VERSION 5.8 ;
BUSBITCHARS "[]" ;
DIVIDERCHAR "/" ;
UNITS
    DATABASE MICRONS 1000 ;
END UNITS

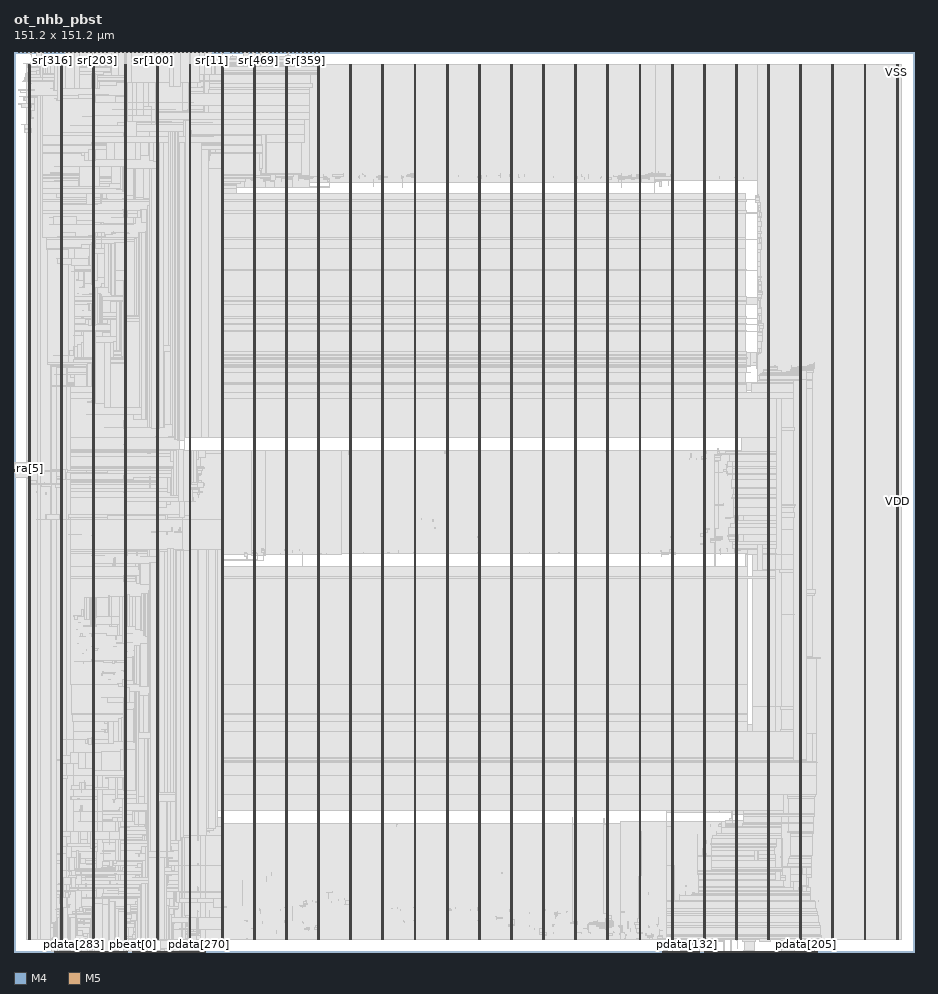
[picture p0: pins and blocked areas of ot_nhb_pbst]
MACRO ot_nhb_pbst
  FOREIGN ot_nhb_pbst 0 0 ;
  CLASS BLOCK ;
  SIZE 151.2 BY 151.2 ;
  PIN clk
    DIRECTION INPUT ;
    USE SIGNAL ;
    PORT
      LAYER M4 ;
        RECT  0 80.592 0.084 80.616 ;
    END
  END clk
  PIN pbeat[0]
    DIRECTION INPUT ;
    USE SIGNAL ;
    PORT
      LAYER M5 ;
        RECT  19.92 0 19.944 0.084 ;
    END
  END pbeat[0]
  PIN pbeat[1]
    DIRECTION INPUT ;
    USE SIGNAL ;
    PORT
      LAYER M5 ;
        RECT  20.016 0 20.04 0.084 ;
    END
  END pbeat[1]
  PIN pbeat[2]
    DIRECTION INPUT ;
    USE SIGNAL ;
    PORT
      LAYER M5 ;
        RECT  20.112 0 20.136 0.084 ;
    END
  END pbeat[2]
  PIN pbeat[3]
    DIRECTION INPUT ;
    USE SIGNAL ;
    PORT
      LAYER M5 ;
        RECT  20.208 0 20.232 0.084 ;
    END
  END pbeat[3]
  PIN pbeat[4]
    DIRECTION INPUT ;
    USE SIGNAL ;
    PORT
      LAYER M5 ;
        RECT  20.304 0 20.328 0.084 ;
    END
  END pbeat[4]
  PIN pbeat[5]
    DIRECTION INPUT ;
    USE SIGNAL ;
    PORT
      LAYER M5 ;
        RECT  20.4 0 20.424 0.084 ;
    END
  END pbeat[5]
  PIN pdata[0]
    DIRECTION INPUT ;
    USE SIGNAL ;
    PORT
      LAYER M5 ;
        RECT  20.496 0 20.52 0.084 ;
    END
  END pdata[0]
  PIN pdata[100]
    DIRECTION INPUT ;
    USE SIGNAL ;
    PORT
      LAYER M5 ;
        RECT  23.952 0 23.976 0.084 ;
    END
  END pdata[100]
  PIN pdata[101]
    DIRECTION INPUT ;
    USE SIGNAL ;
    PORT
      LAYER M5 ;
        RECT  24.048 0 24.072 0.084 ;
    END
  END pdata[101]
  PIN pdata[102]
    DIRECTION INPUT ;
    USE SIGNAL ;
    PORT
      LAYER M5 ;
        RECT  24.144 0 24.168 0.084 ;
    END
  END pdata[102]
  PIN pdata[103]
    DIRECTION INPUT ;
    USE SIGNAL ;
    PORT
      LAYER M5 ;
        RECT  24.24 0 24.264 0.084 ;
    END
  END pdata[103]
  PIN pdata[104]
    DIRECTION INPUT ;
    USE SIGNAL ;
    PORT
      LAYER M5 ;
        RECT  24.336 0 24.36 0.084 ;
    END
  END pdata[104]
  PIN pdata[105]
    DIRECTION INPUT ;
    USE SIGNAL ;
    PORT
      LAYER M5 ;
        RECT  24.432 0 24.456 0.084 ;
    END
  END pdata[105]
  PIN pdata[106]
    DIRECTION INPUT ;
    USE SIGNAL ;
    PORT
      LAYER M5 ;
        RECT  24.528 0 24.552 0.084 ;
    END
  END pdata[106]
  PIN pdata[107]
    DIRECTION INPUT ;
    USE SIGNAL ;
    PORT
      LAYER M5 ;
        RECT  24.624 0 24.648 0.084 ;
    END
  END pdata[107]
  PIN pdata[108]
    DIRECTION INPUT ;
    USE SIGNAL ;
    PORT
      LAYER M5 ;
        RECT  24.72 0 24.744 0.084 ;
    END
  END pdata[108]
  PIN pdata[109]
    DIRECTION INPUT ;
    USE SIGNAL ;
    PORT
      LAYER M5 ;
        RECT  24.816 0 24.84 0.084 ;
    END
  END pdata[109]
  PIN pdata[10]
    DIRECTION INPUT ;
    USE SIGNAL ;
    PORT
      LAYER M5 ;
        RECT  21.456 0 21.48 0.084 ;
    END
  END pdata[10]
  PIN pdata[110]
    DIRECTION INPUT ;
    USE SIGNAL ;
    PORT
      LAYER M5 ;
        RECT  24.912 0 24.936 0.084 ;
    END
  END pdata[110]
  PIN pdata[111]
    DIRECTION INPUT ;
    USE SIGNAL ;
    PORT
      LAYER M5 ;
        RECT  25.008 0 25.032 0.084 ;
    END
  END pdata[111]
  PIN pdata[112]
    DIRECTION INPUT ;
    USE SIGNAL ;
    PORT
      LAYER M5 ;
        RECT  25.104 0 25.128 0.084 ;
    END
  END pdata[112]
  PIN pdata[113]
    DIRECTION INPUT ;
    USE SIGNAL ;
    PORT
      LAYER M5 ;
        RECT  25.2 0 25.224 0.084 ;
    END
  END pdata[113]
  PIN pdata[114]
    DIRECTION INPUT ;
    USE SIGNAL ;
    PORT
      LAYER M5 ;
        RECT  25.296 0 25.32 0.084 ;
    END
  END pdata[114]
  PIN pdata[115]
    DIRECTION INPUT ;
    USE SIGNAL ;
    PORT
      LAYER M5 ;
        RECT  25.392 0 25.416 0.084 ;
    END
  END pdata[115]
  PIN pdata[116]
    DIRECTION INPUT ;
    USE SIGNAL ;
    PORT
      LAYER M5 ;
        RECT  25.488 0 25.512 0.084 ;
    END
  END pdata[116]
  PIN pdata[117]
    DIRECTION INPUT ;
    USE SIGNAL ;
    PORT
      LAYER M5 ;
        RECT  25.584 0 25.608 0.084 ;
    END
  END pdata[117]
  PIN pdata[118]
    DIRECTION INPUT ;
    USE SIGNAL ;
    PORT
      LAYER M5 ;
        RECT  25.68 0 25.704 0.084 ;
    END
  END pdata[118]
  PIN pdata[119]
    DIRECTION INPUT ;
    USE SIGNAL ;
    PORT
      LAYER M5 ;
        RECT  25.776 0 25.8 0.084 ;
    END
  END pdata[119]
  PIN pdata[11]
    DIRECTION INPUT ;
    USE SIGNAL ;
    PORT
      LAYER M5 ;
        RECT  21.552 0 21.576 0.084 ;
    END
  END pdata[11]
  PIN pdata[120]
    DIRECTION INPUT ;
    USE SIGNAL ;
    PORT
      LAYER M5 ;
        RECT  25.872 0 25.896 0.084 ;
    END
  END pdata[120]
  PIN pdata[121]
    DIRECTION INPUT ;
    USE SIGNAL ;
    PORT
      LAYER M5 ;
        RECT  25.968 0 25.992 0.084 ;
    END
  END pdata[121]
  PIN pdata[122]
    DIRECTION INPUT ;
    USE SIGNAL ;
    PORT
      LAYER M5 ;
        RECT  112.08 0 112.104 0.084 ;
    END
  END pdata[122]
  PIN pdata[123]
    DIRECTION INPUT ;
    USE SIGNAL ;
    PORT
      LAYER M5 ;
        RECT  112.176 0 112.2 0.084 ;
    END
  END pdata[123]
  PIN pdata[124]
    DIRECTION INPUT ;
    USE SIGNAL ;
    PORT
      LAYER M5 ;
        RECT  112.272 0 112.296 0.084 ;
    END
  END pdata[124]
  PIN pdata[125]
    DIRECTION INPUT ;
    USE SIGNAL ;
    PORT
      LAYER M5 ;
        RECT  112.368 0 112.392 0.084 ;
    END
  END pdata[125]
  PIN pdata[126]
    DIRECTION INPUT ;
    USE SIGNAL ;
    PORT
      LAYER M5 ;
        RECT  112.464 0 112.488 0.084 ;
    END
  END pdata[126]
  PIN pdata[127]
    DIRECTION INPUT ;
    USE SIGNAL ;
    PORT
      LAYER M5 ;
        RECT  112.56 0 112.584 0.084 ;
    END
  END pdata[127]
  PIN pdata[128]
    DIRECTION INPUT ;
    USE SIGNAL ;
    PORT
      LAYER M5 ;
        RECT  112.656 0 112.68 0.084 ;
    END
  END pdata[128]
  PIN pdata[129]
    DIRECTION INPUT ;
    USE SIGNAL ;
    PORT
      LAYER M5 ;
        RECT  112.752 0 112.776 0.084 ;
    END
  END pdata[129]
  PIN pdata[12]
    DIRECTION INPUT ;
    USE SIGNAL ;
    PORT
      LAYER M5 ;
        RECT  21.648 0 21.672 0.084 ;
    END
  END pdata[12]
  PIN pdata[130]
    DIRECTION INPUT ;
    USE SIGNAL ;
    PORT
      LAYER M5 ;
        RECT  112.848 0 112.872 0.084 ;
    END
  END pdata[130]
  PIN pdata[131]
    DIRECTION INPUT ;
    USE SIGNAL ;
    PORT
      LAYER M5 ;
        RECT  112.944 0 112.968 0.084 ;
    END
  END pdata[131]
  PIN pdata[132]
    DIRECTION INPUT ;
    USE SIGNAL ;
    PORT
      LAYER M5 ;
        RECT  113.04 0 113.064 0.084 ;
    END
  END pdata[132]
  PIN pdata[133]
    DIRECTION INPUT ;
    USE SIGNAL ;
    PORT
      LAYER M5 ;
        RECT  113.136 0 113.16 0.084 ;
    END
  END pdata[133]
  PIN pdata[134]
    DIRECTION INPUT ;
    USE SIGNAL ;
    PORT
      LAYER M5 ;
        RECT  113.232 0 113.256 0.084 ;
    END
  END pdata[134]
  PIN pdata[135]
    DIRECTION INPUT ;
    USE SIGNAL ;
    PORT
      LAYER M5 ;
        RECT  113.328 0 113.352 0.084 ;
    END
  END pdata[135]
  PIN pdata[136]
    DIRECTION INPUT ;
    USE SIGNAL ;
    PORT
      LAYER M5 ;
        RECT  113.424 0 113.448 0.084 ;
    END
  END pdata[136]
  PIN pdata[137]
    DIRECTION INPUT ;
    USE SIGNAL ;
    PORT
      LAYER M5 ;
        RECT  113.52 0 113.544 0.084 ;
    END
  END pdata[137]
  PIN pdata[138]
    DIRECTION INPUT ;
    USE SIGNAL ;
    PORT
      LAYER M5 ;
        RECT  113.616 0 113.64 0.084 ;
    END
  END pdata[138]
  PIN pdata[139]
    DIRECTION INPUT ;
    USE SIGNAL ;
    PORT
      LAYER M5 ;
        RECT  113.712 0 113.736 0.084 ;
    END
  END pdata[139]
  PIN pdata[13]
    DIRECTION INPUT ;
    USE SIGNAL ;
    PORT
      LAYER M5 ;
        RECT  21.744 0 21.768 0.084 ;
    END
  END pdata[13]
  PIN pdata[140]
    DIRECTION INPUT ;
    USE SIGNAL ;
    PORT
      LAYER M5 ;
        RECT  113.808 0 113.832 0.084 ;
    END
  END pdata[140]
  PIN pdata[141]
    DIRECTION INPUT ;
    USE SIGNAL ;
    PORT
      LAYER M5 ;
        RECT  113.904 0 113.928 0.084 ;
    END
  END pdata[141]
  PIN pdata[142]
    DIRECTION INPUT ;
    USE SIGNAL ;
    PORT
      LAYER M5 ;
        RECT  114 0 114.024 0.084 ;
    END
  END pdata[142]
  PIN pdata[143]
    DIRECTION INPUT ;
    USE SIGNAL ;
    PORT
      LAYER M5 ;
        RECT  114.096 0 114.12 0.084 ;
    END
  END pdata[143]
  PIN pdata[144]
    DIRECTION INPUT ;
    USE SIGNAL ;
    PORT
      LAYER M5 ;
        RECT  114.192 0 114.216 0.084 ;
    END
  END pdata[144]
  PIN pdata[145]
    DIRECTION INPUT ;
    USE SIGNAL ;
    PORT
      LAYER M5 ;
        RECT  114.288 0 114.312 0.084 ;
    END
  END pdata[145]
  PIN pdata[146]
    DIRECTION INPUT ;
    USE SIGNAL ;
    PORT
      LAYER M5 ;
        RECT  114.384 0 114.408 0.084 ;
    END
  END pdata[146]
  PIN pdata[147]
    DIRECTION INPUT ;
    USE SIGNAL ;
    PORT
      LAYER M5 ;
        RECT  114.48 0 114.504 0.084 ;
    END
  END pdata[147]
  PIN pdata[148]
    DIRECTION INPUT ;
    USE SIGNAL ;
    PORT
      LAYER M5 ;
        RECT  114.576 0 114.6 0.084 ;
    END
  END pdata[148]
  PIN pdata[149]
    DIRECTION INPUT ;
    USE SIGNAL ;
    PORT
      LAYER M5 ;
        RECT  114.672 0 114.696 0.084 ;
    END
  END pdata[149]
  PIN pdata[14]
    DIRECTION INPUT ;
    USE SIGNAL ;
    PORT
      LAYER M5 ;
        RECT  21.84 0 21.864 0.084 ;
    END
  END pdata[14]
  PIN pdata[150]
    DIRECTION INPUT ;
    USE SIGNAL ;
    PORT
      LAYER M5 ;
        RECT  114.768 0 114.792 0.084 ;
    END
  END pdata[150]
  PIN pdata[151]
    DIRECTION INPUT ;
    USE SIGNAL ;
    PORT
      LAYER M5 ;
        RECT  114.864 0 114.888 0.084 ;
    END
  END pdata[151]
  PIN pdata[152]
    DIRECTION INPUT ;
    USE SIGNAL ;
    PORT
      LAYER M5 ;
        RECT  114.96 0 114.984 0.084 ;
    END
  END pdata[152]
  PIN pdata[153]
    DIRECTION INPUT ;
    USE SIGNAL ;
    PORT
      LAYER M5 ;
        RECT  115.056 0 115.08 0.084 ;
    END
  END pdata[153]
  PIN pdata[154]
    DIRECTION INPUT ;
    USE SIGNAL ;
    PORT
      LAYER M5 ;
        RECT  118.992 0 119.016 0.084 ;
    END
  END pdata[154]
  PIN pdata[155]
    DIRECTION INPUT ;
    USE SIGNAL ;
    PORT
      LAYER M5 ;
        RECT  119.088 0 119.112 0.084 ;
    END
  END pdata[155]
  PIN pdata[156]
    DIRECTION INPUT ;
    USE SIGNAL ;
    PORT
      LAYER M5 ;
        RECT  119.184 0 119.208 0.084 ;
    END
  END pdata[156]
  PIN pdata[157]
    DIRECTION INPUT ;
    USE SIGNAL ;
    PORT
      LAYER M5 ;
        RECT  119.28 0 119.304 0.084 ;
    END
  END pdata[157]
  PIN pdata[158]
    DIRECTION INPUT ;
    USE SIGNAL ;
    PORT
      LAYER M5 ;
        RECT  119.376 0 119.4 0.084 ;
    END
  END pdata[158]
  PIN pdata[159]
    DIRECTION INPUT ;
    USE SIGNAL ;
    PORT
      LAYER M5 ;
        RECT  119.472 0 119.496 0.084 ;
    END
  END pdata[159]
  PIN pdata[15]
    DIRECTION INPUT ;
    USE SIGNAL ;
    PORT
      LAYER M5 ;
        RECT  21.936 0 21.96 0.084 ;
    END
  END pdata[15]
  PIN pdata[160]
    DIRECTION INPUT ;
    USE SIGNAL ;
    PORT
      LAYER M5 ;
        RECT  119.568 0 119.592 0.084 ;
    END
  END pdata[160]
  PIN pdata[161]
    DIRECTION INPUT ;
    USE SIGNAL ;
    PORT
      LAYER M5 ;
        RECT  119.664 0 119.688 0.084 ;
    END
  END pdata[161]
  PIN pdata[162]
    DIRECTION INPUT ;
    USE SIGNAL ;
    PORT
      LAYER M5 ;
        RECT  119.76 0 119.784 0.084 ;
    END
  END pdata[162]
  PIN pdata[163]
    DIRECTION INPUT ;
    USE SIGNAL ;
    PORT
      LAYER M5 ;
        RECT  119.856 0 119.88 0.084 ;
    END
  END pdata[163]
  PIN pdata[164]
    DIRECTION INPUT ;
    USE SIGNAL ;
    PORT
      LAYER M5 ;
        RECT  119.952 0 119.976 0.084 ;
    END
  END pdata[164]
  PIN pdata[165]
    DIRECTION INPUT ;
    USE SIGNAL ;
    PORT
      LAYER M5 ;
        RECT  120.048 0 120.072 0.084 ;
    END
  END pdata[165]
  PIN pdata[166]
    DIRECTION INPUT ;
    USE SIGNAL ;
    PORT
      LAYER M5 ;
        RECT  120.144 0 120.168 0.084 ;
    END
  END pdata[166]
  PIN pdata[167]
    DIRECTION INPUT ;
    USE SIGNAL ;
    PORT
      LAYER M5 ;
        RECT  120.24 0 120.264 0.084 ;
    END
  END pdata[167]
  PIN pdata[168]
    DIRECTION INPUT ;
    USE SIGNAL ;
    PORT
      LAYER M5 ;
        RECT  120.336 0 120.36 0.084 ;
    END
  END pdata[168]
  PIN pdata[169]
    DIRECTION INPUT ;
    USE SIGNAL ;
    PORT
      LAYER M5 ;
        RECT  120.432 0 120.456 0.084 ;
    END
  END pdata[169]
  PIN pdata[16]
    DIRECTION INPUT ;
    USE SIGNAL ;
    PORT
      LAYER M5 ;
        RECT  22.032 0 22.056 0.084 ;
    END
  END pdata[16]
  PIN pdata[170]
    DIRECTION INPUT ;
    USE SIGNAL ;
    PORT
      LAYER M5 ;
        RECT  120.528 0 120.552 0.084 ;
    END
  END pdata[170]
  PIN pdata[171]
    DIRECTION INPUT ;
    USE SIGNAL ;
    PORT
      LAYER M5 ;
        RECT  120.624 0 120.648 0.084 ;
    END
  END pdata[171]
  PIN pdata[172]
    DIRECTION INPUT ;
    USE SIGNAL ;
    PORT
      LAYER M5 ;
        RECT  120.72 0 120.744 0.084 ;
    END
  END pdata[172]
  PIN pdata[173]
    DIRECTION INPUT ;
    USE SIGNAL ;
    PORT
      LAYER M5 ;
        RECT  120.816 0 120.84 0.084 ;
    END
  END pdata[173]
  PIN pdata[174]
    DIRECTION INPUT ;
    USE SIGNAL ;
    PORT
      LAYER M5 ;
        RECT  120.912 0 120.936 0.084 ;
    END
  END pdata[174]
  PIN pdata[175]
    DIRECTION INPUT ;
    USE SIGNAL ;
    PORT
      LAYER M5 ;
        RECT  121.008 0 121.032 0.084 ;
    END
  END pdata[175]
  PIN pdata[176]
    DIRECTION INPUT ;
    USE SIGNAL ;
    PORT
      LAYER M5 ;
        RECT  121.104 0 121.128 0.084 ;
    END
  END pdata[176]
  PIN pdata[177]
    DIRECTION INPUT ;
    USE SIGNAL ;
    PORT
      LAYER M5 ;
        RECT  121.2 0 121.224 0.084 ;
    END
  END pdata[177]
  PIN pdata[178]
    DIRECTION INPUT ;
    USE SIGNAL ;
    PORT
      LAYER M5 ;
        RECT  121.296 0 121.32 0.084 ;
    END
  END pdata[178]
  PIN pdata[179]
    DIRECTION INPUT ;
    USE SIGNAL ;
    PORT
      LAYER M5 ;
        RECT  121.392 0 121.416 0.084 ;
    END
  END pdata[179]
  PIN pdata[17]
    DIRECTION INPUT ;
    USE SIGNAL ;
    PORT
      LAYER M5 ;
        RECT  22.128 0 22.152 0.084 ;
    END
  END pdata[17]
  PIN pdata[180]
    DIRECTION INPUT ;
    USE SIGNAL ;
    PORT
      LAYER M5 ;
        RECT  121.488 0 121.512 0.084 ;
    END
  END pdata[180]
  PIN pdata[181]
    DIRECTION INPUT ;
    USE SIGNAL ;
    PORT
      LAYER M5 ;
        RECT  121.584 0 121.608 0.084 ;
    END
  END pdata[181]
  PIN pdata[182]
    DIRECTION INPUT ;
    USE SIGNAL ;
    PORT
      LAYER M5 ;
        RECT  121.68 0 121.704 0.084 ;
    END
  END pdata[182]
  PIN pdata[183]
    DIRECTION INPUT ;
    USE SIGNAL ;
    PORT
      LAYER M5 ;
        RECT  121.776 0 121.8 0.084 ;
    END
  END pdata[183]
  PIN pdata[184]
    DIRECTION INPUT ;
    USE SIGNAL ;
    PORT
      LAYER M5 ;
        RECT  121.872 0 121.896 0.084 ;
    END
  END pdata[184]
  PIN pdata[185]
    DIRECTION INPUT ;
    USE SIGNAL ;
    PORT
      LAYER M5 ;
        RECT  121.968 0 121.992 0.084 ;
    END
  END pdata[185]
  PIN pdata[186]
    DIRECTION INPUT ;
    USE SIGNAL ;
    PORT
      LAYER M5 ;
        RECT  131.28 0 131.304 0.084 ;
    END
  END pdata[186]
  PIN pdata[187]
    DIRECTION INPUT ;
    USE SIGNAL ;
    PORT
      LAYER M5 ;
        RECT  131.376 0 131.4 0.084 ;
    END
  END pdata[187]
  PIN pdata[188]
    DIRECTION INPUT ;
    USE SIGNAL ;
    PORT
      LAYER M5 ;
        RECT  131.472 0 131.496 0.084 ;
    END
  END pdata[188]
  PIN pdata[189]
    DIRECTION INPUT ;
    USE SIGNAL ;
    PORT
      LAYER M5 ;
        RECT  131.568 0 131.592 0.084 ;
    END
  END pdata[189]
  PIN pdata[18]
    DIRECTION INPUT ;
    USE SIGNAL ;
    PORT
      LAYER M5 ;
        RECT  22.224 0 22.248 0.084 ;
    END
  END pdata[18]
  PIN pdata[190]
    DIRECTION INPUT ;
    USE SIGNAL ;
    PORT
      LAYER M5 ;
        RECT  131.664 0 131.688 0.084 ;
    END
  END pdata[190]
  PIN pdata[191]
    DIRECTION INPUT ;
    USE SIGNAL ;
    PORT
      LAYER M5 ;
        RECT  131.76 0 131.784 0.084 ;
    END
  END pdata[191]
  PIN pdata[192]
    DIRECTION INPUT ;
    USE SIGNAL ;
    PORT
      LAYER M5 ;
        RECT  131.856 0 131.88 0.084 ;
    END
  END pdata[192]
  PIN pdata[193]
    DIRECTION INPUT ;
    USE SIGNAL ;
    PORT
      LAYER M5 ;
        RECT  131.952 0 131.976 0.084 ;
    END
  END pdata[193]
  PIN pdata[194]
    DIRECTION INPUT ;
    USE SIGNAL ;
    PORT
      LAYER M5 ;
        RECT  132.048 0 132.072 0.084 ;
    END
  END pdata[194]
  PIN pdata[195]
    DIRECTION INPUT ;
    USE SIGNAL ;
    PORT
      LAYER M5 ;
        RECT  132.144 0 132.168 0.084 ;
    END
  END pdata[195]
  PIN pdata[196]
    DIRECTION INPUT ;
    USE SIGNAL ;
    PORT
      LAYER M5 ;
        RECT  132.24 0 132.264 0.084 ;
    END
  END pdata[196]
  PIN pdata[197]
    DIRECTION INPUT ;
    USE SIGNAL ;
    PORT
      LAYER M5 ;
        RECT  132.336 0 132.36 0.084 ;
    END
  END pdata[197]
  PIN pdata[198]
    DIRECTION INPUT ;
    USE SIGNAL ;
    PORT
      LAYER M5 ;
        RECT  132.432 0 132.456 0.084 ;
    END
  END pdata[198]
  PIN pdata[199]
    DIRECTION INPUT ;
    USE SIGNAL ;
    PORT
      LAYER M5 ;
        RECT  132.528 0 132.552 0.084 ;
    END
  END pdata[199]
  PIN pdata[19]
    DIRECTION INPUT ;
    USE SIGNAL ;
    PORT
      LAYER M5 ;
        RECT  22.32 0 22.344 0.084 ;
    END
  END pdata[19]
  PIN pdata[1]
    DIRECTION INPUT ;
    USE SIGNAL ;
    PORT
      LAYER M5 ;
        RECT  20.592 0 20.616 0.084 ;
    END
  END pdata[1]
  PIN pdata[200]
    DIRECTION INPUT ;
    USE SIGNAL ;
    PORT
      LAYER M5 ;
        RECT  132.624 0 132.648 0.084 ;
    END
  END pdata[200]
  PIN pdata[201]
    DIRECTION INPUT ;
    USE SIGNAL ;
    PORT
      LAYER M5 ;
        RECT  132.72 0 132.744 0.084 ;
    END
  END pdata[201]
  PIN pdata[202]
    DIRECTION INPUT ;
    USE SIGNAL ;
    PORT
      LAYER M5 ;
        RECT  132.816 0 132.84 0.084 ;
    END
  END pdata[202]
  PIN pdata[203]
    DIRECTION INPUT ;
    USE SIGNAL ;
    PORT
      LAYER M5 ;
        RECT  132.912 0 132.936 0.084 ;
    END
  END pdata[203]
  PIN pdata[204]
    DIRECTION INPUT ;
    USE SIGNAL ;
    PORT
      LAYER M5 ;
        RECT  133.008 0 133.032 0.084 ;
    END
  END pdata[204]
  PIN pdata[205]
    DIRECTION INPUT ;
    USE SIGNAL ;
    PORT
      LAYER M5 ;
        RECT  133.104 0 133.128 0.084 ;
    END
  END pdata[205]
  PIN pdata[206]
    DIRECTION INPUT ;
    USE SIGNAL ;
    PORT
      LAYER M5 ;
        RECT  133.2 0 133.224 0.084 ;
    END
  END pdata[206]
  PIN pdata[207]
    DIRECTION INPUT ;
    USE SIGNAL ;
    PORT
      LAYER M5 ;
        RECT  133.296 0 133.32 0.084 ;
    END
  END pdata[207]
  PIN pdata[208]
    DIRECTION INPUT ;
    USE SIGNAL ;
    PORT
      LAYER M5 ;
        RECT  133.392 0 133.416 0.084 ;
    END
  END pdata[208]
  PIN pdata[209]
    DIRECTION INPUT ;
    USE SIGNAL ;
    PORT
      LAYER M5 ;
        RECT  133.488 0 133.512 0.084 ;
    END
  END pdata[209]
  PIN pdata[20]
    DIRECTION INPUT ;
    USE SIGNAL ;
    PORT
      LAYER M5 ;
        RECT  22.416 0 22.44 0.084 ;
    END
  END pdata[20]
  PIN pdata[210]
    DIRECTION INPUT ;
    USE SIGNAL ;
    PORT
      LAYER M5 ;
        RECT  133.584 0 133.608 0.084 ;
    END
  END pdata[210]
  PIN pdata[211]
    DIRECTION INPUT ;
    USE SIGNAL ;
    PORT
      LAYER M5 ;
        RECT  133.68 0 133.704 0.084 ;
    END
  END pdata[211]
  PIN pdata[212]
    DIRECTION INPUT ;
    USE SIGNAL ;
    PORT
      LAYER M5 ;
        RECT  133.776 0 133.8 0.084 ;
    END
  END pdata[212]
  PIN pdata[213]
    DIRECTION INPUT ;
    USE SIGNAL ;
    PORT
      LAYER M5 ;
        RECT  133.872 0 133.896 0.084 ;
    END
  END pdata[213]
  PIN pdata[214]
    DIRECTION INPUT ;
    USE SIGNAL ;
    PORT
      LAYER M5 ;
        RECT  133.968 0 133.992 0.084 ;
    END
  END pdata[214]
  PIN pdata[215]
    DIRECTION INPUT ;
    USE SIGNAL ;
    PORT
      LAYER M5 ;
        RECT  134.064 0 134.088 0.084 ;
    END
  END pdata[215]
  PIN pdata[216]
    DIRECTION INPUT ;
    USE SIGNAL ;
    PORT
      LAYER M5 ;
        RECT  134.16 0 134.184 0.084 ;
    END
  END pdata[216]
  PIN pdata[217]
    DIRECTION INPUT ;
    USE SIGNAL ;
    PORT
      LAYER M5 ;
        RECT  134.256 0 134.28 0.084 ;
    END
  END pdata[217]
  PIN pdata[218]
    DIRECTION INPUT ;
    USE SIGNAL ;
    PORT
      LAYER M5 ;
        RECT  125.136 0 125.16 0.084 ;
    END
  END pdata[218]
  PIN pdata[219]
    DIRECTION INPUT ;
    USE SIGNAL ;
    PORT
      LAYER M5 ;
        RECT  125.232 0 125.256 0.084 ;
    END
  END pdata[219]
  PIN pdata[21]
    DIRECTION INPUT ;
    USE SIGNAL ;
    PORT
      LAYER M5 ;
        RECT  22.512 0 22.536 0.084 ;
    END
  END pdata[21]
  PIN pdata[220]
    DIRECTION INPUT ;
    USE SIGNAL ;
    PORT
      LAYER M5 ;
        RECT  125.328 0 125.352 0.084 ;
    END
  END pdata[220]
  PIN pdata[221]
    DIRECTION INPUT ;
    USE SIGNAL ;
    PORT
      LAYER M5 ;
        RECT  125.424 0 125.448 0.084 ;
    END
  END pdata[221]
  PIN pdata[222]
    DIRECTION INPUT ;
    USE SIGNAL ;
    PORT
      LAYER M5 ;
        RECT  125.52 0 125.544 0.084 ;
    END
  END pdata[222]
  PIN pdata[223]
    DIRECTION INPUT ;
    USE SIGNAL ;
    PORT
      LAYER M5 ;
        RECT  125.616 0 125.64 0.084 ;
    END
  END pdata[223]
  PIN pdata[224]
    DIRECTION INPUT ;
    USE SIGNAL ;
    PORT
      LAYER M5 ;
        RECT  125.712 0 125.736 0.084 ;
    END
  END pdata[224]
  PIN pdata[225]
    DIRECTION INPUT ;
    USE SIGNAL ;
    PORT
      LAYER M5 ;
        RECT  125.808 0 125.832 0.084 ;
    END
  END pdata[225]
  PIN pdata[226]
    DIRECTION INPUT ;
    USE SIGNAL ;
    PORT
      LAYER M5 ;
        RECT  125.904 0 125.928 0.084 ;
    END
  END pdata[226]
  PIN pdata[227]
    DIRECTION INPUT ;
    USE SIGNAL ;
    PORT
      LAYER M5 ;
        RECT  126 0 126.024 0.084 ;
    END
  END pdata[227]
  PIN pdata[228]
    DIRECTION INPUT ;
    USE SIGNAL ;
    PORT
      LAYER M5 ;
        RECT  126.096 0 126.12 0.084 ;
    END
  END pdata[228]
  PIN pdata[229]
    DIRECTION INPUT ;
    USE SIGNAL ;
    PORT
      LAYER M5 ;
        RECT  126.192 0 126.216 0.084 ;
    END
  END pdata[229]
  PIN pdata[22]
    DIRECTION INPUT ;
    USE SIGNAL ;
    PORT
      LAYER M5 ;
        RECT  22.608 0 22.632 0.084 ;
    END
  END pdata[22]
  PIN pdata[230]
    DIRECTION INPUT ;
    USE SIGNAL ;
    PORT
      LAYER M5 ;
        RECT  126.288 0 126.312 0.084 ;
    END
  END pdata[230]
  PIN pdata[231]
    DIRECTION INPUT ;
    USE SIGNAL ;
    PORT
      LAYER M5 ;
        RECT  126.384 0 126.408 0.084 ;
    END
  END pdata[231]
  PIN pdata[232]
    DIRECTION INPUT ;
    USE SIGNAL ;
    PORT
      LAYER M5 ;
        RECT  126.48 0 126.504 0.084 ;
    END
  END pdata[232]
  PIN pdata[233]
    DIRECTION INPUT ;
    USE SIGNAL ;
    PORT
      LAYER M5 ;
        RECT  126.576 0 126.6 0.084 ;
    END
  END pdata[233]
  PIN pdata[234]
    DIRECTION INPUT ;
    USE SIGNAL ;
    PORT
      LAYER M5 ;
        RECT  126.672 0 126.696 0.084 ;
    END
  END pdata[234]
  PIN pdata[235]
    DIRECTION INPUT ;
    USE SIGNAL ;
    PORT
      LAYER M5 ;
        RECT  126.768 0 126.792 0.084 ;
    END
  END pdata[235]
  PIN pdata[236]
    DIRECTION INPUT ;
    USE SIGNAL ;
    PORT
      LAYER M5 ;
        RECT  126.864 0 126.888 0.084 ;
    END
  END pdata[236]
  PIN pdata[237]
    DIRECTION INPUT ;
    USE SIGNAL ;
    PORT
      LAYER M5 ;
        RECT  126.96 0 126.984 0.084 ;
    END
  END pdata[237]
  PIN pdata[238]
    DIRECTION INPUT ;
    USE SIGNAL ;
    PORT
      LAYER M5 ;
        RECT  127.056 0 127.08 0.084 ;
    END
  END pdata[238]
  PIN pdata[239]
    DIRECTION INPUT ;
    USE SIGNAL ;
    PORT
      LAYER M5 ;
        RECT  127.152 0 127.176 0.084 ;
    END
  END pdata[239]
  PIN pdata[23]
    DIRECTION INPUT ;
    USE SIGNAL ;
    PORT
      LAYER M5 ;
        RECT  22.704 0 22.728 0.084 ;
    END
  END pdata[23]
  PIN pdata[240]
    DIRECTION INPUT ;
    USE SIGNAL ;
    PORT
      LAYER M5 ;
        RECT  127.248 0 127.272 0.084 ;
    END
  END pdata[240]
  PIN pdata[241]
    DIRECTION INPUT ;
    USE SIGNAL ;
    PORT
      LAYER M5 ;
        RECT  127.344 0 127.368 0.084 ;
    END
  END pdata[241]
  PIN pdata[242]
    DIRECTION INPUT ;
    USE SIGNAL ;
    PORT
      LAYER M5 ;
        RECT  127.44 0 127.464 0.084 ;
    END
  END pdata[242]
  PIN pdata[243]
    DIRECTION INPUT ;
    USE SIGNAL ;
    PORT
      LAYER M5 ;
        RECT  127.536 0 127.56 0.084 ;
    END
  END pdata[243]
  PIN pdata[244]
    DIRECTION INPUT ;
    USE SIGNAL ;
    PORT
      LAYER M5 ;
        RECT  127.632 0 127.656 0.084 ;
    END
  END pdata[244]
  PIN pdata[245]
    DIRECTION INPUT ;
    USE SIGNAL ;
    PORT
      LAYER M5 ;
        RECT  127.728 0 127.752 0.084 ;
    END
  END pdata[245]
  PIN pdata[246]
    DIRECTION INPUT ;
    USE SIGNAL ;
    PORT
      LAYER M5 ;
        RECT  127.824 0 127.848 0.084 ;
    END
  END pdata[246]
  PIN pdata[247]
    DIRECTION INPUT ;
    USE SIGNAL ;
    PORT
      LAYER M5 ;
        RECT  127.92 0 127.944 0.084 ;
    END
  END pdata[247]
  PIN pdata[248]
    DIRECTION INPUT ;
    USE SIGNAL ;
    PORT
      LAYER M5 ;
        RECT  128.016 0 128.04 0.084 ;
    END
  END pdata[248]
  PIN pdata[249]
    DIRECTION INPUT ;
    USE SIGNAL ;
    PORT
      LAYER M5 ;
        RECT  128.112 0 128.136 0.084 ;
    END
  END pdata[249]
  PIN pdata[24]
    DIRECTION INPUT ;
    USE SIGNAL ;
    PORT
      LAYER M5 ;
        RECT  22.8 0 22.824 0.084 ;
    END
  END pdata[24]
  PIN pdata[250]
    DIRECTION INPUT ;
    USE SIGNAL ;
    PORT
      LAYER M5 ;
        RECT  29.136 0 29.16 0.084 ;
    END
  END pdata[250]
  PIN pdata[251]
    DIRECTION INPUT ;
    USE SIGNAL ;
    PORT
      LAYER M5 ;
        RECT  29.232 0 29.256 0.084 ;
    END
  END pdata[251]
  PIN pdata[252]
    DIRECTION INPUT ;
    USE SIGNAL ;
    PORT
      LAYER M5 ;
        RECT  29.328 0 29.352 0.084 ;
    END
  END pdata[252]
  PIN pdata[253]
    DIRECTION INPUT ;
    USE SIGNAL ;
    PORT
      LAYER M5 ;
        RECT  29.424 0 29.448 0.084 ;
    END
  END pdata[253]
  PIN pdata[254]
    DIRECTION INPUT ;
    USE SIGNAL ;
    PORT
      LAYER M5 ;
        RECT  29.52 0 29.544 0.084 ;
    END
  END pdata[254]
  PIN pdata[255]
    DIRECTION INPUT ;
    USE SIGNAL ;
    PORT
      LAYER M5 ;
        RECT  29.616 0 29.64 0.084 ;
    END
  END pdata[255]
  PIN pdata[256]
    DIRECTION INPUT ;
    USE SIGNAL ;
    PORT
      LAYER M5 ;
        RECT  29.712 0 29.736 0.084 ;
    END
  END pdata[256]
  PIN pdata[257]
    DIRECTION INPUT ;
    USE SIGNAL ;
    PORT
      LAYER M5 ;
        RECT  29.808 0 29.832 0.084 ;
    END
  END pdata[257]
  PIN pdata[258]
    DIRECTION INPUT ;
    USE SIGNAL ;
    PORT
      LAYER M5 ;
        RECT  29.904 0 29.928 0.084 ;
    END
  END pdata[258]
  PIN pdata[259]
    DIRECTION INPUT ;
    USE SIGNAL ;
    PORT
      LAYER M5 ;
        RECT  30 0 30.024 0.084 ;
    END
  END pdata[259]
  PIN pdata[25]
    DIRECTION INPUT ;
    USE SIGNAL ;
    PORT
      LAYER M5 ;
        RECT  22.896 0 22.92 0.084 ;
    END
  END pdata[25]
  PIN pdata[260]
    DIRECTION INPUT ;
    USE SIGNAL ;
    PORT
      LAYER M5 ;
        RECT  30.096 0 30.12 0.084 ;
    END
  END pdata[260]
  PIN pdata[261]
    DIRECTION INPUT ;
    USE SIGNAL ;
    PORT
      LAYER M5 ;
        RECT  30.192 0 30.216 0.084 ;
    END
  END pdata[261]
  PIN pdata[262]
    DIRECTION INPUT ;
    USE SIGNAL ;
    PORT
      LAYER M5 ;
        RECT  30.288 0 30.312 0.084 ;
    END
  END pdata[262]
  PIN pdata[263]
    DIRECTION INPUT ;
    USE SIGNAL ;
    PORT
      LAYER M5 ;
        RECT  30.384 0 30.408 0.084 ;
    END
  END pdata[263]
  PIN pdata[264]
    DIRECTION INPUT ;
    USE SIGNAL ;
    PORT
      LAYER M5 ;
        RECT  30.48 0 30.504 0.084 ;
    END
  END pdata[264]
  PIN pdata[265]
    DIRECTION INPUT ;
    USE SIGNAL ;
    PORT
      LAYER M5 ;
        RECT  30.576 0 30.6 0.084 ;
    END
  END pdata[265]
  PIN pdata[266]
    DIRECTION INPUT ;
    USE SIGNAL ;
    PORT
      LAYER M5 ;
        RECT  30.672 0 30.696 0.084 ;
    END
  END pdata[266]
  PIN pdata[267]
    DIRECTION INPUT ;
    USE SIGNAL ;
    PORT
      LAYER M5 ;
        RECT  30.768 0 30.792 0.084 ;
    END
  END pdata[267]
  PIN pdata[268]
    DIRECTION INPUT ;
    USE SIGNAL ;
    PORT
      LAYER M5 ;
        RECT  30.864 0 30.888 0.084 ;
    END
  END pdata[268]
  PIN pdata[269]
    DIRECTION INPUT ;
    USE SIGNAL ;
    PORT
      LAYER M5 ;
        RECT  30.96 0 30.984 0.084 ;
    END
  END pdata[269]
  PIN pdata[26]
    DIRECTION INPUT ;
    USE SIGNAL ;
    PORT
      LAYER M5 ;
        RECT  13.008 0 13.032 0.084 ;
    END
  END pdata[26]
  PIN pdata[270]
    DIRECTION INPUT ;
    USE SIGNAL ;
    PORT
      LAYER M5 ;
        RECT  31.056 0 31.08 0.084 ;
    END
  END pdata[270]
  PIN pdata[271]
    DIRECTION INPUT ;
    USE SIGNAL ;
    PORT
      LAYER M5 ;
        RECT  31.152 0 31.176 0.084 ;
    END
  END pdata[271]
  PIN pdata[272]
    DIRECTION INPUT ;
    USE SIGNAL ;
    PORT
      LAYER M5 ;
        RECT  31.248 0 31.272 0.084 ;
    END
  END pdata[272]
  PIN pdata[273]
    DIRECTION INPUT ;
    USE SIGNAL ;
    PORT
      LAYER M5 ;
        RECT  31.344 0 31.368 0.084 ;
    END
  END pdata[273]
  PIN pdata[274]
    DIRECTION INPUT ;
    USE SIGNAL ;
    PORT
      LAYER M5 ;
        RECT  31.44 0 31.464 0.084 ;
    END
  END pdata[274]
  PIN pdata[275]
    DIRECTION INPUT ;
    USE SIGNAL ;
    PORT
      LAYER M5 ;
        RECT  31.536 0 31.56 0.084 ;
    END
  END pdata[275]
  PIN pdata[276]
    DIRECTION INPUT ;
    USE SIGNAL ;
    PORT
      LAYER M5 ;
        RECT  31.632 0 31.656 0.084 ;
    END
  END pdata[276]
  PIN pdata[277]
    DIRECTION INPUT ;
    USE SIGNAL ;
    PORT
      LAYER M5 ;
        RECT  31.728 0 31.752 0.084 ;
    END
  END pdata[277]
  PIN pdata[278]
    DIRECTION INPUT ;
    USE SIGNAL ;
    PORT
      LAYER M5 ;
        RECT  31.824 0 31.848 0.084 ;
    END
  END pdata[278]
  PIN pdata[279]
    DIRECTION INPUT ;
    USE SIGNAL ;
    PORT
      LAYER M5 ;
        RECT  31.92 0 31.944 0.084 ;
    END
  END pdata[279]
  PIN pdata[27]
    DIRECTION INPUT ;
    USE SIGNAL ;
    PORT
      LAYER M5 ;
        RECT  13.104 0 13.128 0.084 ;
    END
  END pdata[27]
  PIN pdata[280]
    DIRECTION INPUT ;
    USE SIGNAL ;
    PORT
      LAYER M5 ;
        RECT  32.016 0 32.04 0.084 ;
    END
  END pdata[280]
  PIN pdata[281]
    DIRECTION INPUT ;
    USE SIGNAL ;
    PORT
      LAYER M5 ;
        RECT  32.112 0 32.136 0.084 ;
    END
  END pdata[281]
  PIN pdata[282]
    DIRECTION INPUT ;
    USE SIGNAL ;
    PORT
      LAYER M5 ;
        RECT  9.936 0 9.96 0.084 ;
    END
  END pdata[282]
  PIN pdata[283]
    DIRECTION INPUT ;
    USE SIGNAL ;
    PORT
      LAYER M5 ;
        RECT  10.032 0 10.056 0.084 ;
    END
  END pdata[283]
  PIN pdata[284]
    DIRECTION INPUT ;
    USE SIGNAL ;
    PORT
      LAYER M5 ;
        RECT  10.128 0 10.152 0.084 ;
    END
  END pdata[284]
  PIN pdata[285]
    DIRECTION INPUT ;
    USE SIGNAL ;
    PORT
      LAYER M5 ;
        RECT  10.224 0 10.248 0.084 ;
    END
  END pdata[285]
  PIN pdata[286]
    DIRECTION INPUT ;
    USE SIGNAL ;
    PORT
      LAYER M5 ;
        RECT  10.32 0 10.344 0.084 ;
    END
  END pdata[286]
  PIN pdata[287]
    DIRECTION INPUT ;
    USE SIGNAL ;
    PORT
      LAYER M5 ;
        RECT  10.416 0 10.44 0.084 ;
    END
  END pdata[287]
  PIN pdata[288]
    DIRECTION INPUT ;
    USE SIGNAL ;
    PORT
      LAYER M5 ;
        RECT  10.512 0 10.536 0.084 ;
    END
  END pdata[288]
  PIN pdata[289]
    DIRECTION INPUT ;
    USE SIGNAL ;
    PORT
      LAYER M5 ;
        RECT  10.608 0 10.632 0.084 ;
    END
  END pdata[289]
  PIN pdata[28]
    DIRECTION INPUT ;
    USE SIGNAL ;
    PORT
      LAYER M5 ;
        RECT  13.2 0 13.224 0.084 ;
    END
  END pdata[28]
  PIN pdata[290]
    DIRECTION INPUT ;
    USE SIGNAL ;
    PORT
      LAYER M5 ;
        RECT  10.704 0 10.728 0.084 ;
    END
  END pdata[290]
  PIN pdata[291]
    DIRECTION INPUT ;
    USE SIGNAL ;
    PORT
      LAYER M5 ;
        RECT  10.8 0 10.824 0.084 ;
    END
  END pdata[291]
  PIN pdata[292]
    DIRECTION INPUT ;
    USE SIGNAL ;
    PORT
      LAYER M5 ;
        RECT  10.896 0 10.92 0.084 ;
    END
  END pdata[292]
  PIN pdata[293]
    DIRECTION INPUT ;
    USE SIGNAL ;
    PORT
      LAYER M5 ;
        RECT  10.992 0 11.016 0.084 ;
    END
  END pdata[293]
  PIN pdata[294]
    DIRECTION INPUT ;
    USE SIGNAL ;
    PORT
      LAYER M5 ;
        RECT  11.088 0 11.112 0.084 ;
    END
  END pdata[294]
  PIN pdata[295]
    DIRECTION INPUT ;
    USE SIGNAL ;
    PORT
      LAYER M5 ;
        RECT  11.184 0 11.208 0.084 ;
    END
  END pdata[295]
  PIN pdata[296]
    DIRECTION INPUT ;
    USE SIGNAL ;
    PORT
      LAYER M5 ;
        RECT  11.28 0 11.304 0.084 ;
    END
  END pdata[296]
  PIN pdata[297]
    DIRECTION INPUT ;
    USE SIGNAL ;
    PORT
      LAYER M5 ;
        RECT  11.376 0 11.4 0.084 ;
    END
  END pdata[297]
  PIN pdata[298]
    DIRECTION INPUT ;
    USE SIGNAL ;
    PORT
      LAYER M5 ;
        RECT  11.472 0 11.496 0.084 ;
    END
  END pdata[298]
  PIN pdata[299]
    DIRECTION INPUT ;
    USE SIGNAL ;
    PORT
      LAYER M5 ;
        RECT  11.568 0 11.592 0.084 ;
    END
  END pdata[299]
  PIN pdata[29]
    DIRECTION INPUT ;
    USE SIGNAL ;
    PORT
      LAYER M5 ;
        RECT  13.296 0 13.32 0.084 ;
    END
  END pdata[29]
  PIN pdata[2]
    DIRECTION INPUT ;
    USE SIGNAL ;
    PORT
      LAYER M5 ;
        RECT  20.688 0 20.712 0.084 ;
    END
  END pdata[2]
  PIN pdata[300]
    DIRECTION INPUT ;
    USE SIGNAL ;
    PORT
      LAYER M5 ;
        RECT  11.664 0 11.688 0.084 ;
    END
  END pdata[300]
  PIN pdata[301]
    DIRECTION INPUT ;
    USE SIGNAL ;
    PORT
      LAYER M5 ;
        RECT  11.76 0 11.784 0.084 ;
    END
  END pdata[301]
  PIN pdata[302]
    DIRECTION INPUT ;
    USE SIGNAL ;
    PORT
      LAYER M5 ;
        RECT  11.856 0 11.88 0.084 ;
    END
  END pdata[302]
  PIN pdata[303]
    DIRECTION INPUT ;
    USE SIGNAL ;
    PORT
      LAYER M5 ;
        RECT  11.952 0 11.976 0.084 ;
    END
  END pdata[303]
  PIN pdata[304]
    DIRECTION INPUT ;
    USE SIGNAL ;
    PORT
      LAYER M5 ;
        RECT  12.048 0 12.072 0.084 ;
    END
  END pdata[304]
  PIN pdata[305]
    DIRECTION INPUT ;
    USE SIGNAL ;
    PORT
      LAYER M5 ;
        RECT  12.144 0 12.168 0.084 ;
    END
  END pdata[305]
  PIN pdata[306]
    DIRECTION INPUT ;
    USE SIGNAL ;
    PORT
      LAYER M5 ;
        RECT  12.24 0 12.264 0.084 ;
    END
  END pdata[306]
  PIN pdata[307]
    DIRECTION INPUT ;
    USE SIGNAL ;
    PORT
      LAYER M5 ;
        RECT  12.336 0 12.36 0.084 ;
    END
  END pdata[307]
  PIN pdata[308]
    DIRECTION INPUT ;
    USE SIGNAL ;
    PORT
      LAYER M5 ;
        RECT  12.432 0 12.456 0.084 ;
    END
  END pdata[308]
  PIN pdata[309]
    DIRECTION INPUT ;
    USE SIGNAL ;
    PORT
      LAYER M5 ;
        RECT  12.528 0 12.552 0.084 ;
    END
  END pdata[309]
  PIN pdata[30]
    DIRECTION INPUT ;
    USE SIGNAL ;
    PORT
      LAYER M5 ;
        RECT  13.392 0 13.416 0.084 ;
    END
  END pdata[30]
  PIN pdata[310]
    DIRECTION INPUT ;
    USE SIGNAL ;
    PORT
      LAYER M5 ;
        RECT  12.624 0 12.648 0.084 ;
    END
  END pdata[310]
  PIN pdata[311]
    DIRECTION INPUT ;
    USE SIGNAL ;
    PORT
      LAYER M5 ;
        RECT  12.72 0 12.744 0.084 ;
    END
  END pdata[311]
  PIN pdata[312]
    DIRECTION INPUT ;
    USE SIGNAL ;
    PORT
      LAYER M5 ;
        RECT  12.816 0 12.84 0.084 ;
    END
  END pdata[312]
  PIN pdata[313]
    DIRECTION INPUT ;
    USE SIGNAL ;
    PORT
      LAYER M5 ;
        RECT  12.912 0 12.936 0.084 ;
    END
  END pdata[313]
  PIN pdata[314]
    DIRECTION INPUT ;
    USE SIGNAL ;
    PORT
      LAYER M5 ;
        RECT  16.08 0 16.104 0.084 ;
    END
  END pdata[314]
  PIN pdata[315]
    DIRECTION INPUT ;
    USE SIGNAL ;
    PORT
      LAYER M5 ;
        RECT  16.176 0 16.2 0.084 ;
    END
  END pdata[315]
  PIN pdata[316]
    DIRECTION INPUT ;
    USE SIGNAL ;
    PORT
      LAYER M5 ;
        RECT  16.272 0 16.296 0.084 ;
    END
  END pdata[316]
  PIN pdata[317]
    DIRECTION INPUT ;
    USE SIGNAL ;
    PORT
      LAYER M5 ;
        RECT  16.368 0 16.392 0.084 ;
    END
  END pdata[317]
  PIN pdata[318]
    DIRECTION INPUT ;
    USE SIGNAL ;
    PORT
      LAYER M5 ;
        RECT  16.464 0 16.488 0.084 ;
    END
  END pdata[318]
  PIN pdata[319]
    DIRECTION INPUT ;
    USE SIGNAL ;
    PORT
      LAYER M5 ;
        RECT  16.56 0 16.584 0.084 ;
    END
  END pdata[319]
  PIN pdata[31]
    DIRECTION INPUT ;
    USE SIGNAL ;
    PORT
      LAYER M5 ;
        RECT  13.488 0 13.512 0.084 ;
    END
  END pdata[31]
  PIN pdata[320]
    DIRECTION INPUT ;
    USE SIGNAL ;
    PORT
      LAYER M5 ;
        RECT  16.656 0 16.68 0.084 ;
    END
  END pdata[320]
  PIN pdata[321]
    DIRECTION INPUT ;
    USE SIGNAL ;
    PORT
      LAYER M5 ;
        RECT  16.752 0 16.776 0.084 ;
    END
  END pdata[321]
  PIN pdata[322]
    DIRECTION INPUT ;
    USE SIGNAL ;
    PORT
      LAYER M5 ;
        RECT  16.848 0 16.872 0.084 ;
    END
  END pdata[322]
  PIN pdata[323]
    DIRECTION INPUT ;
    USE SIGNAL ;
    PORT
      LAYER M5 ;
        RECT  16.944 0 16.968 0.084 ;
    END
  END pdata[323]
  PIN pdata[324]
    DIRECTION INPUT ;
    USE SIGNAL ;
    PORT
      LAYER M5 ;
        RECT  17.04 0 17.064 0.084 ;
    END
  END pdata[324]
  PIN pdata[325]
    DIRECTION INPUT ;
    USE SIGNAL ;
    PORT
      LAYER M5 ;
        RECT  17.136 0 17.16 0.084 ;
    END
  END pdata[325]
  PIN pdata[326]
    DIRECTION INPUT ;
    USE SIGNAL ;
    PORT
      LAYER M5 ;
        RECT  17.232 0 17.256 0.084 ;
    END
  END pdata[326]
  PIN pdata[327]
    DIRECTION INPUT ;
    USE SIGNAL ;
    PORT
      LAYER M5 ;
        RECT  17.328 0 17.352 0.084 ;
    END
  END pdata[327]
  PIN pdata[328]
    DIRECTION INPUT ;
    USE SIGNAL ;
    PORT
      LAYER M5 ;
        RECT  17.424 0 17.448 0.084 ;
    END
  END pdata[328]
  PIN pdata[329]
    DIRECTION INPUT ;
    USE SIGNAL ;
    PORT
      LAYER M5 ;
        RECT  17.52 0 17.544 0.084 ;
    END
  END pdata[329]
  PIN pdata[32]
    DIRECTION INPUT ;
    USE SIGNAL ;
    PORT
      LAYER M5 ;
        RECT  13.584 0 13.608 0.084 ;
    END
  END pdata[32]
  PIN pdata[330]
    DIRECTION INPUT ;
    USE SIGNAL ;
    PORT
      LAYER M5 ;
        RECT  17.616 0 17.64 0.084 ;
    END
  END pdata[330]
  PIN pdata[331]
    DIRECTION INPUT ;
    USE SIGNAL ;
    PORT
      LAYER M5 ;
        RECT  17.712 0 17.736 0.084 ;
    END
  END pdata[331]
  PIN pdata[332]
    DIRECTION INPUT ;
    USE SIGNAL ;
    PORT
      LAYER M5 ;
        RECT  17.808 0 17.832 0.084 ;
    END
  END pdata[332]
  PIN pdata[333]
    DIRECTION INPUT ;
    USE SIGNAL ;
    PORT
      LAYER M5 ;
        RECT  17.904 0 17.928 0.084 ;
    END
  END pdata[333]
  PIN pdata[334]
    DIRECTION INPUT ;
    USE SIGNAL ;
    PORT
      LAYER M5 ;
        RECT  18 0 18.024 0.084 ;
    END
  END pdata[334]
  PIN pdata[335]
    DIRECTION INPUT ;
    USE SIGNAL ;
    PORT
      LAYER M5 ;
        RECT  18.096 0 18.12 0.084 ;
    END
  END pdata[335]
  PIN pdata[336]
    DIRECTION INPUT ;
    USE SIGNAL ;
    PORT
      LAYER M5 ;
        RECT  18.192 0 18.216 0.084 ;
    END
  END pdata[336]
  PIN pdata[337]
    DIRECTION INPUT ;
    USE SIGNAL ;
    PORT
      LAYER M5 ;
        RECT  18.288 0 18.312 0.084 ;
    END
  END pdata[337]
  PIN pdata[338]
    DIRECTION INPUT ;
    USE SIGNAL ;
    PORT
      LAYER M5 ;
        RECT  18.384 0 18.408 0.084 ;
    END
  END pdata[338]
  PIN pdata[339]
    DIRECTION INPUT ;
    USE SIGNAL ;
    PORT
      LAYER M5 ;
        RECT  18.48 0 18.504 0.084 ;
    END
  END pdata[339]
  PIN pdata[33]
    DIRECTION INPUT ;
    USE SIGNAL ;
    PORT
      LAYER M5 ;
        RECT  13.68 0 13.704 0.084 ;
    END
  END pdata[33]
  PIN pdata[340]
    DIRECTION INPUT ;
    USE SIGNAL ;
    PORT
      LAYER M5 ;
        RECT  18.576 0 18.6 0.084 ;
    END
  END pdata[340]
  PIN pdata[341]
    DIRECTION INPUT ;
    USE SIGNAL ;
    PORT
      LAYER M5 ;
        RECT  18.672 0 18.696 0.084 ;
    END
  END pdata[341]
  PIN pdata[342]
    DIRECTION INPUT ;
    USE SIGNAL ;
    PORT
      LAYER M5 ;
        RECT  18.768 0 18.792 0.084 ;
    END
  END pdata[342]
  PIN pdata[343]
    DIRECTION INPUT ;
    USE SIGNAL ;
    PORT
      LAYER M5 ;
        RECT  18.864 0 18.888 0.084 ;
    END
  END pdata[343]
  PIN pdata[344]
    DIRECTION INPUT ;
    USE SIGNAL ;
    PORT
      LAYER M5 ;
        RECT  18.96 0 18.984 0.084 ;
    END
  END pdata[344]
  PIN pdata[345]
    DIRECTION INPUT ;
    USE SIGNAL ;
    PORT
      LAYER M5 ;
        RECT  19.056 0 19.08 0.084 ;
    END
  END pdata[345]
  PIN pdata[346]
    DIRECTION INPUT ;
    USE SIGNAL ;
    PORT
      LAYER M5 ;
        RECT  26.064 0 26.088 0.084 ;
    END
  END pdata[346]
  PIN pdata[347]
    DIRECTION INPUT ;
    USE SIGNAL ;
    PORT
      LAYER M5 ;
        RECT  26.16 0 26.184 0.084 ;
    END
  END pdata[347]
  PIN pdata[348]
    DIRECTION INPUT ;
    USE SIGNAL ;
    PORT
      LAYER M5 ;
        RECT  26.256 0 26.28 0.084 ;
    END
  END pdata[348]
  PIN pdata[349]
    DIRECTION INPUT ;
    USE SIGNAL ;
    PORT
      LAYER M5 ;
        RECT  26.352 0 26.376 0.084 ;
    END
  END pdata[349]
  PIN pdata[34]
    DIRECTION INPUT ;
    USE SIGNAL ;
    PORT
      LAYER M5 ;
        RECT  13.776 0 13.8 0.084 ;
    END
  END pdata[34]
  PIN pdata[350]
    DIRECTION INPUT ;
    USE SIGNAL ;
    PORT
      LAYER M5 ;
        RECT  26.448 0 26.472 0.084 ;
    END
  END pdata[350]
  PIN pdata[351]
    DIRECTION INPUT ;
    USE SIGNAL ;
    PORT
      LAYER M5 ;
        RECT  26.544 0 26.568 0.084 ;
    END
  END pdata[351]
  PIN pdata[352]
    DIRECTION INPUT ;
    USE SIGNAL ;
    PORT
      LAYER M5 ;
        RECT  26.64 0 26.664 0.084 ;
    END
  END pdata[352]
  PIN pdata[353]
    DIRECTION INPUT ;
    USE SIGNAL ;
    PORT
      LAYER M5 ;
        RECT  26.736 0 26.76 0.084 ;
    END
  END pdata[353]
  PIN pdata[354]
    DIRECTION INPUT ;
    USE SIGNAL ;
    PORT
      LAYER M5 ;
        RECT  26.832 0 26.856 0.084 ;
    END
  END pdata[354]
  PIN pdata[355]
    DIRECTION INPUT ;
    USE SIGNAL ;
    PORT
      LAYER M5 ;
        RECT  26.928 0 26.952 0.084 ;
    END
  END pdata[355]
  PIN pdata[356]
    DIRECTION INPUT ;
    USE SIGNAL ;
    PORT
      LAYER M5 ;
        RECT  27.024 0 27.048 0.084 ;
    END
  END pdata[356]
  PIN pdata[357]
    DIRECTION INPUT ;
    USE SIGNAL ;
    PORT
      LAYER M5 ;
        RECT  27.12 0 27.144 0.084 ;
    END
  END pdata[357]
  PIN pdata[358]
    DIRECTION INPUT ;
    USE SIGNAL ;
    PORT
      LAYER M5 ;
        RECT  27.216 0 27.24 0.084 ;
    END
  END pdata[358]
  PIN pdata[359]
    DIRECTION INPUT ;
    USE SIGNAL ;
    PORT
      LAYER M5 ;
        RECT  27.312 0 27.336 0.084 ;
    END
  END pdata[359]
  PIN pdata[35]
    DIRECTION INPUT ;
    USE SIGNAL ;
    PORT
      LAYER M5 ;
        RECT  13.872 0 13.896 0.084 ;
    END
  END pdata[35]
  PIN pdata[360]
    DIRECTION INPUT ;
    USE SIGNAL ;
    PORT
      LAYER M5 ;
        RECT  27.408 0 27.432 0.084 ;
    END
  END pdata[360]
  PIN pdata[361]
    DIRECTION INPUT ;
    USE SIGNAL ;
    PORT
      LAYER M5 ;
        RECT  27.504 0 27.528 0.084 ;
    END
  END pdata[361]
  PIN pdata[362]
    DIRECTION INPUT ;
    USE SIGNAL ;
    PORT
      LAYER M5 ;
        RECT  27.6 0 27.624 0.084 ;
    END
  END pdata[362]
  PIN pdata[363]
    DIRECTION INPUT ;
    USE SIGNAL ;
    PORT
      LAYER M5 ;
        RECT  27.696 0 27.72 0.084 ;
    END
  END pdata[363]
  PIN pdata[364]
    DIRECTION INPUT ;
    USE SIGNAL ;
    PORT
      LAYER M5 ;
        RECT  27.792 0 27.816 0.084 ;
    END
  END pdata[364]
  PIN pdata[365]
    DIRECTION INPUT ;
    USE SIGNAL ;
    PORT
      LAYER M5 ;
        RECT  27.888 0 27.912 0.084 ;
    END
  END pdata[365]
  PIN pdata[366]
    DIRECTION INPUT ;
    USE SIGNAL ;
    PORT
      LAYER M5 ;
        RECT  27.984 0 28.008 0.084 ;
    END
  END pdata[366]
  PIN pdata[367]
    DIRECTION INPUT ;
    USE SIGNAL ;
    PORT
      LAYER M5 ;
        RECT  28.08 0 28.104 0.084 ;
    END
  END pdata[367]
  PIN pdata[368]
    DIRECTION INPUT ;
    USE SIGNAL ;
    PORT
      LAYER M5 ;
        RECT  28.176 0 28.2 0.084 ;
    END
  END pdata[368]
  PIN pdata[369]
    DIRECTION INPUT ;
    USE SIGNAL ;
    PORT
      LAYER M5 ;
        RECT  28.272 0 28.296 0.084 ;
    END
  END pdata[369]
  PIN pdata[36]
    DIRECTION INPUT ;
    USE SIGNAL ;
    PORT
      LAYER M5 ;
        RECT  13.968 0 13.992 0.084 ;
    END
  END pdata[36]
  PIN pdata[370]
    DIRECTION INPUT ;
    USE SIGNAL ;
    PORT
      LAYER M5 ;
        RECT  28.368 0 28.392 0.084 ;
    END
  END pdata[370]
  PIN pdata[371]
    DIRECTION INPUT ;
    USE SIGNAL ;
    PORT
      LAYER M5 ;
        RECT  28.464 0 28.488 0.084 ;
    END
  END pdata[371]
  PIN pdata[372]
    DIRECTION INPUT ;
    USE SIGNAL ;
    PORT
      LAYER M5 ;
        RECT  28.56 0 28.584 0.084 ;
    END
  END pdata[372]
  PIN pdata[373]
    DIRECTION INPUT ;
    USE SIGNAL ;
    PORT
      LAYER M5 ;
        RECT  28.656 0 28.68 0.084 ;
    END
  END pdata[373]
  PIN pdata[374]
    DIRECTION INPUT ;
    USE SIGNAL ;
    PORT
      LAYER M5 ;
        RECT  28.752 0 28.776 0.084 ;
    END
  END pdata[374]
  PIN pdata[375]
    DIRECTION INPUT ;
    USE SIGNAL ;
    PORT
      LAYER M5 ;
        RECT  28.848 0 28.872 0.084 ;
    END
  END pdata[375]
  PIN pdata[376]
    DIRECTION INPUT ;
    USE SIGNAL ;
    PORT
      LAYER M5 ;
        RECT  28.944 0 28.968 0.084 ;
    END
  END pdata[376]
  PIN pdata[377]
    DIRECTION INPUT ;
    USE SIGNAL ;
    PORT
      LAYER M5 ;
        RECT  29.04 0 29.064 0.084 ;
    END
  END pdata[377]
  PIN pdata[378]
    DIRECTION INPUT ;
    USE SIGNAL ;
    PORT
      LAYER M5 ;
        RECT  109.008 0 109.032 0.084 ;
    END
  END pdata[378]
  PIN pdata[379]
    DIRECTION INPUT ;
    USE SIGNAL ;
    PORT
      LAYER M5 ;
        RECT  109.104 0 109.128 0.084 ;
    END
  END pdata[379]
  PIN pdata[37]
    DIRECTION INPUT ;
    USE SIGNAL ;
    PORT
      LAYER M5 ;
        RECT  14.064 0 14.088 0.084 ;
    END
  END pdata[37]
  PIN pdata[380]
    DIRECTION INPUT ;
    USE SIGNAL ;
    PORT
      LAYER M5 ;
        RECT  109.2 0 109.224 0.084 ;
    END
  END pdata[380]
  PIN pdata[381]
    DIRECTION INPUT ;
    USE SIGNAL ;
    PORT
      LAYER M5 ;
        RECT  109.296 0 109.32 0.084 ;
    END
  END pdata[381]
  PIN pdata[382]
    DIRECTION INPUT ;
    USE SIGNAL ;
    PORT
      LAYER M5 ;
        RECT  109.392 0 109.416 0.084 ;
    END
  END pdata[382]
  PIN pdata[383]
    DIRECTION INPUT ;
    USE SIGNAL ;
    PORT
      LAYER M5 ;
        RECT  109.488 0 109.512 0.084 ;
    END
  END pdata[383]
  PIN pdata[384]
    DIRECTION INPUT ;
    USE SIGNAL ;
    PORT
      LAYER M5 ;
        RECT  109.584 0 109.608 0.084 ;
    END
  END pdata[384]
  PIN pdata[385]
    DIRECTION INPUT ;
    USE SIGNAL ;
    PORT
      LAYER M5 ;
        RECT  109.68 0 109.704 0.084 ;
    END
  END pdata[385]
  PIN pdata[386]
    DIRECTION INPUT ;
    USE SIGNAL ;
    PORT
      LAYER M5 ;
        RECT  109.776 0 109.8 0.084 ;
    END
  END pdata[386]
  PIN pdata[387]
    DIRECTION INPUT ;
    USE SIGNAL ;
    PORT
      LAYER M5 ;
        RECT  109.872 0 109.896 0.084 ;
    END
  END pdata[387]
  PIN pdata[388]
    DIRECTION INPUT ;
    USE SIGNAL ;
    PORT
      LAYER M5 ;
        RECT  109.968 0 109.992 0.084 ;
    END
  END pdata[388]
  PIN pdata[389]
    DIRECTION INPUT ;
    USE SIGNAL ;
    PORT
      LAYER M5 ;
        RECT  110.064 0 110.088 0.084 ;
    END
  END pdata[389]
  PIN pdata[38]
    DIRECTION INPUT ;
    USE SIGNAL ;
    PORT
      LAYER M5 ;
        RECT  14.16 0 14.184 0.084 ;
    END
  END pdata[38]
  PIN pdata[390]
    DIRECTION INPUT ;
    USE SIGNAL ;
    PORT
      LAYER M5 ;
        RECT  110.16 0 110.184 0.084 ;
    END
  END pdata[390]
  PIN pdata[391]
    DIRECTION INPUT ;
    USE SIGNAL ;
    PORT
      LAYER M5 ;
        RECT  110.256 0 110.28 0.084 ;
    END
  END pdata[391]
  PIN pdata[392]
    DIRECTION INPUT ;
    USE SIGNAL ;
    PORT
      LAYER M5 ;
        RECT  110.352 0 110.376 0.084 ;
    END
  END pdata[392]
  PIN pdata[393]
    DIRECTION INPUT ;
    USE SIGNAL ;
    PORT
      LAYER M5 ;
        RECT  110.448 0 110.472 0.084 ;
    END
  END pdata[393]
  PIN pdata[394]
    DIRECTION INPUT ;
    USE SIGNAL ;
    PORT
      LAYER M5 ;
        RECT  110.544 0 110.568 0.084 ;
    END
  END pdata[394]
  PIN pdata[395]
    DIRECTION INPUT ;
    USE SIGNAL ;
    PORT
      LAYER M5 ;
        RECT  110.64 0 110.664 0.084 ;
    END
  END pdata[395]
  PIN pdata[396]
    DIRECTION INPUT ;
    USE SIGNAL ;
    PORT
      LAYER M5 ;
        RECT  110.736 0 110.76 0.084 ;
    END
  END pdata[396]
  PIN pdata[397]
    DIRECTION INPUT ;
    USE SIGNAL ;
    PORT
      LAYER M5 ;
        RECT  110.832 0 110.856 0.084 ;
    END
  END pdata[397]
  PIN pdata[398]
    DIRECTION INPUT ;
    USE SIGNAL ;
    PORT
      LAYER M5 ;
        RECT  110.928 0 110.952 0.084 ;
    END
  END pdata[398]
  PIN pdata[399]
    DIRECTION INPUT ;
    USE SIGNAL ;
    PORT
      LAYER M5 ;
        RECT  111.024 0 111.048 0.084 ;
    END
  END pdata[399]
  PIN pdata[39]
    DIRECTION INPUT ;
    USE SIGNAL ;
    PORT
      LAYER M5 ;
        RECT  14.256 0 14.28 0.084 ;
    END
  END pdata[39]
  PIN pdata[3]
    DIRECTION INPUT ;
    USE SIGNAL ;
    PORT
      LAYER M5 ;
        RECT  20.784 0 20.808 0.084 ;
    END
  END pdata[3]
  PIN pdata[400]
    DIRECTION INPUT ;
    USE SIGNAL ;
    PORT
      LAYER M5 ;
        RECT  111.12 0 111.144 0.084 ;
    END
  END pdata[400]
  PIN pdata[401]
    DIRECTION INPUT ;
    USE SIGNAL ;
    PORT
      LAYER M5 ;
        RECT  111.216 0 111.24 0.084 ;
    END
  END pdata[401]
  PIN pdata[402]
    DIRECTION INPUT ;
    USE SIGNAL ;
    PORT
      LAYER M5 ;
        RECT  111.312 0 111.336 0.084 ;
    END
  END pdata[402]
  PIN pdata[403]
    DIRECTION INPUT ;
    USE SIGNAL ;
    PORT
      LAYER M5 ;
        RECT  111.408 0 111.432 0.084 ;
    END
  END pdata[403]
  PIN pdata[404]
    DIRECTION INPUT ;
    USE SIGNAL ;
    PORT
      LAYER M5 ;
        RECT  111.504 0 111.528 0.084 ;
    END
  END pdata[404]
  PIN pdata[405]
    DIRECTION INPUT ;
    USE SIGNAL ;
    PORT
      LAYER M5 ;
        RECT  111.6 0 111.624 0.084 ;
    END
  END pdata[405]
  PIN pdata[406]
    DIRECTION INPUT ;
    USE SIGNAL ;
    PORT
      LAYER M5 ;
        RECT  111.696 0 111.72 0.084 ;
    END
  END pdata[406]
  PIN pdata[407]
    DIRECTION INPUT ;
    USE SIGNAL ;
    PORT
      LAYER M5 ;
        RECT  111.792 0 111.816 0.084 ;
    END
  END pdata[407]
  PIN pdata[408]
    DIRECTION INPUT ;
    USE SIGNAL ;
    PORT
      LAYER M5 ;
        RECT  111.888 0 111.912 0.084 ;
    END
  END pdata[408]
  PIN pdata[409]
    DIRECTION INPUT ;
    USE SIGNAL ;
    PORT
      LAYER M5 ;
        RECT  111.984 0 112.008 0.084 ;
    END
  END pdata[409]
  PIN pdata[40]
    DIRECTION INPUT ;
    USE SIGNAL ;
    PORT
      LAYER M5 ;
        RECT  14.352 0 14.376 0.084 ;
    END
  END pdata[40]
  PIN pdata[410]
    DIRECTION INPUT ;
    USE SIGNAL ;
    PORT
      LAYER M5 ;
        RECT  115.92 0 115.944 0.084 ;
    END
  END pdata[410]
  PIN pdata[411]
    DIRECTION INPUT ;
    USE SIGNAL ;
    PORT
      LAYER M5 ;
        RECT  116.016 0 116.04 0.084 ;
    END
  END pdata[411]
  PIN pdata[412]
    DIRECTION INPUT ;
    USE SIGNAL ;
    PORT
      LAYER M5 ;
        RECT  116.112 0 116.136 0.084 ;
    END
  END pdata[412]
  PIN pdata[413]
    DIRECTION INPUT ;
    USE SIGNAL ;
    PORT
      LAYER M5 ;
        RECT  116.208 0 116.232 0.084 ;
    END
  END pdata[413]
  PIN pdata[414]
    DIRECTION INPUT ;
    USE SIGNAL ;
    PORT
      LAYER M5 ;
        RECT  116.304 0 116.328 0.084 ;
    END
  END pdata[414]
  PIN pdata[415]
    DIRECTION INPUT ;
    USE SIGNAL ;
    PORT
      LAYER M5 ;
        RECT  116.4 0 116.424 0.084 ;
    END
  END pdata[415]
  PIN pdata[416]
    DIRECTION INPUT ;
    USE SIGNAL ;
    PORT
      LAYER M5 ;
        RECT  116.496 0 116.52 0.084 ;
    END
  END pdata[416]
  PIN pdata[417]
    DIRECTION INPUT ;
    USE SIGNAL ;
    PORT
      LAYER M5 ;
        RECT  116.592 0 116.616 0.084 ;
    END
  END pdata[417]
  PIN pdata[418]
    DIRECTION INPUT ;
    USE SIGNAL ;
    PORT
      LAYER M5 ;
        RECT  116.688 0 116.712 0.084 ;
    END
  END pdata[418]
  PIN pdata[419]
    DIRECTION INPUT ;
    USE SIGNAL ;
    PORT
      LAYER M5 ;
        RECT  116.784 0 116.808 0.084 ;
    END
  END pdata[419]
  PIN pdata[41]
    DIRECTION INPUT ;
    USE SIGNAL ;
    PORT
      LAYER M5 ;
        RECT  14.448 0 14.472 0.084 ;
    END
  END pdata[41]
  PIN pdata[420]
    DIRECTION INPUT ;
    USE SIGNAL ;
    PORT
      LAYER M5 ;
        RECT  116.88 0 116.904 0.084 ;
    END
  END pdata[420]
  PIN pdata[421]
    DIRECTION INPUT ;
    USE SIGNAL ;
    PORT
      LAYER M5 ;
        RECT  116.976 0 117 0.084 ;
    END
  END pdata[421]
  PIN pdata[422]
    DIRECTION INPUT ;
    USE SIGNAL ;
    PORT
      LAYER M5 ;
        RECT  117.072 0 117.096 0.084 ;
    END
  END pdata[422]
  PIN pdata[423]
    DIRECTION INPUT ;
    USE SIGNAL ;
    PORT
      LAYER M5 ;
        RECT  117.168 0 117.192 0.084 ;
    END
  END pdata[423]
  PIN pdata[424]
    DIRECTION INPUT ;
    USE SIGNAL ;
    PORT
      LAYER M5 ;
        RECT  117.264 0 117.288 0.084 ;
    END
  END pdata[424]
  PIN pdata[425]
    DIRECTION INPUT ;
    USE SIGNAL ;
    PORT
      LAYER M5 ;
        RECT  117.36 0 117.384 0.084 ;
    END
  END pdata[425]
  PIN pdata[426]
    DIRECTION INPUT ;
    USE SIGNAL ;
    PORT
      LAYER M5 ;
        RECT  117.456 0 117.48 0.084 ;
    END
  END pdata[426]
  PIN pdata[427]
    DIRECTION INPUT ;
    USE SIGNAL ;
    PORT
      LAYER M5 ;
        RECT  117.552 0 117.576 0.084 ;
    END
  END pdata[427]
  PIN pdata[428]
    DIRECTION INPUT ;
    USE SIGNAL ;
    PORT
      LAYER M5 ;
        RECT  117.648 0 117.672 0.084 ;
    END
  END pdata[428]
  PIN pdata[429]
    DIRECTION INPUT ;
    USE SIGNAL ;
    PORT
      LAYER M5 ;
        RECT  117.744 0 117.768 0.084 ;
    END
  END pdata[429]
  PIN pdata[42]
    DIRECTION INPUT ;
    USE SIGNAL ;
    PORT
      LAYER M5 ;
        RECT  14.544 0 14.568 0.084 ;
    END
  END pdata[42]
  PIN pdata[430]
    DIRECTION INPUT ;
    USE SIGNAL ;
    PORT
      LAYER M5 ;
        RECT  117.84 0 117.864 0.084 ;
    END
  END pdata[430]
  PIN pdata[431]
    DIRECTION INPUT ;
    USE SIGNAL ;
    PORT
      LAYER M5 ;
        RECT  117.936 0 117.96 0.084 ;
    END
  END pdata[431]
  PIN pdata[432]
    DIRECTION INPUT ;
    USE SIGNAL ;
    PORT
      LAYER M5 ;
        RECT  118.032 0 118.056 0.084 ;
    END
  END pdata[432]
  PIN pdata[433]
    DIRECTION INPUT ;
    USE SIGNAL ;
    PORT
      LAYER M5 ;
        RECT  118.128 0 118.152 0.084 ;
    END
  END pdata[433]
  PIN pdata[434]
    DIRECTION INPUT ;
    USE SIGNAL ;
    PORT
      LAYER M5 ;
        RECT  118.224 0 118.248 0.084 ;
    END
  END pdata[434]
  PIN pdata[435]
    DIRECTION INPUT ;
    USE SIGNAL ;
    PORT
      LAYER M5 ;
        RECT  118.32 0 118.344 0.084 ;
    END
  END pdata[435]
  PIN pdata[436]
    DIRECTION INPUT ;
    USE SIGNAL ;
    PORT
      LAYER M5 ;
        RECT  118.416 0 118.44 0.084 ;
    END
  END pdata[436]
  PIN pdata[437]
    DIRECTION INPUT ;
    USE SIGNAL ;
    PORT
      LAYER M5 ;
        RECT  118.512 0 118.536 0.084 ;
    END
  END pdata[437]
  PIN pdata[438]
    DIRECTION INPUT ;
    USE SIGNAL ;
    PORT
      LAYER M5 ;
        RECT  118.608 0 118.632 0.084 ;
    END
  END pdata[438]
  PIN pdata[439]
    DIRECTION INPUT ;
    USE SIGNAL ;
    PORT
      LAYER M5 ;
        RECT  118.704 0 118.728 0.084 ;
    END
  END pdata[439]
  PIN pdata[43]
    DIRECTION INPUT ;
    USE SIGNAL ;
    PORT
      LAYER M5 ;
        RECT  14.64 0 14.664 0.084 ;
    END
  END pdata[43]
  PIN pdata[440]
    DIRECTION INPUT ;
    USE SIGNAL ;
    PORT
      LAYER M5 ;
        RECT  118.8 0 118.824 0.084 ;
    END
  END pdata[440]
  PIN pdata[441]
    DIRECTION INPUT ;
    USE SIGNAL ;
    PORT
      LAYER M5 ;
        RECT  118.896 0 118.92 0.084 ;
    END
  END pdata[441]
  PIN pdata[442]
    DIRECTION INPUT ;
    USE SIGNAL ;
    PORT
      LAYER M5 ;
        RECT  122.064 0 122.088 0.084 ;
    END
  END pdata[442]
  PIN pdata[443]
    DIRECTION INPUT ;
    USE SIGNAL ;
    PORT
      LAYER M5 ;
        RECT  122.16 0 122.184 0.084 ;
    END
  END pdata[443]
  PIN pdata[444]
    DIRECTION INPUT ;
    USE SIGNAL ;
    PORT
      LAYER M5 ;
        RECT  122.256 0 122.28 0.084 ;
    END
  END pdata[444]
  PIN pdata[445]
    DIRECTION INPUT ;
    USE SIGNAL ;
    PORT
      LAYER M5 ;
        RECT  122.352 0 122.376 0.084 ;
    END
  END pdata[445]
  PIN pdata[446]
    DIRECTION INPUT ;
    USE SIGNAL ;
    PORT
      LAYER M5 ;
        RECT  122.448 0 122.472 0.084 ;
    END
  END pdata[446]
  PIN pdata[447]
    DIRECTION INPUT ;
    USE SIGNAL ;
    PORT
      LAYER M5 ;
        RECT  122.544 0 122.568 0.084 ;
    END
  END pdata[447]
  PIN pdata[448]
    DIRECTION INPUT ;
    USE SIGNAL ;
    PORT
      LAYER M5 ;
        RECT  122.64 0 122.664 0.084 ;
    END
  END pdata[448]
  PIN pdata[449]
    DIRECTION INPUT ;
    USE SIGNAL ;
    PORT
      LAYER M5 ;
        RECT  122.736 0 122.76 0.084 ;
    END
  END pdata[449]
  PIN pdata[44]
    DIRECTION INPUT ;
    USE SIGNAL ;
    PORT
      LAYER M5 ;
        RECT  14.736 0 14.76 0.084 ;
    END
  END pdata[44]
  PIN pdata[450]
    DIRECTION INPUT ;
    USE SIGNAL ;
    PORT
      LAYER M5 ;
        RECT  122.832 0 122.856 0.084 ;
    END
  END pdata[450]
  PIN pdata[451]
    DIRECTION INPUT ;
    USE SIGNAL ;
    PORT
      LAYER M5 ;
        RECT  122.928 0 122.952 0.084 ;
    END
  END pdata[451]
  PIN pdata[452]
    DIRECTION INPUT ;
    USE SIGNAL ;
    PORT
      LAYER M5 ;
        RECT  123.024 0 123.048 0.084 ;
    END
  END pdata[452]
  PIN pdata[453]
    DIRECTION INPUT ;
    USE SIGNAL ;
    PORT
      LAYER M5 ;
        RECT  123.12 0 123.144 0.084 ;
    END
  END pdata[453]
  PIN pdata[454]
    DIRECTION INPUT ;
    USE SIGNAL ;
    PORT
      LAYER M5 ;
        RECT  123.216 0 123.24 0.084 ;
    END
  END pdata[454]
  PIN pdata[455]
    DIRECTION INPUT ;
    USE SIGNAL ;
    PORT
      LAYER M5 ;
        RECT  123.312 0 123.336 0.084 ;
    END
  END pdata[455]
  PIN pdata[456]
    DIRECTION INPUT ;
    USE SIGNAL ;
    PORT
      LAYER M5 ;
        RECT  123.408 0 123.432 0.084 ;
    END
  END pdata[456]
  PIN pdata[457]
    DIRECTION INPUT ;
    USE SIGNAL ;
    PORT
      LAYER M5 ;
        RECT  123.504 0 123.528 0.084 ;
    END
  END pdata[457]
  PIN pdata[458]
    DIRECTION INPUT ;
    USE SIGNAL ;
    PORT
      LAYER M5 ;
        RECT  123.6 0 123.624 0.084 ;
    END
  END pdata[458]
  PIN pdata[459]
    DIRECTION INPUT ;
    USE SIGNAL ;
    PORT
      LAYER M5 ;
        RECT  123.696 0 123.72 0.084 ;
    END
  END pdata[459]
  PIN pdata[45]
    DIRECTION INPUT ;
    USE SIGNAL ;
    PORT
      LAYER M5 ;
        RECT  14.832 0 14.856 0.084 ;
    END
  END pdata[45]
  PIN pdata[460]
    DIRECTION INPUT ;
    USE SIGNAL ;
    PORT
      LAYER M5 ;
        RECT  123.792 0 123.816 0.084 ;
    END
  END pdata[460]
  PIN pdata[461]
    DIRECTION INPUT ;
    USE SIGNAL ;
    PORT
      LAYER M5 ;
        RECT  123.888 0 123.912 0.084 ;
    END
  END pdata[461]
  PIN pdata[462]
    DIRECTION INPUT ;
    USE SIGNAL ;
    PORT
      LAYER M5 ;
        RECT  123.984 0 124.008 0.084 ;
    END
  END pdata[462]
  PIN pdata[463]
    DIRECTION INPUT ;
    USE SIGNAL ;
    PORT
      LAYER M5 ;
        RECT  124.08 0 124.104 0.084 ;
    END
  END pdata[463]
  PIN pdata[464]
    DIRECTION INPUT ;
    USE SIGNAL ;
    PORT
      LAYER M5 ;
        RECT  124.176 0 124.2 0.084 ;
    END
  END pdata[464]
  PIN pdata[465]
    DIRECTION INPUT ;
    USE SIGNAL ;
    PORT
      LAYER M5 ;
        RECT  124.272 0 124.296 0.084 ;
    END
  END pdata[465]
  PIN pdata[466]
    DIRECTION INPUT ;
    USE SIGNAL ;
    PORT
      LAYER M5 ;
        RECT  124.368 0 124.392 0.084 ;
    END
  END pdata[466]
  PIN pdata[467]
    DIRECTION INPUT ;
    USE SIGNAL ;
    PORT
      LAYER M5 ;
        RECT  124.464 0 124.488 0.084 ;
    END
  END pdata[467]
  PIN pdata[468]
    DIRECTION INPUT ;
    USE SIGNAL ;
    PORT
      LAYER M5 ;
        RECT  124.56 0 124.584 0.084 ;
    END
  END pdata[468]
  PIN pdata[469]
    DIRECTION INPUT ;
    USE SIGNAL ;
    PORT
      LAYER M5 ;
        RECT  124.656 0 124.68 0.084 ;
    END
  END pdata[469]
  PIN pdata[46]
    DIRECTION INPUT ;
    USE SIGNAL ;
    PORT
      LAYER M5 ;
        RECT  14.928 0 14.952 0.084 ;
    END
  END pdata[46]
  PIN pdata[470]
    DIRECTION INPUT ;
    USE SIGNAL ;
    PORT
      LAYER M5 ;
        RECT  124.752 0 124.776 0.084 ;
    END
  END pdata[470]
  PIN pdata[471]
    DIRECTION INPUT ;
    USE SIGNAL ;
    PORT
      LAYER M5 ;
        RECT  124.848 0 124.872 0.084 ;
    END
  END pdata[471]
  PIN pdata[472]
    DIRECTION INPUT ;
    USE SIGNAL ;
    PORT
      LAYER M5 ;
        RECT  124.944 0 124.968 0.084 ;
    END
  END pdata[472]
  PIN pdata[473]
    DIRECTION INPUT ;
    USE SIGNAL ;
    PORT
      LAYER M5 ;
        RECT  125.04 0 125.064 0.084 ;
    END
  END pdata[473]
  PIN pdata[474]
    DIRECTION INPUT ;
    USE SIGNAL ;
    PORT
      LAYER M5 ;
        RECT  128.208 0 128.232 0.084 ;
    END
  END pdata[474]
  PIN pdata[475]
    DIRECTION INPUT ;
    USE SIGNAL ;
    PORT
      LAYER M5 ;
        RECT  128.304 0 128.328 0.084 ;
    END
  END pdata[475]
  PIN pdata[476]
    DIRECTION INPUT ;
    USE SIGNAL ;
    PORT
      LAYER M5 ;
        RECT  128.4 0 128.424 0.084 ;
    END
  END pdata[476]
  PIN pdata[477]
    DIRECTION INPUT ;
    USE SIGNAL ;
    PORT
      LAYER M5 ;
        RECT  128.496 0 128.52 0.084 ;
    END
  END pdata[477]
  PIN pdata[478]
    DIRECTION INPUT ;
    USE SIGNAL ;
    PORT
      LAYER M5 ;
        RECT  128.592 0 128.616 0.084 ;
    END
  END pdata[478]
  PIN pdata[479]
    DIRECTION INPUT ;
    USE SIGNAL ;
    PORT
      LAYER M5 ;
        RECT  128.688 0 128.712 0.084 ;
    END
  END pdata[479]
  PIN pdata[47]
    DIRECTION INPUT ;
    USE SIGNAL ;
    PORT
      LAYER M5 ;
        RECT  15.024 0 15.048 0.084 ;
    END
  END pdata[47]
  PIN pdata[480]
    DIRECTION INPUT ;
    USE SIGNAL ;
    PORT
      LAYER M5 ;
        RECT  128.784 0 128.808 0.084 ;
    END
  END pdata[480]
  PIN pdata[481]
    DIRECTION INPUT ;
    USE SIGNAL ;
    PORT
      LAYER M5 ;
        RECT  128.88 0 128.904 0.084 ;
    END
  END pdata[481]
  PIN pdata[482]
    DIRECTION INPUT ;
    USE SIGNAL ;
    PORT
      LAYER M5 ;
        RECT  128.976 0 129 0.084 ;
    END
  END pdata[482]
  PIN pdata[483]
    DIRECTION INPUT ;
    USE SIGNAL ;
    PORT
      LAYER M5 ;
        RECT  129.072 0 129.096 0.084 ;
    END
  END pdata[483]
  PIN pdata[484]
    DIRECTION INPUT ;
    USE SIGNAL ;
    PORT
      LAYER M5 ;
        RECT  129.168 0 129.192 0.084 ;
    END
  END pdata[484]
  PIN pdata[485]
    DIRECTION INPUT ;
    USE SIGNAL ;
    PORT
      LAYER M5 ;
        RECT  129.264 0 129.288 0.084 ;
    END
  END pdata[485]
  PIN pdata[486]
    DIRECTION INPUT ;
    USE SIGNAL ;
    PORT
      LAYER M5 ;
        RECT  129.36 0 129.384 0.084 ;
    END
  END pdata[486]
  PIN pdata[487]
    DIRECTION INPUT ;
    USE SIGNAL ;
    PORT
      LAYER M5 ;
        RECT  129.456 0 129.48 0.084 ;
    END
  END pdata[487]
  PIN pdata[488]
    DIRECTION INPUT ;
    USE SIGNAL ;
    PORT
      LAYER M5 ;
        RECT  129.552 0 129.576 0.084 ;
    END
  END pdata[488]
  PIN pdata[489]
    DIRECTION INPUT ;
    USE SIGNAL ;
    PORT
      LAYER M5 ;
        RECT  129.648 0 129.672 0.084 ;
    END
  END pdata[489]
  PIN pdata[48]
    DIRECTION INPUT ;
    USE SIGNAL ;
    PORT
      LAYER M5 ;
        RECT  15.12 0 15.144 0.084 ;
    END
  END pdata[48]
  PIN pdata[490]
    DIRECTION INPUT ;
    USE SIGNAL ;
    PORT
      LAYER M5 ;
        RECT  129.744 0 129.768 0.084 ;
    END
  END pdata[490]
  PIN pdata[491]
    DIRECTION INPUT ;
    USE SIGNAL ;
    PORT
      LAYER M5 ;
        RECT  129.84 0 129.864 0.084 ;
    END
  END pdata[491]
  PIN pdata[492]
    DIRECTION INPUT ;
    USE SIGNAL ;
    PORT
      LAYER M5 ;
        RECT  129.936 0 129.96 0.084 ;
    END
  END pdata[492]
  PIN pdata[493]
    DIRECTION INPUT ;
    USE SIGNAL ;
    PORT
      LAYER M5 ;
        RECT  130.032 0 130.056 0.084 ;
    END
  END pdata[493]
  PIN pdata[494]
    DIRECTION INPUT ;
    USE SIGNAL ;
    PORT
      LAYER M5 ;
        RECT  130.128 0 130.152 0.084 ;
    END
  END pdata[494]
  PIN pdata[495]
    DIRECTION INPUT ;
    USE SIGNAL ;
    PORT
      LAYER M5 ;
        RECT  130.224 0 130.248 0.084 ;
    END
  END pdata[495]
  PIN pdata[496]
    DIRECTION INPUT ;
    USE SIGNAL ;
    PORT
      LAYER M5 ;
        RECT  130.32 0 130.344 0.084 ;
    END
  END pdata[496]
  PIN pdata[497]
    DIRECTION INPUT ;
    USE SIGNAL ;
    PORT
      LAYER M5 ;
        RECT  130.416 0 130.44 0.084 ;
    END
  END pdata[497]
  PIN pdata[498]
    DIRECTION INPUT ;
    USE SIGNAL ;
    PORT
      LAYER M5 ;
        RECT  130.512 0 130.536 0.084 ;
    END
  END pdata[498]
  PIN pdata[499]
    DIRECTION INPUT ;
    USE SIGNAL ;
    PORT
      LAYER M5 ;
        RECT  130.608 0 130.632 0.084 ;
    END
  END pdata[499]
  PIN pdata[49]
    DIRECTION INPUT ;
    USE SIGNAL ;
    PORT
      LAYER M5 ;
        RECT  15.216 0 15.24 0.084 ;
    END
  END pdata[49]
  PIN pdata[4]
    DIRECTION INPUT ;
    USE SIGNAL ;
    PORT
      LAYER M5 ;
        RECT  20.88 0 20.904 0.084 ;
    END
  END pdata[4]
  PIN pdata[500]
    DIRECTION INPUT ;
    USE SIGNAL ;
    PORT
      LAYER M5 ;
        RECT  130.704 0 130.728 0.084 ;
    END
  END pdata[500]
  PIN pdata[501]
    DIRECTION INPUT ;
    USE SIGNAL ;
    PORT
      LAYER M5 ;
        RECT  130.8 0 130.824 0.084 ;
    END
  END pdata[501]
  PIN pdata[502]
    DIRECTION INPUT ;
    USE SIGNAL ;
    PORT
      LAYER M5 ;
        RECT  130.896 0 130.92 0.084 ;
    END
  END pdata[502]
  PIN pdata[503]
    DIRECTION INPUT ;
    USE SIGNAL ;
    PORT
      LAYER M5 ;
        RECT  130.992 0 131.016 0.084 ;
    END
  END pdata[503]
  PIN pdata[504]
    DIRECTION INPUT ;
    USE SIGNAL ;
    PORT
      LAYER M5 ;
        RECT  131.088 0 131.112 0.084 ;
    END
  END pdata[504]
  PIN pdata[505]
    DIRECTION INPUT ;
    USE SIGNAL ;
    PORT
      LAYER M5 ;
        RECT  131.184 0 131.208 0.084 ;
    END
  END pdata[505]
  PIN pdata[506]
    DIRECTION INPUT ;
    USE SIGNAL ;
    PORT
      LAYER M5 ;
        RECT  134.352 0 134.376 0.084 ;
    END
  END pdata[506]
  PIN pdata[507]
    DIRECTION INPUT ;
    USE SIGNAL ;
    PORT
      LAYER M5 ;
        RECT  134.448 0 134.472 0.084 ;
    END
  END pdata[507]
  PIN pdata[508]
    DIRECTION INPUT ;
    USE SIGNAL ;
    PORT
      LAYER M5 ;
        RECT  134.544 0 134.568 0.084 ;
    END
  END pdata[508]
  PIN pdata[509]
    DIRECTION INPUT ;
    USE SIGNAL ;
    PORT
      LAYER M5 ;
        RECT  134.64 0 134.664 0.084 ;
    END
  END pdata[509]
  PIN pdata[50]
    DIRECTION INPUT ;
    USE SIGNAL ;
    PORT
      LAYER M5 ;
        RECT  15.312 0 15.336 0.084 ;
    END
  END pdata[50]
  PIN pdata[510]
    DIRECTION INPUT ;
    USE SIGNAL ;
    PORT
      LAYER M5 ;
        RECT  134.736 0 134.76 0.084 ;
    END
  END pdata[510]
  PIN pdata[511]
    DIRECTION INPUT ;
    USE SIGNAL ;
    PORT
      LAYER M5 ;
        RECT  134.832 0 134.856 0.084 ;
    END
  END pdata[511]
  PIN pdata[51]
    DIRECTION INPUT ;
    USE SIGNAL ;
    PORT
      LAYER M5 ;
        RECT  15.408 0 15.432 0.084 ;
    END
  END pdata[51]
  PIN pdata[52]
    DIRECTION INPUT ;
    USE SIGNAL ;
    PORT
      LAYER M5 ;
        RECT  15.504 0 15.528 0.084 ;
    END
  END pdata[52]
  PIN pdata[53]
    DIRECTION INPUT ;
    USE SIGNAL ;
    PORT
      LAYER M5 ;
        RECT  15.6 0 15.624 0.084 ;
    END
  END pdata[53]
  PIN pdata[54]
    DIRECTION INPUT ;
    USE SIGNAL ;
    PORT
      LAYER M5 ;
        RECT  15.696 0 15.72 0.084 ;
    END
  END pdata[54]
  PIN pdata[55]
    DIRECTION INPUT ;
    USE SIGNAL ;
    PORT
      LAYER M5 ;
        RECT  15.792 0 15.816 0.084 ;
    END
  END pdata[55]
  PIN pdata[56]
    DIRECTION INPUT ;
    USE SIGNAL ;
    PORT
      LAYER M5 ;
        RECT  15.888 0 15.912 0.084 ;
    END
  END pdata[56]
  PIN pdata[57]
    DIRECTION INPUT ;
    USE SIGNAL ;
    PORT
      LAYER M5 ;
        RECT  15.984 0 16.008 0.084 ;
    END
  END pdata[57]
  PIN pdata[58]
    DIRECTION INPUT ;
    USE SIGNAL ;
    PORT
      LAYER M5 ;
        RECT  6.864 0 6.888 0.084 ;
    END
  END pdata[58]
  PIN pdata[59]
    DIRECTION INPUT ;
    USE SIGNAL ;
    PORT
      LAYER M5 ;
        RECT  6.96 0 6.984 0.084 ;
    END
  END pdata[59]
  PIN pdata[5]
    DIRECTION INPUT ;
    USE SIGNAL ;
    PORT
      LAYER M5 ;
        RECT  20.976 0 21 0.084 ;
    END
  END pdata[5]
  PIN pdata[60]
    DIRECTION INPUT ;
    USE SIGNAL ;
    PORT
      LAYER M5 ;
        RECT  7.056 0 7.08 0.084 ;
    END
  END pdata[60]
  PIN pdata[61]
    DIRECTION INPUT ;
    USE SIGNAL ;
    PORT
      LAYER M5 ;
        RECT  7.152 0 7.176 0.084 ;
    END
  END pdata[61]
  PIN pdata[62]
    DIRECTION INPUT ;
    USE SIGNAL ;
    PORT
      LAYER M5 ;
        RECT  7.248 0 7.272 0.084 ;
    END
  END pdata[62]
  PIN pdata[63]
    DIRECTION INPUT ;
    USE SIGNAL ;
    PORT
      LAYER M5 ;
        RECT  7.344 0 7.368 0.084 ;
    END
  END pdata[63]
  PIN pdata[64]
    DIRECTION INPUT ;
    USE SIGNAL ;
    PORT
      LAYER M5 ;
        RECT  7.44 0 7.464 0.084 ;
    END
  END pdata[64]
  PIN pdata[65]
    DIRECTION INPUT ;
    USE SIGNAL ;
    PORT
      LAYER M5 ;
        RECT  7.536 0 7.56 0.084 ;
    END
  END pdata[65]
  PIN pdata[66]
    DIRECTION INPUT ;
    USE SIGNAL ;
    PORT
      LAYER M5 ;
        RECT  7.632 0 7.656 0.084 ;
    END
  END pdata[66]
  PIN pdata[67]
    DIRECTION INPUT ;
    USE SIGNAL ;
    PORT
      LAYER M5 ;
        RECT  7.728 0 7.752 0.084 ;
    END
  END pdata[67]
  PIN pdata[68]
    DIRECTION INPUT ;
    USE SIGNAL ;
    PORT
      LAYER M5 ;
        RECT  7.824 0 7.848 0.084 ;
    END
  END pdata[68]
  PIN pdata[69]
    DIRECTION INPUT ;
    USE SIGNAL ;
    PORT
      LAYER M5 ;
        RECT  7.92 0 7.944 0.084 ;
    END
  END pdata[69]
  PIN pdata[6]
    DIRECTION INPUT ;
    USE SIGNAL ;
    PORT
      LAYER M5 ;
        RECT  21.072 0 21.096 0.084 ;
    END
  END pdata[6]
  PIN pdata[70]
    DIRECTION INPUT ;
    USE SIGNAL ;
    PORT
      LAYER M5 ;
        RECT  8.016 0 8.04 0.084 ;
    END
  END pdata[70]
  PIN pdata[71]
    DIRECTION INPUT ;
    USE SIGNAL ;
    PORT
      LAYER M5 ;
        RECT  8.112 0 8.136 0.084 ;
    END
  END pdata[71]
  PIN pdata[72]
    DIRECTION INPUT ;
    USE SIGNAL ;
    PORT
      LAYER M5 ;
        RECT  8.208 0 8.232 0.084 ;
    END
  END pdata[72]
  PIN pdata[73]
    DIRECTION INPUT ;
    USE SIGNAL ;
    PORT
      LAYER M5 ;
        RECT  8.304 0 8.328 0.084 ;
    END
  END pdata[73]
  PIN pdata[74]
    DIRECTION INPUT ;
    USE SIGNAL ;
    PORT
      LAYER M5 ;
        RECT  8.4 0 8.424 0.084 ;
    END
  END pdata[74]
  PIN pdata[75]
    DIRECTION INPUT ;
    USE SIGNAL ;
    PORT
      LAYER M5 ;
        RECT  8.496 0 8.52 0.084 ;
    END
  END pdata[75]
  PIN pdata[76]
    DIRECTION INPUT ;
    USE SIGNAL ;
    PORT
      LAYER M5 ;
        RECT  8.592 0 8.616 0.084 ;
    END
  END pdata[76]
  PIN pdata[77]
    DIRECTION INPUT ;
    USE SIGNAL ;
    PORT
      LAYER M5 ;
        RECT  8.688 0 8.712 0.084 ;
    END
  END pdata[77]
  PIN pdata[78]
    DIRECTION INPUT ;
    USE SIGNAL ;
    PORT
      LAYER M5 ;
        RECT  8.784 0 8.808 0.084 ;
    END
  END pdata[78]
  PIN pdata[79]
    DIRECTION INPUT ;
    USE SIGNAL ;
    PORT
      LAYER M5 ;
        RECT  8.88 0 8.904 0.084 ;
    END
  END pdata[79]
  PIN pdata[7]
    DIRECTION INPUT ;
    USE SIGNAL ;
    PORT
      LAYER M5 ;
        RECT  21.168 0 21.192 0.084 ;
    END
  END pdata[7]
  PIN pdata[80]
    DIRECTION INPUT ;
    USE SIGNAL ;
    PORT
      LAYER M5 ;
        RECT  8.976 0 9 0.084 ;
    END
  END pdata[80]
  PIN pdata[81]
    DIRECTION INPUT ;
    USE SIGNAL ;
    PORT
      LAYER M5 ;
        RECT  9.072 0 9.096 0.084 ;
    END
  END pdata[81]
  PIN pdata[82]
    DIRECTION INPUT ;
    USE SIGNAL ;
    PORT
      LAYER M5 ;
        RECT  9.168 0 9.192 0.084 ;
    END
  END pdata[82]
  PIN pdata[83]
    DIRECTION INPUT ;
    USE SIGNAL ;
    PORT
      LAYER M5 ;
        RECT  9.264 0 9.288 0.084 ;
    END
  END pdata[83]
  PIN pdata[84]
    DIRECTION INPUT ;
    USE SIGNAL ;
    PORT
      LAYER M5 ;
        RECT  9.36 0 9.384 0.084 ;
    END
  END pdata[84]
  PIN pdata[85]
    DIRECTION INPUT ;
    USE SIGNAL ;
    PORT
      LAYER M5 ;
        RECT  9.456 0 9.48 0.084 ;
    END
  END pdata[85]
  PIN pdata[86]
    DIRECTION INPUT ;
    USE SIGNAL ;
    PORT
      LAYER M5 ;
        RECT  9.552 0 9.576 0.084 ;
    END
  END pdata[86]
  PIN pdata[87]
    DIRECTION INPUT ;
    USE SIGNAL ;
    PORT
      LAYER M5 ;
        RECT  9.648 0 9.672 0.084 ;
    END
  END pdata[87]
  PIN pdata[88]
    DIRECTION INPUT ;
    USE SIGNAL ;
    PORT
      LAYER M5 ;
        RECT  9.744 0 9.768 0.084 ;
    END
  END pdata[88]
  PIN pdata[89]
    DIRECTION INPUT ;
    USE SIGNAL ;
    PORT
      LAYER M5 ;
        RECT  9.84 0 9.864 0.084 ;
    END
  END pdata[89]
  PIN pdata[8]
    DIRECTION INPUT ;
    USE SIGNAL ;
    PORT
      LAYER M5 ;
        RECT  21.264 0 21.288 0.084 ;
    END
  END pdata[8]
  PIN pdata[90]
    DIRECTION INPUT ;
    USE SIGNAL ;
    PORT
      LAYER M5 ;
        RECT  22.992 0 23.016 0.084 ;
    END
  END pdata[90]
  PIN pdata[91]
    DIRECTION INPUT ;
    USE SIGNAL ;
    PORT
      LAYER M5 ;
        RECT  23.088 0 23.112 0.084 ;
    END
  END pdata[91]
  PIN pdata[92]
    DIRECTION INPUT ;
    USE SIGNAL ;
    PORT
      LAYER M5 ;
        RECT  23.184 0 23.208 0.084 ;
    END
  END pdata[92]
  PIN pdata[93]
    DIRECTION INPUT ;
    USE SIGNAL ;
    PORT
      LAYER M5 ;
        RECT  23.28 0 23.304 0.084 ;
    END
  END pdata[93]
  PIN pdata[94]
    DIRECTION INPUT ;
    USE SIGNAL ;
    PORT
      LAYER M5 ;
        RECT  23.376 0 23.4 0.084 ;
    END
  END pdata[94]
  PIN pdata[95]
    DIRECTION INPUT ;
    USE SIGNAL ;
    PORT
      LAYER M5 ;
        RECT  23.472 0 23.496 0.084 ;
    END
  END pdata[95]
  PIN pdata[96]
    DIRECTION INPUT ;
    USE SIGNAL ;
    PORT
      LAYER M5 ;
        RECT  23.568 0 23.592 0.084 ;
    END
  END pdata[96]
  PIN pdata[97]
    DIRECTION INPUT ;
    USE SIGNAL ;
    PORT
      LAYER M5 ;
        RECT  23.664 0 23.688 0.084 ;
    END
  END pdata[97]
  PIN pdata[98]
    DIRECTION INPUT ;
    USE SIGNAL ;
    PORT
      LAYER M5 ;
        RECT  23.76 0 23.784 0.084 ;
    END
  END pdata[98]
  PIN pdata[99]
    DIRECTION INPUT ;
    USE SIGNAL ;
    PORT
      LAYER M5 ;
        RECT  23.856 0 23.88 0.084 ;
    END
  END pdata[99]
  PIN pdata[9]
    DIRECTION INPUT ;
    USE SIGNAL ;
    PORT
      LAYER M5 ;
        RECT  21.36 0 21.384 0.084 ;
    END
  END pdata[9]
  PIN pgi
    DIRECTION INPUT ;
    USE SIGNAL ;
    PORT
      LAYER M5 ;
        RECT  134.928 0 134.952 0.084 ;
    END
  END pgi
  PIN pv
    DIRECTION INPUT ;
    USE SIGNAL ;
    PORT
      LAYER M5 ;
        RECT  135.024 0 135.048 0.084 ;
    END
  END pv
  PIN ra[0]
    DIRECTION INPUT ;
    USE SIGNAL ;
    PORT
      LAYER M4 ;
        RECT  0 80.688 0.084 80.712 ;
    END
  END ra[0]
  PIN ra[1]
    DIRECTION INPUT ;
    USE SIGNAL ;
    PORT
      LAYER M4 ;
        RECT  0 80.784 0.084 80.808 ;
    END
  END ra[1]
  PIN ra[2]
    DIRECTION INPUT ;
    USE SIGNAL ;
    PORT
      LAYER M4 ;
        RECT  0 80.88 0.084 80.904 ;
    END
  END ra[2]
  PIN ra[3]
    DIRECTION INPUT ;
    USE SIGNAL ;
    PORT
      LAYER M4 ;
        RECT  0 80.976 0.084 81 ;
    END
  END ra[3]
  PIN ra[4]
    DIRECTION INPUT ;
    USE SIGNAL ;
    PORT
      LAYER M4 ;
        RECT  0 81.072 0.084 81.096 ;
    END
  END ra[4]
  PIN ra[5]
    DIRECTION INPUT ;
    USE SIGNAL ;
    PORT
      LAYER M4 ;
        RECT  0 81.168 0.084 81.192 ;
    END
  END ra[5]
  PIN rst_n
    DIRECTION INPUT ;
    USE SIGNAL ;
    PORT
      LAYER M4 ;
        RECT  0 81.264 0.084 81.288 ;
    END
  END rst_n
  PIN sr[0]
    DIRECTION OUTPUT ;
    USE SIGNAL ;
    PORT
      LAYER M5 ;
        RECT  32.208 151.116 32.232 151.2 ;
    END
  END sr[0]
  PIN sr[100]
    DIRECTION OUTPUT ;
    USE SIGNAL ;
    PORT
      LAYER M5 ;
        RECT  23.376 151.116 23.4 151.2 ;
    END
  END sr[100]
  PIN sr[101]
    DIRECTION OUTPUT ;
    USE SIGNAL ;
    PORT
      LAYER M5 ;
        RECT  23.472 151.116 23.496 151.2 ;
    END
  END sr[101]
  PIN sr[102]
    DIRECTION OUTPUT ;
    USE SIGNAL ;
    PORT
      LAYER M5 ;
        RECT  23.568 151.116 23.592 151.2 ;
    END
  END sr[102]
  PIN sr[103]
    DIRECTION OUTPUT ;
    USE SIGNAL ;
    PORT
      LAYER M5 ;
        RECT  23.664 151.116 23.688 151.2 ;
    END
  END sr[103]
  PIN sr[104]
    DIRECTION OUTPUT ;
    USE SIGNAL ;
    PORT
      LAYER M5 ;
        RECT  23.76 151.116 23.784 151.2 ;
    END
  END sr[104]
  PIN sr[105]
    DIRECTION OUTPUT ;
    USE SIGNAL ;
    PORT
      LAYER M5 ;
        RECT  23.856 151.116 23.88 151.2 ;
    END
  END sr[105]
  PIN sr[106]
    DIRECTION OUTPUT ;
    USE SIGNAL ;
    PORT
      LAYER M5 ;
        RECT  23.952 151.116 23.976 151.2 ;
    END
  END sr[106]
  PIN sr[107]
    DIRECTION OUTPUT ;
    USE SIGNAL ;
    PORT
      LAYER M5 ;
        RECT  24.048 151.116 24.072 151.2 ;
    END
  END sr[107]
  PIN sr[108]
    DIRECTION OUTPUT ;
    USE SIGNAL ;
    PORT
      LAYER M5 ;
        RECT  24.144 151.116 24.168 151.2 ;
    END
  END sr[108]
  PIN sr[109]
    DIRECTION OUTPUT ;
    USE SIGNAL ;
    PORT
      LAYER M5 ;
        RECT  24.24 151.116 24.264 151.2 ;
    END
  END sr[109]
  PIN sr[10]
    DIRECTION OUTPUT ;
    USE SIGNAL ;
    PORT
      LAYER M5 ;
        RECT  33.168 151.116 33.192 151.2 ;
    END
  END sr[10]
  PIN sr[110]
    DIRECTION OUTPUT ;
    USE SIGNAL ;
    PORT
      LAYER M5 ;
        RECT  24.336 151.116 24.36 151.2 ;
    END
  END sr[110]
  PIN sr[111]
    DIRECTION OUTPUT ;
    USE SIGNAL ;
    PORT
      LAYER M5 ;
        RECT  24.432 151.116 24.456 151.2 ;
    END
  END sr[111]
  PIN sr[112]
    DIRECTION OUTPUT ;
    USE SIGNAL ;
    PORT
      LAYER M5 ;
        RECT  24.528 151.116 24.552 151.2 ;
    END
  END sr[112]
  PIN sr[113]
    DIRECTION OUTPUT ;
    USE SIGNAL ;
    PORT
      LAYER M5 ;
        RECT  24.624 151.116 24.648 151.2 ;
    END
  END sr[113]
  PIN sr[114]
    DIRECTION OUTPUT ;
    USE SIGNAL ;
    PORT
      LAYER M5 ;
        RECT  24.72 151.116 24.744 151.2 ;
    END
  END sr[114]
  PIN sr[115]
    DIRECTION OUTPUT ;
    USE SIGNAL ;
    PORT
      LAYER M5 ;
        RECT  24.816 151.116 24.84 151.2 ;
    END
  END sr[115]
  PIN sr[116]
    DIRECTION OUTPUT ;
    USE SIGNAL ;
    PORT
      LAYER M5 ;
        RECT  24.912 151.116 24.936 151.2 ;
    END
  END sr[116]
  PIN sr[117]
    DIRECTION OUTPUT ;
    USE SIGNAL ;
    PORT
      LAYER M5 ;
        RECT  25.008 151.116 25.032 151.2 ;
    END
  END sr[117]
  PIN sr[118]
    DIRECTION OUTPUT ;
    USE SIGNAL ;
    PORT
      LAYER M5 ;
        RECT  25.104 151.116 25.128 151.2 ;
    END
  END sr[118]
  PIN sr[119]
    DIRECTION OUTPUT ;
    USE SIGNAL ;
    PORT
      LAYER M5 ;
        RECT  25.2 151.116 25.224 151.2 ;
    END
  END sr[119]
  PIN sr[11]
    DIRECTION OUTPUT ;
    USE SIGNAL ;
    PORT
      LAYER M5 ;
        RECT  33.264 151.116 33.288 151.2 ;
    END
  END sr[11]
  PIN sr[120]
    DIRECTION OUTPUT ;
    USE SIGNAL ;
    PORT
      LAYER M5 ;
        RECT  25.296 151.116 25.32 151.2 ;
    END
  END sr[120]
  PIN sr[121]
    DIRECTION OUTPUT ;
    USE SIGNAL ;
    PORT
      LAYER M5 ;
        RECT  25.392 151.116 25.416 151.2 ;
    END
  END sr[121]
  PIN sr[122]
    DIRECTION OUTPUT ;
    USE SIGNAL ;
    PORT
      LAYER M5 ;
        RECT  25.488 151.116 25.512 151.2 ;
    END
  END sr[122]
  PIN sr[123]
    DIRECTION OUTPUT ;
    USE SIGNAL ;
    PORT
      LAYER M5 ;
        RECT  25.584 151.116 25.608 151.2 ;
    END
  END sr[123]
  PIN sr[124]
    DIRECTION OUTPUT ;
    USE SIGNAL ;
    PORT
      LAYER M5 ;
        RECT  25.68 151.116 25.704 151.2 ;
    END
  END sr[124]
  PIN sr[125]
    DIRECTION OUTPUT ;
    USE SIGNAL ;
    PORT
      LAYER M5 ;
        RECT  25.776 151.116 25.8 151.2 ;
    END
  END sr[125]
  PIN sr[126]
    DIRECTION OUTPUT ;
    USE SIGNAL ;
    PORT
      LAYER M5 ;
        RECT  25.872 151.116 25.896 151.2 ;
    END
  END sr[126]
  PIN sr[127]
    DIRECTION OUTPUT ;
    USE SIGNAL ;
    PORT
      LAYER M5 ;
        RECT  25.968 151.116 25.992 151.2 ;
    END
  END sr[127]
  PIN sr[128]
    DIRECTION OUTPUT ;
    USE SIGNAL ;
    PORT
      LAYER M5 ;
        RECT  16.848 151.116 16.872 151.2 ;
    END
  END sr[128]
  PIN sr[129]
    DIRECTION OUTPUT ;
    USE SIGNAL ;
    PORT
      LAYER M5 ;
        RECT  16.944 151.116 16.968 151.2 ;
    END
  END sr[129]
  PIN sr[12]
    DIRECTION OUTPUT ;
    USE SIGNAL ;
    PORT
      LAYER M5 ;
        RECT  33.36 151.116 33.384 151.2 ;
    END
  END sr[12]
  PIN sr[130]
    DIRECTION OUTPUT ;
    USE SIGNAL ;
    PORT
      LAYER M5 ;
        RECT  17.04 151.116 17.064 151.2 ;
    END
  END sr[130]
  PIN sr[131]
    DIRECTION OUTPUT ;
    USE SIGNAL ;
    PORT
      LAYER M5 ;
        RECT  17.136 151.116 17.16 151.2 ;
    END
  END sr[131]
  PIN sr[132]
    DIRECTION OUTPUT ;
    USE SIGNAL ;
    PORT
      LAYER M5 ;
        RECT  17.232 151.116 17.256 151.2 ;
    END
  END sr[132]
  PIN sr[133]
    DIRECTION OUTPUT ;
    USE SIGNAL ;
    PORT
      LAYER M5 ;
        RECT  17.328 151.116 17.352 151.2 ;
    END
  END sr[133]
  PIN sr[134]
    DIRECTION OUTPUT ;
    USE SIGNAL ;
    PORT
      LAYER M5 ;
        RECT  17.424 151.116 17.448 151.2 ;
    END
  END sr[134]
  PIN sr[135]
    DIRECTION OUTPUT ;
    USE SIGNAL ;
    PORT
      LAYER M5 ;
        RECT  17.52 151.116 17.544 151.2 ;
    END
  END sr[135]
  PIN sr[136]
    DIRECTION OUTPUT ;
    USE SIGNAL ;
    PORT
      LAYER M5 ;
        RECT  17.616 151.116 17.64 151.2 ;
    END
  END sr[136]
  PIN sr[137]
    DIRECTION OUTPUT ;
    USE SIGNAL ;
    PORT
      LAYER M5 ;
        RECT  17.712 151.116 17.736 151.2 ;
    END
  END sr[137]
  PIN sr[138]
    DIRECTION OUTPUT ;
    USE SIGNAL ;
    PORT
      LAYER M5 ;
        RECT  17.808 151.116 17.832 151.2 ;
    END
  END sr[138]
  PIN sr[139]
    DIRECTION OUTPUT ;
    USE SIGNAL ;
    PORT
      LAYER M5 ;
        RECT  17.904 151.116 17.928 151.2 ;
    END
  END sr[139]
  PIN sr[13]
    DIRECTION OUTPUT ;
    USE SIGNAL ;
    PORT
      LAYER M5 ;
        RECT  33.456 151.116 33.48 151.2 ;
    END
  END sr[13]
  PIN sr[140]
    DIRECTION OUTPUT ;
    USE SIGNAL ;
    PORT
      LAYER M5 ;
        RECT  18 151.116 18.024 151.2 ;
    END
  END sr[140]
  PIN sr[141]
    DIRECTION OUTPUT ;
    USE SIGNAL ;
    PORT
      LAYER M5 ;
        RECT  18.096 151.116 18.12 151.2 ;
    END
  END sr[141]
  PIN sr[142]
    DIRECTION OUTPUT ;
    USE SIGNAL ;
    PORT
      LAYER M5 ;
        RECT  18.192 151.116 18.216 151.2 ;
    END
  END sr[142]
  PIN sr[143]
    DIRECTION OUTPUT ;
    USE SIGNAL ;
    PORT
      LAYER M5 ;
        RECT  18.288 151.116 18.312 151.2 ;
    END
  END sr[143]
  PIN sr[144]
    DIRECTION OUTPUT ;
    USE SIGNAL ;
    PORT
      LAYER M5 ;
        RECT  18.384 151.116 18.408 151.2 ;
    END
  END sr[144]
  PIN sr[145]
    DIRECTION OUTPUT ;
    USE SIGNAL ;
    PORT
      LAYER M5 ;
        RECT  18.48 151.116 18.504 151.2 ;
    END
  END sr[145]
  PIN sr[146]
    DIRECTION OUTPUT ;
    USE SIGNAL ;
    PORT
      LAYER M5 ;
        RECT  18.576 151.116 18.6 151.2 ;
    END
  END sr[146]
  PIN sr[147]
    DIRECTION OUTPUT ;
    USE SIGNAL ;
    PORT
      LAYER M5 ;
        RECT  18.672 151.116 18.696 151.2 ;
    END
  END sr[147]
  PIN sr[148]
    DIRECTION OUTPUT ;
    USE SIGNAL ;
    PORT
      LAYER M5 ;
        RECT  18.768 151.116 18.792 151.2 ;
    END
  END sr[148]
  PIN sr[149]
    DIRECTION OUTPUT ;
    USE SIGNAL ;
    PORT
      LAYER M5 ;
        RECT  18.864 151.116 18.888 151.2 ;
    END
  END sr[149]
  PIN sr[14]
    DIRECTION OUTPUT ;
    USE SIGNAL ;
    PORT
      LAYER M5 ;
        RECT  33.552 151.116 33.576 151.2 ;
    END
  END sr[14]
  PIN sr[150]
    DIRECTION OUTPUT ;
    USE SIGNAL ;
    PORT
      LAYER M5 ;
        RECT  18.96 151.116 18.984 151.2 ;
    END
  END sr[150]
  PIN sr[151]
    DIRECTION OUTPUT ;
    USE SIGNAL ;
    PORT
      LAYER M5 ;
        RECT  19.056 151.116 19.08 151.2 ;
    END
  END sr[151]
  PIN sr[152]
    DIRECTION OUTPUT ;
    USE SIGNAL ;
    PORT
      LAYER M5 ;
        RECT  19.152 151.116 19.176 151.2 ;
    END
  END sr[152]
  PIN sr[153]
    DIRECTION OUTPUT ;
    USE SIGNAL ;
    PORT
      LAYER M5 ;
        RECT  19.248 151.116 19.272 151.2 ;
    END
  END sr[153]
  PIN sr[154]
    DIRECTION OUTPUT ;
    USE SIGNAL ;
    PORT
      LAYER M5 ;
        RECT  19.344 151.116 19.368 151.2 ;
    END
  END sr[154]
  PIN sr[155]
    DIRECTION OUTPUT ;
    USE SIGNAL ;
    PORT
      LAYER M5 ;
        RECT  19.44 151.116 19.464 151.2 ;
    END
  END sr[155]
  PIN sr[156]
    DIRECTION OUTPUT ;
    USE SIGNAL ;
    PORT
      LAYER M5 ;
        RECT  19.536 151.116 19.56 151.2 ;
    END
  END sr[156]
  PIN sr[157]
    DIRECTION OUTPUT ;
    USE SIGNAL ;
    PORT
      LAYER M5 ;
        RECT  19.632 151.116 19.656 151.2 ;
    END
  END sr[157]
  PIN sr[158]
    DIRECTION OUTPUT ;
    USE SIGNAL ;
    PORT
      LAYER M5 ;
        RECT  19.728 151.116 19.752 151.2 ;
    END
  END sr[158]
  PIN sr[159]
    DIRECTION OUTPUT ;
    USE SIGNAL ;
    PORT
      LAYER M5 ;
        RECT  19.824 151.116 19.848 151.2 ;
    END
  END sr[159]
  PIN sr[15]
    DIRECTION OUTPUT ;
    USE SIGNAL ;
    PORT
      LAYER M5 ;
        RECT  33.648 151.116 33.672 151.2 ;
    END
  END sr[15]
  PIN sr[160]
    DIRECTION OUTPUT ;
    USE SIGNAL ;
    PORT
      LAYER M5 ;
        RECT  26.064 151.116 26.088 151.2 ;
    END
  END sr[160]
  PIN sr[161]
    DIRECTION OUTPUT ;
    USE SIGNAL ;
    PORT
      LAYER M5 ;
        RECT  26.16 151.116 26.184 151.2 ;
    END
  END sr[161]
  PIN sr[162]
    DIRECTION OUTPUT ;
    USE SIGNAL ;
    PORT
      LAYER M5 ;
        RECT  26.256 151.116 26.28 151.2 ;
    END
  END sr[162]
  PIN sr[163]
    DIRECTION OUTPUT ;
    USE SIGNAL ;
    PORT
      LAYER M5 ;
        RECT  26.352 151.116 26.376 151.2 ;
    END
  END sr[163]
  PIN sr[164]
    DIRECTION OUTPUT ;
    USE SIGNAL ;
    PORT
      LAYER M5 ;
        RECT  26.448 151.116 26.472 151.2 ;
    END
  END sr[164]
  PIN sr[165]
    DIRECTION OUTPUT ;
    USE SIGNAL ;
    PORT
      LAYER M5 ;
        RECT  26.544 151.116 26.568 151.2 ;
    END
  END sr[165]
  PIN sr[166]
    DIRECTION OUTPUT ;
    USE SIGNAL ;
    PORT
      LAYER M5 ;
        RECT  26.64 151.116 26.664 151.2 ;
    END
  END sr[166]
  PIN sr[167]
    DIRECTION OUTPUT ;
    USE SIGNAL ;
    PORT
      LAYER M5 ;
        RECT  26.736 151.116 26.76 151.2 ;
    END
  END sr[167]
  PIN sr[168]
    DIRECTION OUTPUT ;
    USE SIGNAL ;
    PORT
      LAYER M5 ;
        RECT  26.832 151.116 26.856 151.2 ;
    END
  END sr[168]
  PIN sr[169]
    DIRECTION OUTPUT ;
    USE SIGNAL ;
    PORT
      LAYER M5 ;
        RECT  26.928 151.116 26.952 151.2 ;
    END
  END sr[169]
  PIN sr[16]
    DIRECTION OUTPUT ;
    USE SIGNAL ;
    PORT
      LAYER M5 ;
        RECT  33.744 151.116 33.768 151.2 ;
    END
  END sr[16]
  PIN sr[170]
    DIRECTION OUTPUT ;
    USE SIGNAL ;
    PORT
      LAYER M5 ;
        RECT  27.024 151.116 27.048 151.2 ;
    END
  END sr[170]
  PIN sr[171]
    DIRECTION OUTPUT ;
    USE SIGNAL ;
    PORT
      LAYER M5 ;
        RECT  27.12 151.116 27.144 151.2 ;
    END
  END sr[171]
  PIN sr[172]
    DIRECTION OUTPUT ;
    USE SIGNAL ;
    PORT
      LAYER M5 ;
        RECT  27.216 151.116 27.24 151.2 ;
    END
  END sr[172]
  PIN sr[173]
    DIRECTION OUTPUT ;
    USE SIGNAL ;
    PORT
      LAYER M5 ;
        RECT  27.312 151.116 27.336 151.2 ;
    END
  END sr[173]
  PIN sr[174]
    DIRECTION OUTPUT ;
    USE SIGNAL ;
    PORT
      LAYER M5 ;
        RECT  27.408 151.116 27.432 151.2 ;
    END
  END sr[174]
  PIN sr[175]
    DIRECTION OUTPUT ;
    USE SIGNAL ;
    PORT
      LAYER M5 ;
        RECT  27.504 151.116 27.528 151.2 ;
    END
  END sr[175]
  PIN sr[176]
    DIRECTION OUTPUT ;
    USE SIGNAL ;
    PORT
      LAYER M5 ;
        RECT  27.6 151.116 27.624 151.2 ;
    END
  END sr[176]
  PIN sr[177]
    DIRECTION OUTPUT ;
    USE SIGNAL ;
    PORT
      LAYER M5 ;
        RECT  27.696 151.116 27.72 151.2 ;
    END
  END sr[177]
  PIN sr[178]
    DIRECTION OUTPUT ;
    USE SIGNAL ;
    PORT
      LAYER M5 ;
        RECT  27.792 151.116 27.816 151.2 ;
    END
  END sr[178]
  PIN sr[179]
    DIRECTION OUTPUT ;
    USE SIGNAL ;
    PORT
      LAYER M5 ;
        RECT  27.888 151.116 27.912 151.2 ;
    END
  END sr[179]
  PIN sr[17]
    DIRECTION OUTPUT ;
    USE SIGNAL ;
    PORT
      LAYER M5 ;
        RECT  33.84 151.116 33.864 151.2 ;
    END
  END sr[17]
  PIN sr[180]
    DIRECTION OUTPUT ;
    USE SIGNAL ;
    PORT
      LAYER M5 ;
        RECT  27.984 151.116 28.008 151.2 ;
    END
  END sr[180]
  PIN sr[181]
    DIRECTION OUTPUT ;
    USE SIGNAL ;
    PORT
      LAYER M5 ;
        RECT  28.08 151.116 28.104 151.2 ;
    END
  END sr[181]
  PIN sr[182]
    DIRECTION OUTPUT ;
    USE SIGNAL ;
    PORT
      LAYER M5 ;
        RECT  28.176 151.116 28.2 151.2 ;
    END
  END sr[182]
  PIN sr[183]
    DIRECTION OUTPUT ;
    USE SIGNAL ;
    PORT
      LAYER M5 ;
        RECT  28.272 151.116 28.296 151.2 ;
    END
  END sr[183]
  PIN sr[184]
    DIRECTION OUTPUT ;
    USE SIGNAL ;
    PORT
      LAYER M5 ;
        RECT  28.368 151.116 28.392 151.2 ;
    END
  END sr[184]
  PIN sr[185]
    DIRECTION OUTPUT ;
    USE SIGNAL ;
    PORT
      LAYER M5 ;
        RECT  28.464 151.116 28.488 151.2 ;
    END
  END sr[185]
  PIN sr[186]
    DIRECTION OUTPUT ;
    USE SIGNAL ;
    PORT
      LAYER M5 ;
        RECT  28.56 151.116 28.584 151.2 ;
    END
  END sr[186]
  PIN sr[187]
    DIRECTION OUTPUT ;
    USE SIGNAL ;
    PORT
      LAYER M5 ;
        RECT  28.656 151.116 28.68 151.2 ;
    END
  END sr[187]
  PIN sr[188]
    DIRECTION OUTPUT ;
    USE SIGNAL ;
    PORT
      LAYER M5 ;
        RECT  28.752 151.116 28.776 151.2 ;
    END
  END sr[188]
  PIN sr[189]
    DIRECTION OUTPUT ;
    USE SIGNAL ;
    PORT
      LAYER M5 ;
        RECT  28.848 151.116 28.872 151.2 ;
    END
  END sr[189]
  PIN sr[18]
    DIRECTION OUTPUT ;
    USE SIGNAL ;
    PORT
      LAYER M5 ;
        RECT  33.936 151.116 33.96 151.2 ;
    END
  END sr[18]
  PIN sr[190]
    DIRECTION OUTPUT ;
    USE SIGNAL ;
    PORT
      LAYER M5 ;
        RECT  28.944 151.116 28.968 151.2 ;
    END
  END sr[190]
  PIN sr[191]
    DIRECTION OUTPUT ;
    USE SIGNAL ;
    PORT
      LAYER M5 ;
        RECT  29.04 151.116 29.064 151.2 ;
    END
  END sr[191]
  PIN sr[192]
    DIRECTION OUTPUT ;
    USE SIGNAL ;
    PORT
      LAYER M5 ;
        RECT  13.008 151.116 13.032 151.2 ;
    END
  END sr[192]
  PIN sr[193]
    DIRECTION OUTPUT ;
    USE SIGNAL ;
    PORT
      LAYER M5 ;
        RECT  13.104 151.116 13.128 151.2 ;
    END
  END sr[193]
  PIN sr[194]
    DIRECTION OUTPUT ;
    USE SIGNAL ;
    PORT
      LAYER M5 ;
        RECT  13.2 151.116 13.224 151.2 ;
    END
  END sr[194]
  PIN sr[195]
    DIRECTION OUTPUT ;
    USE SIGNAL ;
    PORT
      LAYER M5 ;
        RECT  13.296 151.116 13.32 151.2 ;
    END
  END sr[195]
  PIN sr[196]
    DIRECTION OUTPUT ;
    USE SIGNAL ;
    PORT
      LAYER M5 ;
        RECT  13.392 151.116 13.416 151.2 ;
    END
  END sr[196]
  PIN sr[197]
    DIRECTION OUTPUT ;
    USE SIGNAL ;
    PORT
      LAYER M5 ;
        RECT  13.488 151.116 13.512 151.2 ;
    END
  END sr[197]
  PIN sr[198]
    DIRECTION OUTPUT ;
    USE SIGNAL ;
    PORT
      LAYER M5 ;
        RECT  13.584 151.116 13.608 151.2 ;
    END
  END sr[198]
  PIN sr[199]
    DIRECTION OUTPUT ;
    USE SIGNAL ;
    PORT
      LAYER M5 ;
        RECT  13.68 151.116 13.704 151.2 ;
    END
  END sr[199]
  PIN sr[19]
    DIRECTION OUTPUT ;
    USE SIGNAL ;
    PORT
      LAYER M5 ;
        RECT  34.032 151.116 34.056 151.2 ;
    END
  END sr[19]
  PIN sr[1]
    DIRECTION OUTPUT ;
    USE SIGNAL ;
    PORT
      LAYER M5 ;
        RECT  32.304 151.116 32.328 151.2 ;
    END
  END sr[1]
  PIN sr[200]
    DIRECTION OUTPUT ;
    USE SIGNAL ;
    PORT
      LAYER M5 ;
        RECT  13.776 151.116 13.8 151.2 ;
    END
  END sr[200]
  PIN sr[201]
    DIRECTION OUTPUT ;
    USE SIGNAL ;
    PORT
      LAYER M5 ;
        RECT  13.872 151.116 13.896 151.2 ;
    END
  END sr[201]
  PIN sr[202]
    DIRECTION OUTPUT ;
    USE SIGNAL ;
    PORT
      LAYER M5 ;
        RECT  13.968 151.116 13.992 151.2 ;
    END
  END sr[202]
  PIN sr[203]
    DIRECTION OUTPUT ;
    USE SIGNAL ;
    PORT
      LAYER M5 ;
        RECT  14.064 151.116 14.088 151.2 ;
    END
  END sr[203]
  PIN sr[204]
    DIRECTION OUTPUT ;
    USE SIGNAL ;
    PORT
      LAYER M5 ;
        RECT  14.16 151.116 14.184 151.2 ;
    END
  END sr[204]
  PIN sr[205]
    DIRECTION OUTPUT ;
    USE SIGNAL ;
    PORT
      LAYER M5 ;
        RECT  14.256 151.116 14.28 151.2 ;
    END
  END sr[205]
  PIN sr[206]
    DIRECTION OUTPUT ;
    USE SIGNAL ;
    PORT
      LAYER M5 ;
        RECT  14.352 151.116 14.376 151.2 ;
    END
  END sr[206]
  PIN sr[207]
    DIRECTION OUTPUT ;
    USE SIGNAL ;
    PORT
      LAYER M5 ;
        RECT  14.448 151.116 14.472 151.2 ;
    END
  END sr[207]
  PIN sr[208]
    DIRECTION OUTPUT ;
    USE SIGNAL ;
    PORT
      LAYER M5 ;
        RECT  14.544 151.116 14.568 151.2 ;
    END
  END sr[208]
  PIN sr[209]
    DIRECTION OUTPUT ;
    USE SIGNAL ;
    PORT
      LAYER M5 ;
        RECT  14.64 151.116 14.664 151.2 ;
    END
  END sr[209]
  PIN sr[20]
    DIRECTION OUTPUT ;
    USE SIGNAL ;
    PORT
      LAYER M5 ;
        RECT  34.128 151.116 34.152 151.2 ;
    END
  END sr[20]
  PIN sr[210]
    DIRECTION OUTPUT ;
    USE SIGNAL ;
    PORT
      LAYER M5 ;
        RECT  14.736 151.116 14.76 151.2 ;
    END
  END sr[210]
  PIN sr[211]
    DIRECTION OUTPUT ;
    USE SIGNAL ;
    PORT
      LAYER M5 ;
        RECT  14.832 151.116 14.856 151.2 ;
    END
  END sr[211]
  PIN sr[212]
    DIRECTION OUTPUT ;
    USE SIGNAL ;
    PORT
      LAYER M5 ;
        RECT  14.928 151.116 14.952 151.2 ;
    END
  END sr[212]
  PIN sr[213]
    DIRECTION OUTPUT ;
    USE SIGNAL ;
    PORT
      LAYER M5 ;
        RECT  15.024 151.116 15.048 151.2 ;
    END
  END sr[213]
  PIN sr[214]
    DIRECTION OUTPUT ;
    USE SIGNAL ;
    PORT
      LAYER M5 ;
        RECT  15.12 151.116 15.144 151.2 ;
    END
  END sr[214]
  PIN sr[215]
    DIRECTION OUTPUT ;
    USE SIGNAL ;
    PORT
      LAYER M5 ;
        RECT  15.216 151.116 15.24 151.2 ;
    END
  END sr[215]
  PIN sr[216]
    DIRECTION OUTPUT ;
    USE SIGNAL ;
    PORT
      LAYER M5 ;
        RECT  15.312 151.116 15.336 151.2 ;
    END
  END sr[216]
  PIN sr[217]
    DIRECTION OUTPUT ;
    USE SIGNAL ;
    PORT
      LAYER M5 ;
        RECT  15.408 151.116 15.432 151.2 ;
    END
  END sr[217]
  PIN sr[218]
    DIRECTION OUTPUT ;
    USE SIGNAL ;
    PORT
      LAYER M5 ;
        RECT  15.504 151.116 15.528 151.2 ;
    END
  END sr[218]
  PIN sr[219]
    DIRECTION OUTPUT ;
    USE SIGNAL ;
    PORT
      LAYER M5 ;
        RECT  15.6 151.116 15.624 151.2 ;
    END
  END sr[219]
  PIN sr[21]
    DIRECTION OUTPUT ;
    USE SIGNAL ;
    PORT
      LAYER M5 ;
        RECT  34.224 151.116 34.248 151.2 ;
    END
  END sr[21]
  PIN sr[220]
    DIRECTION OUTPUT ;
    USE SIGNAL ;
    PORT
      LAYER M5 ;
        RECT  15.696 151.116 15.72 151.2 ;
    END
  END sr[220]
  PIN sr[221]
    DIRECTION OUTPUT ;
    USE SIGNAL ;
    PORT
      LAYER M5 ;
        RECT  15.792 151.116 15.816 151.2 ;
    END
  END sr[221]
  PIN sr[222]
    DIRECTION OUTPUT ;
    USE SIGNAL ;
    PORT
      LAYER M5 ;
        RECT  15.888 151.116 15.912 151.2 ;
    END
  END sr[222]
  PIN sr[223]
    DIRECTION OUTPUT ;
    USE SIGNAL ;
    PORT
      LAYER M5 ;
        RECT  15.984 151.116 16.008 151.2 ;
    END
  END sr[223]
  PIN sr[224]
    DIRECTION OUTPUT ;
    USE SIGNAL ;
    PORT
      LAYER M5 ;
        RECT  9.936 151.116 9.96 151.2 ;
    END
  END sr[224]
  PIN sr[225]
    DIRECTION OUTPUT ;
    USE SIGNAL ;
    PORT
      LAYER M5 ;
        RECT  10.032 151.116 10.056 151.2 ;
    END
  END sr[225]
  PIN sr[226]
    DIRECTION OUTPUT ;
    USE SIGNAL ;
    PORT
      LAYER M5 ;
        RECT  10.128 151.116 10.152 151.2 ;
    END
  END sr[226]
  PIN sr[227]
    DIRECTION OUTPUT ;
    USE SIGNAL ;
    PORT
      LAYER M5 ;
        RECT  10.224 151.116 10.248 151.2 ;
    END
  END sr[227]
  PIN sr[228]
    DIRECTION OUTPUT ;
    USE SIGNAL ;
    PORT
      LAYER M5 ;
        RECT  10.32 151.116 10.344 151.2 ;
    END
  END sr[228]
  PIN sr[229]
    DIRECTION OUTPUT ;
    USE SIGNAL ;
    PORT
      LAYER M5 ;
        RECT  10.416 151.116 10.44 151.2 ;
    END
  END sr[229]
  PIN sr[22]
    DIRECTION OUTPUT ;
    USE SIGNAL ;
    PORT
      LAYER M5 ;
        RECT  34.32 151.116 34.344 151.2 ;
    END
  END sr[22]
  PIN sr[230]
    DIRECTION OUTPUT ;
    USE SIGNAL ;
    PORT
      LAYER M5 ;
        RECT  10.512 151.116 10.536 151.2 ;
    END
  END sr[230]
  PIN sr[231]
    DIRECTION OUTPUT ;
    USE SIGNAL ;
    PORT
      LAYER M5 ;
        RECT  10.608 151.116 10.632 151.2 ;
    END
  END sr[231]
  PIN sr[232]
    DIRECTION OUTPUT ;
    USE SIGNAL ;
    PORT
      LAYER M5 ;
        RECT  10.704 151.116 10.728 151.2 ;
    END
  END sr[232]
  PIN sr[233]
    DIRECTION OUTPUT ;
    USE SIGNAL ;
    PORT
      LAYER M5 ;
        RECT  10.8 151.116 10.824 151.2 ;
    END
  END sr[233]
  PIN sr[234]
    DIRECTION OUTPUT ;
    USE SIGNAL ;
    PORT
      LAYER M5 ;
        RECT  10.896 151.116 10.92 151.2 ;
    END
  END sr[234]
  PIN sr[235]
    DIRECTION OUTPUT ;
    USE SIGNAL ;
    PORT
      LAYER M5 ;
        RECT  10.992 151.116 11.016 151.2 ;
    END
  END sr[235]
  PIN sr[236]
    DIRECTION OUTPUT ;
    USE SIGNAL ;
    PORT
      LAYER M5 ;
        RECT  11.088 151.116 11.112 151.2 ;
    END
  END sr[236]
  PIN sr[237]
    DIRECTION OUTPUT ;
    USE SIGNAL ;
    PORT
      LAYER M5 ;
        RECT  11.184 151.116 11.208 151.2 ;
    END
  END sr[237]
  PIN sr[238]
    DIRECTION OUTPUT ;
    USE SIGNAL ;
    PORT
      LAYER M5 ;
        RECT  11.28 151.116 11.304 151.2 ;
    END
  END sr[238]
  PIN sr[239]
    DIRECTION OUTPUT ;
    USE SIGNAL ;
    PORT
      LAYER M5 ;
        RECT  11.376 151.116 11.4 151.2 ;
    END
  END sr[239]
  PIN sr[23]
    DIRECTION OUTPUT ;
    USE SIGNAL ;
    PORT
      LAYER M5 ;
        RECT  34.416 151.116 34.44 151.2 ;
    END
  END sr[23]
  PIN sr[240]
    DIRECTION OUTPUT ;
    USE SIGNAL ;
    PORT
      LAYER M5 ;
        RECT  11.472 151.116 11.496 151.2 ;
    END
  END sr[240]
  PIN sr[241]
    DIRECTION OUTPUT ;
    USE SIGNAL ;
    PORT
      LAYER M5 ;
        RECT  11.568 151.116 11.592 151.2 ;
    END
  END sr[241]
  PIN sr[242]
    DIRECTION OUTPUT ;
    USE SIGNAL ;
    PORT
      LAYER M5 ;
        RECT  11.664 151.116 11.688 151.2 ;
    END
  END sr[242]
  PIN sr[243]
    DIRECTION OUTPUT ;
    USE SIGNAL ;
    PORT
      LAYER M5 ;
        RECT  11.76 151.116 11.784 151.2 ;
    END
  END sr[243]
  PIN sr[244]
    DIRECTION OUTPUT ;
    USE SIGNAL ;
    PORT
      LAYER M5 ;
        RECT  11.856 151.116 11.88 151.2 ;
    END
  END sr[244]
  PIN sr[245]
    DIRECTION OUTPUT ;
    USE SIGNAL ;
    PORT
      LAYER M5 ;
        RECT  11.952 151.116 11.976 151.2 ;
    END
  END sr[245]
  PIN sr[246]
    DIRECTION OUTPUT ;
    USE SIGNAL ;
    PORT
      LAYER M5 ;
        RECT  12.048 151.116 12.072 151.2 ;
    END
  END sr[246]
  PIN sr[247]
    DIRECTION OUTPUT ;
    USE SIGNAL ;
    PORT
      LAYER M5 ;
        RECT  12.144 151.116 12.168 151.2 ;
    END
  END sr[247]
  PIN sr[248]
    DIRECTION OUTPUT ;
    USE SIGNAL ;
    PORT
      LAYER M5 ;
        RECT  12.24 151.116 12.264 151.2 ;
    END
  END sr[248]
  PIN sr[249]
    DIRECTION OUTPUT ;
    USE SIGNAL ;
    PORT
      LAYER M5 ;
        RECT  12.336 151.116 12.36 151.2 ;
    END
  END sr[249]
  PIN sr[24]
    DIRECTION OUTPUT ;
    USE SIGNAL ;
    PORT
      LAYER M5 ;
        RECT  34.512 151.116 34.536 151.2 ;
    END
  END sr[24]
  PIN sr[250]
    DIRECTION OUTPUT ;
    USE SIGNAL ;
    PORT
      LAYER M5 ;
        RECT  12.432 151.116 12.456 151.2 ;
    END
  END sr[250]
  PIN sr[251]
    DIRECTION OUTPUT ;
    USE SIGNAL ;
    PORT
      LAYER M5 ;
        RECT  12.528 151.116 12.552 151.2 ;
    END
  END sr[251]
  PIN sr[252]
    DIRECTION OUTPUT ;
    USE SIGNAL ;
    PORT
      LAYER M5 ;
        RECT  12.624 151.116 12.648 151.2 ;
    END
  END sr[252]
  PIN sr[253]
    DIRECTION OUTPUT ;
    USE SIGNAL ;
    PORT
      LAYER M5 ;
        RECT  12.72 151.116 12.744 151.2 ;
    END
  END sr[253]
  PIN sr[254]
    DIRECTION OUTPUT ;
    USE SIGNAL ;
    PORT
      LAYER M5 ;
        RECT  12.816 151.116 12.84 151.2 ;
    END
  END sr[254]
  PIN sr[255]
    DIRECTION OUTPUT ;
    USE SIGNAL ;
    PORT
      LAYER M5 ;
        RECT  12.912 151.116 12.936 151.2 ;
    END
  END sr[255]
  PIN sr[256]
    DIRECTION OUTPUT ;
    USE SIGNAL ;
    PORT
      LAYER M5 ;
        RECT  6.864 151.116 6.888 151.2 ;
    END
  END sr[256]
  PIN sr[257]
    DIRECTION OUTPUT ;
    USE SIGNAL ;
    PORT
      LAYER M5 ;
        RECT  6.96 151.116 6.984 151.2 ;
    END
  END sr[257]
  PIN sr[258]
    DIRECTION OUTPUT ;
    USE SIGNAL ;
    PORT
      LAYER M5 ;
        RECT  7.056 151.116 7.08 151.2 ;
    END
  END sr[258]
  PIN sr[259]
    DIRECTION OUTPUT ;
    USE SIGNAL ;
    PORT
      LAYER M5 ;
        RECT  7.152 151.116 7.176 151.2 ;
    END
  END sr[259]
  PIN sr[25]
    DIRECTION OUTPUT ;
    USE SIGNAL ;
    PORT
      LAYER M5 ;
        RECT  34.608 151.116 34.632 151.2 ;
    END
  END sr[25]
  PIN sr[260]
    DIRECTION OUTPUT ;
    USE SIGNAL ;
    PORT
      LAYER M5 ;
        RECT  7.248 151.116 7.272 151.2 ;
    END
  END sr[260]
  PIN sr[261]
    DIRECTION OUTPUT ;
    USE SIGNAL ;
    PORT
      LAYER M5 ;
        RECT  7.344 151.116 7.368 151.2 ;
    END
  END sr[261]
  PIN sr[262]
    DIRECTION OUTPUT ;
    USE SIGNAL ;
    PORT
      LAYER M5 ;
        RECT  7.44 151.116 7.464 151.2 ;
    END
  END sr[262]
  PIN sr[263]
    DIRECTION OUTPUT ;
    USE SIGNAL ;
    PORT
      LAYER M5 ;
        RECT  7.536 151.116 7.56 151.2 ;
    END
  END sr[263]
  PIN sr[264]
    DIRECTION OUTPUT ;
    USE SIGNAL ;
    PORT
      LAYER M5 ;
        RECT  7.632 151.116 7.656 151.2 ;
    END
  END sr[264]
  PIN sr[265]
    DIRECTION OUTPUT ;
    USE SIGNAL ;
    PORT
      LAYER M5 ;
        RECT  7.728 151.116 7.752 151.2 ;
    END
  END sr[265]
  PIN sr[266]
    DIRECTION OUTPUT ;
    USE SIGNAL ;
    PORT
      LAYER M5 ;
        RECT  7.824 151.116 7.848 151.2 ;
    END
  END sr[266]
  PIN sr[267]
    DIRECTION OUTPUT ;
    USE SIGNAL ;
    PORT
      LAYER M5 ;
        RECT  7.92 151.116 7.944 151.2 ;
    END
  END sr[267]
  PIN sr[268]
    DIRECTION OUTPUT ;
    USE SIGNAL ;
    PORT
      LAYER M5 ;
        RECT  8.016 151.116 8.04 151.2 ;
    END
  END sr[268]
  PIN sr[269]
    DIRECTION OUTPUT ;
    USE SIGNAL ;
    PORT
      LAYER M5 ;
        RECT  8.112 151.116 8.136 151.2 ;
    END
  END sr[269]
  PIN sr[26]
    DIRECTION OUTPUT ;
    USE SIGNAL ;
    PORT
      LAYER M5 ;
        RECT  34.704 151.116 34.728 151.2 ;
    END
  END sr[26]
  PIN sr[270]
    DIRECTION OUTPUT ;
    USE SIGNAL ;
    PORT
      LAYER M5 ;
        RECT  8.208 151.116 8.232 151.2 ;
    END
  END sr[270]
  PIN sr[271]
    DIRECTION OUTPUT ;
    USE SIGNAL ;
    PORT
      LAYER M5 ;
        RECT  8.304 151.116 8.328 151.2 ;
    END
  END sr[271]
  PIN sr[272]
    DIRECTION OUTPUT ;
    USE SIGNAL ;
    PORT
      LAYER M5 ;
        RECT  8.4 151.116 8.424 151.2 ;
    END
  END sr[272]
  PIN sr[273]
    DIRECTION OUTPUT ;
    USE SIGNAL ;
    PORT
      LAYER M5 ;
        RECT  8.496 151.116 8.52 151.2 ;
    END
  END sr[273]
  PIN sr[274]
    DIRECTION OUTPUT ;
    USE SIGNAL ;
    PORT
      LAYER M5 ;
        RECT  8.592 151.116 8.616 151.2 ;
    END
  END sr[274]
  PIN sr[275]
    DIRECTION OUTPUT ;
    USE SIGNAL ;
    PORT
      LAYER M5 ;
        RECT  8.688 151.116 8.712 151.2 ;
    END
  END sr[275]
  PIN sr[276]
    DIRECTION OUTPUT ;
    USE SIGNAL ;
    PORT
      LAYER M5 ;
        RECT  8.784 151.116 8.808 151.2 ;
    END
  END sr[276]
  PIN sr[277]
    DIRECTION OUTPUT ;
    USE SIGNAL ;
    PORT
      LAYER M5 ;
        RECT  8.88 151.116 8.904 151.2 ;
    END
  END sr[277]
  PIN sr[278]
    DIRECTION OUTPUT ;
    USE SIGNAL ;
    PORT
      LAYER M5 ;
        RECT  8.976 151.116 9 151.2 ;
    END
  END sr[278]
  PIN sr[279]
    DIRECTION OUTPUT ;
    USE SIGNAL ;
    PORT
      LAYER M5 ;
        RECT  9.072 151.116 9.096 151.2 ;
    END
  END sr[279]
  PIN sr[27]
    DIRECTION OUTPUT ;
    USE SIGNAL ;
    PORT
      LAYER M5 ;
        RECT  34.8 151.116 34.824 151.2 ;
    END
  END sr[27]
  PIN sr[280]
    DIRECTION OUTPUT ;
    USE SIGNAL ;
    PORT
      LAYER M5 ;
        RECT  9.168 151.116 9.192 151.2 ;
    END
  END sr[280]
  PIN sr[281]
    DIRECTION OUTPUT ;
    USE SIGNAL ;
    PORT
      LAYER M5 ;
        RECT  9.264 151.116 9.288 151.2 ;
    END
  END sr[281]
  PIN sr[282]
    DIRECTION OUTPUT ;
    USE SIGNAL ;
    PORT
      LAYER M5 ;
        RECT  9.36 151.116 9.384 151.2 ;
    END
  END sr[282]
  PIN sr[283]
    DIRECTION OUTPUT ;
    USE SIGNAL ;
    PORT
      LAYER M5 ;
        RECT  9.456 151.116 9.48 151.2 ;
    END
  END sr[283]
  PIN sr[284]
    DIRECTION OUTPUT ;
    USE SIGNAL ;
    PORT
      LAYER M5 ;
        RECT  9.552 151.116 9.576 151.2 ;
    END
  END sr[284]
  PIN sr[285]
    DIRECTION OUTPUT ;
    USE SIGNAL ;
    PORT
      LAYER M5 ;
        RECT  9.648 151.116 9.672 151.2 ;
    END
  END sr[285]
  PIN sr[286]
    DIRECTION OUTPUT ;
    USE SIGNAL ;
    PORT
      LAYER M5 ;
        RECT  9.744 151.116 9.768 151.2 ;
    END
  END sr[286]
  PIN sr[287]
    DIRECTION OUTPUT ;
    USE SIGNAL ;
    PORT
      LAYER M5 ;
        RECT  9.84 151.116 9.864 151.2 ;
    END
  END sr[287]
  PIN sr[288]
    DIRECTION OUTPUT ;
    USE SIGNAL ;
    PORT
      LAYER M5 ;
        RECT  3.792 151.116 3.816 151.2 ;
    END
  END sr[288]
  PIN sr[289]
    DIRECTION OUTPUT ;
    USE SIGNAL ;
    PORT
      LAYER M5 ;
        RECT  3.888 151.116 3.912 151.2 ;
    END
  END sr[289]
  PIN sr[28]
    DIRECTION OUTPUT ;
    USE SIGNAL ;
    PORT
      LAYER M5 ;
        RECT  34.896 151.116 34.92 151.2 ;
    END
  END sr[28]
  PIN sr[290]
    DIRECTION OUTPUT ;
    USE SIGNAL ;
    PORT
      LAYER M5 ;
        RECT  3.984 151.116 4.008 151.2 ;
    END
  END sr[290]
  PIN sr[291]
    DIRECTION OUTPUT ;
    USE SIGNAL ;
    PORT
      LAYER M5 ;
        RECT  4.08 151.116 4.104 151.2 ;
    END
  END sr[291]
  PIN sr[292]
    DIRECTION OUTPUT ;
    USE SIGNAL ;
    PORT
      LAYER M5 ;
        RECT  4.176 151.116 4.2 151.2 ;
    END
  END sr[292]
  PIN sr[293]
    DIRECTION OUTPUT ;
    USE SIGNAL ;
    PORT
      LAYER M5 ;
        RECT  4.272 151.116 4.296 151.2 ;
    END
  END sr[293]
  PIN sr[294]
    DIRECTION OUTPUT ;
    USE SIGNAL ;
    PORT
      LAYER M5 ;
        RECT  4.368 151.116 4.392 151.2 ;
    END
  END sr[294]
  PIN sr[295]
    DIRECTION OUTPUT ;
    USE SIGNAL ;
    PORT
      LAYER M5 ;
        RECT  4.464 151.116 4.488 151.2 ;
    END
  END sr[295]
  PIN sr[296]
    DIRECTION OUTPUT ;
    USE SIGNAL ;
    PORT
      LAYER M5 ;
        RECT  4.56 151.116 4.584 151.2 ;
    END
  END sr[296]
  PIN sr[297]
    DIRECTION OUTPUT ;
    USE SIGNAL ;
    PORT
      LAYER M5 ;
        RECT  4.656 151.116 4.68 151.2 ;
    END
  END sr[297]
  PIN sr[298]
    DIRECTION OUTPUT ;
    USE SIGNAL ;
    PORT
      LAYER M5 ;
        RECT  4.752 151.116 4.776 151.2 ;
    END
  END sr[298]
  PIN sr[299]
    DIRECTION OUTPUT ;
    USE SIGNAL ;
    PORT
      LAYER M5 ;
        RECT  4.848 151.116 4.872 151.2 ;
    END
  END sr[299]
  PIN sr[29]
    DIRECTION OUTPUT ;
    USE SIGNAL ;
    PORT
      LAYER M5 ;
        RECT  34.992 151.116 35.016 151.2 ;
    END
  END sr[29]
  PIN sr[2]
    DIRECTION OUTPUT ;
    USE SIGNAL ;
    PORT
      LAYER M5 ;
        RECT  32.4 151.116 32.424 151.2 ;
    END
  END sr[2]
  PIN sr[300]
    DIRECTION OUTPUT ;
    USE SIGNAL ;
    PORT
      LAYER M5 ;
        RECT  4.944 151.116 4.968 151.2 ;
    END
  END sr[300]
  PIN sr[301]
    DIRECTION OUTPUT ;
    USE SIGNAL ;
    PORT
      LAYER M5 ;
        RECT  5.04 151.116 5.064 151.2 ;
    END
  END sr[301]
  PIN sr[302]
    DIRECTION OUTPUT ;
    USE SIGNAL ;
    PORT
      LAYER M5 ;
        RECT  5.136 151.116 5.16 151.2 ;
    END
  END sr[302]
  PIN sr[303]
    DIRECTION OUTPUT ;
    USE SIGNAL ;
    PORT
      LAYER M5 ;
        RECT  5.232 151.116 5.256 151.2 ;
    END
  END sr[303]
  PIN sr[304]
    DIRECTION OUTPUT ;
    USE SIGNAL ;
    PORT
      LAYER M5 ;
        RECT  5.328 151.116 5.352 151.2 ;
    END
  END sr[304]
  PIN sr[305]
    DIRECTION OUTPUT ;
    USE SIGNAL ;
    PORT
      LAYER M5 ;
        RECT  5.424 151.116 5.448 151.2 ;
    END
  END sr[305]
  PIN sr[306]
    DIRECTION OUTPUT ;
    USE SIGNAL ;
    PORT
      LAYER M5 ;
        RECT  5.52 151.116 5.544 151.2 ;
    END
  END sr[306]
  PIN sr[307]
    DIRECTION OUTPUT ;
    USE SIGNAL ;
    PORT
      LAYER M5 ;
        RECT  5.616 151.116 5.64 151.2 ;
    END
  END sr[307]
  PIN sr[308]
    DIRECTION OUTPUT ;
    USE SIGNAL ;
    PORT
      LAYER M5 ;
        RECT  5.712 151.116 5.736 151.2 ;
    END
  END sr[308]
  PIN sr[309]
    DIRECTION OUTPUT ;
    USE SIGNAL ;
    PORT
      LAYER M5 ;
        RECT  5.808 151.116 5.832 151.2 ;
    END
  END sr[309]
  PIN sr[30]
    DIRECTION OUTPUT ;
    USE SIGNAL ;
    PORT
      LAYER M5 ;
        RECT  35.088 151.116 35.112 151.2 ;
    END
  END sr[30]
  PIN sr[310]
    DIRECTION OUTPUT ;
    USE SIGNAL ;
    PORT
      LAYER M5 ;
        RECT  5.904 151.116 5.928 151.2 ;
    END
  END sr[310]
  PIN sr[311]
    DIRECTION OUTPUT ;
    USE SIGNAL ;
    PORT
      LAYER M5 ;
        RECT  6 151.116 6.024 151.2 ;
    END
  END sr[311]
  PIN sr[312]
    DIRECTION OUTPUT ;
    USE SIGNAL ;
    PORT
      LAYER M5 ;
        RECT  6.096 151.116 6.12 151.2 ;
    END
  END sr[312]
  PIN sr[313]
    DIRECTION OUTPUT ;
    USE SIGNAL ;
    PORT
      LAYER M5 ;
        RECT  6.192 151.116 6.216 151.2 ;
    END
  END sr[313]
  PIN sr[314]
    DIRECTION OUTPUT ;
    USE SIGNAL ;
    PORT
      LAYER M5 ;
        RECT  6.288 151.116 6.312 151.2 ;
    END
  END sr[314]
  PIN sr[315]
    DIRECTION OUTPUT ;
    USE SIGNAL ;
    PORT
      LAYER M5 ;
        RECT  6.384 151.116 6.408 151.2 ;
    END
  END sr[315]
  PIN sr[316]
    DIRECTION OUTPUT ;
    USE SIGNAL ;
    PORT
      LAYER M5 ;
        RECT  6.48 151.116 6.504 151.2 ;
    END
  END sr[316]
  PIN sr[317]
    DIRECTION OUTPUT ;
    USE SIGNAL ;
    PORT
      LAYER M5 ;
        RECT  6.576 151.116 6.6 151.2 ;
    END
  END sr[317]
  PIN sr[318]
    DIRECTION OUTPUT ;
    USE SIGNAL ;
    PORT
      LAYER M5 ;
        RECT  6.672 151.116 6.696 151.2 ;
    END
  END sr[318]
  PIN sr[319]
    DIRECTION OUTPUT ;
    USE SIGNAL ;
    PORT
      LAYER M5 ;
        RECT  6.768 151.116 6.792 151.2 ;
    END
  END sr[319]
  PIN sr[31]
    DIRECTION OUTPUT ;
    USE SIGNAL ;
    PORT
      LAYER M5 ;
        RECT  35.184 151.116 35.208 151.2 ;
    END
  END sr[31]
  PIN sr[320]
    DIRECTION OUTPUT ;
    USE SIGNAL ;
    PORT
      LAYER M5 ;
        RECT  0.72 151.116 0.744 151.2 ;
    END
  END sr[320]
  PIN sr[321]
    DIRECTION OUTPUT ;
    USE SIGNAL ;
    PORT
      LAYER M5 ;
        RECT  0.816 151.116 0.84 151.2 ;
    END
  END sr[321]
  PIN sr[322]
    DIRECTION OUTPUT ;
    USE SIGNAL ;
    PORT
      LAYER M5 ;
        RECT  0.912 151.116 0.936 151.2 ;
    END
  END sr[322]
  PIN sr[323]
    DIRECTION OUTPUT ;
    USE SIGNAL ;
    PORT
      LAYER M5 ;
        RECT  1.008 151.116 1.032 151.2 ;
    END
  END sr[323]
  PIN sr[324]
    DIRECTION OUTPUT ;
    USE SIGNAL ;
    PORT
      LAYER M5 ;
        RECT  1.104 151.116 1.128 151.2 ;
    END
  END sr[324]
  PIN sr[325]
    DIRECTION OUTPUT ;
    USE SIGNAL ;
    PORT
      LAYER M5 ;
        RECT  1.2 151.116 1.224 151.2 ;
    END
  END sr[325]
  PIN sr[326]
    DIRECTION OUTPUT ;
    USE SIGNAL ;
    PORT
      LAYER M5 ;
        RECT  1.296 151.116 1.32 151.2 ;
    END
  END sr[326]
  PIN sr[327]
    DIRECTION OUTPUT ;
    USE SIGNAL ;
    PORT
      LAYER M5 ;
        RECT  1.392 151.116 1.416 151.2 ;
    END
  END sr[327]
  PIN sr[328]
    DIRECTION OUTPUT ;
    USE SIGNAL ;
    PORT
      LAYER M5 ;
        RECT  1.488 151.116 1.512 151.2 ;
    END
  END sr[328]
  PIN sr[329]
    DIRECTION OUTPUT ;
    USE SIGNAL ;
    PORT
      LAYER M5 ;
        RECT  1.584 151.116 1.608 151.2 ;
    END
  END sr[329]
  PIN sr[32]
    DIRECTION OUTPUT ;
    USE SIGNAL ;
    PORT
      LAYER M5 ;
        RECT  29.136 151.116 29.16 151.2 ;
    END
  END sr[32]
  PIN sr[330]
    DIRECTION OUTPUT ;
    USE SIGNAL ;
    PORT
      LAYER M5 ;
        RECT  1.68 151.116 1.704 151.2 ;
    END
  END sr[330]
  PIN sr[331]
    DIRECTION OUTPUT ;
    USE SIGNAL ;
    PORT
      LAYER M5 ;
        RECT  1.776 151.116 1.8 151.2 ;
    END
  END sr[331]
  PIN sr[332]
    DIRECTION OUTPUT ;
    USE SIGNAL ;
    PORT
      LAYER M5 ;
        RECT  1.872 151.116 1.896 151.2 ;
    END
  END sr[332]
  PIN sr[333]
    DIRECTION OUTPUT ;
    USE SIGNAL ;
    PORT
      LAYER M5 ;
        RECT  1.968 151.116 1.992 151.2 ;
    END
  END sr[333]
  PIN sr[334]
    DIRECTION OUTPUT ;
    USE SIGNAL ;
    PORT
      LAYER M5 ;
        RECT  2.064 151.116 2.088 151.2 ;
    END
  END sr[334]
  PIN sr[335]
    DIRECTION OUTPUT ;
    USE SIGNAL ;
    PORT
      LAYER M5 ;
        RECT  2.16 151.116 2.184 151.2 ;
    END
  END sr[335]
  PIN sr[336]
    DIRECTION OUTPUT ;
    USE SIGNAL ;
    PORT
      LAYER M5 ;
        RECT  2.256 151.116 2.28 151.2 ;
    END
  END sr[336]
  PIN sr[337]
    DIRECTION OUTPUT ;
    USE SIGNAL ;
    PORT
      LAYER M5 ;
        RECT  2.352 151.116 2.376 151.2 ;
    END
  END sr[337]
  PIN sr[338]
    DIRECTION OUTPUT ;
    USE SIGNAL ;
    PORT
      LAYER M5 ;
        RECT  2.448 151.116 2.472 151.2 ;
    END
  END sr[338]
  PIN sr[339]
    DIRECTION OUTPUT ;
    USE SIGNAL ;
    PORT
      LAYER M5 ;
        RECT  2.544 151.116 2.568 151.2 ;
    END
  END sr[339]
  PIN sr[33]
    DIRECTION OUTPUT ;
    USE SIGNAL ;
    PORT
      LAYER M5 ;
        RECT  29.232 151.116 29.256 151.2 ;
    END
  END sr[33]
  PIN sr[340]
    DIRECTION OUTPUT ;
    USE SIGNAL ;
    PORT
      LAYER M5 ;
        RECT  2.64 151.116 2.664 151.2 ;
    END
  END sr[340]
  PIN sr[341]
    DIRECTION OUTPUT ;
    USE SIGNAL ;
    PORT
      LAYER M5 ;
        RECT  2.736 151.116 2.76 151.2 ;
    END
  END sr[341]
  PIN sr[342]
    DIRECTION OUTPUT ;
    USE SIGNAL ;
    PORT
      LAYER M5 ;
        RECT  2.832 151.116 2.856 151.2 ;
    END
  END sr[342]
  PIN sr[343]
    DIRECTION OUTPUT ;
    USE SIGNAL ;
    PORT
      LAYER M5 ;
        RECT  2.928 151.116 2.952 151.2 ;
    END
  END sr[343]
  PIN sr[344]
    DIRECTION OUTPUT ;
    USE SIGNAL ;
    PORT
      LAYER M5 ;
        RECT  3.024 151.116 3.048 151.2 ;
    END
  END sr[344]
  PIN sr[345]
    DIRECTION OUTPUT ;
    USE SIGNAL ;
    PORT
      LAYER M5 ;
        RECT  3.12 151.116 3.144 151.2 ;
    END
  END sr[345]
  PIN sr[346]
    DIRECTION OUTPUT ;
    USE SIGNAL ;
    PORT
      LAYER M5 ;
        RECT  3.216 151.116 3.24 151.2 ;
    END
  END sr[346]
  PIN sr[347]
    DIRECTION OUTPUT ;
    USE SIGNAL ;
    PORT
      LAYER M5 ;
        RECT  3.312 151.116 3.336 151.2 ;
    END
  END sr[347]
  PIN sr[348]
    DIRECTION OUTPUT ;
    USE SIGNAL ;
    PORT
      LAYER M5 ;
        RECT  3.408 151.116 3.432 151.2 ;
    END
  END sr[348]
  PIN sr[349]
    DIRECTION OUTPUT ;
    USE SIGNAL ;
    PORT
      LAYER M5 ;
        RECT  3.504 151.116 3.528 151.2 ;
    END
  END sr[349]
  PIN sr[34]
    DIRECTION OUTPUT ;
    USE SIGNAL ;
    PORT
      LAYER M5 ;
        RECT  29.328 151.116 29.352 151.2 ;
    END
  END sr[34]
  PIN sr[350]
    DIRECTION OUTPUT ;
    USE SIGNAL ;
    PORT
      LAYER M5 ;
        RECT  3.6 151.116 3.624 151.2 ;
    END
  END sr[350]
  PIN sr[351]
    DIRECTION OUTPUT ;
    USE SIGNAL ;
    PORT
      LAYER M5 ;
        RECT  3.696 151.116 3.72 151.2 ;
    END
  END sr[351]
  PIN sr[352]
    DIRECTION OUTPUT ;
    USE SIGNAL ;
    PORT
      LAYER M5 ;
        RECT  48.336 151.116 48.36 151.2 ;
    END
  END sr[352]
  PIN sr[353]
    DIRECTION OUTPUT ;
    USE SIGNAL ;
    PORT
      LAYER M5 ;
        RECT  48.432 151.116 48.456 151.2 ;
    END
  END sr[353]
  PIN sr[354]
    DIRECTION OUTPUT ;
    USE SIGNAL ;
    PORT
      LAYER M5 ;
        RECT  48.528 151.116 48.552 151.2 ;
    END
  END sr[354]
  PIN sr[355]
    DIRECTION OUTPUT ;
    USE SIGNAL ;
    PORT
      LAYER M5 ;
        RECT  48.624 151.116 48.648 151.2 ;
    END
  END sr[355]
  PIN sr[356]
    DIRECTION OUTPUT ;
    USE SIGNAL ;
    PORT
      LAYER M5 ;
        RECT  48.72 151.116 48.744 151.2 ;
    END
  END sr[356]
  PIN sr[357]
    DIRECTION OUTPUT ;
    USE SIGNAL ;
    PORT
      LAYER M5 ;
        RECT  48.816 151.116 48.84 151.2 ;
    END
  END sr[357]
  PIN sr[358]
    DIRECTION OUTPUT ;
    USE SIGNAL ;
    PORT
      LAYER M5 ;
        RECT  48.912 151.116 48.936 151.2 ;
    END
  END sr[358]
  PIN sr[359]
    DIRECTION OUTPUT ;
    USE SIGNAL ;
    PORT
      LAYER M5 ;
        RECT  49.008 151.116 49.032 151.2 ;
    END
  END sr[359]
  PIN sr[35]
    DIRECTION OUTPUT ;
    USE SIGNAL ;
    PORT
      LAYER M5 ;
        RECT  29.424 151.116 29.448 151.2 ;
    END
  END sr[35]
  PIN sr[360]
    DIRECTION OUTPUT ;
    USE SIGNAL ;
    PORT
      LAYER M5 ;
        RECT  49.104 151.116 49.128 151.2 ;
    END
  END sr[360]
  PIN sr[361]
    DIRECTION OUTPUT ;
    USE SIGNAL ;
    PORT
      LAYER M5 ;
        RECT  49.2 151.116 49.224 151.2 ;
    END
  END sr[361]
  PIN sr[362]
    DIRECTION OUTPUT ;
    USE SIGNAL ;
    PORT
      LAYER M5 ;
        RECT  49.296 151.116 49.32 151.2 ;
    END
  END sr[362]
  PIN sr[363]
    DIRECTION OUTPUT ;
    USE SIGNAL ;
    PORT
      LAYER M5 ;
        RECT  49.392 151.116 49.416 151.2 ;
    END
  END sr[363]
  PIN sr[364]
    DIRECTION OUTPUT ;
    USE SIGNAL ;
    PORT
      LAYER M5 ;
        RECT  49.488 151.116 49.512 151.2 ;
    END
  END sr[364]
  PIN sr[365]
    DIRECTION OUTPUT ;
    USE SIGNAL ;
    PORT
      LAYER M5 ;
        RECT  49.584 151.116 49.608 151.2 ;
    END
  END sr[365]
  PIN sr[366]
    DIRECTION OUTPUT ;
    USE SIGNAL ;
    PORT
      LAYER M5 ;
        RECT  49.68 151.116 49.704 151.2 ;
    END
  END sr[366]
  PIN sr[367]
    DIRECTION OUTPUT ;
    USE SIGNAL ;
    PORT
      LAYER M5 ;
        RECT  49.776 151.116 49.8 151.2 ;
    END
  END sr[367]
  PIN sr[368]
    DIRECTION OUTPUT ;
    USE SIGNAL ;
    PORT
      LAYER M5 ;
        RECT  49.872 151.116 49.896 151.2 ;
    END
  END sr[368]
  PIN sr[369]
    DIRECTION OUTPUT ;
    USE SIGNAL ;
    PORT
      LAYER M5 ;
        RECT  49.968 151.116 49.992 151.2 ;
    END
  END sr[369]
  PIN sr[36]
    DIRECTION OUTPUT ;
    USE SIGNAL ;
    PORT
      LAYER M5 ;
        RECT  29.52 151.116 29.544 151.2 ;
    END
  END sr[36]
  PIN sr[370]
    DIRECTION OUTPUT ;
    USE SIGNAL ;
    PORT
      LAYER M5 ;
        RECT  50.064 151.116 50.088 151.2 ;
    END
  END sr[370]
  PIN sr[371]
    DIRECTION OUTPUT ;
    USE SIGNAL ;
    PORT
      LAYER M5 ;
        RECT  50.16 151.116 50.184 151.2 ;
    END
  END sr[371]
  PIN sr[372]
    DIRECTION OUTPUT ;
    USE SIGNAL ;
    PORT
      LAYER M5 ;
        RECT  50.256 151.116 50.28 151.2 ;
    END
  END sr[372]
  PIN sr[373]
    DIRECTION OUTPUT ;
    USE SIGNAL ;
    PORT
      LAYER M5 ;
        RECT  50.352 151.116 50.376 151.2 ;
    END
  END sr[373]
  PIN sr[374]
    DIRECTION OUTPUT ;
    USE SIGNAL ;
    PORT
      LAYER M5 ;
        RECT  50.448 151.116 50.472 151.2 ;
    END
  END sr[374]
  PIN sr[375]
    DIRECTION OUTPUT ;
    USE SIGNAL ;
    PORT
      LAYER M5 ;
        RECT  50.544 151.116 50.568 151.2 ;
    END
  END sr[375]
  PIN sr[376]
    DIRECTION OUTPUT ;
    USE SIGNAL ;
    PORT
      LAYER M5 ;
        RECT  50.64 151.116 50.664 151.2 ;
    END
  END sr[376]
  PIN sr[377]
    DIRECTION OUTPUT ;
    USE SIGNAL ;
    PORT
      LAYER M5 ;
        RECT  50.736 151.116 50.76 151.2 ;
    END
  END sr[377]
  PIN sr[378]
    DIRECTION OUTPUT ;
    USE SIGNAL ;
    PORT
      LAYER M5 ;
        RECT  50.832 151.116 50.856 151.2 ;
    END
  END sr[378]
  PIN sr[379]
    DIRECTION OUTPUT ;
    USE SIGNAL ;
    PORT
      LAYER M5 ;
        RECT  50.928 151.116 50.952 151.2 ;
    END
  END sr[379]
  PIN sr[37]
    DIRECTION OUTPUT ;
    USE SIGNAL ;
    PORT
      LAYER M5 ;
        RECT  29.616 151.116 29.64 151.2 ;
    END
  END sr[37]
  PIN sr[380]
    DIRECTION OUTPUT ;
    USE SIGNAL ;
    PORT
      LAYER M5 ;
        RECT  51.024 151.116 51.048 151.2 ;
    END
  END sr[380]
  PIN sr[381]
    DIRECTION OUTPUT ;
    USE SIGNAL ;
    PORT
      LAYER M5 ;
        RECT  51.12 151.116 51.144 151.2 ;
    END
  END sr[381]
  PIN sr[382]
    DIRECTION OUTPUT ;
    USE SIGNAL ;
    PORT
      LAYER M5 ;
        RECT  51.216 151.116 51.24 151.2 ;
    END
  END sr[382]
  PIN sr[383]
    DIRECTION OUTPUT ;
    USE SIGNAL ;
    PORT
      LAYER M5 ;
        RECT  51.312 151.116 51.336 151.2 ;
    END
  END sr[383]
  PIN sr[384]
    DIRECTION OUTPUT ;
    USE SIGNAL ;
    PORT
      LAYER M5 ;
        RECT  45.264 151.116 45.288 151.2 ;
    END
  END sr[384]
  PIN sr[385]
    DIRECTION OUTPUT ;
    USE SIGNAL ;
    PORT
      LAYER M5 ;
        RECT  45.36 151.116 45.384 151.2 ;
    END
  END sr[385]
  PIN sr[386]
    DIRECTION OUTPUT ;
    USE SIGNAL ;
    PORT
      LAYER M5 ;
        RECT  45.456 151.116 45.48 151.2 ;
    END
  END sr[386]
  PIN sr[387]
    DIRECTION OUTPUT ;
    USE SIGNAL ;
    PORT
      LAYER M5 ;
        RECT  45.552 151.116 45.576 151.2 ;
    END
  END sr[387]
  PIN sr[388]
    DIRECTION OUTPUT ;
    USE SIGNAL ;
    PORT
      LAYER M5 ;
        RECT  45.648 151.116 45.672 151.2 ;
    END
  END sr[388]
  PIN sr[389]
    DIRECTION OUTPUT ;
    USE SIGNAL ;
    PORT
      LAYER M5 ;
        RECT  45.744 151.116 45.768 151.2 ;
    END
  END sr[389]
  PIN sr[38]
    DIRECTION OUTPUT ;
    USE SIGNAL ;
    PORT
      LAYER M5 ;
        RECT  29.712 151.116 29.736 151.2 ;
    END
  END sr[38]
  PIN sr[390]
    DIRECTION OUTPUT ;
    USE SIGNAL ;
    PORT
      LAYER M5 ;
        RECT  45.84 151.116 45.864 151.2 ;
    END
  END sr[390]
  PIN sr[391]
    DIRECTION OUTPUT ;
    USE SIGNAL ;
    PORT
      LAYER M5 ;
        RECT  45.936 151.116 45.96 151.2 ;
    END
  END sr[391]
  PIN sr[392]
    DIRECTION OUTPUT ;
    USE SIGNAL ;
    PORT
      LAYER M5 ;
        RECT  46.032 151.116 46.056 151.2 ;
    END
  END sr[392]
  PIN sr[393]
    DIRECTION OUTPUT ;
    USE SIGNAL ;
    PORT
      LAYER M5 ;
        RECT  46.128 151.116 46.152 151.2 ;
    END
  END sr[393]
  PIN sr[394]
    DIRECTION OUTPUT ;
    USE SIGNAL ;
    PORT
      LAYER M5 ;
        RECT  46.224 151.116 46.248 151.2 ;
    END
  END sr[394]
  PIN sr[395]
    DIRECTION OUTPUT ;
    USE SIGNAL ;
    PORT
      LAYER M5 ;
        RECT  46.32 151.116 46.344 151.2 ;
    END
  END sr[395]
  PIN sr[396]
    DIRECTION OUTPUT ;
    USE SIGNAL ;
    PORT
      LAYER M5 ;
        RECT  46.416 151.116 46.44 151.2 ;
    END
  END sr[396]
  PIN sr[397]
    DIRECTION OUTPUT ;
    USE SIGNAL ;
    PORT
      LAYER M5 ;
        RECT  46.512 151.116 46.536 151.2 ;
    END
  END sr[397]
  PIN sr[398]
    DIRECTION OUTPUT ;
    USE SIGNAL ;
    PORT
      LAYER M5 ;
        RECT  46.608 151.116 46.632 151.2 ;
    END
  END sr[398]
  PIN sr[399]
    DIRECTION OUTPUT ;
    USE SIGNAL ;
    PORT
      LAYER M5 ;
        RECT  46.704 151.116 46.728 151.2 ;
    END
  END sr[399]
  PIN sr[39]
    DIRECTION OUTPUT ;
    USE SIGNAL ;
    PORT
      LAYER M5 ;
        RECT  29.808 151.116 29.832 151.2 ;
    END
  END sr[39]
  PIN sr[3]
    DIRECTION OUTPUT ;
    USE SIGNAL ;
    PORT
      LAYER M5 ;
        RECT  32.496 151.116 32.52 151.2 ;
    END
  END sr[3]
  PIN sr[400]
    DIRECTION OUTPUT ;
    USE SIGNAL ;
    PORT
      LAYER M5 ;
        RECT  46.8 151.116 46.824 151.2 ;
    END
  END sr[400]
  PIN sr[401]
    DIRECTION OUTPUT ;
    USE SIGNAL ;
    PORT
      LAYER M5 ;
        RECT  46.896 151.116 46.92 151.2 ;
    END
  END sr[401]
  PIN sr[402]
    DIRECTION OUTPUT ;
    USE SIGNAL ;
    PORT
      LAYER M5 ;
        RECT  46.992 151.116 47.016 151.2 ;
    END
  END sr[402]
  PIN sr[403]
    DIRECTION OUTPUT ;
    USE SIGNAL ;
    PORT
      LAYER M5 ;
        RECT  47.088 151.116 47.112 151.2 ;
    END
  END sr[403]
  PIN sr[404]
    DIRECTION OUTPUT ;
    USE SIGNAL ;
    PORT
      LAYER M5 ;
        RECT  47.184 151.116 47.208 151.2 ;
    END
  END sr[404]
  PIN sr[405]
    DIRECTION OUTPUT ;
    USE SIGNAL ;
    PORT
      LAYER M5 ;
        RECT  47.28 151.116 47.304 151.2 ;
    END
  END sr[405]
  PIN sr[406]
    DIRECTION OUTPUT ;
    USE SIGNAL ;
    PORT
      LAYER M5 ;
        RECT  47.376 151.116 47.4 151.2 ;
    END
  END sr[406]
  PIN sr[407]
    DIRECTION OUTPUT ;
    USE SIGNAL ;
    PORT
      LAYER M5 ;
        RECT  47.472 151.116 47.496 151.2 ;
    END
  END sr[407]
  PIN sr[408]
    DIRECTION OUTPUT ;
    USE SIGNAL ;
    PORT
      LAYER M5 ;
        RECT  47.568 151.116 47.592 151.2 ;
    END
  END sr[408]
  PIN sr[409]
    DIRECTION OUTPUT ;
    USE SIGNAL ;
    PORT
      LAYER M5 ;
        RECT  47.664 151.116 47.688 151.2 ;
    END
  END sr[409]
  PIN sr[40]
    DIRECTION OUTPUT ;
    USE SIGNAL ;
    PORT
      LAYER M5 ;
        RECT  29.904 151.116 29.928 151.2 ;
    END
  END sr[40]
  PIN sr[410]
    DIRECTION OUTPUT ;
    USE SIGNAL ;
    PORT
      LAYER M5 ;
        RECT  47.76 151.116 47.784 151.2 ;
    END
  END sr[410]
  PIN sr[411]
    DIRECTION OUTPUT ;
    USE SIGNAL ;
    PORT
      LAYER M5 ;
        RECT  47.856 151.116 47.88 151.2 ;
    END
  END sr[411]
  PIN sr[412]
    DIRECTION OUTPUT ;
    USE SIGNAL ;
    PORT
      LAYER M5 ;
        RECT  47.952 151.116 47.976 151.2 ;
    END
  END sr[412]
  PIN sr[413]
    DIRECTION OUTPUT ;
    USE SIGNAL ;
    PORT
      LAYER M5 ;
        RECT  48.048 151.116 48.072 151.2 ;
    END
  END sr[413]
  PIN sr[414]
    DIRECTION OUTPUT ;
    USE SIGNAL ;
    PORT
      LAYER M5 ;
        RECT  48.144 151.116 48.168 151.2 ;
    END
  END sr[414]
  PIN sr[415]
    DIRECTION OUTPUT ;
    USE SIGNAL ;
    PORT
      LAYER M5 ;
        RECT  48.24 151.116 48.264 151.2 ;
    END
  END sr[415]
  PIN sr[416]
    DIRECTION OUTPUT ;
    USE SIGNAL ;
    PORT
      LAYER M5 ;
        RECT  42.192 151.116 42.216 151.2 ;
    END
  END sr[416]
  PIN sr[417]
    DIRECTION OUTPUT ;
    USE SIGNAL ;
    PORT
      LAYER M5 ;
        RECT  42.288 151.116 42.312 151.2 ;
    END
  END sr[417]
  PIN sr[418]
    DIRECTION OUTPUT ;
    USE SIGNAL ;
    PORT
      LAYER M5 ;
        RECT  42.384 151.116 42.408 151.2 ;
    END
  END sr[418]
  PIN sr[419]
    DIRECTION OUTPUT ;
    USE SIGNAL ;
    PORT
      LAYER M5 ;
        RECT  42.48 151.116 42.504 151.2 ;
    END
  END sr[419]
  PIN sr[41]
    DIRECTION OUTPUT ;
    USE SIGNAL ;
    PORT
      LAYER M5 ;
        RECT  30 151.116 30.024 151.2 ;
    END
  END sr[41]
  PIN sr[420]
    DIRECTION OUTPUT ;
    USE SIGNAL ;
    PORT
      LAYER M5 ;
        RECT  42.576 151.116 42.6 151.2 ;
    END
  END sr[420]
  PIN sr[421]
    DIRECTION OUTPUT ;
    USE SIGNAL ;
    PORT
      LAYER M5 ;
        RECT  42.672 151.116 42.696 151.2 ;
    END
  END sr[421]
  PIN sr[422]
    DIRECTION OUTPUT ;
    USE SIGNAL ;
    PORT
      LAYER M5 ;
        RECT  42.768 151.116 42.792 151.2 ;
    END
  END sr[422]
  PIN sr[423]
    DIRECTION OUTPUT ;
    USE SIGNAL ;
    PORT
      LAYER M5 ;
        RECT  42.864 151.116 42.888 151.2 ;
    END
  END sr[423]
  PIN sr[424]
    DIRECTION OUTPUT ;
    USE SIGNAL ;
    PORT
      LAYER M5 ;
        RECT  42.96 151.116 42.984 151.2 ;
    END
  END sr[424]
  PIN sr[425]
    DIRECTION OUTPUT ;
    USE SIGNAL ;
    PORT
      LAYER M5 ;
        RECT  43.056 151.116 43.08 151.2 ;
    END
  END sr[425]
  PIN sr[426]
    DIRECTION OUTPUT ;
    USE SIGNAL ;
    PORT
      LAYER M5 ;
        RECT  43.152 151.116 43.176 151.2 ;
    END
  END sr[426]
  PIN sr[427]
    DIRECTION OUTPUT ;
    USE SIGNAL ;
    PORT
      LAYER M5 ;
        RECT  43.248 151.116 43.272 151.2 ;
    END
  END sr[427]
  PIN sr[428]
    DIRECTION OUTPUT ;
    USE SIGNAL ;
    PORT
      LAYER M5 ;
        RECT  43.344 151.116 43.368 151.2 ;
    END
  END sr[428]
  PIN sr[429]
    DIRECTION OUTPUT ;
    USE SIGNAL ;
    PORT
      LAYER M5 ;
        RECT  43.44 151.116 43.464 151.2 ;
    END
  END sr[429]
  PIN sr[42]
    DIRECTION OUTPUT ;
    USE SIGNAL ;
    PORT
      LAYER M5 ;
        RECT  30.096 151.116 30.12 151.2 ;
    END
  END sr[42]
  PIN sr[430]
    DIRECTION OUTPUT ;
    USE SIGNAL ;
    PORT
      LAYER M5 ;
        RECT  43.536 151.116 43.56 151.2 ;
    END
  END sr[430]
  PIN sr[431]
    DIRECTION OUTPUT ;
    USE SIGNAL ;
    PORT
      LAYER M5 ;
        RECT  43.632 151.116 43.656 151.2 ;
    END
  END sr[431]
  PIN sr[432]
    DIRECTION OUTPUT ;
    USE SIGNAL ;
    PORT
      LAYER M5 ;
        RECT  43.728 151.116 43.752 151.2 ;
    END
  END sr[432]
  PIN sr[433]
    DIRECTION OUTPUT ;
    USE SIGNAL ;
    PORT
      LAYER M5 ;
        RECT  43.824 151.116 43.848 151.2 ;
    END
  END sr[433]
  PIN sr[434]
    DIRECTION OUTPUT ;
    USE SIGNAL ;
    PORT
      LAYER M5 ;
        RECT  43.92 151.116 43.944 151.2 ;
    END
  END sr[434]
  PIN sr[435]
    DIRECTION OUTPUT ;
    USE SIGNAL ;
    PORT
      LAYER M5 ;
        RECT  44.016 151.116 44.04 151.2 ;
    END
  END sr[435]
  PIN sr[436]
    DIRECTION OUTPUT ;
    USE SIGNAL ;
    PORT
      LAYER M5 ;
        RECT  44.112 151.116 44.136 151.2 ;
    END
  END sr[436]
  PIN sr[437]
    DIRECTION OUTPUT ;
    USE SIGNAL ;
    PORT
      LAYER M5 ;
        RECT  44.208 151.116 44.232 151.2 ;
    END
  END sr[437]
  PIN sr[438]
    DIRECTION OUTPUT ;
    USE SIGNAL ;
    PORT
      LAYER M5 ;
        RECT  44.304 151.116 44.328 151.2 ;
    END
  END sr[438]
  PIN sr[439]
    DIRECTION OUTPUT ;
    USE SIGNAL ;
    PORT
      LAYER M5 ;
        RECT  44.4 151.116 44.424 151.2 ;
    END
  END sr[439]
  PIN sr[43]
    DIRECTION OUTPUT ;
    USE SIGNAL ;
    PORT
      LAYER M5 ;
        RECT  30.192 151.116 30.216 151.2 ;
    END
  END sr[43]
  PIN sr[440]
    DIRECTION OUTPUT ;
    USE SIGNAL ;
    PORT
      LAYER M5 ;
        RECT  44.496 151.116 44.52 151.2 ;
    END
  END sr[440]
  PIN sr[441]
    DIRECTION OUTPUT ;
    USE SIGNAL ;
    PORT
      LAYER M5 ;
        RECT  44.592 151.116 44.616 151.2 ;
    END
  END sr[441]
  PIN sr[442]
    DIRECTION OUTPUT ;
    USE SIGNAL ;
    PORT
      LAYER M5 ;
        RECT  44.688 151.116 44.712 151.2 ;
    END
  END sr[442]
  PIN sr[443]
    DIRECTION OUTPUT ;
    USE SIGNAL ;
    PORT
      LAYER M5 ;
        RECT  44.784 151.116 44.808 151.2 ;
    END
  END sr[443]
  PIN sr[444]
    DIRECTION OUTPUT ;
    USE SIGNAL ;
    PORT
      LAYER M5 ;
        RECT  44.88 151.116 44.904 151.2 ;
    END
  END sr[444]
  PIN sr[445]
    DIRECTION OUTPUT ;
    USE SIGNAL ;
    PORT
      LAYER M5 ;
        RECT  44.976 151.116 45 151.2 ;
    END
  END sr[445]
  PIN sr[446]
    DIRECTION OUTPUT ;
    USE SIGNAL ;
    PORT
      LAYER M5 ;
        RECT  45.072 151.116 45.096 151.2 ;
    END
  END sr[446]
  PIN sr[447]
    DIRECTION OUTPUT ;
    USE SIGNAL ;
    PORT
      LAYER M5 ;
        RECT  45.168 151.116 45.192 151.2 ;
    END
  END sr[447]
  PIN sr[448]
    DIRECTION OUTPUT ;
    USE SIGNAL ;
    PORT
      LAYER M5 ;
        RECT  39.12 151.116 39.144 151.2 ;
    END
  END sr[448]
  PIN sr[449]
    DIRECTION OUTPUT ;
    USE SIGNAL ;
    PORT
      LAYER M5 ;
        RECT  39.216 151.116 39.24 151.2 ;
    END
  END sr[449]
  PIN sr[44]
    DIRECTION OUTPUT ;
    USE SIGNAL ;
    PORT
      LAYER M5 ;
        RECT  30.288 151.116 30.312 151.2 ;
    END
  END sr[44]
  PIN sr[450]
    DIRECTION OUTPUT ;
    USE SIGNAL ;
    PORT
      LAYER M5 ;
        RECT  39.312 151.116 39.336 151.2 ;
    END
  END sr[450]
  PIN sr[451]
    DIRECTION OUTPUT ;
    USE SIGNAL ;
    PORT
      LAYER M5 ;
        RECT  39.408 151.116 39.432 151.2 ;
    END
  END sr[451]
  PIN sr[452]
    DIRECTION OUTPUT ;
    USE SIGNAL ;
    PORT
      LAYER M5 ;
        RECT  39.504 151.116 39.528 151.2 ;
    END
  END sr[452]
  PIN sr[453]
    DIRECTION OUTPUT ;
    USE SIGNAL ;
    PORT
      LAYER M5 ;
        RECT  39.6 151.116 39.624 151.2 ;
    END
  END sr[453]
  PIN sr[454]
    DIRECTION OUTPUT ;
    USE SIGNAL ;
    PORT
      LAYER M5 ;
        RECT  39.696 151.116 39.72 151.2 ;
    END
  END sr[454]
  PIN sr[455]
    DIRECTION OUTPUT ;
    USE SIGNAL ;
    PORT
      LAYER M5 ;
        RECT  39.792 151.116 39.816 151.2 ;
    END
  END sr[455]
  PIN sr[456]
    DIRECTION OUTPUT ;
    USE SIGNAL ;
    PORT
      LAYER M5 ;
        RECT  39.888 151.116 39.912 151.2 ;
    END
  END sr[456]
  PIN sr[457]
    DIRECTION OUTPUT ;
    USE SIGNAL ;
    PORT
      LAYER M5 ;
        RECT  39.984 151.116 40.008 151.2 ;
    END
  END sr[457]
  PIN sr[458]
    DIRECTION OUTPUT ;
    USE SIGNAL ;
    PORT
      LAYER M5 ;
        RECT  40.08 151.116 40.104 151.2 ;
    END
  END sr[458]
  PIN sr[459]
    DIRECTION OUTPUT ;
    USE SIGNAL ;
    PORT
      LAYER M5 ;
        RECT  40.176 151.116 40.2 151.2 ;
    END
  END sr[459]
  PIN sr[45]
    DIRECTION OUTPUT ;
    USE SIGNAL ;
    PORT
      LAYER M5 ;
        RECT  30.384 151.116 30.408 151.2 ;
    END
  END sr[45]
  PIN sr[460]
    DIRECTION OUTPUT ;
    USE SIGNAL ;
    PORT
      LAYER M5 ;
        RECT  40.272 151.116 40.296 151.2 ;
    END
  END sr[460]
  PIN sr[461]
    DIRECTION OUTPUT ;
    USE SIGNAL ;
    PORT
      LAYER M5 ;
        RECT  40.368 151.116 40.392 151.2 ;
    END
  END sr[461]
  PIN sr[462]
    DIRECTION OUTPUT ;
    USE SIGNAL ;
    PORT
      LAYER M5 ;
        RECT  40.464 151.116 40.488 151.2 ;
    END
  END sr[462]
  PIN sr[463]
    DIRECTION OUTPUT ;
    USE SIGNAL ;
    PORT
      LAYER M5 ;
        RECT  40.56 151.116 40.584 151.2 ;
    END
  END sr[463]
  PIN sr[464]
    DIRECTION OUTPUT ;
    USE SIGNAL ;
    PORT
      LAYER M5 ;
        RECT  40.656 151.116 40.68 151.2 ;
    END
  END sr[464]
  PIN sr[465]
    DIRECTION OUTPUT ;
    USE SIGNAL ;
    PORT
      LAYER M5 ;
        RECT  40.752 151.116 40.776 151.2 ;
    END
  END sr[465]
  PIN sr[466]
    DIRECTION OUTPUT ;
    USE SIGNAL ;
    PORT
      LAYER M5 ;
        RECT  40.848 151.116 40.872 151.2 ;
    END
  END sr[466]
  PIN sr[467]
    DIRECTION OUTPUT ;
    USE SIGNAL ;
    PORT
      LAYER M5 ;
        RECT  40.944 151.116 40.968 151.2 ;
    END
  END sr[467]
  PIN sr[468]
    DIRECTION OUTPUT ;
    USE SIGNAL ;
    PORT
      LAYER M5 ;
        RECT  41.04 151.116 41.064 151.2 ;
    END
  END sr[468]
  PIN sr[469]
    DIRECTION OUTPUT ;
    USE SIGNAL ;
    PORT
      LAYER M5 ;
        RECT  41.136 151.116 41.16 151.2 ;
    END
  END sr[469]
  PIN sr[46]
    DIRECTION OUTPUT ;
    USE SIGNAL ;
    PORT
      LAYER M5 ;
        RECT  30.48 151.116 30.504 151.2 ;
    END
  END sr[46]
  PIN sr[470]
    DIRECTION OUTPUT ;
    USE SIGNAL ;
    PORT
      LAYER M5 ;
        RECT  41.232 151.116 41.256 151.2 ;
    END
  END sr[470]
  PIN sr[471]
    DIRECTION OUTPUT ;
    USE SIGNAL ;
    PORT
      LAYER M5 ;
        RECT  41.328 151.116 41.352 151.2 ;
    END
  END sr[471]
  PIN sr[472]
    DIRECTION OUTPUT ;
    USE SIGNAL ;
    PORT
      LAYER M5 ;
        RECT  41.424 151.116 41.448 151.2 ;
    END
  END sr[472]
  PIN sr[473]
    DIRECTION OUTPUT ;
    USE SIGNAL ;
    PORT
      LAYER M5 ;
        RECT  41.52 151.116 41.544 151.2 ;
    END
  END sr[473]
  PIN sr[474]
    DIRECTION OUTPUT ;
    USE SIGNAL ;
    PORT
      LAYER M5 ;
        RECT  41.616 151.116 41.64 151.2 ;
    END
  END sr[474]
  PIN sr[475]
    DIRECTION OUTPUT ;
    USE SIGNAL ;
    PORT
      LAYER M5 ;
        RECT  41.712 151.116 41.736 151.2 ;
    END
  END sr[475]
  PIN sr[476]
    DIRECTION OUTPUT ;
    USE SIGNAL ;
    PORT
      LAYER M5 ;
        RECT  41.808 151.116 41.832 151.2 ;
    END
  END sr[476]
  PIN sr[477]
    DIRECTION OUTPUT ;
    USE SIGNAL ;
    PORT
      LAYER M5 ;
        RECT  41.904 151.116 41.928 151.2 ;
    END
  END sr[477]
  PIN sr[478]
    DIRECTION OUTPUT ;
    USE SIGNAL ;
    PORT
      LAYER M5 ;
        RECT  42 151.116 42.024 151.2 ;
    END
  END sr[478]
  PIN sr[479]
    DIRECTION OUTPUT ;
    USE SIGNAL ;
    PORT
      LAYER M5 ;
        RECT  42.096 151.116 42.12 151.2 ;
    END
  END sr[479]
  PIN sr[47]
    DIRECTION OUTPUT ;
    USE SIGNAL ;
    PORT
      LAYER M5 ;
        RECT  30.576 151.116 30.6 151.2 ;
    END
  END sr[47]
  PIN sr[480]
    DIRECTION OUTPUT ;
    USE SIGNAL ;
    PORT
      LAYER M5 ;
        RECT  36.048 151.116 36.072 151.2 ;
    END
  END sr[480]
  PIN sr[481]
    DIRECTION OUTPUT ;
    USE SIGNAL ;
    PORT
      LAYER M5 ;
        RECT  36.144 151.116 36.168 151.2 ;
    END
  END sr[481]
  PIN sr[482]
    DIRECTION OUTPUT ;
    USE SIGNAL ;
    PORT
      LAYER M5 ;
        RECT  36.24 151.116 36.264 151.2 ;
    END
  END sr[482]
  PIN sr[483]
    DIRECTION OUTPUT ;
    USE SIGNAL ;
    PORT
      LAYER M5 ;
        RECT  36.336 151.116 36.36 151.2 ;
    END
  END sr[483]
  PIN sr[484]
    DIRECTION OUTPUT ;
    USE SIGNAL ;
    PORT
      LAYER M5 ;
        RECT  36.432 151.116 36.456 151.2 ;
    END
  END sr[484]
  PIN sr[485]
    DIRECTION OUTPUT ;
    USE SIGNAL ;
    PORT
      LAYER M5 ;
        RECT  36.528 151.116 36.552 151.2 ;
    END
  END sr[485]
  PIN sr[486]
    DIRECTION OUTPUT ;
    USE SIGNAL ;
    PORT
      LAYER M5 ;
        RECT  36.624 151.116 36.648 151.2 ;
    END
  END sr[486]
  PIN sr[487]
    DIRECTION OUTPUT ;
    USE SIGNAL ;
    PORT
      LAYER M5 ;
        RECT  36.72 151.116 36.744 151.2 ;
    END
  END sr[487]
  PIN sr[488]
    DIRECTION OUTPUT ;
    USE SIGNAL ;
    PORT
      LAYER M5 ;
        RECT  36.816 151.116 36.84 151.2 ;
    END
  END sr[488]
  PIN sr[489]
    DIRECTION OUTPUT ;
    USE SIGNAL ;
    PORT
      LAYER M5 ;
        RECT  36.912 151.116 36.936 151.2 ;
    END
  END sr[489]
  PIN sr[48]
    DIRECTION OUTPUT ;
    USE SIGNAL ;
    PORT
      LAYER M5 ;
        RECT  30.672 151.116 30.696 151.2 ;
    END
  END sr[48]
  PIN sr[490]
    DIRECTION OUTPUT ;
    USE SIGNAL ;
    PORT
      LAYER M5 ;
        RECT  37.008 151.116 37.032 151.2 ;
    END
  END sr[490]
  PIN sr[491]
    DIRECTION OUTPUT ;
    USE SIGNAL ;
    PORT
      LAYER M5 ;
        RECT  37.104 151.116 37.128 151.2 ;
    END
  END sr[491]
  PIN sr[492]
    DIRECTION OUTPUT ;
    USE SIGNAL ;
    PORT
      LAYER M5 ;
        RECT  37.2 151.116 37.224 151.2 ;
    END
  END sr[492]
  PIN sr[493]
    DIRECTION OUTPUT ;
    USE SIGNAL ;
    PORT
      LAYER M5 ;
        RECT  37.296 151.116 37.32 151.2 ;
    END
  END sr[493]
  PIN sr[494]
    DIRECTION OUTPUT ;
    USE SIGNAL ;
    PORT
      LAYER M5 ;
        RECT  37.392 151.116 37.416 151.2 ;
    END
  END sr[494]
  PIN sr[495]
    DIRECTION OUTPUT ;
    USE SIGNAL ;
    PORT
      LAYER M5 ;
        RECT  37.488 151.116 37.512 151.2 ;
    END
  END sr[495]
  PIN sr[496]
    DIRECTION OUTPUT ;
    USE SIGNAL ;
    PORT
      LAYER M5 ;
        RECT  37.584 151.116 37.608 151.2 ;
    END
  END sr[496]
  PIN sr[497]
    DIRECTION OUTPUT ;
    USE SIGNAL ;
    PORT
      LAYER M5 ;
        RECT  37.68 151.116 37.704 151.2 ;
    END
  END sr[497]
  PIN sr[498]
    DIRECTION OUTPUT ;
    USE SIGNAL ;
    PORT
      LAYER M5 ;
        RECT  37.776 151.116 37.8 151.2 ;
    END
  END sr[498]
  PIN sr[499]
    DIRECTION OUTPUT ;
    USE SIGNAL ;
    PORT
      LAYER M5 ;
        RECT  37.872 151.116 37.896 151.2 ;
    END
  END sr[499]
  PIN sr[49]
    DIRECTION OUTPUT ;
    USE SIGNAL ;
    PORT
      LAYER M5 ;
        RECT  30.768 151.116 30.792 151.2 ;
    END
  END sr[49]
  PIN sr[4]
    DIRECTION OUTPUT ;
    USE SIGNAL ;
    PORT
      LAYER M5 ;
        RECT  32.592 151.116 32.616 151.2 ;
    END
  END sr[4]
  PIN sr[500]
    DIRECTION OUTPUT ;
    USE SIGNAL ;
    PORT
      LAYER M5 ;
        RECT  37.968 151.116 37.992 151.2 ;
    END
  END sr[500]
  PIN sr[501]
    DIRECTION OUTPUT ;
    USE SIGNAL ;
    PORT
      LAYER M5 ;
        RECT  38.064 151.116 38.088 151.2 ;
    END
  END sr[501]
  PIN sr[502]
    DIRECTION OUTPUT ;
    USE SIGNAL ;
    PORT
      LAYER M5 ;
        RECT  38.16 151.116 38.184 151.2 ;
    END
  END sr[502]
  PIN sr[503]
    DIRECTION OUTPUT ;
    USE SIGNAL ;
    PORT
      LAYER M5 ;
        RECT  38.256 151.116 38.28 151.2 ;
    END
  END sr[503]
  PIN sr[504]
    DIRECTION OUTPUT ;
    USE SIGNAL ;
    PORT
      LAYER M5 ;
        RECT  38.352 151.116 38.376 151.2 ;
    END
  END sr[504]
  PIN sr[505]
    DIRECTION OUTPUT ;
    USE SIGNAL ;
    PORT
      LAYER M5 ;
        RECT  38.448 151.116 38.472 151.2 ;
    END
  END sr[505]
  PIN sr[506]
    DIRECTION OUTPUT ;
    USE SIGNAL ;
    PORT
      LAYER M5 ;
        RECT  38.544 151.116 38.568 151.2 ;
    END
  END sr[506]
  PIN sr[507]
    DIRECTION OUTPUT ;
    USE SIGNAL ;
    PORT
      LAYER M5 ;
        RECT  38.64 151.116 38.664 151.2 ;
    END
  END sr[507]
  PIN sr[508]
    DIRECTION OUTPUT ;
    USE SIGNAL ;
    PORT
      LAYER M5 ;
        RECT  38.736 151.116 38.76 151.2 ;
    END
  END sr[508]
  PIN sr[509]
    DIRECTION OUTPUT ;
    USE SIGNAL ;
    PORT
      LAYER M5 ;
        RECT  38.832 151.116 38.856 151.2 ;
    END
  END sr[509]
  PIN sr[50]
    DIRECTION OUTPUT ;
    USE SIGNAL ;
    PORT
      LAYER M5 ;
        RECT  30.864 151.116 30.888 151.2 ;
    END
  END sr[50]
  PIN sr[510]
    DIRECTION OUTPUT ;
    USE SIGNAL ;
    PORT
      LAYER M5 ;
        RECT  38.928 151.116 38.952 151.2 ;
    END
  END sr[510]
  PIN sr[511]
    DIRECTION OUTPUT ;
    USE SIGNAL ;
    PORT
      LAYER M5 ;
        RECT  39.024 151.116 39.048 151.2 ;
    END
  END sr[511]
  PIN sr[51]
    DIRECTION OUTPUT ;
    USE SIGNAL ;
    PORT
      LAYER M5 ;
        RECT  30.96 151.116 30.984 151.2 ;
    END
  END sr[51]
  PIN sr[52]
    DIRECTION OUTPUT ;
    USE SIGNAL ;
    PORT
      LAYER M5 ;
        RECT  31.056 151.116 31.08 151.2 ;
    END
  END sr[52]
  PIN sr[53]
    DIRECTION OUTPUT ;
    USE SIGNAL ;
    PORT
      LAYER M5 ;
        RECT  31.152 151.116 31.176 151.2 ;
    END
  END sr[53]
  PIN sr[54]
    DIRECTION OUTPUT ;
    USE SIGNAL ;
    PORT
      LAYER M5 ;
        RECT  31.248 151.116 31.272 151.2 ;
    END
  END sr[54]
  PIN sr[55]
    DIRECTION OUTPUT ;
    USE SIGNAL ;
    PORT
      LAYER M5 ;
        RECT  31.344 151.116 31.368 151.2 ;
    END
  END sr[55]
  PIN sr[56]
    DIRECTION OUTPUT ;
    USE SIGNAL ;
    PORT
      LAYER M5 ;
        RECT  31.44 151.116 31.464 151.2 ;
    END
  END sr[56]
  PIN sr[57]
    DIRECTION OUTPUT ;
    USE SIGNAL ;
    PORT
      LAYER M5 ;
        RECT  31.536 151.116 31.56 151.2 ;
    END
  END sr[57]
  PIN sr[58]
    DIRECTION OUTPUT ;
    USE SIGNAL ;
    PORT
      LAYER M5 ;
        RECT  31.632 151.116 31.656 151.2 ;
    END
  END sr[58]
  PIN sr[59]
    DIRECTION OUTPUT ;
    USE SIGNAL ;
    PORT
      LAYER M5 ;
        RECT  31.728 151.116 31.752 151.2 ;
    END
  END sr[59]
  PIN sr[5]
    DIRECTION OUTPUT ;
    USE SIGNAL ;
    PORT
      LAYER M5 ;
        RECT  32.688 151.116 32.712 151.2 ;
    END
  END sr[5]
  PIN sr[60]
    DIRECTION OUTPUT ;
    USE SIGNAL ;
    PORT
      LAYER M5 ;
        RECT  31.824 151.116 31.848 151.2 ;
    END
  END sr[60]
  PIN sr[61]
    DIRECTION OUTPUT ;
    USE SIGNAL ;
    PORT
      LAYER M5 ;
        RECT  31.92 151.116 31.944 151.2 ;
    END
  END sr[61]
  PIN sr[62]
    DIRECTION OUTPUT ;
    USE SIGNAL ;
    PORT
      LAYER M5 ;
        RECT  32.016 151.116 32.04 151.2 ;
    END
  END sr[62]
  PIN sr[63]
    DIRECTION OUTPUT ;
    USE SIGNAL ;
    PORT
      LAYER M5 ;
        RECT  32.112 151.116 32.136 151.2 ;
    END
  END sr[63]
  PIN sr[64]
    DIRECTION OUTPUT ;
    USE SIGNAL ;
    PORT
      LAYER M5 ;
        RECT  19.92 151.116 19.944 151.2 ;
    END
  END sr[64]
  PIN sr[65]
    DIRECTION OUTPUT ;
    USE SIGNAL ;
    PORT
      LAYER M5 ;
        RECT  20.016 151.116 20.04 151.2 ;
    END
  END sr[65]
  PIN sr[66]
    DIRECTION OUTPUT ;
    USE SIGNAL ;
    PORT
      LAYER M5 ;
        RECT  20.112 151.116 20.136 151.2 ;
    END
  END sr[66]
  PIN sr[67]
    DIRECTION OUTPUT ;
    USE SIGNAL ;
    PORT
      LAYER M5 ;
        RECT  20.208 151.116 20.232 151.2 ;
    END
  END sr[67]
  PIN sr[68]
    DIRECTION OUTPUT ;
    USE SIGNAL ;
    PORT
      LAYER M5 ;
        RECT  20.304 151.116 20.328 151.2 ;
    END
  END sr[68]
  PIN sr[69]
    DIRECTION OUTPUT ;
    USE SIGNAL ;
    PORT
      LAYER M5 ;
        RECT  20.4 151.116 20.424 151.2 ;
    END
  END sr[69]
  PIN sr[6]
    DIRECTION OUTPUT ;
    USE SIGNAL ;
    PORT
      LAYER M5 ;
        RECT  32.784 151.116 32.808 151.2 ;
    END
  END sr[6]
  PIN sr[70]
    DIRECTION OUTPUT ;
    USE SIGNAL ;
    PORT
      LAYER M5 ;
        RECT  20.496 151.116 20.52 151.2 ;
    END
  END sr[70]
  PIN sr[71]
    DIRECTION OUTPUT ;
    USE SIGNAL ;
    PORT
      LAYER M5 ;
        RECT  20.592 151.116 20.616 151.2 ;
    END
  END sr[71]
  PIN sr[72]
    DIRECTION OUTPUT ;
    USE SIGNAL ;
    PORT
      LAYER M5 ;
        RECT  20.688 151.116 20.712 151.2 ;
    END
  END sr[72]
  PIN sr[73]
    DIRECTION OUTPUT ;
    USE SIGNAL ;
    PORT
      LAYER M5 ;
        RECT  20.784 151.116 20.808 151.2 ;
    END
  END sr[73]
  PIN sr[74]
    DIRECTION OUTPUT ;
    USE SIGNAL ;
    PORT
      LAYER M5 ;
        RECT  20.88 151.116 20.904 151.2 ;
    END
  END sr[74]
  PIN sr[75]
    DIRECTION OUTPUT ;
    USE SIGNAL ;
    PORT
      LAYER M5 ;
        RECT  20.976 151.116 21 151.2 ;
    END
  END sr[75]
  PIN sr[76]
    DIRECTION OUTPUT ;
    USE SIGNAL ;
    PORT
      LAYER M5 ;
        RECT  21.072 151.116 21.096 151.2 ;
    END
  END sr[76]
  PIN sr[77]
    DIRECTION OUTPUT ;
    USE SIGNAL ;
    PORT
      LAYER M5 ;
        RECT  21.168 151.116 21.192 151.2 ;
    END
  END sr[77]
  PIN sr[78]
    DIRECTION OUTPUT ;
    USE SIGNAL ;
    PORT
      LAYER M5 ;
        RECT  21.264 151.116 21.288 151.2 ;
    END
  END sr[78]
  PIN sr[79]
    DIRECTION OUTPUT ;
    USE SIGNAL ;
    PORT
      LAYER M5 ;
        RECT  21.36 151.116 21.384 151.2 ;
    END
  END sr[79]
  PIN sr[7]
    DIRECTION OUTPUT ;
    USE SIGNAL ;
    PORT
      LAYER M5 ;
        RECT  32.88 151.116 32.904 151.2 ;
    END
  END sr[7]
  PIN sr[80]
    DIRECTION OUTPUT ;
    USE SIGNAL ;
    PORT
      LAYER M5 ;
        RECT  21.456 151.116 21.48 151.2 ;
    END
  END sr[80]
  PIN sr[81]
    DIRECTION OUTPUT ;
    USE SIGNAL ;
    PORT
      LAYER M5 ;
        RECT  21.552 151.116 21.576 151.2 ;
    END
  END sr[81]
  PIN sr[82]
    DIRECTION OUTPUT ;
    USE SIGNAL ;
    PORT
      LAYER M5 ;
        RECT  21.648 151.116 21.672 151.2 ;
    END
  END sr[82]
  PIN sr[83]
    DIRECTION OUTPUT ;
    USE SIGNAL ;
    PORT
      LAYER M5 ;
        RECT  21.744 151.116 21.768 151.2 ;
    END
  END sr[83]
  PIN sr[84]
    DIRECTION OUTPUT ;
    USE SIGNAL ;
    PORT
      LAYER M5 ;
        RECT  21.84 151.116 21.864 151.2 ;
    END
  END sr[84]
  PIN sr[85]
    DIRECTION OUTPUT ;
    USE SIGNAL ;
    PORT
      LAYER M5 ;
        RECT  21.936 151.116 21.96 151.2 ;
    END
  END sr[85]
  PIN sr[86]
    DIRECTION OUTPUT ;
    USE SIGNAL ;
    PORT
      LAYER M5 ;
        RECT  22.032 151.116 22.056 151.2 ;
    END
  END sr[86]
  PIN sr[87]
    DIRECTION OUTPUT ;
    USE SIGNAL ;
    PORT
      LAYER M5 ;
        RECT  22.128 151.116 22.152 151.2 ;
    END
  END sr[87]
  PIN sr[88]
    DIRECTION OUTPUT ;
    USE SIGNAL ;
    PORT
      LAYER M5 ;
        RECT  22.224 151.116 22.248 151.2 ;
    END
  END sr[88]
  PIN sr[89]
    DIRECTION OUTPUT ;
    USE SIGNAL ;
    PORT
      LAYER M5 ;
        RECT  22.32 151.116 22.344 151.2 ;
    END
  END sr[89]
  PIN sr[8]
    DIRECTION OUTPUT ;
    USE SIGNAL ;
    PORT
      LAYER M5 ;
        RECT  32.976 151.116 33 151.2 ;
    END
  END sr[8]
  PIN sr[90]
    DIRECTION OUTPUT ;
    USE SIGNAL ;
    PORT
      LAYER M5 ;
        RECT  22.416 151.116 22.44 151.2 ;
    END
  END sr[90]
  PIN sr[91]
    DIRECTION OUTPUT ;
    USE SIGNAL ;
    PORT
      LAYER M5 ;
        RECT  22.512 151.116 22.536 151.2 ;
    END
  END sr[91]
  PIN sr[92]
    DIRECTION OUTPUT ;
    USE SIGNAL ;
    PORT
      LAYER M5 ;
        RECT  22.608 151.116 22.632 151.2 ;
    END
  END sr[92]
  PIN sr[93]
    DIRECTION OUTPUT ;
    USE SIGNAL ;
    PORT
      LAYER M5 ;
        RECT  22.704 151.116 22.728 151.2 ;
    END
  END sr[93]
  PIN sr[94]
    DIRECTION OUTPUT ;
    USE SIGNAL ;
    PORT
      LAYER M5 ;
        RECT  22.8 151.116 22.824 151.2 ;
    END
  END sr[94]
  PIN sr[95]
    DIRECTION OUTPUT ;
    USE SIGNAL ;
    PORT
      LAYER M5 ;
        RECT  22.896 151.116 22.92 151.2 ;
    END
  END sr[95]
  PIN sr[96]
    DIRECTION OUTPUT ;
    USE SIGNAL ;
    PORT
      LAYER M5 ;
        RECT  22.992 151.116 23.016 151.2 ;
    END
  END sr[96]
  PIN sr[97]
    DIRECTION OUTPUT ;
    USE SIGNAL ;
    PORT
      LAYER M5 ;
        RECT  23.088 151.116 23.112 151.2 ;
    END
  END sr[97]
  PIN sr[98]
    DIRECTION OUTPUT ;
    USE SIGNAL ;
    PORT
      LAYER M5 ;
        RECT  23.184 151.116 23.208 151.2 ;
    END
  END sr[98]
  PIN sr[99]
    DIRECTION OUTPUT ;
    USE SIGNAL ;
    PORT
      LAYER M5 ;
        RECT  23.28 151.116 23.304 151.2 ;
    END
  END sr[99]
  PIN sr[9]
    DIRECTION OUTPUT ;
    USE SIGNAL ;
    PORT
      LAYER M5 ;
        RECT  33.072 151.116 33.096 151.2 ;
    END
  END sr[9]
  PIN VDD
    DIRECTION INOUT ;
    USE POWER ;
    PORT
      LAYER M5 ;
        RECT  148.392 2.151 148.512 149.049 ;
        RECT  142.992 2.151 143.112 149.049 ;
        RECT  137.592 2.151 137.712 149.049 ;
        RECT  132.192 2.151 132.312 149.049 ;
        RECT  126.792 2.151 126.912 149.049 ;
        RECT  121.392 2.151 121.512 149.049 ;
        RECT  115.992 2.151 116.112 149.049 ;
        RECT  110.592 2.151 110.712 149.049 ;
        RECT  105.192 2.151 105.312 149.049 ;
        RECT  99.792 2.151 99.912 149.049 ;
        RECT  94.392 2.151 94.512 149.049 ;
        RECT  88.992 2.151 89.112 149.049 ;
        RECT  83.592 2.151 83.712 149.049 ;
        RECT  78.192 2.151 78.312 149.049 ;
        RECT  72.792 2.151 72.912 149.049 ;
        RECT  67.392 2.151 67.512 149.049 ;
        RECT  61.992 2.151 62.112 149.049 ;
        RECT  56.592 2.151 56.712 149.049 ;
        RECT  51.192 2.151 51.312 149.049 ;
        RECT  45.792 2.151 45.912 149.049 ;
        RECT  40.392 2.151 40.512 149.049 ;
        RECT  34.992 2.151 35.112 149.049 ;
        RECT  29.592 2.151 29.712 149.049 ;
        RECT  24.192 2.151 24.312 149.049 ;
        RECT  18.792 2.151 18.912 149.049 ;
        RECT  13.392 2.151 13.512 149.049 ;
        RECT  7.992 2.151 8.112 149.049 ;
        RECT  2.592 2.151 2.712 149.049 ;
    END
  END VDD
  PIN VSS
    DIRECTION INOUT ;
    USE GROUND ;
    PORT
      LAYER M5 ;
        RECT  148.2 2.137 148.32 149.063 ;
        RECT  142.8 2.137 142.92 149.063 ;
        RECT  137.4 2.137 137.52 149.063 ;
        RECT  132 2.137 132.12 149.063 ;
        RECT  126.6 2.137 126.72 149.063 ;
        RECT  121.2 2.137 121.32 149.063 ;
        RECT  115.8 2.137 115.92 149.063 ;
        RECT  110.4 2.137 110.52 149.063 ;
        RECT  105 2.137 105.12 149.063 ;
        RECT  99.6 2.137 99.72 149.063 ;
        RECT  94.2 2.137 94.32 149.063 ;
        RECT  88.8 2.137 88.92 149.063 ;
        RECT  83.4 2.137 83.52 149.063 ;
        RECT  78 2.137 78.12 149.063 ;
        RECT  72.6 2.137 72.72 149.063 ;
        RECT  67.2 2.137 67.32 149.063 ;
        RECT  61.8 2.137 61.92 149.063 ;
        RECT  56.4 2.137 56.52 149.063 ;
        RECT  51 2.137 51.12 149.063 ;
        RECT  45.6 2.137 45.72 149.063 ;
        RECT  40.2 2.137 40.32 149.063 ;
        RECT  34.8 2.137 34.92 149.063 ;
        RECT  29.4 2.137 29.52 149.063 ;
        RECT  24 2.137 24.12 149.063 ;
        RECT  18.6 2.137 18.72 149.063 ;
        RECT  13.2 2.137 13.32 149.063 ;
        RECT  7.8 2.137 7.92 149.063 ;
        RECT  2.4 2.137 2.52 149.063 ;
    END
  END VSS
  OBS
    LAYER RVTN ;
     RECT  2.16 2.16 149.04 2.295 ;
     RECT  2.16 2.565 149.04 2.835 ;
     RECT  2.16 3.105 149.04 3.375 ;
     RECT  2.16 3.645 149.04 3.915 ;
     RECT  2.16 4.185 149.04 4.455 ;
     RECT  2.16 4.725 149.04 4.995 ;
     RECT  2.16 5.265 149.04 5.535 ;
     RECT  2.16 5.805 149.04 6.075 ;
     RECT  2.16 6.345 149.04 6.615 ;
     RECT  2.16 6.885 149.04 7.155 ;
     RECT  2.16 7.425 149.04 7.695 ;
     RECT  2.16 7.965 149.04 8.235 ;
     RECT  2.16 8.505 149.04 8.775 ;
     RECT  2.16 9.045 149.04 9.315 ;
     RECT  2.16 9.585 149.04 9.855 ;
     RECT  2.16 10.125 149.04 10.395 ;
     RECT  2.16 10.665 149.04 10.935 ;
     RECT  2.16 11.205 149.04 11.475 ;
     RECT  2.16 11.745 149.04 12.015 ;
     RECT  2.16 12.285 149.04 12.555 ;
     RECT  2.16 12.825 149.04 13.095 ;
     RECT  2.16 13.365 149.04 13.635 ;
     RECT  2.16 13.905 149.04 14.175 ;
     RECT  2.16 14.445 149.04 14.715 ;
     RECT  2.16 14.985 149.04 15.255 ;
     RECT  2.16 15.525 149.04 15.795 ;
     RECT  2.16 16.065 149.04 16.335 ;
     RECT  2.16 16.605 149.04 16.875 ;
     RECT  2.16 17.145 149.04 17.415 ;
     RECT  2.16 17.685 149.04 17.955 ;
     RECT  2.16 18.225 149.04 18.495 ;
     RECT  2.16 18.765 149.04 19.035 ;
     RECT  2.16 19.305 149.04 19.575 ;
     RECT  2.16 19.845 149.04 20.115 ;
     RECT  2.16 20.385 149.04 20.655 ;
     RECT  2.16 20.925 149.04 21.195 ;
     RECT  2.16 21.465 149.04 21.6 ;
     RECT  2.16 21.6 26.028 21.735 ;
     RECT  124.956 21.6 149.04 21.735 ;
     RECT  2.16 22.005 26.028 22.275 ;
     RECT  124.956 22.005 149.04 22.275 ;
     RECT  2.16 22.545 26.028 22.815 ;
     RECT  124.956 22.545 149.04 22.815 ;
     RECT  2.16 23.085 26.028 23.355 ;
     RECT  124.956 23.085 149.04 23.355 ;
     RECT  2.16 23.625 26.028 23.895 ;
     RECT  124.956 23.625 149.04 23.895 ;
     RECT  2.16 24.165 26.028 24.435 ;
     RECT  124.956 24.165 149.04 24.435 ;
     RECT  2.16 24.705 26.028 24.975 ;
     RECT  124.956 24.705 149.04 24.975 ;
     RECT  2.16 25.245 26.028 25.515 ;
     RECT  124.956 25.245 149.04 25.515 ;
     RECT  2.16 25.785 26.028 26.055 ;
     RECT  124.956 25.785 149.04 26.055 ;
     RECT  2.16 26.325 26.028 26.595 ;
     RECT  124.956 26.325 149.04 26.595 ;
     RECT  2.16 26.865 26.028 27.135 ;
     RECT  124.956 26.865 149.04 27.135 ;
     RECT  2.16 27.405 26.028 27.675 ;
     RECT  124.956 27.405 149.04 27.675 ;
     RECT  2.16 27.945 26.028 28.215 ;
     RECT  124.956 27.945 149.04 28.215 ;
     RECT  2.16 28.485 26.028 28.755 ;
     RECT  124.956 28.485 149.04 28.755 ;
     RECT  2.16 29.025 26.028 29.295 ;
     RECT  124.956 29.025 149.04 29.295 ;
     RECT  2.16 29.565 26.028 29.835 ;
     RECT  124.956 29.565 149.04 29.835 ;
     RECT  2.16 30.105 26.028 30.375 ;
     RECT  124.956 30.105 149.04 30.375 ;
     RECT  2.16 30.645 26.028 30.915 ;
     RECT  124.956 30.645 149.04 30.915 ;
     RECT  2.16 31.185 26.028 31.455 ;
     RECT  124.956 31.185 149.04 31.455 ;
     RECT  2.16 31.725 26.028 31.995 ;
     RECT  124.956 31.725 149.04 31.995 ;
     RECT  2.16 32.265 26.028 32.535 ;
     RECT  124.956 32.265 149.04 32.535 ;
     RECT  2.16 32.805 26.028 33.075 ;
     RECT  124.956 32.805 149.04 33.075 ;
     RECT  2.16 33.345 26.028 33.615 ;
     RECT  124.956 33.345 149.04 33.615 ;
     RECT  2.16 33.885 26.028 34.155 ;
     RECT  124.956 33.885 149.04 34.155 ;
     RECT  2.16 34.425 26.028 34.695 ;
     RECT  124.956 34.425 149.04 34.695 ;
     RECT  2.16 34.965 26.028 35.235 ;
     RECT  124.956 34.965 149.04 35.235 ;
     RECT  2.16 35.505 26.028 35.775 ;
     RECT  124.956 35.505 149.04 35.775 ;
     RECT  2.16 36.045 26.028 36.315 ;
     RECT  124.956 36.045 149.04 36.315 ;
     RECT  2.16 36.585 26.028 36.855 ;
     RECT  124.956 36.585 149.04 36.855 ;
     RECT  2.16 37.125 26.028 37.395 ;
     RECT  124.956 37.125 149.04 37.395 ;
     RECT  2.16 37.665 26.028 37.935 ;
     RECT  124.956 37.665 149.04 37.935 ;
     RECT  2.16 38.205 26.028 38.475 ;
     RECT  124.956 38.205 149.04 38.475 ;
     RECT  2.16 38.745 26.028 39.015 ;
     RECT  124.956 38.745 149.04 39.015 ;
     RECT  2.16 39.285 26.028 39.555 ;
     RECT  124.956 39.285 149.04 39.555 ;
     RECT  2.16 39.825 26.028 40.095 ;
     RECT  124.956 39.825 149.04 40.095 ;
     RECT  2.16 40.365 26.028 40.635 ;
     RECT  124.956 40.365 149.04 40.635 ;
     RECT  2.16 40.905 26.028 41.175 ;
     RECT  124.956 40.905 149.04 41.175 ;
     RECT  2.16 41.445 26.028 41.715 ;
     RECT  124.956 41.445 149.04 41.715 ;
     RECT  2.16 41.985 26.028 42.255 ;
     RECT  124.956 41.985 149.04 42.255 ;
     RECT  2.16 42.525 26.028 42.795 ;
     RECT  124.956 42.525 149.04 42.795 ;
     RECT  2.16 43.065 26.028 43.335 ;
     RECT  124.956 43.065 149.04 43.335 ;
     RECT  2.16 43.605 26.028 43.875 ;
     RECT  124.956 43.605 149.04 43.875 ;
     RECT  2.16 44.145 26.028 44.415 ;
     RECT  124.956 44.145 149.04 44.415 ;
     RECT  2.16 44.685 26.028 44.955 ;
     RECT  124.956 44.685 149.04 44.955 ;
     RECT  2.16 45.225 26.028 45.495 ;
     RECT  124.956 45.225 149.04 45.495 ;
     RECT  2.16 45.765 26.028 46.035 ;
     RECT  124.956 45.765 149.04 46.035 ;
     RECT  2.16 46.305 26.028 46.575 ;
     RECT  124.956 46.305 149.04 46.575 ;
     RECT  2.16 46.845 26.028 47.115 ;
     RECT  124.956 46.845 149.04 47.115 ;
     RECT  2.16 47.385 26.028 47.655 ;
     RECT  124.956 47.385 149.04 47.655 ;
     RECT  2.16 47.925 26.028 48.195 ;
     RECT  124.956 47.925 149.04 48.195 ;
     RECT  2.16 48.465 26.028 48.735 ;
     RECT  124.956 48.465 149.04 48.735 ;
     RECT  2.16 49.005 26.028 49.275 ;
     RECT  124.956 49.005 149.04 49.275 ;
     RECT  2.16 49.545 26.028 49.815 ;
     RECT  124.956 49.545 149.04 49.815 ;
     RECT  2.16 50.085 26.028 50.355 ;
     RECT  124.956 50.085 149.04 50.355 ;
     RECT  2.16 50.625 26.028 50.895 ;
     RECT  124.956 50.625 149.04 50.895 ;
     RECT  2.16 51.165 26.028 51.435 ;
     RECT  124.956 51.165 149.04 51.435 ;
     RECT  2.16 51.705 26.028 51.975 ;
     RECT  124.956 51.705 149.04 51.975 ;
     RECT  2.16 52.245 26.028 52.515 ;
     RECT  124.956 52.245 149.04 52.515 ;
     RECT  2.16 52.785 26.028 53.055 ;
     RECT  124.956 52.785 149.04 53.055 ;
     RECT  2.16 53.325 26.028 53.595 ;
     RECT  124.956 53.325 149.04 53.595 ;
     RECT  2.16 53.865 26.028 54.135 ;
     RECT  124.956 53.865 149.04 54.135 ;
     RECT  2.16 54.405 26.028 54.675 ;
     RECT  124.956 54.405 149.04 54.675 ;
     RECT  2.16 54.945 26.028 55.215 ;
     RECT  124.956 54.945 149.04 55.215 ;
     RECT  2.16 55.485 26.028 55.755 ;
     RECT  124.956 55.485 149.04 55.755 ;
     RECT  2.16 56.025 26.028 56.295 ;
     RECT  124.956 56.025 149.04 56.295 ;
     RECT  2.16 56.565 26.028 56.835 ;
     RECT  124.956 56.565 149.04 56.835 ;
     RECT  2.16 57.105 26.028 57.375 ;
     RECT  124.956 57.105 149.04 57.375 ;
     RECT  2.16 57.645 26.028 57.915 ;
     RECT  124.956 57.645 149.04 57.915 ;
     RECT  2.16 58.185 26.028 58.455 ;
     RECT  124.956 58.185 149.04 58.455 ;
     RECT  2.16 58.725 26.028 58.995 ;
     RECT  124.956 58.725 149.04 58.995 ;
     RECT  2.16 59.265 26.028 59.535 ;
     RECT  124.956 59.265 149.04 59.535 ;
     RECT  2.16 59.805 26.028 60.075 ;
     RECT  124.956 59.805 149.04 60.075 ;
     RECT  2.16 60.345 26.028 60.615 ;
     RECT  124.956 60.345 149.04 60.615 ;
     RECT  2.16 60.885 26.028 61.155 ;
     RECT  124.956 60.885 149.04 61.155 ;
     RECT  2.16 61.425 26.028 61.695 ;
     RECT  124.956 61.425 149.04 61.695 ;
     RECT  2.16 61.965 26.028 62.235 ;
     RECT  124.956 61.965 149.04 62.235 ;
     RECT  2.16 62.505 26.028 62.775 ;
     RECT  124.956 62.505 149.04 62.775 ;
     RECT  2.16 63.045 26.028 63.315 ;
     RECT  124.956 63.045 149.04 63.315 ;
     RECT  2.16 63.585 26.028 63.855 ;
     RECT  124.956 63.585 149.04 63.855 ;
     RECT  2.16 64.125 26.028 64.395 ;
     RECT  124.956 64.125 149.04 64.395 ;
     RECT  2.16 64.665 26.028 64.935 ;
     RECT  124.956 64.665 149.04 64.935 ;
     RECT  2.16 65.205 26.028 65.475 ;
     RECT  124.956 65.205 149.04 65.475 ;
     RECT  2.16 65.745 26.028 66.015 ;
     RECT  124.956 65.745 149.04 66.015 ;
     RECT  2.16 66.285 26.028 66.555 ;
     RECT  124.956 66.285 149.04 66.555 ;
     RECT  2.16 66.825 26.028 66.96 ;
     RECT  124.956 66.825 149.04 66.96 ;
     RECT  2.16 66.96 149.04 67.095 ;
     RECT  2.16 67.365 149.04 67.635 ;
     RECT  2.16 67.905 149.04 68.175 ;
     RECT  2.16 68.445 149.04 68.715 ;
     RECT  2.16 68.985 149.04 69.255 ;
     RECT  2.16 69.525 149.04 69.795 ;
     RECT  2.16 70.065 149.04 70.335 ;
     RECT  2.16 70.605 149.04 70.875 ;
     RECT  2.16 71.145 149.04 71.415 ;
     RECT  2.16 71.685 149.04 71.955 ;
     RECT  2.16 72.225 149.04 72.495 ;
     RECT  2.16 72.765 149.04 73.035 ;
     RECT  2.16 73.305 149.04 73.575 ;
     RECT  2.16 73.845 149.04 74.115 ;
     RECT  2.16 74.385 149.04 74.655 ;
     RECT  2.16 74.925 149.04 75.195 ;
     RECT  2.16 75.465 149.04 75.735 ;
     RECT  2.16 76.005 149.04 76.275 ;
     RECT  2.16 76.545 149.04 76.815 ;
     RECT  2.16 77.085 149.04 77.355 ;
     RECT  2.16 77.625 149.04 77.895 ;
     RECT  2.16 78.165 149.04 78.435 ;
     RECT  2.16 78.705 149.04 78.975 ;
     RECT  2.16 79.245 149.04 79.515 ;
     RECT  2.16 79.785 149.04 80.055 ;
     RECT  2.16 80.325 149.04 80.595 ;
     RECT  2.16 80.865 149.04 81.135 ;
     RECT  2.16 81.405 149.04 81.675 ;
     RECT  2.16 81.945 149.04 82.215 ;
     RECT  2.16 82.485 149.04 82.755 ;
     RECT  2.16 83.025 149.04 83.295 ;
     RECT  2.16 83.565 149.04 83.835 ;
     RECT  2.16 84.105 149.04 84.24 ;
     RECT  2.16 84.24 26.028 84.375 ;
     RECT  124.956 84.24 149.04 84.375 ;
     RECT  2.16 84.645 26.028 84.915 ;
     RECT  124.956 84.645 149.04 84.915 ;
     RECT  2.16 85.185 26.028 85.455 ;
     RECT  124.956 85.185 149.04 85.455 ;
     RECT  2.16 85.725 26.028 85.995 ;
     RECT  124.956 85.725 149.04 85.995 ;
     RECT  2.16 86.265 26.028 86.535 ;
     RECT  124.956 86.265 149.04 86.535 ;
     RECT  2.16 86.805 26.028 87.075 ;
     RECT  124.956 86.805 149.04 87.075 ;
     RECT  2.16 87.345 26.028 87.615 ;
     RECT  124.956 87.345 149.04 87.615 ;
     RECT  2.16 87.885 26.028 88.155 ;
     RECT  124.956 87.885 149.04 88.155 ;
     RECT  2.16 88.425 26.028 88.695 ;
     RECT  124.956 88.425 149.04 88.695 ;
     RECT  2.16 88.965 26.028 89.235 ;
     RECT  124.956 88.965 149.04 89.235 ;
     RECT  2.16 89.505 26.028 89.775 ;
     RECT  124.956 89.505 149.04 89.775 ;
     RECT  2.16 90.045 26.028 90.315 ;
     RECT  124.956 90.045 149.04 90.315 ;
     RECT  2.16 90.585 26.028 90.855 ;
     RECT  124.956 90.585 149.04 90.855 ;
     RECT  2.16 91.125 26.028 91.395 ;
     RECT  124.956 91.125 149.04 91.395 ;
     RECT  2.16 91.665 26.028 91.935 ;
     RECT  124.956 91.665 149.04 91.935 ;
     RECT  2.16 92.205 26.028 92.475 ;
     RECT  124.956 92.205 149.04 92.475 ;
     RECT  2.16 92.745 26.028 93.015 ;
     RECT  124.956 92.745 149.04 93.015 ;
     RECT  2.16 93.285 26.028 93.555 ;
     RECT  124.956 93.285 149.04 93.555 ;
     RECT  2.16 93.825 26.028 94.095 ;
     RECT  124.956 93.825 149.04 94.095 ;
     RECT  2.16 94.365 26.028 94.635 ;
     RECT  124.956 94.365 149.04 94.635 ;
     RECT  2.16 94.905 26.028 95.175 ;
     RECT  124.956 94.905 149.04 95.175 ;
     RECT  2.16 95.445 26.028 95.715 ;
     RECT  124.956 95.445 149.04 95.715 ;
     RECT  2.16 95.985 26.028 96.255 ;
     RECT  124.956 95.985 149.04 96.255 ;
     RECT  2.16 96.525 26.028 96.795 ;
     RECT  124.956 96.525 149.04 96.795 ;
     RECT  2.16 97.065 26.028 97.335 ;
     RECT  124.956 97.065 149.04 97.335 ;
     RECT  2.16 97.605 26.028 97.875 ;
     RECT  124.956 97.605 149.04 97.875 ;
     RECT  2.16 98.145 26.028 98.415 ;
     RECT  124.956 98.145 149.04 98.415 ;
     RECT  2.16 98.685 26.028 98.955 ;
     RECT  124.956 98.685 149.04 98.955 ;
     RECT  2.16 99.225 26.028 99.495 ;
     RECT  124.956 99.225 149.04 99.495 ;
     RECT  2.16 99.765 26.028 100.035 ;
     RECT  124.956 99.765 149.04 100.035 ;
     RECT  2.16 100.305 26.028 100.575 ;
     RECT  124.956 100.305 149.04 100.575 ;
     RECT  2.16 100.845 26.028 101.115 ;
     RECT  124.956 100.845 149.04 101.115 ;
     RECT  2.16 101.385 26.028 101.655 ;
     RECT  124.956 101.385 149.04 101.655 ;
     RECT  2.16 101.925 26.028 102.195 ;
     RECT  124.956 101.925 149.04 102.195 ;
     RECT  2.16 102.465 26.028 102.735 ;
     RECT  124.956 102.465 149.04 102.735 ;
     RECT  2.16 103.005 26.028 103.275 ;
     RECT  124.956 103.005 149.04 103.275 ;
     RECT  2.16 103.545 26.028 103.815 ;
     RECT  124.956 103.545 149.04 103.815 ;
     RECT  2.16 104.085 26.028 104.355 ;
     RECT  124.956 104.085 149.04 104.355 ;
     RECT  2.16 104.625 26.028 104.895 ;
     RECT  124.956 104.625 149.04 104.895 ;
     RECT  2.16 105.165 26.028 105.435 ;
     RECT  124.956 105.165 149.04 105.435 ;
     RECT  2.16 105.705 26.028 105.975 ;
     RECT  124.956 105.705 149.04 105.975 ;
     RECT  2.16 106.245 26.028 106.515 ;
     RECT  124.956 106.245 149.04 106.515 ;
     RECT  2.16 106.785 26.028 107.055 ;
     RECT  124.956 106.785 149.04 107.055 ;
     RECT  2.16 107.325 26.028 107.595 ;
     RECT  124.956 107.325 149.04 107.595 ;
     RECT  2.16 107.865 26.028 108.135 ;
     RECT  124.956 107.865 149.04 108.135 ;
     RECT  2.16 108.405 26.028 108.675 ;
     RECT  124.956 108.405 149.04 108.675 ;
     RECT  2.16 108.945 26.028 109.215 ;
     RECT  124.956 108.945 149.04 109.215 ;
     RECT  2.16 109.485 26.028 109.755 ;
     RECT  124.956 109.485 149.04 109.755 ;
     RECT  2.16 110.025 26.028 110.295 ;
     RECT  124.956 110.025 149.04 110.295 ;
     RECT  2.16 110.565 26.028 110.835 ;
     RECT  124.956 110.565 149.04 110.835 ;
     RECT  2.16 111.105 26.028 111.375 ;
     RECT  124.956 111.105 149.04 111.375 ;
     RECT  2.16 111.645 26.028 111.915 ;
     RECT  124.956 111.645 149.04 111.915 ;
     RECT  2.16 112.185 26.028 112.455 ;
     RECT  124.956 112.185 149.04 112.455 ;
     RECT  2.16 112.725 26.028 112.995 ;
     RECT  124.956 112.725 149.04 112.995 ;
     RECT  2.16 113.265 26.028 113.535 ;
     RECT  124.956 113.265 149.04 113.535 ;
     RECT  2.16 113.805 26.028 114.075 ;
     RECT  124.956 113.805 149.04 114.075 ;
     RECT  2.16 114.345 26.028 114.615 ;
     RECT  124.956 114.345 149.04 114.615 ;
     RECT  2.16 114.885 26.028 115.155 ;
     RECT  124.956 114.885 149.04 115.155 ;
     RECT  2.16 115.425 26.028 115.695 ;
     RECT  124.956 115.425 149.04 115.695 ;
     RECT  2.16 115.965 26.028 116.235 ;
     RECT  124.956 115.965 149.04 116.235 ;
     RECT  2.16 116.505 26.028 116.775 ;
     RECT  124.956 116.505 149.04 116.775 ;
     RECT  2.16 117.045 26.028 117.315 ;
     RECT  124.956 117.045 149.04 117.315 ;
     RECT  2.16 117.585 26.028 117.855 ;
     RECT  124.956 117.585 149.04 117.855 ;
     RECT  2.16 118.125 26.028 118.395 ;
     RECT  124.956 118.125 149.04 118.395 ;
     RECT  2.16 118.665 26.028 118.935 ;
     RECT  124.956 118.665 149.04 118.935 ;
     RECT  2.16 119.205 26.028 119.475 ;
     RECT  124.956 119.205 149.04 119.475 ;
     RECT  2.16 119.745 26.028 120.015 ;
     RECT  124.956 119.745 149.04 120.015 ;
     RECT  2.16 120.285 26.028 120.555 ;
     RECT  124.956 120.285 149.04 120.555 ;
     RECT  2.16 120.825 26.028 121.095 ;
     RECT  124.956 120.825 149.04 121.095 ;
     RECT  2.16 121.365 26.028 121.635 ;
     RECT  124.956 121.365 149.04 121.635 ;
     RECT  2.16 121.905 26.028 122.175 ;
     RECT  124.956 121.905 149.04 122.175 ;
     RECT  2.16 122.445 26.028 122.715 ;
     RECT  124.956 122.445 149.04 122.715 ;
     RECT  2.16 122.985 26.028 123.255 ;
     RECT  124.956 122.985 149.04 123.255 ;
     RECT  2.16 123.525 26.028 123.795 ;
     RECT  124.956 123.525 149.04 123.795 ;
     RECT  2.16 124.065 26.028 124.335 ;
     RECT  124.956 124.065 149.04 124.335 ;
     RECT  2.16 124.605 26.028 124.875 ;
     RECT  124.956 124.605 149.04 124.875 ;
     RECT  2.16 125.145 26.028 125.415 ;
     RECT  124.956 125.145 149.04 125.415 ;
     RECT  2.16 125.685 26.028 125.955 ;
     RECT  124.956 125.685 149.04 125.955 ;
     RECT  2.16 126.225 26.028 126.495 ;
     RECT  124.956 126.225 149.04 126.495 ;
     RECT  2.16 126.765 26.028 127.035 ;
     RECT  124.956 126.765 149.04 127.035 ;
     RECT  2.16 127.305 26.028 127.575 ;
     RECT  124.956 127.305 149.04 127.575 ;
     RECT  2.16 127.845 26.028 128.115 ;
     RECT  124.956 127.845 149.04 128.115 ;
     RECT  2.16 128.385 26.028 128.655 ;
     RECT  124.956 128.385 149.04 128.655 ;
     RECT  2.16 128.925 26.028 129.195 ;
     RECT  124.956 128.925 149.04 129.195 ;
     RECT  2.16 129.465 26.028 129.6 ;
     RECT  124.956 129.465 149.04 129.6 ;
     RECT  2.16 129.6 149.04 129.735 ;
     RECT  2.16 130.005 149.04 130.275 ;
     RECT  2.16 130.545 149.04 130.815 ;
     RECT  2.16 131.085 149.04 131.355 ;
     RECT  2.16 131.625 149.04 131.895 ;
     RECT  2.16 132.165 149.04 132.435 ;
     RECT  2.16 132.705 149.04 132.975 ;
     RECT  2.16 133.245 149.04 133.515 ;
     RECT  2.16 133.785 149.04 134.055 ;
     RECT  2.16 134.325 149.04 134.595 ;
     RECT  2.16 134.865 149.04 135.135 ;
     RECT  2.16 135.405 149.04 135.675 ;
     RECT  2.16 135.945 149.04 136.215 ;
     RECT  2.16 136.485 149.04 136.755 ;
     RECT  2.16 137.025 149.04 137.295 ;
     RECT  2.16 137.565 149.04 137.835 ;
     RECT  2.16 138.105 149.04 138.375 ;
     RECT  2.16 138.645 149.04 138.915 ;
     RECT  2.16 139.185 149.04 139.455 ;
     RECT  2.16 139.725 149.04 139.995 ;
     RECT  2.16 140.265 149.04 140.535 ;
     RECT  2.16 140.805 149.04 141.075 ;
     RECT  2.16 141.345 149.04 141.615 ;
     RECT  2.16 141.885 149.04 142.155 ;
     RECT  2.16 142.425 149.04 142.695 ;
     RECT  2.16 142.965 149.04 143.235 ;
     RECT  2.16 143.505 149.04 143.775 ;
     RECT  2.16 144.045 149.04 144.315 ;
     RECT  2.16 144.585 149.04 144.855 ;
     RECT  2.16 145.125 149.04 145.395 ;
     RECT  2.16 145.665 149.04 145.935 ;
     RECT  2.16 146.205 149.04 146.475 ;
     RECT  2.16 146.745 149.04 147.015 ;
     RECT  2.16 147.285 149.04 147.555 ;
     RECT  2.16 147.825 149.04 148.095 ;
     RECT  2.16 148.365 149.04 148.635 ;
     RECT  2.16 148.905 149.04 149.04 ;
    LAYER RVTP ;
     RECT  2.16 2.295 149.04 2.565 ;
     RECT  2.16 2.835 149.04 3.105 ;
     RECT  2.16 3.375 149.04 3.645 ;
     RECT  2.16 3.915 149.04 4.185 ;
     RECT  2.16 4.455 149.04 4.725 ;
     RECT  2.16 4.995 149.04 5.265 ;
     RECT  2.16 5.535 149.04 5.805 ;
     RECT  2.16 6.075 149.04 6.345 ;
     RECT  2.16 6.615 149.04 6.885 ;
     RECT  2.16 7.155 149.04 7.425 ;
     RECT  2.16 7.695 149.04 7.965 ;
     RECT  2.16 8.235 149.04 8.505 ;
     RECT  2.16 8.775 149.04 9.045 ;
     RECT  2.16 9.315 149.04 9.585 ;
     RECT  2.16 9.855 149.04 10.125 ;
     RECT  2.16 10.395 149.04 10.665 ;
     RECT  2.16 10.935 149.04 11.205 ;
     RECT  2.16 11.475 149.04 11.745 ;
     RECT  2.16 12.015 149.04 12.285 ;
     RECT  2.16 12.555 149.04 12.825 ;
     RECT  2.16 13.095 149.04 13.365 ;
     RECT  2.16 13.635 149.04 13.905 ;
     RECT  2.16 14.175 149.04 14.445 ;
     RECT  2.16 14.715 149.04 14.985 ;
     RECT  2.16 15.255 149.04 15.525 ;
     RECT  2.16 15.795 149.04 16.065 ;
     RECT  2.16 16.335 149.04 16.605 ;
     RECT  2.16 16.875 149.04 17.145 ;
     RECT  2.16 17.415 149.04 17.685 ;
     RECT  2.16 17.955 149.04 18.225 ;
     RECT  2.16 18.495 149.04 18.765 ;
     RECT  2.16 19.035 149.04 19.305 ;
     RECT  2.16 19.575 149.04 19.845 ;
     RECT  2.16 20.115 149.04 20.385 ;
     RECT  2.16 20.655 149.04 20.925 ;
     RECT  2.16 21.195 149.04 21.465 ;
     RECT  2.16 21.735 26.028 22.005 ;
     RECT  124.956 21.735 149.04 22.005 ;
     RECT  2.16 22.275 26.028 22.545 ;
     RECT  124.956 22.275 149.04 22.545 ;
     RECT  2.16 22.815 26.028 23.085 ;
     RECT  124.956 22.815 149.04 23.085 ;
     RECT  2.16 23.355 26.028 23.625 ;
     RECT  124.956 23.355 149.04 23.625 ;
     RECT  2.16 23.895 26.028 24.165 ;
     RECT  124.956 23.895 149.04 24.165 ;
     RECT  2.16 24.435 26.028 24.705 ;
     RECT  124.956 24.435 149.04 24.705 ;
     RECT  2.16 24.975 26.028 25.245 ;
     RECT  124.956 24.975 149.04 25.245 ;
     RECT  2.16 25.515 26.028 25.785 ;
     RECT  124.956 25.515 149.04 25.785 ;
     RECT  2.16 26.055 26.028 26.325 ;
     RECT  124.956 26.055 149.04 26.325 ;
     RECT  2.16 26.595 26.028 26.865 ;
     RECT  124.956 26.595 149.04 26.865 ;
     RECT  2.16 27.135 26.028 27.405 ;
     RECT  124.956 27.135 149.04 27.405 ;
     RECT  2.16 27.675 26.028 27.945 ;
     RECT  124.956 27.675 149.04 27.945 ;
     RECT  2.16 28.215 26.028 28.485 ;
     RECT  124.956 28.215 149.04 28.485 ;
     RECT  2.16 28.755 26.028 29.025 ;
     RECT  124.956 28.755 149.04 29.025 ;
     RECT  2.16 29.295 26.028 29.565 ;
     RECT  124.956 29.295 149.04 29.565 ;
     RECT  2.16 29.835 26.028 30.105 ;
     RECT  124.956 29.835 149.04 30.105 ;
     RECT  2.16 30.375 26.028 30.645 ;
     RECT  124.956 30.375 149.04 30.645 ;
     RECT  2.16 30.915 26.028 31.185 ;
     RECT  124.956 30.915 149.04 31.185 ;
     RECT  2.16 31.455 26.028 31.725 ;
     RECT  124.956 31.455 149.04 31.725 ;
     RECT  2.16 31.995 26.028 32.265 ;
     RECT  124.956 31.995 149.04 32.265 ;
     RECT  2.16 32.535 26.028 32.805 ;
     RECT  124.956 32.535 149.04 32.805 ;
     RECT  2.16 33.075 26.028 33.345 ;
     RECT  124.956 33.075 149.04 33.345 ;
     RECT  2.16 33.615 26.028 33.885 ;
     RECT  124.956 33.615 149.04 33.885 ;
     RECT  2.16 34.155 26.028 34.425 ;
     RECT  124.956 34.155 149.04 34.425 ;
     RECT  2.16 34.695 26.028 34.965 ;
     RECT  124.956 34.695 149.04 34.965 ;
     RECT  2.16 35.235 26.028 35.505 ;
     RECT  124.956 35.235 149.04 35.505 ;
     RECT  2.16 35.775 26.028 36.045 ;
     RECT  124.956 35.775 149.04 36.045 ;
     RECT  2.16 36.315 26.028 36.585 ;
     RECT  124.956 36.315 149.04 36.585 ;
     RECT  2.16 36.855 26.028 37.125 ;
     RECT  124.956 36.855 149.04 37.125 ;
     RECT  2.16 37.395 26.028 37.665 ;
     RECT  124.956 37.395 149.04 37.665 ;
     RECT  2.16 37.935 26.028 38.205 ;
     RECT  124.956 37.935 149.04 38.205 ;
     RECT  2.16 38.475 26.028 38.745 ;
     RECT  124.956 38.475 149.04 38.745 ;
     RECT  2.16 39.015 26.028 39.285 ;
     RECT  124.956 39.015 149.04 39.285 ;
     RECT  2.16 39.555 26.028 39.825 ;
     RECT  124.956 39.555 149.04 39.825 ;
     RECT  2.16 40.095 26.028 40.365 ;
     RECT  124.956 40.095 149.04 40.365 ;
     RECT  2.16 40.635 26.028 40.905 ;
     RECT  124.956 40.635 149.04 40.905 ;
     RECT  2.16 41.175 26.028 41.445 ;
     RECT  124.956 41.175 149.04 41.445 ;
     RECT  2.16 41.715 26.028 41.985 ;
     RECT  124.956 41.715 149.04 41.985 ;
     RECT  2.16 42.255 26.028 42.525 ;
     RECT  124.956 42.255 149.04 42.525 ;
     RECT  2.16 42.795 26.028 43.065 ;
     RECT  124.956 42.795 149.04 43.065 ;
     RECT  2.16 43.335 26.028 43.605 ;
     RECT  124.956 43.335 149.04 43.605 ;
     RECT  2.16 43.875 26.028 44.145 ;
     RECT  124.956 43.875 149.04 44.145 ;
     RECT  2.16 44.415 26.028 44.685 ;
     RECT  124.956 44.415 149.04 44.685 ;
     RECT  2.16 44.955 26.028 45.225 ;
     RECT  124.956 44.955 149.04 45.225 ;
     RECT  2.16 45.495 26.028 45.765 ;
     RECT  124.956 45.495 149.04 45.765 ;
     RECT  2.16 46.035 26.028 46.305 ;
     RECT  124.956 46.035 149.04 46.305 ;
     RECT  2.16 46.575 26.028 46.845 ;
     RECT  124.956 46.575 149.04 46.845 ;
     RECT  2.16 47.115 26.028 47.385 ;
     RECT  124.956 47.115 149.04 47.385 ;
     RECT  2.16 47.655 26.028 47.925 ;
     RECT  124.956 47.655 149.04 47.925 ;
     RECT  2.16 48.195 26.028 48.465 ;
     RECT  124.956 48.195 149.04 48.465 ;
     RECT  2.16 48.735 26.028 49.005 ;
     RECT  124.956 48.735 149.04 49.005 ;
     RECT  2.16 49.275 26.028 49.545 ;
     RECT  124.956 49.275 149.04 49.545 ;
     RECT  2.16 49.815 26.028 50.085 ;
     RECT  124.956 49.815 149.04 50.085 ;
     RECT  2.16 50.355 26.028 50.625 ;
     RECT  124.956 50.355 149.04 50.625 ;
     RECT  2.16 50.895 26.028 51.165 ;
     RECT  124.956 50.895 149.04 51.165 ;
     RECT  2.16 51.435 26.028 51.705 ;
     RECT  124.956 51.435 149.04 51.705 ;
     RECT  2.16 51.975 26.028 52.245 ;
     RECT  124.956 51.975 149.04 52.245 ;
     RECT  2.16 52.515 26.028 52.785 ;
     RECT  124.956 52.515 149.04 52.785 ;
     RECT  2.16 53.055 26.028 53.325 ;
     RECT  124.956 53.055 149.04 53.325 ;
     RECT  2.16 53.595 26.028 53.865 ;
     RECT  124.956 53.595 149.04 53.865 ;
     RECT  2.16 54.135 26.028 54.405 ;
     RECT  124.956 54.135 149.04 54.405 ;
     RECT  2.16 54.675 26.028 54.945 ;
     RECT  124.956 54.675 149.04 54.945 ;
     RECT  2.16 55.215 26.028 55.485 ;
     RECT  124.956 55.215 149.04 55.485 ;
     RECT  2.16 55.755 26.028 56.025 ;
     RECT  124.956 55.755 149.04 56.025 ;
     RECT  2.16 56.295 26.028 56.565 ;
     RECT  124.956 56.295 149.04 56.565 ;
     RECT  2.16 56.835 26.028 57.105 ;
     RECT  124.956 56.835 149.04 57.105 ;
     RECT  2.16 57.375 26.028 57.645 ;
     RECT  124.956 57.375 149.04 57.645 ;
     RECT  2.16 57.915 26.028 58.185 ;
     RECT  124.956 57.915 149.04 58.185 ;
     RECT  2.16 58.455 26.028 58.725 ;
     RECT  124.956 58.455 149.04 58.725 ;
     RECT  2.16 58.995 26.028 59.265 ;
     RECT  124.956 58.995 149.04 59.265 ;
     RECT  2.16 59.535 26.028 59.805 ;
     RECT  124.956 59.535 149.04 59.805 ;
     RECT  2.16 60.075 26.028 60.345 ;
     RECT  124.956 60.075 149.04 60.345 ;
     RECT  2.16 60.615 26.028 60.885 ;
     RECT  124.956 60.615 149.04 60.885 ;
     RECT  2.16 61.155 26.028 61.425 ;
     RECT  124.956 61.155 149.04 61.425 ;
     RECT  2.16 61.695 26.028 61.965 ;
     RECT  124.956 61.695 149.04 61.965 ;
     RECT  2.16 62.235 26.028 62.505 ;
     RECT  124.956 62.235 149.04 62.505 ;
     RECT  2.16 62.775 26.028 63.045 ;
     RECT  124.956 62.775 149.04 63.045 ;
     RECT  2.16 63.315 26.028 63.585 ;
     RECT  124.956 63.315 149.04 63.585 ;
     RECT  2.16 63.855 26.028 64.125 ;
     RECT  124.956 63.855 149.04 64.125 ;
     RECT  2.16 64.395 26.028 64.665 ;
     RECT  124.956 64.395 149.04 64.665 ;
     RECT  2.16 64.935 26.028 65.205 ;
     RECT  124.956 64.935 149.04 65.205 ;
     RECT  2.16 65.475 26.028 65.745 ;
     RECT  124.956 65.475 149.04 65.745 ;
     RECT  2.16 66.015 26.028 66.285 ;
     RECT  124.956 66.015 149.04 66.285 ;
     RECT  2.16 66.555 26.028 66.825 ;
     RECT  124.956 66.555 149.04 66.825 ;
     RECT  2.16 67.095 149.04 67.365 ;
     RECT  2.16 67.635 149.04 67.905 ;
     RECT  2.16 68.175 149.04 68.445 ;
     RECT  2.16 68.715 149.04 68.985 ;
     RECT  2.16 69.255 149.04 69.525 ;
     RECT  2.16 69.795 149.04 70.065 ;
     RECT  2.16 70.335 149.04 70.605 ;
     RECT  2.16 70.875 149.04 71.145 ;
     RECT  2.16 71.415 149.04 71.685 ;
     RECT  2.16 71.955 149.04 72.225 ;
     RECT  2.16 72.495 149.04 72.765 ;
     RECT  2.16 73.035 149.04 73.305 ;
     RECT  2.16 73.575 149.04 73.845 ;
     RECT  2.16 74.115 149.04 74.385 ;
     RECT  2.16 74.655 149.04 74.925 ;
     RECT  2.16 75.195 149.04 75.465 ;
     RECT  2.16 75.735 149.04 76.005 ;
     RECT  2.16 76.275 149.04 76.545 ;
     RECT  2.16 76.815 149.04 77.085 ;
     RECT  2.16 77.355 149.04 77.625 ;
     RECT  2.16 77.895 149.04 78.165 ;
     RECT  2.16 78.435 149.04 78.705 ;
     RECT  2.16 78.975 149.04 79.245 ;
     RECT  2.16 79.515 149.04 79.785 ;
     RECT  2.16 80.055 149.04 80.325 ;
     RECT  2.16 80.595 149.04 80.865 ;
     RECT  2.16 81.135 149.04 81.405 ;
     RECT  2.16 81.675 149.04 81.945 ;
     RECT  2.16 82.215 149.04 82.485 ;
     RECT  2.16 82.755 149.04 83.025 ;
     RECT  2.16 83.295 149.04 83.565 ;
     RECT  2.16 83.835 149.04 84.105 ;
     RECT  2.16 84.375 26.028 84.645 ;
     RECT  124.956 84.375 149.04 84.645 ;
     RECT  2.16 84.915 26.028 85.185 ;
     RECT  124.956 84.915 149.04 85.185 ;
     RECT  2.16 85.455 26.028 85.725 ;
     RECT  124.956 85.455 149.04 85.725 ;
     RECT  2.16 85.995 26.028 86.265 ;
     RECT  124.956 85.995 149.04 86.265 ;
     RECT  2.16 86.535 26.028 86.805 ;
     RECT  124.956 86.535 149.04 86.805 ;
     RECT  2.16 87.075 26.028 87.345 ;
     RECT  124.956 87.075 149.04 87.345 ;
     RECT  2.16 87.615 26.028 87.885 ;
     RECT  124.956 87.615 149.04 87.885 ;
     RECT  2.16 88.155 26.028 88.425 ;
     RECT  124.956 88.155 149.04 88.425 ;
     RECT  2.16 88.695 26.028 88.965 ;
     RECT  124.956 88.695 149.04 88.965 ;
     RECT  2.16 89.235 26.028 89.505 ;
     RECT  124.956 89.235 149.04 89.505 ;
     RECT  2.16 89.775 26.028 90.045 ;
     RECT  124.956 89.775 149.04 90.045 ;
     RECT  2.16 90.315 26.028 90.585 ;
     RECT  124.956 90.315 149.04 90.585 ;
     RECT  2.16 90.855 26.028 91.125 ;
     RECT  124.956 90.855 149.04 91.125 ;
     RECT  2.16 91.395 26.028 91.665 ;
     RECT  124.956 91.395 149.04 91.665 ;
     RECT  2.16 91.935 26.028 92.205 ;
     RECT  124.956 91.935 149.04 92.205 ;
     RECT  2.16 92.475 26.028 92.745 ;
     RECT  124.956 92.475 149.04 92.745 ;
     RECT  2.16 93.015 26.028 93.285 ;
     RECT  124.956 93.015 149.04 93.285 ;
     RECT  2.16 93.555 26.028 93.825 ;
     RECT  124.956 93.555 149.04 93.825 ;
     RECT  2.16 94.095 26.028 94.365 ;
     RECT  124.956 94.095 149.04 94.365 ;
     RECT  2.16 94.635 26.028 94.905 ;
     RECT  124.956 94.635 149.04 94.905 ;
     RECT  2.16 95.175 26.028 95.445 ;
     RECT  124.956 95.175 149.04 95.445 ;
     RECT  2.16 95.715 26.028 95.985 ;
     RECT  124.956 95.715 149.04 95.985 ;
     RECT  2.16 96.255 26.028 96.525 ;
     RECT  124.956 96.255 149.04 96.525 ;
     RECT  2.16 96.795 26.028 97.065 ;
     RECT  124.956 96.795 149.04 97.065 ;
     RECT  2.16 97.335 26.028 97.605 ;
     RECT  124.956 97.335 149.04 97.605 ;
     RECT  2.16 97.875 26.028 98.145 ;
     RECT  124.956 97.875 149.04 98.145 ;
     RECT  2.16 98.415 26.028 98.685 ;
     RECT  124.956 98.415 149.04 98.685 ;
     RECT  2.16 98.955 26.028 99.225 ;
     RECT  124.956 98.955 149.04 99.225 ;
     RECT  2.16 99.495 26.028 99.765 ;
     RECT  124.956 99.495 149.04 99.765 ;
     RECT  2.16 100.035 26.028 100.305 ;
     RECT  124.956 100.035 149.04 100.305 ;
     RECT  2.16 100.575 26.028 100.845 ;
     RECT  124.956 100.575 149.04 100.845 ;
     RECT  2.16 101.115 26.028 101.385 ;
     RECT  124.956 101.115 149.04 101.385 ;
     RECT  2.16 101.655 26.028 101.925 ;
     RECT  124.956 101.655 149.04 101.925 ;
     RECT  2.16 102.195 26.028 102.465 ;
     RECT  124.956 102.195 149.04 102.465 ;
     RECT  2.16 102.735 26.028 103.005 ;
     RECT  124.956 102.735 149.04 103.005 ;
     RECT  2.16 103.275 26.028 103.545 ;
     RECT  124.956 103.275 149.04 103.545 ;
     RECT  2.16 103.815 26.028 104.085 ;
     RECT  124.956 103.815 149.04 104.085 ;
     RECT  2.16 104.355 26.028 104.625 ;
     RECT  124.956 104.355 149.04 104.625 ;
     RECT  2.16 104.895 26.028 105.165 ;
     RECT  124.956 104.895 149.04 105.165 ;
     RECT  2.16 105.435 26.028 105.705 ;
     RECT  124.956 105.435 149.04 105.705 ;
     RECT  2.16 105.975 26.028 106.245 ;
     RECT  124.956 105.975 149.04 106.245 ;
     RECT  2.16 106.515 26.028 106.785 ;
     RECT  124.956 106.515 149.04 106.785 ;
     RECT  2.16 107.055 26.028 107.325 ;
     RECT  124.956 107.055 149.04 107.325 ;
     RECT  2.16 107.595 26.028 107.865 ;
     RECT  124.956 107.595 149.04 107.865 ;
     RECT  2.16 108.135 26.028 108.405 ;
     RECT  124.956 108.135 149.04 108.405 ;
     RECT  2.16 108.675 26.028 108.945 ;
     RECT  124.956 108.675 149.04 108.945 ;
     RECT  2.16 109.215 26.028 109.485 ;
     RECT  124.956 109.215 149.04 109.485 ;
     RECT  2.16 109.755 26.028 110.025 ;
     RECT  124.956 109.755 149.04 110.025 ;
     RECT  2.16 110.295 26.028 110.565 ;
     RECT  124.956 110.295 149.04 110.565 ;
     RECT  2.16 110.835 26.028 111.105 ;
     RECT  124.956 110.835 149.04 111.105 ;
     RECT  2.16 111.375 26.028 111.645 ;
     RECT  124.956 111.375 149.04 111.645 ;
     RECT  2.16 111.915 26.028 112.185 ;
     RECT  124.956 111.915 149.04 112.185 ;
     RECT  2.16 112.455 26.028 112.725 ;
     RECT  124.956 112.455 149.04 112.725 ;
     RECT  2.16 112.995 26.028 113.265 ;
     RECT  124.956 112.995 149.04 113.265 ;
     RECT  2.16 113.535 26.028 113.805 ;
     RECT  124.956 113.535 149.04 113.805 ;
     RECT  2.16 114.075 26.028 114.345 ;
     RECT  124.956 114.075 149.04 114.345 ;
     RECT  2.16 114.615 26.028 114.885 ;
     RECT  124.956 114.615 149.04 114.885 ;
     RECT  2.16 115.155 26.028 115.425 ;
     RECT  124.956 115.155 149.04 115.425 ;
     RECT  2.16 115.695 26.028 115.965 ;
     RECT  124.956 115.695 149.04 115.965 ;
     RECT  2.16 116.235 26.028 116.505 ;
     RECT  124.956 116.235 149.04 116.505 ;
     RECT  2.16 116.775 26.028 117.045 ;
     RECT  124.956 116.775 149.04 117.045 ;
     RECT  2.16 117.315 26.028 117.585 ;
     RECT  124.956 117.315 149.04 117.585 ;
     RECT  2.16 117.855 26.028 118.125 ;
     RECT  124.956 117.855 149.04 118.125 ;
     RECT  2.16 118.395 26.028 118.665 ;
     RECT  124.956 118.395 149.04 118.665 ;
     RECT  2.16 118.935 26.028 119.205 ;
     RECT  124.956 118.935 149.04 119.205 ;
     RECT  2.16 119.475 26.028 119.745 ;
     RECT  124.956 119.475 149.04 119.745 ;
     RECT  2.16 120.015 26.028 120.285 ;
     RECT  124.956 120.015 149.04 120.285 ;
     RECT  2.16 120.555 26.028 120.825 ;
     RECT  124.956 120.555 149.04 120.825 ;
     RECT  2.16 121.095 26.028 121.365 ;
     RECT  124.956 121.095 149.04 121.365 ;
     RECT  2.16 121.635 26.028 121.905 ;
     RECT  124.956 121.635 149.04 121.905 ;
     RECT  2.16 122.175 26.028 122.445 ;
     RECT  124.956 122.175 149.04 122.445 ;
     RECT  2.16 122.715 26.028 122.985 ;
     RECT  124.956 122.715 149.04 122.985 ;
     RECT  2.16 123.255 26.028 123.525 ;
     RECT  124.956 123.255 149.04 123.525 ;
     RECT  2.16 123.795 26.028 124.065 ;
     RECT  124.956 123.795 149.04 124.065 ;
     RECT  2.16 124.335 26.028 124.605 ;
     RECT  124.956 124.335 149.04 124.605 ;
     RECT  2.16 124.875 26.028 125.145 ;
     RECT  124.956 124.875 149.04 125.145 ;
     RECT  2.16 125.415 26.028 125.685 ;
     RECT  124.956 125.415 149.04 125.685 ;
     RECT  2.16 125.955 26.028 126.225 ;
     RECT  124.956 125.955 149.04 126.225 ;
     RECT  2.16 126.495 26.028 126.765 ;
     RECT  124.956 126.495 149.04 126.765 ;
     RECT  2.16 127.035 26.028 127.305 ;
     RECT  124.956 127.035 149.04 127.305 ;
     RECT  2.16 127.575 26.028 127.845 ;
     RECT  124.956 127.575 149.04 127.845 ;
     RECT  2.16 128.115 26.028 128.385 ;
     RECT  124.956 128.115 149.04 128.385 ;
     RECT  2.16 128.655 26.028 128.925 ;
     RECT  124.956 128.655 149.04 128.925 ;
     RECT  2.16 129.195 26.028 129.465 ;
     RECT  124.956 129.195 149.04 129.465 ;
     RECT  2.16 129.735 149.04 130.005 ;
     RECT  2.16 130.275 149.04 130.545 ;
     RECT  2.16 130.815 149.04 131.085 ;
     RECT  2.16 131.355 149.04 131.625 ;
     RECT  2.16 131.895 149.04 132.165 ;
     RECT  2.16 132.435 149.04 132.705 ;
     RECT  2.16 132.975 149.04 133.245 ;
     RECT  2.16 133.515 149.04 133.785 ;
     RECT  2.16 134.055 149.04 134.325 ;
     RECT  2.16 134.595 149.04 134.865 ;
     RECT  2.16 135.135 149.04 135.405 ;
     RECT  2.16 135.675 149.04 135.945 ;
     RECT  2.16 136.215 149.04 136.485 ;
     RECT  2.16 136.755 149.04 137.025 ;
     RECT  2.16 137.295 149.04 137.565 ;
     RECT  2.16 137.835 149.04 138.105 ;
     RECT  2.16 138.375 149.04 138.645 ;
     RECT  2.16 138.915 149.04 139.185 ;
     RECT  2.16 139.455 149.04 139.725 ;
     RECT  2.16 139.995 149.04 140.265 ;
     RECT  2.16 140.535 149.04 140.805 ;
     RECT  2.16 141.075 149.04 141.345 ;
     RECT  2.16 141.615 149.04 141.885 ;
     RECT  2.16 142.155 149.04 142.425 ;
     RECT  2.16 142.695 149.04 142.965 ;
     RECT  2.16 143.235 149.04 143.505 ;
     RECT  2.16 143.775 149.04 144.045 ;
     RECT  2.16 144.315 149.04 144.585 ;
     RECT  2.16 144.855 149.04 145.125 ;
     RECT  2.16 145.395 149.04 145.665 ;
     RECT  2.16 145.935 149.04 146.205 ;
     RECT  2.16 146.475 149.04 146.745 ;
     RECT  2.16 147.015 149.04 147.285 ;
     RECT  2.16 147.555 149.04 147.825 ;
     RECT  2.16 148.095 149.04 148.365 ;
     RECT  2.16 148.635 149.04 148.905 ;
    LAYER M1 ;
     RECT  2.16 2.151 149.04 21.609 ;
     RECT  28.08 23.76 122.904 64.824 ;
     RECT  2.16 21.609 26.028 66.951 ;
     RECT  124.956 21.609 149.04 66.951 ;
     RECT  2.16 66.951 149.04 84.249 ;
     RECT  28.08 86.4 122.904 127.464 ;
     RECT  2.16 84.249 26.028 129.591 ;
     RECT  124.956 84.249 149.04 129.591 ;
     RECT  2.16 129.591 149.04 149.049 ;
    LAYER M2 ;
     RECT  1.651 143.136 1.687 143.154 ;
     RECT  1.723 137.736 2.16 137.754 ;
     RECT  1.687 143.136 2.16 143.496 ;
     RECT  1.111 144.396 2.16 144.414 ;
     RECT  1.687 146.286 2.16 146.394 ;
     RECT  2.16 2.151 2.695 149.049 ;
     RECT  2.695 2.151 3.911 149.166 ;
     RECT  3.911 2.151 4.487 149.094 ;
     RECT  4.487 2.151 7.087 149.049 ;
     RECT  7.087 2.151 8.815 149.094 ;
     RECT  16.555 1.152 16.727 1.17 ;
     RECT  14.719 151.11 17.347 151.128 ;
     RECT  17.347 151.038 17.447 151.128 ;
     RECT  8.815 2.151 17.491 149.634 ;
     RECT  17.491 2.151 18.175 149.67 ;
     RECT  17.447 151.11 20.479 151.128 ;
     RECT  20.479 151.11 21.695 151.164 ;
     RECT  21.695 151.146 24.943 151.164 ;
     RECT  24.907 0.108 25.231 0.126 ;
     RECT  25.231 0.108 25.951 0.549 ;
     RECT  18.175 2.151 26.028 149.778 ;
     RECT  26.028 66.798 26.051 84.249 ;
     RECT  26.028 24.876 26.087 64.152 ;
     RECT  26.028 110.538 26.231 122.274 ;
     RECT  25.951 0.036 26.267 0.549 ;
     RECT  26.028 123.228 26.267 149.778 ;
     RECT  26.028 65.988 26.411 66.006 ;
     RECT  26.028 86.661 26.555 109.674 ;
     RECT  26.087 24.876 26.627 62.46 ;
     RECT  26.267 127.116 26.671 149.778 ;
     RECT  24.943 151.11 26.671 151.164 ;
     RECT  26.627 60.894 26.699 60.984 ;
     RECT  26.699 60.894 26.735 60.912 ;
     RECT  26.231 110.538 26.771 122.202 ;
     RECT  26.671 150.768 26.771 151.164 ;
     RECT  26.627 24.876 26.807 60.138 ;
     RECT  26.555 86.661 26.807 97.83 ;
     RECT  26.028 2.151 26.815 21.654 ;
     RECT  26.028 22.518 26.815 23.724 ;
     RECT  26.627 62.244 26.815 62.46 ;
     RECT  26.815 62.244 26.851 62.649 ;
     RECT  26.771 111.816 26.879 122.202 ;
     RECT  26.879 111.816 26.915 118.764 ;
     RECT  26.771 110.538 26.951 111.024 ;
     RECT  26.555 98.622 26.987 109.674 ;
     RECT  26.879 119.646 26.987 122.202 ;
     RECT  26.987 119.826 27.023 122.202 ;
     RECT  26.987 99.126 27.059 109.674 ;
     RECT  26.807 86.661 27.095 86.832 ;
     RECT  26.915 111.816 27.095 118.458 ;
     RECT  26.807 24.876 27.131 55.98 ;
     RECT  27.095 86.814 27.131 86.832 ;
     RECT  26.851 62.244 27.167 62.802 ;
     RECT  26.267 123.228 27.175 126.144 ;
     RECT  26.807 60.12 27.203 60.138 ;
     RECT  26.951 110.538 27.203 110.754 ;
     RECT  26.051 66.951 27.211 84.249 ;
     RECT  27.059 99.126 27.275 107.244 ;
     RECT  27.131 26.37 27.311 55.98 ;
     RECT  26.807 56.88 27.311 59.256 ;
     RECT  26.807 88.011 27.311 97.83 ;
     RECT  27.131 24.876 27.347 25.434 ;
     RECT  27.311 26.37 27.347 46.062 ;
     RECT  27.311 46.926 27.347 55.98 ;
     RECT  27.175 123.228 27.347 126.216 ;
     RECT  26.923 65.871 27.463 65.889 ;
     RECT  27.211 66.906 27.535 84.249 ;
     RECT  27.023 119.826 27.751 120.78 ;
     RECT  27.023 121.608 27.751 122.202 ;
     RECT  27.311 58.896 27.787 59.256 ;
     RECT  27.535 66.87 27.787 84.249 ;
     RECT  26.267 0.036 27.815 0.504 ;
     RECT  27.787 66.834 27.823 84.249 ;
     RECT  27.275 99.126 27.823 106.704 ;
     RECT  27.823 66.798 27.859 84.249 ;
     RECT  26.815 2.151 28.08 23.724 ;
     RECT  27.347 25.146 28.08 25.434 ;
     RECT  27.347 26.37 28.08 29.088 ;
     RECT  27.347 30.006 28.08 33.642 ;
     RECT  27.347 34.47 28.08 45.954 ;
     RECT  27.347 46.926 28.08 50.112 ;
     RECT  27.347 50.868 28.08 53.856 ;
     RECT  27.347 54.684 28.08 55.98 ;
     RECT  27.311 56.88 28.08 57.978 ;
     RECT  27.787 58.896 28.08 59.679 ;
     RECT  27.167 62.244 28.08 62.73 ;
     RECT  26.087 63.594 28.08 64.152 ;
     RECT  26.028 64.908 28.08 64.926 ;
     RECT  27.311 88.011 28.08 94.014 ;
     RECT  27.311 94.986 28.08 97.83 ;
     RECT  27.823 98.694 28.08 106.704 ;
     RECT  27.059 108.036 28.08 109.674 ;
     RECT  27.203 110.538 28.08 110.592 ;
     RECT  27.095 111.816 28.08 118.224 ;
     RECT  27.751 119.826 28.08 122.202 ;
     RECT  27.347 123.228 28.08 125.91 ;
     RECT  26.671 127.116 28.08 149.904 ;
     RECT  28.08 2.151 28.247 64.926 ;
     RECT  27.815 0.036 28.391 0.054 ;
     RECT  28.247 2.151 31.379 64.824 ;
     RECT  31.379 22.86 31.595 64.824 ;
     RECT  28.08 86.4 31.991 149.904 ;
     RECT  31.379 2.151 32.243 21.96 ;
     RECT  26.771 151.074 32.639 151.164 ;
     RECT  32.639 151.146 33.107 151.164 ;
     RECT  31.595 23.058 33.647 64.824 ;
     RECT  31.991 86.4 33.935 149.859 ;
     RECT  33.935 86.4 34.951 149.319 ;
     RECT  34.951 86.4 35.303 149.364 ;
     RECT  35.303 86.4 36.239 149.319 ;
     RECT  36.239 128.511 38.795 149.319 ;
     RECT  38.983 150.381 39.055 150.399 ;
     RECT  39.055 150.381 39.119 150.48 ;
     RECT  39.119 150.462 39.263 150.48 ;
     RECT  27.859 66.726 39.955 84.249 ;
     RECT  38.795 128.511 40.171 149.166 ;
     RECT  40.171 128.511 40.379 149.436 ;
     RECT  40.603 150.381 40.819 150.399 ;
     RECT  27.463 65.826 40.883 65.889 ;
     RECT  40.819 150.381 40.919 150.48 ;
     RECT  40.883 65.826 41.999 65.844 ;
     RECT  39.955 66.636 42.179 84.249 ;
     RECT  42.043 150.462 42.179 150.48 ;
     RECT  40.379 128.511 42.287 149.166 ;
     RECT  46.291 149.994 46.391 150.012 ;
     RECT  42.287 128.511 49.631 149.049 ;
     RECT  49.631 128.511 53.051 128.529 ;
     RECT  42.179 66.726 55.103 84.249 ;
     RECT  32.243 2.151 101.911 21.609 ;
     RECT  49.631 129.276 107.735 149.049 ;
     RECT  107.735 129.51 107.807 149.049 ;
     RECT  109.039 0.036 109.111 0.054 ;
     RECT  33.647 23.76 109.615 64.824 ;
     RECT  109.111 0.036 109.687 0.126 ;
     RECT  112.279 1.152 112.379 1.17 ;
     RECT  109.615 23.364 118.607 64.824 ;
     RECT  101.911 2.151 118.795 21.96 ;
     RECT  118.795 2.151 120.091 21.996 ;
     RECT  118.607 23.481 120.739 64.824 ;
     RECT  120.739 23.058 122.904 64.824 ;
     RECT  36.239 86.4 122.904 127.464 ;
     RECT  122.904 23.058 123.007 23.724 ;
     RECT  122.904 27.756 123.035 28.008 ;
     RECT  122.904 94.176 123.035 95.742 ;
     RECT  123.007 22.986 123.143 23.724 ;
     RECT  122.904 62.631 123.143 62.73 ;
     RECT  122.904 35.856 123.179 38.736 ;
     RECT  123.143 22.986 123.187 23.652 ;
     RECT  55.103 66.951 123.187 84.249 ;
     RECT  123.187 22.941 123.223 23.652 ;
     RECT  123.187 66.726 123.287 84.249 ;
     RECT  122.904 26.451 123.323 26.469 ;
     RECT  122.904 86.544 123.323 86.634 ;
     RECT  109.687 0.036 123.467 0.162 ;
     RECT  123.323 86.616 123.539 86.634 ;
     RECT  123.223 22.824 123.683 23.652 ;
     RECT  122.904 29.034 123.683 29.628 ;
     RECT  122.904 30.501 123.683 31.104 ;
     RECT  122.904 97.416 123.683 97.434 ;
     RECT  122.904 98.316 123.683 100.764 ;
     RECT  123.035 27.756 123.727 27.936 ;
     RECT  123.467 0.036 123.755 0.09 ;
     RECT  123.683 22.896 123.791 23.652 ;
     RECT  123.727 27.036 123.827 27.936 ;
     RECT  123.791 22.896 123.863 23.382 ;
     RECT  122.904 88.866 123.979 88.884 ;
     RECT  122.904 89.856 123.979 89.874 ;
     RECT  123.863 23.022 124.007 23.382 ;
     RECT  123.035 94.374 124.231 95.742 ;
     RECT  122.904 33.354 124.267 34.074 ;
     RECT  123.179 35.856 124.267 38.196 ;
     RECT  123.287 66.951 124.267 84.249 ;
     RECT  124.267 50.364 124.303 50.382 ;
     RECT  124.267 54.846 124.303 54.864 ;
     RECT  124.267 64.602 124.303 64.62 ;
     RECT  124.303 50.364 124.339 50.454 ;
     RECT  124.267 56.61 124.339 56.628 ;
     RECT  124.339 49.401 124.375 49.419 ;
     RECT  123.979 88.866 124.519 89.874 ;
     RECT  122.904 126.396 124.519 126.414 ;
     RECT  123.683 98.496 124.663 100.764 ;
     RECT  124.663 98.19 124.699 100.764 ;
     RECT  123.683 30.726 124.807 30.744 ;
     RECT  124.771 31.806 124.807 31.824 ;
     RECT  123.827 27.756 124.843 27.936 ;
     RECT  124.267 33.354 124.843 34.794 ;
     RECT  124.267 35.856 124.843 38.772 ;
     RECT  124.267 41.724 124.843 41.814 ;
     RECT  124.267 46.746 124.843 46.764 ;
     RECT  124.375 49.014 124.843 49.419 ;
     RECT  124.339 50.364 124.843 50.922 ;
     RECT  124.267 52.83 124.843 52.848 ;
     RECT  124.303 54.306 124.843 55.548 ;
     RECT  124.339 56.61 124.843 56.979 ;
     RECT  124.267 57.924 124.843 57.942 ;
     RECT  124.267 66.636 124.843 84.249 ;
     RECT  124.231 93.798 124.843 95.742 ;
     RECT  122.904 104.166 124.843 104.184 ;
     RECT  122.904 105.372 124.843 105.39 ;
     RECT  122.904 106.452 124.843 106.47 ;
     RECT  122.904 108.846 124.843 109.944 ;
     RECT  122.904 114.552 124.843 114.57 ;
     RECT  122.904 119.646 124.843 119.664 ;
     RECT  122.904 124.146 124.843 124.164 ;
     RECT  124.843 27.756 124.879 28.746 ;
     RECT  124.807 30.726 124.879 31.824 ;
     RECT  124.843 33.084 124.879 34.794 ;
     RECT  124.843 40.338 124.879 44.136 ;
     RECT  124.843 44.964 124.879 46.908 ;
     RECT  124.843 52.83 124.879 59.022 ;
     RECT  124.843 59.778 124.879 59.796 ;
     RECT  124.843 60.696 124.879 62.694 ;
     RECT  123.943 87.426 124.879 87.444 ;
     RECT  124.519 88.326 124.879 89.874 ;
     RECT  124.843 93.798 124.879 96.084 ;
     RECT  124.843 110.772 124.879 110.79 ;
     RECT  124.843 113.166 124.879 113.796 ;
     RECT  124.843 114.552 124.879 116.802 ;
     RECT  124.843 118.026 124.879 118.044 ;
     RECT  124.843 118.872 124.879 120.816 ;
     RECT  124.879 110.772 124.915 111.096 ;
     RECT  124.879 27.756 124.951 28.854 ;
     RECT  124.519 29.61 124.951 29.628 ;
     RECT  124.159 85.662 124.951 85.68 ;
     RECT  120.091 2.151 124.956 22.032 ;
     RECT  124.007 23.022 124.956 23.076 ;
     RECT  124.843 24.336 124.956 24.426 ;
     RECT  124.951 25.416 124.956 25.434 ;
     RECT  124.843 26.838 124.956 26.856 ;
     RECT  124.951 27.756 124.956 29.628 ;
     RECT  124.879 30.726 124.956 34.794 ;
     RECT  124.843 35.856 124.956 39.276 ;
     RECT  124.879 40.338 124.956 46.908 ;
     RECT  124.843 47.736 124.956 49.419 ;
     RECT  124.843 50.364 124.956 50.994 ;
     RECT  124.843 51.912 124.956 51.93 ;
     RECT  124.879 52.83 124.956 62.694 ;
     RECT  124.267 63.522 124.956 63.54 ;
     RECT  124.303 64.296 124.956 64.62 ;
     RECT  124.843 66.636 124.956 84.6 ;
     RECT  124.951 85.536 124.956 85.68 ;
     RECT  124.879 87.426 124.956 89.874 ;
     RECT  124.843 90.936 124.956 90.954 ;
     RECT  124.879 93.096 124.956 96.084 ;
     RECT  124.843 96.876 124.956 96.894 ;
     RECT  124.699 97.956 124.956 100.764 ;
     RECT  124.843 101.898 124.956 104.184 ;
     RECT  124.843 105.372 124.956 106.47 ;
     RECT  124.843 107.604 124.956 110.016 ;
     RECT  124.915 110.772 124.956 111.132 ;
     RECT  124.843 111.996 124.956 112.014 ;
     RECT  124.879 113.166 124.956 120.816 ;
     RECT  124.843 121.95 124.956 124.632 ;
     RECT  124.843 125.388 124.956 125.406 ;
     RECT  124.519 126.396 124.956 127.098 ;
     RECT  107.807 129.591 124.956 149.049 ;
     RECT  123.755 0.036 128.975 0.054 ;
     RECT  124.956 2.151 149.04 149.049 ;
    LAYER M3 ;
     RECT  28.368 0.031 28.386 0.043 ;
     RECT  25.956 0.031 25.974 0.091 ;
     RECT  27.864 0.043 28.386 0.091 ;
     RECT  109.044 0.031 109.062 0.091 ;
     RECT  109.8 0.067 109.818 0.091 ;
     RECT  123.732 0.067 123.75 0.091 ;
     RECT  128.952 0.031 128.97 0.091 ;
     RECT  122.544 0.091 122.562 0.103 ;
     RECT  27.792 0.091 28.386 0.125 ;
     RECT  109.044 0.091 109.818 0.125 ;
     RECT  14.832 0.091 15.534 0.139 ;
     RECT  16.56 0.091 16.578 0.139 ;
     RECT  19.044 0.091 19.062 0.139 ;
     RECT  25.848 0.091 25.974 0.139 ;
     RECT  26.784 0.103 26.802 0.139 ;
     RECT  120.348 0.091 120.474 0.139 ;
     RECT  122.544 0.103 122.814 0.139 ;
     RECT  123.732 0.091 124.362 0.139 ;
     RECT  27.792 0.125 27.882 0.173 ;
     RECT  109.116 0.125 109.71 0.173 ;
     RECT  11.376 0.091 11.394 0.187 ;
     RECT  12.204 0.139 12.222 0.187 ;
     RECT  14.832 0.139 16.578 0.187 ;
     RECT  17.604 0.091 17.622 0.187 ;
     RECT  18.972 0.139 19.062 0.187 ;
     RECT  25.848 0.139 26.802 0.187 ;
     RECT  27.792 0.173 27.81 0.187 ;
     RECT  112.032 0.091 112.41 0.187 ;
     RECT  24.912 0.091 25.11 0.211 ;
     RECT  25.848 0.187 27.81 0.211 ;
     RECT  122.544 0.139 124.362 0.221 ;
     RECT  18.972 0.187 19.17 0.235 ;
     RECT  24.912 0.211 27.81 0.239 ;
     RECT  6.228 0.091 6.858 0.269 ;
     RECT  20.592 0.139 20.61 0.269 ;
     RECT  23.832 0.139 23.85 0.269 ;
     RECT  24.912 0.239 26.802 0.269 ;
     RECT  110.592 0.091 110.61 0.269 ;
     RECT  9.684 0.091 9.702 0.283 ;
     RECT  9.684 0.283 9.738 0.331 ;
     RECT  10.764 0.187 12.654 0.331 ;
     RECT  18.972 0.235 19.242 0.331 ;
     RECT  22.32 0.091 22.446 0.365 ;
     RECT  112.032 0.187 112.986 0.413 ;
     RECT  24.912 0.269 26.478 0.427 ;
     RECT  24.768 0.427 26.478 0.475 ;
     RECT  24.66 0.475 26.478 0.509 ;
     RECT  27.792 0.239 27.81 0.509 ;
     RECT  30.96 0.379 30.978 0.509 ;
     RECT  24.66 0.509 26.262 0.554 ;
     RECT  6.228 0.269 6.246 0.811 ;
     RECT  118.008 0.091 118.026 1.099 ;
     RECT  29.772 0.139 29.79 1.387 ;
     RECT  7.236 1.675 7.254 1.723 ;
     RECT  8.136 0.523 8.154 1.723 ;
     RECT  13.608 0.091 13.626 1.723 ;
     RECT  22.32 0.365 22.338 1.723 ;
     RECT  112.032 0.413 112.554 1.723 ;
     RECT  114.012 0.091 114.03 1.723 ;
     RECT  115.2 0.091 115.218 1.723 ;
     RECT  117.324 1.099 118.026 1.723 ;
     RECT  119.268 0.091 119.286 1.723 ;
     RECT  121.536 0.523 121.554 1.723 ;
     RECT  122.796 0.221 124.362 1.723 ;
     RECT  128.952 0.091 131.202 1.723 ;
     RECT  132.84 0.091 132.858 1.723 ;
     RECT  134.424 0.091 134.442 1.723 ;
     RECT  13.608 1.723 13.77 1.771 ;
     RECT  13.608 1.771 13.842 1.867 ;
     RECT  24.66 0.554 26.19 1.867 ;
     RECT  13.608 1.867 13.878 1.915 ;
     RECT  13.572 1.915 13.878 1.963 ;
     RECT  24.372 1.867 26.19 1.963 ;
     RECT  128.7 1.723 131.31 1.963 ;
     RECT  132.156 1.723 132.858 1.963 ;
     RECT  9.684 0.331 12.654 2.011 ;
     RECT  13.392 1.963 13.878 2.011 ;
     RECT  24.336 1.963 26.19 2.011 ;
     RECT  109.62 0.173 109.638 2.011 ;
     RECT  111.204 0.379 111.222 2.011 ;
     RECT  112.032 1.723 115.218 2.011 ;
     RECT  116.568 1.723 119.286 2.011 ;
     RECT  121.536 1.723 121.626 2.011 ;
     RECT  20.736 1.723 22.338 2.059 ;
     RECT  24.156 2.011 26.19 2.059 ;
     RECT  112.032 2.011 119.286 2.107 ;
     RECT  120.348 0.139 120.618 2.107 ;
     RECT  121.428 2.011 121.626 2.107 ;
     RECT  122.364 1.723 124.578 2.107 ;
     RECT  24.156 2.059 26.514 2.143 ;
     RECT  112.032 2.107 120.618 2.143 ;
     RECT  121.428 2.107 124.578 2.143 ;
     RECT  107.244 2.059 107.262 2.155 ;
     RECT  9.684 2.011 13.878 2.191 ;
     RECT  24.015 2.143 26.514 2.191 ;
     RECT  34.815 2.143 34.905 2.191 ;
     RECT  105.015 2.143 105.105 2.191 ;
     RECT  14.832 0.187 17.622 2.203 ;
     RECT  18.432 0.331 19.242 2.203 ;
     RECT  39.204 2.191 39.222 2.203 ;
     RECT  108.792 2.155 108.81 2.203 ;
     RECT  128.7 1.963 132.858 2.203 ;
     RECT  133.632 1.723 134.442 2.203 ;
     RECT  23.94 2.191 26.514 2.227 ;
     RECT  29.052 1.387 29.79 2.227 ;
     RECT  104.688 2.191 105.105 2.227 ;
     RECT  112.032 2.143 124.578 2.227 ;
     RECT  125.316 1.723 127.062 2.227 ;
     RECT  128.7 2.203 134.442 2.227 ;
     RECT  39.024 2.203 39.222 2.237 ;
     RECT  102.6 2.059 102.618 2.237 ;
     RECT  6.192 0.811 6.246 2.251 ;
     RECT  7.236 1.723 8.694 2.251 ;
     RECT  23.832 2.227 26.514 2.251 ;
     RECT  29.052 2.227 30.222 2.251 ;
     RECT  109.62 2.011 111.222 2.251 ;
     RECT  112.032 2.227 127.062 2.251 ;
     RECT  135.324 2.227 135.342 2.251 ;
     RECT  39.024 2.237 39.042 2.255 ;
     RECT  28.764 2.251 30.222 2.263 ;
     RECT  109.62 2.251 127.062 2.263 ;
     RECT  6.192 2.251 8.694 2.299 ;
     RECT  9.684 2.191 14.058 2.299 ;
     RECT  14.832 2.203 19.242 2.299 ;
     RECT  20.736 2.059 22.842 2.299 ;
     RECT  23.58 2.251 26.514 2.299 ;
     RECT  108.144 2.203 108.81 2.299 ;
     RECT  109.584 2.263 127.062 2.299 ;
     RECT  128.052 2.227 134.442 2.299 ;
     RECT  135.324 2.251 135.63 2.299 ;
     RECT  31.824 0.091 31.842 2.327 ;
     RECT  33.048 2.227 33.066 2.327 ;
     RECT  6.192 2.299 26.658 2.333 ;
     RECT  104.58 2.227 105.105 2.333 ;
     RECT  108.144 2.299 135.63 2.333 ;
     RECT  106.74 2.155 107.262 2.371 ;
     RECT  2.415 2.143 2.505 2.413 ;
     RECT  34.815 2.191 35.01 2.413 ;
     RECT  40.215 2.143 40.305 2.413 ;
     RECT  45.615 2.143 45.705 2.413 ;
     RECT  51.015 2.143 51.105 2.413 ;
     RECT  56.415 2.143 56.505 2.413 ;
     RECT  61.815 2.143 61.905 2.413 ;
     RECT  67.215 2.143 67.305 2.413 ;
     RECT  72.615 2.143 72.705 2.413 ;
     RECT  78.015 2.143 78.105 2.413 ;
     RECT  83.415 2.143 83.505 2.413 ;
     RECT  88.815 2.143 88.905 2.413 ;
     RECT  94.215 2.143 94.305 2.413 ;
     RECT  99.615 2.143 99.705 2.413 ;
     RECT  105.015 2.333 105.105 2.413 ;
     RECT  137.415 2.143 137.505 2.413 ;
     RECT  142.815 2.143 142.905 2.413 ;
     RECT  148.215 2.143 148.305 2.413 ;
     RECT  108.144 2.333 108.882 2.525 ;
     RECT  20.016 2.333 26.658 2.569 ;
     RECT  106.452 2.371 107.262 2.605 ;
     RECT  20.016 2.569 26.73 2.641 ;
     RECT  106.452 2.605 107.298 2.641 ;
     RECT  109.62 2.333 135.63 2.641 ;
     RECT  109.62 2.641 135.702 2.717 ;
     RECT  88.815 2.413 89.097 2.731 ;
     RECT  102.672 2.251 102.69 2.731 ;
     RECT  108.288 2.525 108.882 2.759 ;
     RECT  109.62 2.717 135.63 2.759 ;
     RECT  108.288 2.759 108.738 2.795 ;
     RECT  106.452 2.641 107.406 2.813 ;
     RECT  99.615 2.413 99.897 2.827 ;
     RECT  108.288 2.795 108.486 2.831 ;
     RECT  102.672 2.731 102.834 2.861 ;
     RECT  107.136 2.813 107.406 2.861 ;
     RECT  28.764 2.263 30.546 2.911 ;
     RECT  109.62 2.759 135.522 2.939 ;
     RECT  88.815 2.731 89.478 3.001 ;
     RECT  101.7 2.875 101.718 3.001 ;
     RECT  99.615 2.827 100.602 3.065 ;
     RECT  101.7 3.001 101.862 3.065 ;
     RECT  107.136 2.861 107.154 3.065 ;
     RECT  43.92 3.067 43.938 3.101 ;
     RECT  105.015 2.413 105.297 3.109 ;
     RECT  106.092 2.827 106.218 3.137 ;
     RECT  28.764 2.911 30.582 3.181 ;
     RECT  104.688 3.109 105.297 3.181 ;
     RECT  90.648 3.067 90.666 3.197 ;
     RECT  88.308 3.001 89.478 3.209 ;
     RECT  20.016 2.641 26.766 3.271 ;
     RECT  96.912 3.181 96.93 3.271 ;
     RECT  102.6 3.181 102.618 3.271 ;
     RECT  102.06 3.271 102.618 3.299 ;
     RECT  94.215 2.413 94.497 3.307 ;
     RECT  95.256 3.067 95.274 3.307 ;
     RECT  96.48 3.271 96.93 3.335 ;
     RECT  104.688 3.181 105.606 3.335 ;
     RECT  108.36 2.831 108.486 3.335 ;
     RECT  94.215 3.307 95.274 3.341 ;
     RECT  100.692 3.271 100.818 3.341 ;
     RECT  104.688 3.335 105.297 3.343 ;
     RECT  20.016 3.271 26.802 3.437 ;
     RECT  28.764 3.181 31.086 3.437 ;
     RECT  100.692 3.341 100.71 3.437 ;
     RECT  108.468 3.335 108.486 3.547 ;
     RECT  31.068 3.437 31.086 3.605 ;
     RECT  44.136 3.181 44.154 3.629 ;
     RECT  48.636 3.577 48.654 3.629 ;
     RECT  108.468 3.547 108.882 3.677 ;
     RECT  31.284 3.685 31.374 3.721 ;
     RECT  49.428 3.685 49.446 3.721 ;
     RECT  51.015 2.413 51.297 3.721 ;
     RECT  99.615 3.065 99.897 3.721 ;
     RECT  108.468 3.677 108.486 3.749 ;
     RECT  31.284 3.721 31.59 3.839 ;
     RECT  96.48 3.335 96.57 3.847 ;
     RECT  87.48 3.811 87.498 3.869 ;
     RECT  48.816 3.721 49.626 3.875 ;
     RECT  103.5 3.403 103.518 3.875 ;
     RECT  40.215 2.413 40.497 3.883 ;
     RECT  99.324 3.721 99.897 3.883 ;
     RECT  88.308 3.209 89.097 3.911 ;
     RECT  39.924 3.883 40.497 3.919 ;
     RECT  96.264 3.847 96.57 3.931 ;
     RECT  98.604 3.883 99.897 3.931 ;
     RECT  104.616 3.343 105.297 3.931 ;
     RECT  39.816 3.919 40.497 3.965 ;
     RECT  95.616 3.931 96.57 3.983 ;
     RECT  34.815 2.413 35.097 4.075 ;
     RECT  6.192 2.333 19.278 4.081 ;
     RECT  20.016 3.437 26.694 4.081 ;
     RECT  98.316 3.931 99.897 4.081 ;
     RECT  49.212 3.875 49.626 4.109 ;
     RECT  96.264 3.983 96.57 4.109 ;
     RECT  49.212 4.109 49.23 4.145 ;
     RECT  50.508 3.721 51.297 4.145 ;
     RECT  106.812 4.081 106.83 4.157 ;
     RECT  102.06 3.299 102.15 4.189 ;
     RECT  109.62 2.939 135.45 4.189 ;
     RECT  98.316 4.081 100.35 4.225 ;
     RECT  101.7 4.189 102.15 4.225 ;
     RECT  28.764 3.437 30.186 4.261 ;
     RECT  32.58 3.721 32.598 4.261 ;
     RECT  106.596 4.189 106.686 4.301 ;
     RECT  83.415 2.413 83.697 4.351 ;
     RECT  98.316 4.225 100.71 4.351 ;
     RECT  101.628 4.225 102.15 4.379 ;
     RECT  106.596 4.301 106.614 4.379 ;
     RECT  109.62 4.189 135.486 4.379 ;
     RECT  34.524 4.075 35.097 4.415 ;
     RECT  50.58 4.145 51.297 4.415 ;
     RECT  109.62 4.379 135.378 4.415 ;
     RECT  50.832 4.415 51.297 4.451 ;
     RECT  101.7 4.379 102.15 4.451 ;
     RECT  86.652 4.363 86.67 4.493 ;
     RECT  97.884 4.351 100.71 4.495 ;
     RECT  28.764 4.261 30.366 4.507 ;
     RECT  31.284 3.839 31.374 4.507 ;
     RECT  101.7 4.451 101.718 4.523 ;
     RECT  32.292 4.261 32.814 4.531 ;
     RECT  83.052 4.351 83.697 4.531 ;
     RECT  28.764 4.507 31.374 4.541 ;
     RECT  83.052 4.531 84.006 4.541 ;
     RECT  97.776 4.495 100.71 4.541 ;
     RECT  90.54 4.363 90.558 4.621 ;
     RECT  94.215 3.341 94.497 4.621 ;
     RECT  96.408 4.109 96.57 4.621 ;
     RECT  97.776 4.541 100.638 4.621 ;
     RECT  104.4 3.931 105.297 4.651 ;
     RECT  108.144 4.351 108.162 4.651 ;
     RECT  32.292 4.531 32.922 4.685 ;
     RECT  83.196 4.541 84.006 4.685 ;
     RECT  90.54 4.621 90.738 4.685 ;
     RECT  96.408 4.621 100.638 4.685 ;
     RECT  107.964 4.651 108.306 4.685 ;
     RECT  6.192 4.081 26.694 4.765 ;
     RECT  94.215 4.621 94.662 4.765 ;
     RECT  6.192 4.765 26.946 4.793 ;
     RECT  28.764 4.541 31.086 4.793 ;
     RECT  93.564 4.765 94.662 4.801 ;
     RECT  96.552 4.685 100.638 4.829 ;
     RECT  45.615 2.413 45.897 4.891 ;
     RECT  20.484 4.793 26.946 4.919 ;
     RECT  30.744 4.793 31.086 4.919 ;
     RECT  48.564 4.801 48.582 4.919 ;
     RECT  109.62 4.415 135.27 4.919 ;
     RECT  34.704 4.415 35.097 4.925 ;
     RECT  49.356 4.891 49.374 4.925 ;
     RECT  6.192 4.793 19.566 4.955 ;
     RECT  93.564 4.801 94.698 4.955 ;
     RECT  96.66 4.829 100.638 4.955 ;
     RECT  104.256 4.651 105.297 4.955 ;
     RECT  109.62 4.919 135.162 4.955 ;
     RECT  30.744 4.919 30.942 4.973 ;
     RECT  96.66 4.955 98.082 4.991 ;
     RECT  30.744 4.973 30.762 5.021 ;
     RECT  103.14 3.991 103.158 5.063 ;
     RECT  48.42 5.035 48.438 5.069 ;
     RECT  27.684 4.987 27.702 5.071 ;
     RECT  27.684 5.071 27.954 5.099 ;
     RECT  93.816 4.955 94.698 5.099 ;
     RECT  97.38 4.991 98.082 5.099 ;
     RECT  7.02 4.955 19.566 5.117 ;
     RECT  27.936 5.099 27.954 5.117 ;
     RECT  41.724 4.801 41.742 5.117 ;
     RECT  65.628 4.963 65.646 5.161 ;
     RECT  31.86 5.071 31.878 5.189 ;
     RECT  65.412 5.161 65.646 5.189 ;
     RECT  99.432 4.955 100.638 5.189 ;
     RECT  39.132 5.161 39.222 5.197 ;
     RECT  99.432 5.189 100.494 5.225 ;
     RECT  65.412 5.189 65.43 5.261 ;
     RECT  39.024 5.197 39.222 5.269 ;
     RECT  98.064 5.099 98.082 5.297 ;
     RECT  56.415 2.413 56.697 5.323 ;
     RECT  67.215 2.413 67.497 5.323 ;
     RECT  78.015 2.413 78.297 5.323 ;
     RECT  88.815 3.911 89.097 5.323 ;
     RECT  38.772 5.269 39.222 5.333 ;
     RECT  34.776 4.925 35.097 5.369 ;
     RECT  38.772 5.333 38.79 5.369 ;
     RECT  45.504 4.891 45.897 5.369 ;
     RECT  56.304 5.323 56.697 5.369 ;
     RECT  67.104 5.323 67.497 5.369 ;
     RECT  77.904 5.323 78.297 5.369 ;
     RECT  88.704 5.323 89.097 5.369 ;
     RECT  32.904 4.685 32.922 5.467 ;
     RECT  83.415 4.685 84.006 5.531 ;
     RECT  7.056 5.117 19.566 5.575 ;
     RECT  99.432 5.225 100.422 5.597 ;
     RECT  7.056 5.575 19.602 5.611 ;
     RECT  32.904 5.467 33.246 5.611 ;
     RECT  32.904 5.611 33.462 5.693 ;
     RECT  104.796 4.955 105.297 5.693 ;
     RECT  81.072 5.431 81.09 5.701 ;
     RECT  82.116 5.611 82.134 5.701 ;
     RECT  108.288 4.685 108.306 5.729 ;
     RECT  81.072 5.701 82.134 5.789 ;
     RECT  82.116 5.789 82.134 5.873 ;
     RECT  90.9 5.707 90.918 5.881 ;
     RECT  81.072 5.789 81.09 5.971 ;
     RECT  80.82 5.971 81.09 5.999 ;
     RECT  80.82 5.999 80.838 6.029 ;
     RECT  90.9 5.881 91.098 6.115 ;
     RECT  28.764 4.793 29.697 6.151 ;
     RECT  90.9 6.115 91.17 6.151 ;
     RECT  109.62 4.955 135.126 6.173 ;
     RECT  99.576 5.597 100.422 6.179 ;
     RECT  7.056 5.611 19.746 6.241 ;
     RECT  7.056 6.241 19.818 6.269 ;
     RECT  90.9 6.151 91.242 6.283 ;
     RECT  20.556 4.919 26.946 6.377 ;
     RECT  90.792 6.283 91.242 6.421 ;
     RECT  99.576 6.179 99.897 6.421 ;
     RECT  90.792 6.421 91.782 6.539 ;
     RECT  109.62 6.173 134.946 6.539 ;
     RECT  9.756 6.269 19.818 6.547 ;
     RECT  20.556 6.377 26.154 6.547 ;
     RECT  90.792 6.539 91.314 6.575 ;
     RECT  45.615 5.369 45.897 6.619 ;
     RECT  86.652 6.547 86.67 6.647 ;
     RECT  101.916 5.341 101.934 6.667 ;
     RECT  92.736 6.667 92.754 6.781 ;
     RECT  91.224 6.575 91.314 6.809 ;
     RECT  101.916 6.667 102.618 6.809 ;
     RECT  109.62 6.539 134.91 6.809 ;
     RECT  83.415 5.531 83.697 6.811 ;
     RECT  9.756 6.547 26.154 6.845 ;
     RECT  91.224 6.809 91.242 6.845 ;
     RECT  92.736 6.781 92.934 6.845 ;
     RECT  101.916 6.809 102.474 6.845 ;
     RECT  109.62 6.809 134.838 6.845 ;
     RECT  7.056 6.269 8.91 6.953 ;
     RECT  32.904 5.693 32.922 6.953 ;
     RECT  88.815 5.369 89.097 6.961 ;
     RECT  41.4 6.547 41.418 7.051 ;
     RECT  46.764 5.233 46.782 7.051 ;
     RECT  72.615 2.413 72.897 7.051 ;
     RECT  78.015 5.369 78.297 7.051 ;
     RECT  64.944 6.961 64.962 7.079 ;
     RECT  88.815 6.961 89.298 7.079 ;
     RECT  10.332 6.845 26.154 7.085 ;
     RECT  72.615 7.051 73.422 7.085 ;
     RECT  76.716 6.925 76.734 7.115 ;
     RECT  83.196 6.811 83.697 7.115 ;
     RECT  26.928 6.377 26.946 7.123 ;
     RECT  41.22 7.051 41.49 7.151 ;
     RECT  44.784 7.051 44.802 7.181 ;
     RECT  46.728 7.051 46.782 7.181 ;
     RECT  41.22 7.151 41.238 7.229 ;
     RECT  11.34 7.085 26.154 7.231 ;
     RECT  26.928 7.123 27.486 7.231 ;
     RECT  63.54 7.231 63.558 7.321 ;
     RECT  63.396 7.321 63.558 7.349 ;
     RECT  7.056 6.953 8.154 7.373 ;
     RECT  63.396 7.349 63.414 7.373 ;
     RECT  72.615 7.085 73.278 7.373 ;
     RECT  109.62 6.845 134.802 7.373 ;
     RECT  64.368 7.357 64.386 7.421 ;
     RECT  74.196 7.231 74.214 7.421 ;
     RECT  34.815 5.369 35.097 7.435 ;
     RECT  45.576 6.619 45.897 7.483 ;
     RECT  56.415 5.369 56.697 7.483 ;
     RECT  67.215 5.369 67.497 7.483 ;
     RECT  88.815 7.079 89.097 7.483 ;
     RECT  45.504 7.483 45.897 7.529 ;
     RECT  67.104 7.483 67.497 7.529 ;
     RECT  77.904 7.051 78.297 7.529 ;
     RECT  88.704 7.483 89.097 7.529 ;
     RECT  48.42 7.435 48.438 7.591 ;
     RECT  34.815 7.435 35.73 7.655 ;
     RECT  48.42 7.591 48.906 7.699 ;
     RECT  11.34 7.231 27.558 7.727 ;
     RECT  46.764 7.181 46.782 7.727 ;
     RECT  48.096 7.699 48.906 7.771 ;
     RECT  47.952 7.771 48.906 7.889 ;
     RECT  48.564 7.889 48.906 7.897 ;
     RECT  8.928 7.435 9.27 7.925 ;
     RECT  9 7.925 9.27 7.933 ;
     RECT  48.564 7.897 49.122 7.933 ;
     RECT  56.304 7.483 56.697 7.933 ;
     RECT  9 7.933 9.486 7.997 ;
     RECT  55.584 7.933 56.697 7.997 ;
     RECT  48.564 7.933 49.338 8.159 ;
     RECT  51.015 4.451 51.297 8.299 ;
     RECT  53.28 8.311 53.298 8.429 ;
     RECT  109.62 7.373 134.658 8.429 ;
     RECT  30.672 8.299 30.69 8.477 ;
     RECT  48.564 8.159 49.122 8.477 ;
     RECT  50.724 8.299 51.297 8.477 ;
     RECT  54.072 8.401 54.09 8.477 ;
     RECT  48.888 8.477 49.122 8.525 ;
     RECT  53.1 8.491 53.118 8.537 ;
     RECT  109.62 8.429 134.442 8.573 ;
     RECT  50.112 8.491 50.13 8.609 ;
     RECT  49.032 8.525 49.122 8.699 ;
     RECT  55.692 7.997 56.697 8.699 ;
     RECT  111.78 8.573 134.442 8.699 ;
     RECT  135.216 8.539 135.234 8.699 ;
     RECT  49.032 8.699 49.05 8.735 ;
     RECT  111.78 8.699 134.298 8.735 ;
     RECT  54.504 8.731 54.522 8.771 ;
     RECT  11.34 7.727 26.082 8.941 ;
     RECT  26.928 7.727 27.558 8.941 ;
     RECT  55.476 8.851 55.566 9.041 ;
     RECT  55.476 9.041 55.494 9.053 ;
     RECT  11.34 8.941 27.558 9.113 ;
     RECT  7.056 7.373 8.097 9.115 ;
     RECT  9 7.997 9.018 9.115 ;
     RECT  14.76 9.113 27.558 9.275 ;
     RECT  111.78 8.735 133.758 9.509 ;
     RECT  111.78 9.509 111.798 9.653 ;
     RECT  113.868 9.509 133.758 9.653 ;
     RECT  7.056 9.115 9.342 9.661 ;
     RECT  114.012 9.653 133.758 9.779 ;
     RECT  14.832 9.275 27.558 9.815 ;
     RECT  114.012 9.779 114.318 9.917 ;
     RECT  114.3 9.917 114.318 9.923 ;
     RECT  52.812 8.941 52.83 9.979 ;
     RECT  52.488 9.979 52.83 10.021 ;
     RECT  52.488 10.021 53.442 10.049 ;
     RECT  106.596 9.661 106.614 10.061 ;
     RECT  53.424 10.049 53.442 10.109 ;
     RECT  112.86 9.509 112.878 10.157 ;
     RECT  7.056 9.661 9.522 10.201 ;
     RECT  10.332 7.085 10.35 10.201 ;
     RECT  115.056 9.779 133.758 10.229 ;
     RECT  7.056 10.201 10.35 10.253 ;
     RECT  9.144 10.253 10.35 10.267 ;
     RECT  11.34 9.113 13.914 10.267 ;
     RECT  115.056 10.229 132.39 10.319 ;
     RECT  9.144 10.267 13.914 10.355 ;
     RECT  9.36 10.355 13.914 10.741 ;
     RECT  15.012 9.815 27.558 10.741 ;
     RECT  133.128 10.229 133.758 10.769 ;
     RECT  131.796 10.319 132.39 10.829 ;
     RECT  115.056 10.319 131.022 10.877 ;
     RECT  9.36 10.741 27.558 10.895 ;
     RECT  115.056 10.877 129.474 10.973 ;
     RECT  112.932 10.939 112.95 10.987 ;
     RECT  131.904 10.829 132.39 11.011 ;
     RECT  133.128 10.769 133.47 11.011 ;
     RECT  112.86 10.987 112.95 11.165 ;
     RECT  131.904 11.011 133.47 11.165 ;
     RECT  112.932 11.165 112.95 11.213 ;
     RECT  7.056 10.253 8.097 11.281 ;
     RECT  7.056 11.281 8.226 11.357 ;
     RECT  10.332 10.895 27.558 11.405 ;
     RECT  40.215 3.965 40.497 11.419 ;
     RECT  130.392 10.877 131.022 11.821 ;
     RECT  131.904 11.165 132.297 11.821 ;
     RECT  38.448 7.771 38.466 11.939 ;
     RECT  115.056 10.973 129.294 11.939 ;
     RECT  128.736 11.939 129.294 11.947 ;
     RECT  11.34 11.405 27.558 11.975 ;
     RECT  40.215 11.419 40.554 11.975 ;
     RECT  9.36 10.895 9.594 11.995 ;
     RECT  115.056 11.939 127.962 12.209 ;
     RECT  10.332 11.405 10.35 12.361 ;
     RECT  9.216 11.995 9.594 12.451 ;
     RECT  10.332 12.361 10.53 12.451 ;
     RECT  11.34 11.975 16.974 12.487 ;
     RECT  9.216 12.451 10.53 12.523 ;
     RECT  133.128 11.165 133.47 12.523 ;
     RECT  128.736 11.947 129.582 12.557 ;
     RECT  42.372 11.911 42.39 12.623 ;
     RECT  42.552 12.631 42.57 12.749 ;
     RECT  104.976 5.693 105.297 12.749 ;
     RECT  9.108 12.523 10.53 12.785 ;
     RECT  10.332 12.785 10.53 12.901 ;
     RECT  11.304 12.487 16.974 12.901 ;
     RECT  105.015 12.749 105.297 12.901 ;
     RECT  128.844 12.557 129.582 12.929 ;
     RECT  133.128 12.523 133.902 12.991 ;
     RECT  130.392 11.821 132.297 13.051 ;
     RECT  133.128 12.991 134.046 13.051 ;
     RECT  115.056 12.209 127.926 13.063 ;
     RECT  130.392 13.051 134.046 13.091 ;
     RECT  10.332 12.901 16.974 13.099 ;
     RECT  17.856 11.975 27.558 13.099 ;
     RECT  114.876 13.063 127.926 13.243 ;
     RECT  81.972 13.171 81.99 13.289 ;
     RECT  43.272 12.901 43.29 13.325 ;
     RECT  114.876 13.243 127.998 13.441 ;
     RECT  128.844 12.929 129.078 13.441 ;
     RECT  9.36 12.785 9.594 13.531 ;
     RECT  10.332 13.099 27.558 13.595 ;
     RECT  9.216 13.531 9.594 13.675 ;
     RECT  10.332 13.595 16.974 13.675 ;
     RECT  114.876 13.441 129.078 13.739 ;
     RECT  8.892 13.675 16.974 13.865 ;
     RECT  117.108 13.739 129.078 13.865 ;
     RECT  9 13.865 16.974 14.045 ;
     RECT  14.724 14.045 16.974 14.135 ;
     RECT  117.216 13.865 129.078 14.171 ;
     RECT  130.392 13.091 132.39 14.215 ;
     RECT  133.128 13.091 134.046 14.215 ;
     RECT  128.88 14.171 129.078 14.251 ;
     RECT  130.392 14.215 134.046 14.251 ;
     RECT  128.88 14.251 134.046 14.405 ;
     RECT  14.904 14.135 16.974 14.521 ;
     RECT  17.856 13.595 27.558 14.521 ;
     RECT  109.62 8.573 111.042 14.525 ;
     RECT  7.056 11.357 8.097 14.791 ;
     RECT  129.888 14.405 134.046 14.813 ;
     RECT  7.056 14.791 8.226 14.827 ;
     RECT  9 14.045 13.914 14.827 ;
     RECT  14.904 14.521 27.558 15.215 ;
     RECT  15.012 15.215 27.558 15.389 ;
     RECT  117.216 14.171 127.998 15.389 ;
     RECT  7.056 14.827 13.914 15.449 ;
     RECT  9.648 15.449 13.914 15.755 ;
     RECT  125.1 15.389 127.998 15.755 ;
     RECT  130.104 14.813 134.046 15.755 ;
     RECT  128.88 14.405 129.078 15.871 ;
     RECT  130.32 15.755 134.046 15.965 ;
     RECT  114.876 13.739 116.19 15.979 ;
     RECT  117.216 15.389 124.362 15.979 ;
     RECT  128.808 15.871 129.078 16.061 ;
     RECT  114.876 15.979 124.362 16.133 ;
     RECT  130.392 15.965 134.046 16.141 ;
     RECT  115.704 16.133 124.362 16.259 ;
     RECT  125.1 15.755 127.926 16.367 ;
     RECT  7.056 15.449 8.694 16.411 ;
     RECT  115.704 16.259 116.37 16.493 ;
     RECT  7.056 16.411 8.802 16.541 ;
     RECT  9.72 15.755 13.914 16.843 ;
     RECT  15.012 15.389 16.974 16.843 ;
     RECT  14.832 16.843 16.974 16.979 ;
     RECT  17.856 15.389 27.558 17.077 ;
     RECT  117.216 16.259 124.362 17.077 ;
     RECT  125.1 16.367 127.71 17.077 ;
     RECT  17.856 17.077 27.63 17.117 ;
     RECT  115.704 16.493 116.154 17.375 ;
     RECT  117.216 17.077 127.71 17.611 ;
     RECT  9.72 16.843 14.058 17.659 ;
     RECT  117.216 17.611 127.926 17.659 ;
     RECT  115.815 17.375 116.154 17.689 ;
     RECT  117.216 17.659 128.034 17.995 ;
     RECT  117.18 17.995 128.034 18.031 ;
     RECT  17.856 17.117 27.558 18.157 ;
     RECT  8.928 17.659 14.058 18.185 ;
     RECT  116.964 18.031 128.034 18.185 ;
     RECT  9.36 18.185 14.058 18.221 ;
     RECT  115.815 17.689 116.226 18.301 ;
     RECT  117.252 18.185 128.034 18.301 ;
     RECT  15.012 16.979 16.974 18.463 ;
     RECT  17.856 18.157 27.63 18.661 ;
     RECT  115.815 18.301 116.37 18.689 ;
     RECT  115.815 18.689 116.298 18.725 ;
     RECT  115.815 18.725 116.154 18.797 ;
     RECT  117.252 18.301 128.142 18.995 ;
     RECT  128.88 16.061 129.078 18.995 ;
     RECT  117.324 18.995 128.142 19.111 ;
     RECT  128.88 18.995 128.97 19.111 ;
     RECT  17.856 18.661 27.954 19.237 ;
     RECT  28.692 6.151 29.697 19.237 ;
     RECT  9.432 18.221 14.058 19.387 ;
     RECT  130.392 16.141 134.082 19.387 ;
     RECT  117.324 19.111 128.97 19.499 ;
     RECT  9.036 19.387 14.058 19.517 ;
     RECT  9.036 19.517 9.054 19.535 ;
     RECT  114.876 16.133 114.894 19.661 ;
     RECT  17.856 19.237 29.697 19.741 ;
     RECT  31.068 19.651 31.086 19.771 ;
     RECT  30.924 19.771 31.086 19.805 ;
     RECT  117.936 19.499 128.97 19.877 ;
     RECT  130.392 19.387 134.118 19.921 ;
     RECT  117.936 19.877 117.99 20.075 ;
     RECT  130.392 19.921 134.334 20.155 ;
     RECT  105.015 12.901 105.39 20.219 ;
     RECT  117.936 20.075 117.954 20.219 ;
     RECT  31.14 19.921 31.914 20.281 ;
     RECT  32.868 20.047 32.886 20.281 ;
     RECT  114.588 20.191 114.606 20.309 ;
     RECT  129.96 20.155 134.334 20.309 ;
     RECT  17.856 19.741 29.97 20.425 ;
     RECT  31.14 20.281 32.886 20.461 ;
     RECT  31.14 20.461 33.462 20.731 ;
     RECT  31.14 20.731 33.534 20.821 ;
     RECT  118.8 19.877 128.97 20.885 ;
     RECT  17.856 20.425 30.186 21.053 ;
     RECT  34.815 7.655 35.097 21.115 ;
     RECT  118.8 20.885 118.818 21.115 ;
     RECT  109.62 14.525 110.697 21.119 ;
     RECT  22.68 21.053 30.186 21.127 ;
     RECT  31.14 20.821 33.822 21.127 ;
     RECT  119.592 20.885 128.97 21.155 ;
     RECT  119.592 21.155 121.59 21.227 ;
     RECT  22.68 21.127 33.822 21.271 ;
     RECT  34.668 21.115 35.097 21.271 ;
     RECT  22.68 21.271 35.097 21.341 ;
     RECT  33.516 21.341 35.097 21.347 ;
     RECT  40.215 11.975 40.497 21.347 ;
     RECT  45.615 7.529 45.897 21.347 ;
     RECT  51.015 8.477 51.297 21.347 ;
     RECT  56.415 8.699 56.697 21.347 ;
     RECT  61.815 2.413 62.097 21.347 ;
     RECT  67.215 7.529 67.497 21.347 ;
     RECT  72.615 7.373 72.897 21.347 ;
     RECT  78.015 7.529 78.297 21.347 ;
     RECT  83.415 7.115 83.697 21.347 ;
     RECT  88.815 7.529 89.097 21.347 ;
     RECT  93.816 5.099 94.497 21.347 ;
     RECT  99.108 6.421 99.897 21.347 ;
     RECT  105.015 20.219 105.297 21.347 ;
     RECT  110.415 21.119 110.697 21.347 ;
     RECT  115.815 18.797 116.097 21.347 ;
     RECT  119.592 21.227 121.497 21.347 ;
     RECT  64.188 21.115 64.206 21.389 ;
     RECT  117.036 21.163 117.054 21.389 ;
     RECT  118.296 21.115 118.818 21.389 ;
     RECT  119.592 21.347 121.374 21.389 ;
     RECT  122.328 21.155 128.97 21.437 ;
     RECT  22.68 21.341 32.526 21.461 ;
     RECT  122.4 21.437 128.97 21.461 ;
     RECT  117.144 21.451 117.162 21.497 ;
     RECT  122.436 21.461 128.97 21.533 ;
     RECT  64.404 21.451 64.422 21.569 ;
     RECT  33.516 21.347 34.905 21.617 ;
     RECT  40.215 21.347 40.305 21.617 ;
     RECT  45.615 21.347 45.705 21.617 ;
     RECT  51.015 21.347 51.105 21.617 ;
     RECT  56.415 21.347 56.505 21.617 ;
     RECT  61.815 21.347 61.905 21.617 ;
     RECT  67.215 21.347 67.305 21.617 ;
     RECT  72.615 21.347 72.705 21.617 ;
     RECT  78.015 21.347 78.105 21.617 ;
     RECT  83.415 21.347 83.505 21.617 ;
     RECT  88.815 21.347 88.905 21.617 ;
     RECT  93.816 21.347 94.305 21.617 ;
     RECT  99.108 21.347 99.705 21.617 ;
     RECT  105.015 21.347 105.105 21.617 ;
     RECT  110.415 21.347 110.505 21.617 ;
     RECT  115.815 21.347 115.905 21.617 ;
     RECT  119.592 21.389 121.305 21.617 ;
     RECT  122.472 21.533 128.97 21.631 ;
     RECT  122.472 21.631 129.006 21.643 ;
     RECT  130.104 20.309 134.334 21.643 ;
     RECT  118.584 21.389 118.818 21.659 ;
     RECT  22.68 21.461 30.618 21.695 ;
     RECT  122.472 21.643 134.334 21.695 ;
     RECT  101.916 6.845 101.934 21.965 ;
     RECT  14.868 18.463 16.974 21.979 ;
     RECT  17.856 21.053 21.906 21.979 ;
     RECT  118.8 21.659 118.818 22.001 ;
     RECT  14.868 21.979 21.906 22.081 ;
     RECT  22.68 21.695 28.962 22.081 ;
     RECT  119.592 21.617 120.762 22.109 ;
     RECT  14.868 22.081 28.962 22.205 ;
     RECT  29.952 21.695 30.618 22.205 ;
     RECT  30.492 22.205 30.618 22.411 ;
     RECT  31.356 21.461 32.526 22.411 ;
     RECT  120.276 22.109 120.762 22.445 ;
     RECT  99.108 21.617 99.126 22.493 ;
     RECT  30.492 22.411 32.526 22.541 ;
     RECT  93.816 21.617 93.834 22.541 ;
     RECT  122.472 21.695 129.006 22.795 ;
     RECT  130.104 21.695 134.334 22.795 ;
     RECT  22.68 22.205 28.962 22.829 ;
     RECT  31.572 22.541 32.526 22.883 ;
     RECT  30.492 22.541 30.762 22.964 ;
     RECT  122.472 22.795 134.55 23.045 ;
     RECT  14.868 22.205 21.906 23.125 ;
     RECT  22.68 22.829 27.846 23.125 ;
     RECT  30.492 22.964 30.51 23.179 ;
     RECT  122.472 23.045 134.442 23.315 ;
     RECT  14.868 23.125 27.846 23.76 ;
     RECT  28.656 22.829 28.962 23.76 ;
     RECT  30.384 23.179 30.51 23.76 ;
     RECT  31.752 22.883 32.526 23.76 ;
     RECT  33.516 21.617 34.254 23.76 ;
     RECT  109.62 21.119 109.638 23.76 ;
     RECT  118.584 23.359 118.602 23.76 ;
     RECT  120.456 22.445 120.762 23.76 ;
     RECT  122.472 23.315 129.222 23.76 ;
     RECT  9.936 19.517 14.058 25.675 ;
     RECT  130.104 23.315 134.442 25.723 ;
     RECT  9.648 25.675 14.058 26.131 ;
     RECT  9.504 26.131 14.058 26.189 ;
     RECT  129.96 25.723 134.442 26.203 ;
     RECT  14.868 23.76 129.222 26.401 ;
     RECT  129.96 26.203 134.73 26.401 ;
     RECT  9.036 29.083 9.054 29.489 ;
     RECT  9.936 26.189 14.058 29.605 ;
     RECT  14.868 26.401 134.838 29.605 ;
     RECT  8.892 29.605 8.91 29.645 ;
     RECT  9.936 29.605 134.838 31.801 ;
     RECT  9.936 31.801 134.91 31.853 ;
     RECT  9.936 31.853 134.838 31.997 ;
     RECT  9.936 31.997 133.146 32.189 ;
     RECT  132.015 32.189 133.146 32.381 ;
     RECT  9.936 32.189 131.022 32.491 ;
     RECT  9.216 32.491 131.022 32.729 ;
     RECT  9.072 32.881 9.09 32.957 ;
     RECT  133.128 32.381 133.146 36.751 ;
     RECT  134.1 31.997 134.838 36.751 ;
     RECT  9.936 32.729 131.022 37.037 ;
     RECT  123.984 37.037 131.022 37.049 ;
     RECT  128.808 37.049 131.022 37.391 ;
     RECT  9.936 37.037 123.21 38.641 ;
     RECT  9.9 38.641 123.21 39.829 ;
     RECT  9.648 39.829 123.21 40.135 ;
     RECT  128.88 37.391 131.022 40.711 ;
     RECT  128.844 40.711 131.022 40.801 ;
     RECT  123.984 37.049 127.926 41.251 ;
     RECT  128.808 40.801 131.022 41.251 ;
     RECT  123.984 41.251 131.022 41.309 ;
     RECT  9.612 40.135 123.21 44.959 ;
     RECT  133.128 36.751 134.838 49.351 ;
     RECT  133.128 49.351 135.414 49.469 ;
     RECT  133.128 49.469 134.442 49.517 ;
     RECT  133.128 49.517 134.118 49.711 ;
     RECT  128.88 41.309 131.022 56.641 ;
     RECT  128.88 56.641 131.058 56.765 ;
     RECT  133.092 49.711 134.118 59.851 ;
     RECT  133.092 59.851 134.406 60.151 ;
     RECT  133.092 60.151 134.73 60.881 ;
     RECT  9.468 44.959 123.21 62.683 ;
     RECT  123.984 41.309 127.926 62.683 ;
     RECT  9.468 62.683 127.926 63.005 ;
     RECT  128.88 56.765 131.022 63.835 ;
     RECT  123.984 63.005 127.926 64.085 ;
     RECT  125.748 64.085 127.926 64.267 ;
     RECT  128.664 63.835 131.022 64.267 ;
     RECT  125.748 64.267 131.022 64.319 ;
     RECT  9.468 63.005 123.21 64.824 ;
     RECT  39.132 65.803 39.15 66.379 ;
     RECT  41.976 65.821 41.994 66.631 ;
     RECT  125.748 64.319 127.926 66.715 ;
     RECT  128.88 64.319 131.022 66.715 ;
     RECT  122.94 64.824 123.21 66.721 ;
     RECT  123.984 64.085 124.866 66.721 ;
     RECT  125.748 66.715 131.022 66.749 ;
     RECT  122.94 66.721 124.866 66.797 ;
     RECT  55.08 66.721 55.098 66.811 ;
     RECT  109.548 66.763 109.566 66.811 ;
     RECT  111.132 66.715 111.15 66.811 ;
     RECT  123.12 66.797 124.866 66.845 ;
     RECT  41.976 66.631 42.174 66.857 ;
     RECT  108.792 66.379 108.81 66.859 ;
     RECT  109.548 66.811 109.89 66.859 ;
     RECT  110.952 66.811 111.15 66.859 ;
     RECT  44.82 66.829 44.838 66.865 ;
     RECT  125.748 66.749 128.142 66.893 ;
     RECT  52.416 66.763 52.434 66.901 ;
     RECT  35.1 66.829 35.118 66.943 ;
     RECT  39.96 66.631 39.978 66.943 ;
     RECT  40.86 65.866 40.878 66.943 ;
     RECT  51.588 66.859 51.606 66.943 ;
     RECT  108.792 66.859 109.89 66.943 ;
     RECT  110.7 66.859 111.15 66.943 ;
     RECT  121.215 66.943 121.305 66.955 ;
     RECT  56.415 66.943 56.505 66.991 ;
     RECT  67.215 66.943 67.305 66.991 ;
     RECT  78.015 66.943 78.105 66.991 ;
     RECT  99.615 66.943 99.705 66.991 ;
     RECT  63 66.991 63.018 67.003 ;
     RECT  94.215 66.943 94.305 67.003 ;
     RECT  34.815 66.943 35.118 67.019 ;
     RECT  38.772 66.379 39.15 67.019 ;
     RECT  39.96 66.943 40.878 67.019 ;
     RECT  41.976 66.857 42.102 67.019 ;
     RECT  44.748 66.865 44.838 67.019 ;
     RECT  51.015 66.943 51.606 67.019 ;
     RECT  52.416 66.901 52.506 67.019 ;
     RECT  55.008 66.811 55.098 67.019 ;
     RECT  9.468 64.824 28.242 67.027 ;
     RECT  38.772 67.019 39.006 67.027 ;
     RECT  56.304 66.991 56.61 67.037 ;
     RECT  62.712 67.003 63.018 67.037 ;
     RECT  67.104 66.991 67.41 67.037 ;
     RECT  77.904 66.991 78.21 67.037 ;
     RECT  99.504 66.991 99.81 67.037 ;
     RECT  108.792 66.943 111.15 67.055 ;
     RECT  109.728 67.055 111.15 67.085 ;
     RECT  48.42 64.824 48.438 67.091 ;
     RECT  38.736 67.027 39.006 67.127 ;
     RECT  30.78 67.003 30.798 67.133 ;
     RECT  48.348 67.099 48.366 67.133 ;
     RECT  58.716 67.003 58.734 67.133 ;
     RECT  62.712 67.037 62.73 67.133 ;
     RECT  86.652 67.003 86.67 67.133 ;
     RECT  91.548 67.099 91.566 67.133 ;
     RECT  94.215 67.003 94.626 67.133 ;
     RECT  106.596 67.003 106.614 67.133 ;
     RECT  46.8 67.135 46.818 67.137 ;
     RECT  39.96 67.019 40.698 67.171 ;
     RECT  41.976 67.019 42.03 67.171 ;
     RECT  39.924 67.171 40.698 67.181 ;
     RECT  38.988 67.127 39.006 67.199 ;
     RECT  90 67.099 90.018 67.199 ;
     RECT  110.052 67.085 111.15 67.199 ;
     RECT  29.415 66.943 29.505 67.213 ;
     RECT  45.615 66.943 45.705 67.213 ;
     RECT  56.415 67.037 56.61 67.213 ;
     RECT  61.815 66.943 61.905 67.213 ;
     RECT  67.215 67.037 67.41 67.213 ;
     RECT  72.615 66.943 72.705 67.213 ;
     RECT  78.015 67.037 78.21 67.213 ;
     RECT  83.415 66.943 83.505 67.213 ;
     RECT  88.815 66.943 88.905 67.213 ;
     RECT  99.615 67.037 99.81 67.213 ;
     RECT  105.015 66.943 105.105 67.213 ;
     RECT  115.815 66.943 115.905 67.213 ;
     RECT  121.104 66.955 121.41 67.213 ;
     RECT  34.815 67.019 35.097 67.261 ;
     RECT  9.468 67.027 28.53 67.289 ;
     RECT  108.792 67.055 108.846 67.333 ;
     RECT  108.612 67.333 108.846 67.373 ;
     RECT  41.652 67.171 42.03 67.387 ;
     RECT  64.548 67.171 64.566 67.397 ;
     RECT  46.797 67.137 46.821 67.416 ;
     RECT  46.8 67.416 46.818 67.421 ;
     RECT  34.164 67.261 35.097 67.433 ;
     RECT  39.924 67.181 40.497 67.433 ;
     RECT  41.58 67.387 42.03 67.433 ;
     RECT  108.828 67.373 108.846 67.433 ;
     RECT  118.656 66.859 118.674 67.435 ;
     RECT  121.104 67.213 121.497 67.441 ;
     RECT  45.615 67.213 45.897 67.531 ;
     RECT  9.468 67.289 28.458 67.559 ;
     RECT  41.652 67.433 42.03 67.559 ;
     RECT  34.704 67.433 35.097 67.565 ;
     RECT  45.504 67.531 45.897 67.565 ;
     RECT  47.988 67.441 48.006 67.565 ;
     RECT  121.104 67.441 122.058 67.567 ;
     RECT  123.192 66.845 124.866 67.567 ;
     RECT  31.392 67.441 31.41 67.595 ;
     RECT  110.196 67.199 110.697 67.613 ;
     RECT  118.584 67.435 118.674 67.661 ;
     RECT  118.656 67.661 118.674 67.709 ;
     RECT  121.104 67.567 124.866 67.711 ;
     RECT  125.748 66.893 127.926 67.711 ;
     RECT  119.916 67.339 119.934 67.771 ;
     RECT  120.96 67.711 124.866 67.801 ;
     RECT  41.652 67.559 41.85 67.829 ;
     RECT  119.772 67.771 119.934 67.829 ;
     RECT  41.652 67.829 41.67 67.865 ;
     RECT  120.708 67.801 124.866 68.377 ;
     RECT  125.748 67.711 128.034 68.377 ;
     RECT  115.815 67.213 116.097 68.491 ;
     RECT  115.38 68.491 116.097 68.639 ;
     RECT  117.756 64.824 117.774 68.791 ;
     RECT  120.708 68.377 128.034 68.971 ;
     RECT  120.24 68.971 128.034 69.017 ;
     RECT  120.24 69.017 121.734 69.019 ;
     RECT  117.036 68.791 117.774 69.151 ;
     RECT  118.62 69.061 118.638 69.151 ;
     RECT  120.132 69.019 121.734 69.223 ;
     RECT  117.036 69.151 118.638 69.295 ;
     RECT  117.036 69.295 119.106 69.449 ;
     RECT  116.892 69.457 116.91 69.533 ;
     RECT  78.015 67.213 78.297 69.691 ;
     RECT  88.815 67.213 89.097 69.691 ;
     RECT  99.615 67.213 99.897 69.691 ;
     RECT  110.415 67.613 110.697 69.691 ;
     RECT  117.756 69.449 119.106 69.719 ;
     RECT  77.904 69.691 78.297 69.725 ;
     RECT  88.704 69.691 89.097 69.725 ;
     RECT  99.504 69.691 99.897 69.725 ;
     RECT  110.304 69.691 110.697 69.725 ;
     RECT  114.876 69.727 114.894 69.773 ;
     RECT  117.756 69.719 118.962 69.773 ;
     RECT  115.815 68.639 116.097 69.835 ;
     RECT  118.944 69.773 118.962 69.869 ;
     RECT  115.815 69.835 116.19 69.871 ;
     RECT  120.024 69.223 121.734 69.871 ;
     RECT  119.88 69.871 121.734 70.025 ;
     RECT  120.024 70.025 121.734 70.069 ;
     RECT  122.508 69.017 128.034 70.069 ;
     RECT  115.272 69.871 116.19 70.301 ;
     RECT  115.815 70.301 116.19 70.411 ;
     RECT  115.815 70.411 116.586 70.951 ;
     RECT  128.88 66.749 131.022 70.979 ;
     RECT  115.815 70.951 116.766 71.069 ;
     RECT  70.74 71.131 70.758 71.149 ;
     RECT  117.756 69.773 117.774 71.221 ;
     RECT  70.596 71.149 70.758 71.249 ;
     RECT  70.596 71.249 70.614 71.261 ;
     RECT  120.024 70.069 128.034 71.375 ;
     RECT  120.312 71.375 128.034 72.059 ;
     RECT  121.032 72.059 128.034 72.455 ;
     RECT  70.38 72.379 70.398 72.689 ;
     RECT  68.4 72.715 68.418 72.72 ;
     RECT  68.397 72.72 68.421 72.759 ;
     RECT  68.4 72.759 68.418 72.761 ;
     RECT  119.484 72.811 119.502 72.841 ;
     RECT  120.276 72.763 120.294 72.841 ;
     RECT  9.468 67.559 28.242 72.931 ;
     RECT  119.484 72.841 120.294 72.931 ;
     RECT  121.032 72.455 121.734 72.931 ;
     RECT  9.468 72.931 28.674 72.955 ;
     RECT  9.144 72.955 28.674 72.959 ;
     RECT  119.484 72.931 121.734 72.959 ;
     RECT  128.952 70.979 131.022 73.075 ;
     RECT  120.852 72.959 121.734 73.229 ;
     RECT  28.656 72.959 28.674 73.265 ;
     RECT  29.415 67.213 29.697 73.381 ;
     RECT  120.924 73.229 121.734 73.381 ;
     RECT  122.472 72.455 128.034 73.381 ;
     RECT  9.144 72.959 27.81 73.499 ;
     RECT  128.952 73.075 131.094 73.769 ;
     RECT  120.924 73.381 128.034 74.683 ;
     RECT  128.952 73.769 131.022 74.731 ;
     RECT  128.952 74.731 131.13 74.929 ;
     RECT  117.756 71.221 118.278 75.091 ;
     RECT  128.952 74.929 131.238 75.119 ;
     RECT  117.756 75.091 119.142 75.149 ;
     RECT  128.952 75.119 131.13 75.155 ;
     RECT  119.124 75.149 119.142 75.389 ;
     RECT  119.808 75.499 119.826 75.533 ;
     RECT  28.692 73.381 29.697 75.667 ;
     RECT  28.692 75.667 30.402 75.725 ;
     RECT  28.692 75.725 30.222 76.199 ;
     RECT  120.888 74.683 128.034 76.267 ;
     RECT  28.692 76.199 30.078 76.343 ;
     RECT  9.468 73.499 27.81 76.351 ;
     RECT  28.692 76.343 29.97 76.351 ;
     RECT  120.456 76.267 128.034 76.379 ;
     RECT  31.032 76.351 31.05 76.621 ;
     RECT  120.744 76.379 128.034 76.781 ;
     RECT  30.96 76.621 31.05 76.855 ;
     RECT  30.96 76.855 31.122 76.891 ;
     RECT  30.816 76.891 31.122 77.275 ;
     RECT  5.364 76.939 5.382 77.279 ;
     RECT  3.816 77.275 3.834 77.28 ;
     RECT  3.813 77.28 3.837 77.313 ;
     RECT  3.816 77.313 3.834 77.315 ;
     RECT  30.816 77.275 31.626 77.315 ;
     RECT  9.468 76.351 29.97 77.431 ;
     RECT  30.816 77.315 31.158 77.431 ;
     RECT  9.468 77.431 31.158 77.855 ;
     RECT  120.852 76.781 128.034 77.947 ;
     RECT  7.056 16.541 8.097 77.971 ;
     RECT  28.368 77.855 31.158 78.061 ;
     RECT  28.368 78.061 31.842 78.089 ;
     RECT  120.6 77.947 128.034 78.091 ;
     RECT  6.192 4.955 6.246 78.205 ;
     RECT  4.536 78.205 4.554 78.241 ;
     RECT  5.976 78.205 6.246 78.241 ;
     RECT  31.788 78.089 31.842 78.367 ;
     RECT  2.415 2.413 2.697 78.475 ;
     RECT  4.536 78.241 6.246 78.475 ;
     RECT  7.02 77.971 8.097 78.475 ;
     RECT  2.376 78.475 2.697 78.511 ;
     RECT  3.744 78.475 3.762 78.511 ;
     RECT  4.536 78.475 8.097 78.511 ;
     RECT  9.468 77.855 27.63 78.601 ;
     RECT  28.368 78.089 30.87 78.601 ;
     RECT  2.376 78.511 8.097 78.629 ;
     RECT  31.788 78.367 32.058 78.629 ;
     RECT  4.572 78.629 8.097 78.653 ;
     RECT  6.192 78.653 8.097 78.665 ;
     RECT  31.788 78.629 31.842 78.701 ;
     RECT  9.468 78.601 30.87 78.871 ;
     RECT  31.788 78.701 31.806 78.871 ;
     RECT  5.04 78.653 5.13 78.899 ;
     RECT  9.468 78.871 31.806 78.899 ;
     RECT  5.04 78.899 5.058 78.935 ;
     RECT  9.468 78.899 31.446 78.989 ;
     RECT  2.415 78.629 3.726 79.169 ;
     RECT  9.468 78.989 31.41 79.169 ;
     RECT  3.636 79.169 3.654 79.205 ;
     RECT  28.404 79.169 31.41 79.241 ;
     RECT  120.528 78.091 128.034 79.349 ;
     RECT  7.056 78.665 8.097 79.435 ;
     RECT  2.415 79.169 2.79 79.555 ;
     RECT  2.34 79.555 2.79 79.591 ;
     RECT  7.056 79.435 8.298 79.591 ;
     RECT  2.304 79.591 2.79 79.717 ;
     RECT  2.268 79.717 2.79 79.757 ;
     RECT  7.056 79.591 8.55 79.901 ;
     RECT  2.304 79.757 2.79 80.015 ;
     RECT  28.404 79.241 30.942 80.059 ;
     RECT  28.404 80.059 30.978 80.131 ;
     RECT  119.808 80.107 119.826 80.221 ;
     RECT  120.744 79.349 128.034 80.221 ;
     RECT  28.404 80.131 31.374 80.257 ;
     RECT  9.468 79.169 27.666 80.401 ;
     RECT  28.404 80.257 31.554 80.401 ;
     RECT  119.808 80.221 128.034 80.401 ;
     RECT  119.736 80.401 128.034 80.429 ;
     RECT  2.376 80.015 2.79 80.491 ;
     RECT  5.04 80.401 5.058 80.519 ;
     RECT  117.756 75.149 118.278 80.527 ;
     RECT  117.756 80.527 118.998 80.573 ;
     RECT  119.736 80.429 119.934 80.671 ;
     RECT  119.124 80.671 119.934 80.699 ;
     RECT  2.376 80.491 2.862 80.779 ;
     RECT  6.192 78.665 6.246 80.797 ;
     RECT  4.104 80.671 4.122 80.875 ;
     RECT  6.192 80.797 6.282 80.875 ;
     RECT  7.056 79.901 8.097 80.875 ;
     RECT  4.104 80.875 4.698 80.905 ;
     RECT  4.032 80.905 4.698 80.933 ;
     RECT  9.468 80.401 31.554 80.941 ;
     RECT  4.032 80.933 4.086 81.059 ;
     RECT  6.192 80.875 8.097 81.059 ;
     RECT  119.124 80.699 119.754 81.059 ;
     RECT  4.032 81.059 4.05 81.067 ;
     RECT  2.376 80.779 3.114 81.095 ;
     RECT  3.852 81.067 4.05 81.101 ;
     RECT  2.376 81.095 2.754 81.175 ;
     RECT  9.468 80.941 31.734 81.211 ;
     RECT  120.744 80.429 128.034 81.211 ;
     RECT  4.032 81.101 4.05 81.365 ;
     RECT  9.468 81.211 31.95 81.401 ;
     RECT  119.736 81.059 119.754 81.445 ;
     RECT  2.34 81.175 2.754 81.499 ;
     RECT  119.736 81.445 119.862 81.595 ;
     RECT  120.672 81.211 128.034 81.595 ;
     RECT  2.304 81.499 2.754 81.599 ;
     RECT  9.468 81.401 31.842 81.635 ;
     RECT  119.736 81.595 128.034 81.635 ;
     RECT  119.736 81.635 119.934 81.877 ;
     RECT  119.52 81.877 119.934 81.917 ;
     RECT  117.756 80.573 118.278 82.411 ;
     RECT  119.916 81.917 119.934 82.411 ;
     RECT  120.672 81.635 128.034 82.411 ;
     RECT  2.304 81.599 2.697 82.445 ;
     RECT  119.916 82.411 128.034 82.445 ;
     RECT  117.612 82.411 118.278 82.561 ;
     RECT  2.34 82.445 2.697 82.589 ;
     RECT  115.815 71.069 116.097 82.699 ;
     RECT  115.452 82.699 116.097 82.831 ;
     RECT  113.544 82.795 113.562 82.949 ;
     RECT  114.588 82.795 114.606 82.973 ;
     RECT  115.452 82.831 116.406 82.985 ;
     RECT  117.612 82.561 118.638 83.101 ;
     RECT  115.452 82.985 116.097 83.213 ;
     RECT  9.468 81.635 31.41 83.219 ;
     RECT  32.184 83.083 32.202 83.219 ;
     RECT  117.612 83.101 118.674 83.371 ;
     RECT  117.612 83.371 118.854 83.489 ;
     RECT  117.756 83.489 118.854 83.501 ;
     RECT  118.26 83.501 118.854 83.641 ;
     RECT  120.204 82.445 128.034 83.641 ;
     RECT  56.415 67.213 56.697 83.659 ;
     RECT  56.196 83.659 56.697 83.664 ;
     RECT  72.615 67.213 72.897 83.731 ;
     RECT  115.815 83.213 116.097 83.731 ;
     RECT  113.616 83.101 113.778 83.759 ;
     RECT  118.26 83.641 128.034 83.759 ;
     RECT  9.468 83.219 31.266 83.903 ;
     RECT  34.815 67.565 35.097 83.987 ;
     RECT  40.215 67.433 40.497 83.987 ;
     RECT  45.615 67.565 45.897 83.987 ;
     RECT  51.015 67.019 51.297 83.987 ;
     RECT  56.193 83.664 56.697 83.987 ;
     RECT  61.815 67.213 62.097 83.987 ;
     RECT  67.215 67.213 67.497 83.987 ;
     RECT  72.396 83.731 72.897 83.987 ;
     RECT  78.015 69.725 78.297 83.987 ;
     RECT  83.415 67.213 83.697 83.987 ;
     RECT  88.815 69.725 89.097 83.987 ;
     RECT  94.215 67.133 94.497 83.987 ;
     RECT  99.615 69.725 99.897 83.987 ;
     RECT  105.015 67.213 105.297 83.987 ;
     RECT  110.415 69.725 110.697 83.987 ;
     RECT  99.615 83.987 99.705 84.001 ;
     RECT  56.193 83.987 56.505 84.027 ;
     RECT  31.104 83.903 31.266 84.029 ;
     RECT  56.196 84.027 56.505 84.029 ;
     RECT  118.26 83.759 118.458 84.029 ;
     RECT  9.468 83.903 30.294 84.065 ;
     RECT  115.815 83.731 116.406 84.065 ;
     RECT  119.484 83.759 128.034 84.065 ;
     RECT  57.744 84.037 57.762 84.077 ;
     RECT  72.396 83.987 72.774 84.077 ;
     RECT  99.396 84.001 99.705 84.077 ;
     RECT  100.944 84.037 100.962 84.077 ;
     RECT  31.248 84.029 31.266 84.091 ;
     RECT  9.468 84.065 29.754 84.137 ;
     RECT  31.248 84.091 31.842 84.137 ;
     RECT  31.824 84.137 31.842 84.173 ;
     RECT  120.276 84.065 120.294 84.173 ;
     RECT  9.468 84.137 29.718 84.209 ;
     RECT  72.615 84.077 72.774 84.209 ;
     RECT  9.468 84.209 29.505 84.257 ;
     RECT  34.815 83.987 34.905 84.257 ;
     RECT  40.215 83.987 40.305 84.257 ;
     RECT  45.615 83.987 45.705 84.257 ;
     RECT  51.015 83.987 51.105 84.257 ;
     RECT  56.415 84.029 56.505 84.257 ;
     RECT  61.815 83.987 61.905 84.257 ;
     RECT  67.215 83.987 67.305 84.257 ;
     RECT  72.615 84.209 72.705 84.257 ;
     RECT  78.015 83.987 78.105 84.257 ;
     RECT  83.415 83.987 83.505 84.257 ;
     RECT  88.815 83.987 88.905 84.257 ;
     RECT  94.215 83.987 94.305 84.257 ;
     RECT  99.615 84.077 99.705 84.257 ;
     RECT  105.015 83.987 105.105 84.257 ;
     RECT  110.415 83.987 110.505 84.257 ;
     RECT  115.815 84.065 115.905 84.257 ;
     RECT  121.215 84.065 121.305 84.257 ;
     RECT  9.468 84.257 28.71 84.365 ;
     RECT  118.26 84.029 118.278 84.653 ;
     RECT  9.468 84.365 27.882 86.4 ;
     RECT  28.692 84.365 28.71 86.4 ;
     RECT  122.292 84.065 128.034 86.4 ;
     RECT  128.952 75.155 131.022 87.691 ;
     RECT  128.952 87.691 131.166 88.115 ;
     RECT  6.192 81.059 6.246 91.939 ;
     RECT  9.468 86.4 128.034 92.971 ;
     RECT  128.952 88.115 131.022 92.971 ;
     RECT  9.468 92.971 131.022 93.917 ;
     RECT  133.092 60.881 134.226 94.667 ;
     RECT  9.468 93.917 123.102 95.377 ;
     RECT  123.948 93.917 131.022 95.453 ;
     RECT  9.036 95.377 123.102 95.549 ;
     RECT  124.524 95.453 131.022 95.645 ;
     RECT  9.036 95.549 122.994 95.747 ;
     RECT  124.848 95.645 131.022 96.061 ;
     RECT  132.015 32.381 132.297 96.061 ;
     RECT  133.092 94.667 134.154 96.061 ;
     RECT  124.848 96.061 132.297 96.089 ;
     RECT  125.172 96.089 132.297 96.151 ;
     RECT  133.092 96.061 134.226 96.151 ;
     RECT  125.172 96.151 134.226 96.215 ;
     RECT  125.172 96.215 134.154 96.221 ;
     RECT  125.172 96.221 132.354 96.859 ;
     RECT  124.848 96.859 132.354 96.899 ;
     RECT  125.172 96.899 132.354 96.989 ;
     RECT  125.244 96.989 132.354 97.037 ;
     RECT  125.424 97.037 132.354 97.259 ;
     RECT  125.82 97.259 132.354 97.277 ;
     RECT  125.964 97.277 132.354 97.295 ;
     RECT  9.036 95.747 122.904 97.411 ;
     RECT  123.66 97.387 123.678 97.411 ;
     RECT  133.092 96.221 134.154 97.411 ;
     RECT  9.036 97.411 123.678 97.439 ;
     RECT  129.816 97.295 132.354 97.601 ;
     RECT  125.964 97.295 128.862 97.673 ;
     RECT  130.464 97.601 132.354 97.681 ;
     RECT  133.092 97.411 134.334 97.681 ;
     RECT  125.964 97.673 128.286 97.907 ;
     RECT  130.464 97.681 134.334 97.907 ;
     RECT  130.536 97.907 134.334 97.951 ;
     RECT  130.536 97.951 134.55 98.141 ;
     RECT  7.056 81.059 8.097 98.185 ;
     RECT  9.036 97.439 122.994 98.185 ;
     RECT  124.704 97.951 124.722 98.185 ;
     RECT  126.615 97.907 128.286 98.237 ;
     RECT  6.048 91.939 6.246 98.311 ;
     RECT  7.056 98.185 122.994 98.311 ;
     RECT  124.668 98.185 124.722 98.347 ;
     RECT  131.616 98.141 134.55 98.375 ;
     RECT  126.615 98.237 128.25 98.381 ;
     RECT  126.615 98.381 127.89 98.429 ;
     RECT  130.536 98.141 130.626 98.447 ;
     RECT  132.015 98.375 134.55 98.447 ;
     RECT  6.048 98.311 123.678 98.483 ;
     RECT  127.8 98.429 127.89 98.483 ;
     RECT  127.872 98.483 127.89 98.519 ;
     RECT  130.536 98.447 130.554 98.519 ;
     RECT  132.015 98.447 132.354 98.519 ;
     RECT  6.048 98.483 123.138 98.525 ;
     RECT  133.344 98.447 134.55 98.609 ;
     RECT  133.704 98.609 134.55 98.681 ;
     RECT  124.668 98.347 124.83 98.717 ;
     RECT  6.048 98.525 123.102 98.725 ;
     RECT  124.668 98.717 124.794 98.813 ;
     RECT  134.28 98.681 134.55 98.879 ;
     RECT  124.668 98.813 124.758 98.909 ;
     RECT  124.668 98.909 124.722 99.005 ;
     RECT  134.532 98.879 134.55 99.023 ;
     RECT  124.668 99.005 124.686 99.031 ;
     RECT  5.616 98.725 123.102 99.059 ;
     RECT  124.236 99.031 124.686 99.101 ;
     RECT  125.568 99.157 125.586 99.197 ;
     RECT  124.668 99.101 124.686 99.293 ;
     RECT  9.972 99.059 123.102 99.599 ;
     RECT  10.152 99.599 123.102 99.661 ;
     RECT  10.152 99.661 123.174 99.833 ;
     RECT  10.152 99.833 123.138 99.869 ;
     RECT  10.152 99.869 123.102 100.253 ;
     RECT  10.152 100.253 123.066 100.349 ;
     RECT  125.136 100.345 125.154 100.603 ;
     RECT  125.136 100.603 125.406 100.651 ;
     RECT  124.848 100.651 125.406 100.733 ;
     RECT  125.244 100.733 125.406 100.795 ;
     RECT  10.152 100.349 122.994 100.925 ;
     RECT  125.244 100.795 125.55 101.467 ;
     RECT  124.848 101.467 125.55 102.619 ;
     RECT  124.848 102.619 125.73 103.579 ;
     RECT  124.848 103.579 125.802 104.081 ;
     RECT  10.152 100.925 122.904 104.161 ;
     RECT  125.136 104.081 125.802 104.315 ;
     RECT  10.152 104.161 123.102 104.381 ;
     RECT  125.172 104.315 125.802 104.827 ;
     RECT  125.172 104.827 125.838 105.205 ;
     RECT  10.152 104.381 122.904 105.367 ;
     RECT  10.152 105.367 122.994 105.533 ;
     RECT  125.136 105.205 125.838 105.629 ;
     RECT  125.136 105.629 125.622 105.691 ;
     RECT  124.848 105.691 125.622 105.737 ;
     RECT  125.136 105.737 125.622 105.935 ;
     RECT  125.136 105.935 125.586 106.013 ;
     RECT  10.152 105.533 122.904 106.447 ;
     RECT  10.152 106.447 123.102 106.685 ;
     RECT  125.172 106.013 125.586 106.939 ;
     RECT  125.136 106.939 125.586 107.227 ;
     RECT  124.848 107.227 125.586 108.167 ;
     RECT  125.172 108.167 125.586 108.329 ;
     RECT  10.152 106.685 122.904 108.841 ;
     RECT  10.152 108.841 122.994 109.291 ;
     RECT  125.208 108.329 125.442 109.339 ;
     RECT  10.152 109.291 123.102 109.469 ;
     RECT  125.172 109.339 125.442 109.531 ;
     RECT  125.136 109.531 125.442 109.819 ;
     RECT  125.136 109.819 125.55 109.915 ;
     RECT  10.152 109.469 122.994 110.045 ;
     RECT  124.848 109.915 125.55 110.395 ;
     RECT  124.848 110.395 125.73 110.795 ;
     RECT  124.884 110.795 125.73 111.029 ;
     RECT  124.884 111.029 125.586 111.101 ;
     RECT  124.92 111.101 125.586 111.137 ;
     RECT  125.136 111.137 125.586 111.991 ;
     RECT  124.848 111.991 125.586 112.061 ;
     RECT  125.136 112.061 125.586 112.649 ;
     RECT  125.136 112.649 125.406 112.987 ;
     RECT  124.848 112.987 125.406 113.371 ;
     RECT  124.848 113.371 125.55 113.495 ;
     RECT  10.152 110.045 122.904 114.547 ;
     RECT  10.152 114.547 123.102 114.653 ;
     RECT  124.848 113.495 125.406 115.115 ;
     RECT  124.848 115.115 125.37 116.059 ;
     RECT  124.848 116.059 125.406 117.481 ;
     RECT  124.848 117.481 125.442 117.979 ;
     RECT  5.616 99.059 9.09 118.021 ;
     RECT  5.616 118.021 9.162 118.057 ;
     RECT  5.4 118.057 9.162 118.129 ;
     RECT  10.152 114.653 122.904 118.129 ;
     RECT  124.848 117.979 125.586 119.039 ;
     RECT  125.172 119.039 125.586 119.129 ;
     RECT  5.4 118.129 122.904 119.641 ;
     RECT  5.4 119.641 122.994 119.741 ;
     RECT  125.172 119.129 125.55 119.803 ;
     RECT  125.136 119.803 125.55 119.899 ;
     RECT  124.848 119.899 125.55 119.975 ;
     RECT  5.4 119.741 122.904 119.983 ;
     RECT  5.112 119.983 122.904 120.055 ;
     RECT  124.848 119.975 125.406 120.763 ;
     RECT  124.848 120.763 125.55 121.055 ;
     RECT  124.848 121.055 125.406 121.819 ;
     RECT  124.848 121.819 125.55 122.675 ;
     RECT  124.848 122.675 125.478 123.451 ;
     RECT  124.848 123.451 125.586 123.593 ;
     RECT  4.716 120.055 122.904 124.141 ;
     RECT  125.172 123.593 125.586 124.259 ;
     RECT  125.172 124.259 125.478 124.411 ;
     RECT  4.716 124.141 123.102 124.541 ;
     RECT  124.848 124.411 125.478 124.637 ;
     RECT  125.136 124.637 125.478 125.105 ;
     RECT  125.136 125.105 125.406 125.371 ;
     RECT  124.848 125.371 125.406 125.851 ;
     RECT  124.524 125.851 125.406 125.879 ;
     RECT  4.716 124.541 122.904 126.139 ;
     RECT  124.524 125.879 125.262 126.185 ;
     RECT  4.716 126.139 122.994 126.419 ;
     RECT  124.524 126.185 125.226 126.725 ;
     RECT  124.524 126.725 125.19 126.959 ;
     RECT  124.524 126.959 125.154 127.103 ;
     RECT  125.136 127.103 125.154 127.265 ;
     RECT  4.716 126.419 122.904 127.464 ;
     RECT  4.716 127.464 28.782 128.236 ;
     RECT  31.572 127.464 31.914 128.281 ;
     RECT  31.464 128.281 31.914 128.347 ;
     RECT  33.012 127.464 37.386 128.347 ;
     RECT  107.604 127.464 107.622 128.539 ;
     RECT  108.684 128.587 108.702 128.635 ;
     RECT  108.684 128.635 108.846 128.683 ;
     RECT  30.204 127.464 30.222 128.776 ;
     RECT  31.464 128.347 37.386 128.776 ;
     RECT  30.204 128.776 37.386 128.965 ;
     RECT  29.808 128.965 37.386 129.046 ;
     RECT  46.836 128.551 46.854 129.127 ;
     RECT  107.604 128.539 107.658 129.271 ;
     RECT  101.988 128.491 102.006 129.316 ;
     RECT  4.716 128.236 29.034 129.397 ;
     RECT  29.808 129.046 38.07 129.397 ;
     RECT  43.74 128.587 43.758 129.433 ;
     RECT  42.192 129.271 42.21 129.469 ;
     RECT  41.976 129.469 42.21 129.505 ;
     RECT  53.028 128.506 53.046 129.505 ;
     RECT  107.604 129.271 107.73 129.505 ;
     RECT  108.504 128.683 108.846 129.505 ;
     RECT  105.372 129.361 105.39 129.583 ;
     RECT  109.872 128.731 109.89 129.583 ;
     RECT  40.215 129.583 40.305 129.631 ;
     RECT  41.904 129.505 42.21 129.631 ;
     RECT  43.02 129.433 43.758 129.631 ;
     RECT  41.904 129.631 43.758 129.659 ;
     RECT  39.996 129.631 40.305 129.667 ;
     RECT  107.604 129.505 108.846 129.691 ;
     RECT  45.615 129.583 45.705 129.703 ;
     RECT  52.668 129.505 53.046 129.703 ;
     RECT  99.615 129.583 99.705 129.703 ;
     RECT  45.615 129.703 46.026 129.739 ;
     RECT  46.8 129.127 46.854 129.739 ;
     RECT  49.608 129.091 49.626 129.739 ;
     RECT  61.815 129.583 61.905 129.739 ;
     RECT  99.615 129.703 100.35 129.739 ;
     RECT  107.604 129.691 109.062 129.739 ;
     RECT  60.444 128.539 60.462 129.767 ;
     RECT  101.592 129.316 102.006 129.775 ;
     RECT  106.668 129.703 106.686 129.775 ;
     RECT  107.532 129.739 109.062 129.775 ;
     RECT  109.872 129.583 110.505 129.775 ;
     RECT  39.96 129.667 40.305 129.787 ;
     RECT  39.708 129.787 40.305 129.811 ;
     RECT  41.904 129.659 43.11 129.811 ;
     RECT  48.888 129.739 49.626 129.811 ;
     RECT  103.68 129.739 103.698 129.811 ;
     RECT  39.708 129.811 40.374 129.853 ;
     RECT  51.015 129.583 51.105 129.853 ;
     RECT  56.415 129.583 56.505 129.853 ;
     RECT  61.308 129.739 61.905 129.853 ;
     RECT  67.215 129.583 67.305 129.853 ;
     RECT  72.615 129.583 72.705 129.853 ;
     RECT  78.015 129.583 78.105 129.853 ;
     RECT  83.415 129.583 83.505 129.853 ;
     RECT  88.815 129.583 88.905 129.853 ;
     RECT  94.215 129.583 94.305 129.853 ;
     RECT  107.532 129.775 110.505 129.853 ;
     RECT  115.815 129.583 115.905 129.853 ;
     RECT  121.215 129.583 121.305 129.853 ;
     RECT  103.68 129.811 104.274 129.883 ;
     RECT  101.592 129.775 102.546 129.901 ;
     RECT  103.608 129.883 104.274 129.901 ;
     RECT  105.015 129.583 105.39 129.901 ;
     RECT  52.02 129.703 53.046 129.929 ;
     RECT  39.708 129.853 40.497 129.931 ;
     RECT  41.832 129.811 43.11 129.931 ;
     RECT  61.308 129.853 62.097 129.937 ;
     RECT  65.196 128.491 65.214 129.937 ;
     RECT  47.772 129.541 47.79 129.973 ;
     RECT  48.816 129.811 49.626 129.973 ;
     RECT  78.015 129.853 78.297 129.973 ;
     RECT  101.592 129.901 105.39 129.973 ;
     RECT  106.596 129.775 106.686 129.973 ;
     RECT  44.856 129.397 44.874 130.009 ;
     RECT  45.615 129.739 46.854 130.009 ;
     RECT  94.215 129.853 94.497 130.009 ;
     RECT  101.592 129.973 106.686 130.009 ;
     RECT  4.716 129.397 38.826 130.027 ;
     RECT  39.564 129.931 40.497 130.027 ;
     RECT  43.848 129.811 43.902 130.045 ;
     RECT  44.856 130.009 46.854 130.045 ;
     RECT  51.015 129.853 51.297 130.045 ;
     RECT  52.02 129.929 52.686 130.045 ;
     RECT  101.34 130.009 106.758 130.045 ;
     RECT  101.304 130.045 106.758 130.061 ;
     RECT  95.76 129.775 95.778 130.073 ;
     RECT  121.215 129.853 121.497 130.075 ;
     RECT  4.716 130.027 40.497 130.081 ;
     RECT  41.328 129.931 43.11 130.081 ;
     RECT  47.772 129.973 50.202 130.081 ;
     RECT  54 129.973 54.738 130.081 ;
     RECT  61.236 129.937 62.097 130.081 ;
     RECT  65.124 129.937 65.214 130.081 ;
     RECT  94.215 130.009 94.662 130.081 ;
     RECT  96.552 130.009 96.57 130.081 ;
     RECT  98.532 130.009 98.55 130.081 ;
     RECT  96.444 130.081 96.57 130.109 ;
     RECT  121.104 130.075 121.497 130.109 ;
     RECT  122.544 129.979 122.562 130.109 ;
     RECT  57.96 129.973 57.978 130.171 ;
     RECT  61.236 130.081 62.766 130.171 ;
     RECT  67.215 129.853 67.497 130.171 ;
     RECT  78.015 129.973 78.462 130.171 ;
     RECT  84.924 130.081 84.942 130.171 ;
     RECT  88.815 129.853 89.097 130.171 ;
     RECT  90.684 130.045 90.702 130.171 ;
     RECT  51.015 130.045 52.686 130.199 ;
     RECT  84.744 130.171 84.942 130.199 ;
     RECT  90.648 130.171 90.702 130.199 ;
     RECT  98.532 130.081 98.694 130.199 ;
     RECT  99.615 129.739 100.386 130.199 ;
     RECT  57.888 130.171 57.978 130.205 ;
     RECT  77.904 130.171 78.462 130.205 ;
     RECT  88.704 130.171 89.097 130.205 ;
     RECT  118.584 130.027 118.602 130.205 ;
     RECT  83.415 129.853 83.697 130.207 ;
     RECT  101.304 130.061 103.734 130.207 ;
     RECT  104.544 130.061 106.758 130.207 ;
     RECT  47.772 130.081 50.274 130.219 ;
     RECT  51.015 130.199 51.297 130.219 ;
     RECT  60.84 130.171 62.766 130.235 ;
     RECT  100.656 130.207 103.734 130.235 ;
     RECT  60.912 130.235 62.766 130.253 ;
     RECT  107.532 129.853 110.697 130.253 ;
     RECT  43.848 130.045 46.854 130.267 ;
     RECT  47.772 130.219 51.297 130.271 ;
     RECT  94.215 130.081 94.734 130.271 ;
     RECT  98.676 130.199 98.694 130.271 ;
     RECT  100.656 130.235 102.042 130.271 ;
     RECT  103.068 130.235 103.734 130.271 ;
     RECT  79.344 130.243 79.362 130.279 ;
     RECT  65.124 130.081 65.466 130.301 ;
     RECT  61.236 130.253 62.766 130.307 ;
     RECT  53.928 130.081 54.81 130.315 ;
     RECT  83.232 130.207 83.697 130.315 ;
     RECT  95.508 130.207 95.526 130.315 ;
     RECT  104.544 130.207 106.794 130.315 ;
     RECT  107.532 130.253 109.458 130.315 ;
     RECT  47.772 130.271 49.986 130.343 ;
     RECT  103.176 130.271 103.734 130.343 ;
     RECT  50.904 130.271 51.297 130.349 ;
     RECT  52.02 130.199 52.542 130.349 ;
     RECT  90.648 130.199 90.666 130.349 ;
     RECT  95.328 130.315 95.526 130.349 ;
     RECT  53.46 130.315 54.81 130.351 ;
     RECT  59.076 130.279 59.094 130.351 ;
     RECT  66.708 130.171 67.497 130.351 ;
     RECT  79.344 130.279 79.398 130.379 ;
     RECT  81.72 130.171 81.738 130.459 ;
     RECT  47.772 130.343 49.626 130.469 ;
     RECT  58.032 130.351 58.05 130.469 ;
     RECT  58.896 130.351 59.094 130.469 ;
     RECT  61.236 130.307 62.097 130.469 ;
     RECT  65.124 130.301 65.142 130.469 ;
     RECT  65.916 130.351 67.497 130.469 ;
     RECT  83.232 130.315 83.79 130.469 ;
     RECT  95.328 130.349 95.418 130.469 ;
     RECT  100.656 130.271 100.674 130.469 ;
     RECT  101.592 130.271 102.042 130.469 ;
     RECT  103.248 130.343 103.734 130.469 ;
     RECT  104.544 130.315 109.458 130.469 ;
     RECT  4.716 130.081 43.11 130.505 ;
     RECT  47.772 130.469 48.654 130.505 ;
     RECT  58.896 130.469 58.914 130.505 ;
     RECT  74.664 130.351 74.682 130.505 ;
     RECT  78.015 130.205 78.462 130.505 ;
     RECT  79.344 130.379 79.362 130.505 ;
     RECT  81.396 130.459 81.738 130.505 ;
     RECT  101.988 130.469 102.042 130.505 ;
     RECT  4.716 130.505 40.59 130.541 ;
     RECT  53.46 130.351 55.278 130.541 ;
     RECT  84.744 130.199 84.762 130.541 ;
     RECT  95.4 130.469 95.418 130.541 ;
     RECT  96.444 130.109 96.534 130.541 ;
     RECT  110.232 130.253 110.697 130.541 ;
     RECT  43.848 130.267 46.926 130.549 ;
     RECT  47.772 130.505 48.294 130.549 ;
     RECT  53.46 130.541 53.946 130.577 ;
     RECT  55.26 130.541 55.278 130.577 ;
     RECT  61.812 130.469 62.097 130.577 ;
     RECT  66.168 130.469 67.497 130.577 ;
     RECT  41.364 130.505 43.11 130.585 ;
     RECT  43.848 130.549 48.294 130.585 ;
     RECT  106.128 130.469 109.458 130.589 ;
     RECT  49.572 130.469 49.626 130.613 ;
     RECT  85.752 130.315 85.77 130.613 ;
     RECT  96.444 130.541 96.462 130.613 ;
     RECT  52.02 130.349 52.038 130.649 ;
     RECT  53.928 130.577 53.946 130.649 ;
     RECT  58.572 130.549 58.662 130.649 ;
     RECT  83.232 130.469 83.697 130.649 ;
     RECT  103.716 130.469 103.734 130.649 ;
     RECT  104.544 130.469 105.297 130.649 ;
     RECT  55.296 130.585 55.314 130.739 ;
     RECT  81.72 130.505 81.738 130.739 ;
     RECT  106.524 130.589 109.458 130.739 ;
     RECT  102.024 130.505 102.042 130.775 ;
     RECT  108.324 130.739 109.458 130.775 ;
     RECT  41.364 130.585 48.294 130.811 ;
     RECT  58.572 130.649 58.59 130.811 ;
     RECT  106.632 130.739 107.19 130.811 ;
     RECT  66.6 130.577 67.497 130.847 ;
     RECT  82.656 130.747 82.674 130.847 ;
     RECT  86.652 130.747 86.67 130.847 ;
     RECT  108.324 130.775 108.882 130.847 ;
     RECT  107.1 130.811 107.19 130.919 ;
     RECT  107.172 130.919 107.19 131.009 ;
     RECT  108.324 130.847 108.342 131.081 ;
     RECT  41.364 130.811 41.598 131.251 ;
     RECT  41.292 131.251 41.598 131.557 ;
     RECT  4.716 130.541 40.497 134.221 ;
     RECT  41.292 131.557 41.67 134.221 ;
     RECT  4.716 134.221 41.67 134.285 ;
     RECT  4.716 134.285 28.566 135.481 ;
     RECT  29.304 134.285 41.67 135.481 ;
     RECT  4.716 135.481 41.67 135.635 ;
     RECT  42.444 130.811 48.294 135.913 ;
     RECT  4.716 135.635 41.598 137.219 ;
     RECT  19.908 137.219 41.598 137.335 ;
     RECT  42.444 135.913 48.798 137.335 ;
     RECT  2.415 82.589 2.697 137.641 ;
     RECT  2.415 137.641 2.934 137.731 ;
     RECT  1.728 137.731 2.934 138.173 ;
     RECT  1.728 138.173 2.862 138.371 ;
     RECT  19.908 137.335 48.798 138.947 ;
     RECT  1.728 138.371 2.697 139.037 ;
     RECT  2.268 139.037 2.697 139.085 ;
     RECT  23.796 138.947 48.798 139.927 ;
     RECT  49.572 130.613 49.59 139.927 ;
     RECT  2.415 139.085 2.697 139.999 ;
     RECT  2.415 139.999 3.294 140.189 ;
     RECT  2.415 140.189 3.186 140.225 ;
     RECT  19.908 138.947 23.058 140.459 ;
     RECT  23.796 139.927 49.59 141.035 ;
     RECT  23.796 141.035 31.914 141.269 ;
     RECT  2.415 140.225 2.934 141.313 ;
     RECT  29.196 141.269 31.914 141.575 ;
     RECT  21.708 140.459 23.058 142.079 ;
     RECT  29.232 141.575 31.914 142.231 ;
     RECT  32.652 141.035 49.59 142.231 ;
     RECT  1.656 143.131 1.674 143.473 ;
     RECT  2.415 141.313 3.438 143.473 ;
     RECT  1.656 143.473 3.438 143.581 ;
     RECT  1.656 143.581 3.834 143.693 ;
     RECT  1.656 143.693 1.674 143.789 ;
     RECT  2.415 143.693 3.834 143.815 ;
     RECT  2.415 143.815 3.942 143.851 ;
     RECT  4.716 137.219 19.134 143.851 ;
     RECT  29.232 142.231 49.59 144.275 ;
     RECT  29.232 144.275 31.914 144.545 ;
     RECT  1.116 144.391 1.134 144.797 ;
     RECT  32.652 144.275 49.59 144.959 ;
     RECT  32.832 144.959 49.59 145.201 ;
     RECT  29.268 144.545 31.914 145.229 ;
     RECT  31.5 145.229 31.914 145.355 ;
     RECT  32.832 145.201 50.202 145.901 ;
     RECT  2.415 143.851 19.134 146.281 ;
     RECT  29.268 145.229 30.762 146.281 ;
     RECT  1.692 146.281 19.134 146.477 ;
     RECT  29.268 146.281 31.086 146.479 ;
     RECT  23.796 141.269 28.35 146.539 ;
     RECT  23.76 146.539 28.35 146.717 ;
     RECT  2.268 146.477 19.134 146.957 ;
     RECT  2.415 146.957 19.134 147.353 ;
     RECT  32.832 145.901 49.878 147.361 ;
     RECT  51.015 130.349 51.297 147.361 ;
     RECT  2.415 147.353 18.954 147.389 ;
     RECT  32.832 147.361 51.297 147.559 ;
     RECT  21.708 142.079 22.554 147.643 ;
     RECT  23.796 146.717 28.35 147.643 ;
     RECT  31.896 145.355 31.914 147.793 ;
     RECT  32.796 147.559 51.297 147.793 ;
     RECT  29.268 146.479 31.158 147.829 ;
     RECT  31.896 147.793 51.297 147.829 ;
     RECT  2.415 147.389 18.897 147.893 ;
     RECT  29.268 147.829 51.297 148.019 ;
     RECT  21.708 147.643 28.35 148.289 ;
     RECT  21.708 148.289 25.074 148.441 ;
     RECT  19.908 140.459 20.502 148.445 ;
     RECT  2.415 147.893 16.29 148.531 ;
     RECT  26.064 148.289 28.35 148.531 ;
     RECT  20.232 148.445 20.502 148.567 ;
     RECT  21.672 148.441 25.074 148.567 ;
     RECT  20.232 148.567 25.074 148.595 ;
     RECT  20.232 148.595 21.222 148.667 ;
     RECT  29.415 148.019 51.297 148.787 ;
     RECT  56.415 129.853 56.697 148.787 ;
     RECT  61.815 130.577 62.097 148.787 ;
     RECT  67.215 130.847 67.497 148.787 ;
     RECT  72.615 129.853 72.897 148.787 ;
     RECT  78.015 130.505 78.297 148.787 ;
     RECT  83.415 130.649 83.697 148.787 ;
     RECT  88.815 130.205 89.097 148.787 ;
     RECT  94.215 130.271 94.497 148.787 ;
     RECT  99.615 130.199 99.897 148.787 ;
     RECT  105.015 130.649 105.297 148.787 ;
     RECT  110.415 130.541 110.697 148.787 ;
     RECT  115.815 129.853 116.097 148.787 ;
     RECT  121.215 130.109 121.497 148.787 ;
     RECT  126.615 98.429 126.897 148.787 ;
     RECT  132.015 98.519 132.297 148.787 ;
     RECT  137.415 2.413 137.697 148.787 ;
     RECT  142.815 2.413 143.097 148.787 ;
     RECT  148.215 2.413 148.497 148.787 ;
     RECT  2.196 148.531 16.29 148.801 ;
     RECT  17.064 147.893 18.897 148.801 ;
     RECT  26.064 148.531 28.386 148.865 ;
     RECT  2.196 148.801 18.897 148.873 ;
     RECT  20.232 148.667 21.078 148.901 ;
     RECT  29.415 148.787 51.105 148.901 ;
     RECT  2.196 148.873 18.918 148.925 ;
     RECT  26.604 148.865 28.386 148.945 ;
     RECT  22.176 148.595 25.074 148.973 ;
     RECT  17.064 148.925 18.918 149.009 ;
     RECT  2.196 148.925 15.894 149.021 ;
     RECT  32.472 148.901 51.105 149.057 ;
     RECT  56.415 148.787 56.505 149.057 ;
     RECT  61.815 148.787 61.905 149.057 ;
     RECT  67.215 148.787 67.305 149.057 ;
     RECT  72.615 148.787 72.705 149.057 ;
     RECT  78.015 148.787 78.105 149.057 ;
     RECT  83.415 148.787 83.505 149.057 ;
     RECT  88.815 148.787 88.905 149.057 ;
     RECT  94.215 148.787 94.305 149.057 ;
     RECT  99.615 148.787 99.705 149.057 ;
     RECT  105.015 148.787 105.105 149.057 ;
     RECT  110.415 148.787 110.505 149.057 ;
     RECT  115.815 148.787 115.905 149.057 ;
     RECT  121.215 148.787 121.305 149.057 ;
     RECT  126.615 148.787 126.705 149.057 ;
     RECT  132.015 148.787 132.105 149.057 ;
     RECT  137.415 148.787 137.505 149.057 ;
     RECT  142.815 148.787 142.905 149.057 ;
     RECT  148.215 148.787 148.305 149.057 ;
     RECT  10.188 149.021 15.894 149.099 ;
     RECT  17.064 149.009 18.846 149.099 ;
     RECT  20.232 148.901 20.502 149.099 ;
     RECT  22.356 148.973 25.074 149.099 ;
     RECT  29.415 148.901 31.158 149.099 ;
     RECT  22.356 149.099 24.21 149.135 ;
     RECT  29.415 149.099 30.87 149.135 ;
     RECT  2.196 149.021 9.342 149.165 ;
     RECT  14.724 149.099 15.894 149.165 ;
     RECT  8.316 149.165 9.342 149.213 ;
     RECT  30.528 149.135 30.87 149.243 ;
     RECT  2.196 149.165 7.434 149.261 ;
     RECT  30.528 149.243 30.546 149.279 ;
     RECT  2.196 149.261 7.29 149.309 ;
     RECT  8.388 149.213 9.342 149.309 ;
     RECT  10.188 149.099 13.662 149.309 ;
     RECT  26.604 148.945 28.602 149.324 ;
     RECT  32.472 149.057 50.994 149.324 ;
     RECT  2.844 149.309 7.29 149.357 ;
     RECT  32.796 149.324 50.994 149.357 ;
     RECT  17.064 149.099 18.774 149.369 ;
     RECT  32.796 149.357 49.59 149.501 ;
     RECT  10.188 149.309 13.626 149.549 ;
     RECT  22.356 149.135 23.886 149.549 ;
     RECT  14.724 149.165 15.39 149.594 ;
     RECT  29.415 149.135 29.682 149.683 ;
     RECT  17.064 149.369 18.738 149.711 ;
     RECT  17.064 149.711 18.702 149.747 ;
     RECT  12.456 149.549 13.626 149.789 ;
     RECT  2.988 149.357 7.29 149.885 ;
     RECT  17.064 149.747 18.198 149.885 ;
     RECT  24.948 149.099 25.074 149.885 ;
     RECT  3.78 149.885 7.29 149.933 ;
     RECT  36 149.501 49.59 149.933 ;
     RECT  50.4 149.357 50.994 149.933 ;
     RECT  36.036 149.933 37.314 150.029 ;
     RECT  36.072 150.029 37.314 150.125 ;
     RECT  17.604 149.885 18.198 150.173 ;
     RECT  7.236 149.933 7.254 150.221 ;
     RECT  10.188 149.549 11.394 150.269 ;
     RECT  12.456 149.789 12.978 150.317 ;
     RECT  3.78 149.933 6.174 150.461 ;
     RECT  8.46 149.309 9.198 150.461 ;
     RECT  36.432 150.125 37.314 150.461 ;
     RECT  40.14 149.933 43.794 150.461 ;
     RECT  44.64 149.933 49.59 150.461 ;
     RECT  18.072 150.173 18.198 150.475 ;
     RECT  14.724 149.594 15.354 150.509 ;
     RECT  22.716 149.549 23.886 150.509 ;
     RECT  26.604 149.324 28.35 150.509 ;
     RECT  29.088 149.683 29.682 150.509 ;
     RECT  32.796 149.501 34.974 150.509 ;
     RECT  36.54 150.461 36.954 150.509 ;
     RECT  40.14 150.461 43.29 150.509 ;
     RECT  45.504 150.461 49.59 150.509 ;
     RECT  50.4 149.933 50.67 150.509 ;
     RECT  18.072 150.475 18.306 150.523 ;
     RECT  23.868 150.509 23.886 150.557 ;
     RECT  32.796 150.509 33.642 150.557 ;
     RECT  36.648 150.509 36.738 150.557 ;
     RECT  45.54 150.509 46.422 150.557 ;
     RECT  48.384 150.509 49.554 150.557 ;
     RECT  29.124 150.509 29.142 150.605 ;
     RECT  36.648 150.557 36.666 150.605 ;
     RECT  45.54 150.557 46.062 150.605 ;
     RECT  49.32 150.557 49.554 150.605 ;
     RECT  45.864 150.605 46.062 150.653 ;
     RECT  48.384 150.557 48.582 150.653 ;
     RECT  19.476 150.619 19.494 150.667 ;
     RECT  20.484 149.099 20.502 150.667 ;
     RECT  49.32 150.605 49.374 150.701 ;
     RECT  14.724 150.509 14.85 150.763 ;
     RECT  49.356 150.701 49.374 150.797 ;
     RECT  14.148 150.763 14.85 150.845 ;
     RECT  26.676 150.509 28.062 150.845 ;
     RECT  14.148 150.845 14.742 150.941 ;
     RECT  9.036 150.461 9.198 150.955 ;
     RECT  10.188 150.269 10.818 150.955 ;
     RECT  12.456 150.317 12.546 150.989 ;
     RECT  18.072 150.523 18.522 150.989 ;
     RECT  21.528 150.811 21.546 150.989 ;
     RECT  45.972 150.653 46.062 150.989 ;
     RECT  18.072 150.989 18.162 151.003 ;
     RECT  19.476 150.667 20.502 151.003 ;
     RECT  31.932 149.719 31.986 151.003 ;
     RECT  12.528 150.989 12.546 151.037 ;
     RECT  17.352 151.003 18.162 151.037 ;
     RECT  22.716 150.509 23.13 151.037 ;
     RECT  31.896 151.003 31.986 151.051 ;
     RECT  32.796 150.557 33.102 151.051 ;
     RECT  17.352 151.037 17.442 151.061 ;
     RECT  2.988 149.885 3.006 151.085 ;
     RECT  3.78 150.461 5.022 151.085 ;
     RECT  9.036 150.955 10.818 151.085 ;
     RECT  17.424 151.061 17.442 151.085 ;
     RECT  26.676 150.845 27.126 151.085 ;
     RECT  29.916 150.811 29.934 151.085 ;
     RECT  38.52 149.933 39.33 151.085 ;
     RECT  40.14 150.509 40.626 151.085 ;
     RECT  41.436 150.509 42.75 151.085 ;
     RECT  46.044 150.989 46.062 151.085 ;
     RECT  47.268 150.509 47.286 151.085 ;
     RECT  48.384 150.653 48.402 151.085 ;
     RECT  50.4 150.509 50.418 151.085 ;
     RECT  26.676 151.085 26.838 151.097 ;
     RECT  31.896 151.051 33.102 151.097 ;
     RECT  10.188 151.085 10.818 151.133 ;
     RECT  14.724 150.941 14.742 151.133 ;
     RECT  19.332 151.003 20.502 151.133 ;
     RECT  21.672 151.003 21.69 151.133 ;
     RECT  24.948 149.885 24.966 151.133 ;
     RECT  26.82 151.097 26.838 151.133 ;
     RECT  28.044 150.845 28.062 151.133 ;
     RECT  30.924 151.003 30.942 151.133 ;
     RECT  31.896 151.097 31.914 151.133 ;
     RECT  20.484 151.133 20.502 151.169 ;
     RECT  33.084 151.097 33.102 151.169 ;
     RECT  10.188 151.133 10.206 151.181 ;
     RECT  19.728 151.133 19.746 151.181 ;
    LAYER M4 ;
     RECT  0.06 80.592 0.133 81.288 ;
     RECT  0.133 80.592 0.229 82.2 ;
     RECT  0.229 79.728 0.277 82.2 ;
     RECT  0.805 144.816 0.997 144.84 ;
     RECT  0.901 143.664 1.093 143.688 ;
     RECT  0.997 144.768 1.145 144.84 ;
     RECT  0.709 142.464 1.189 142.488 ;
     RECT  1.285 139.056 1.381 139.08 ;
     RECT  1.477 146.304 1.669 146.328 ;
     RECT  1.669 146.304 1.765 146.472 ;
     RECT  1.765 146.304 1.861 146.952 ;
     RECT  1.861 146.304 1.957 147.24 ;
     RECT  1.957 146.304 2.053 147.528 ;
     RECT  1.573 149.328 2.149 149.352 ;
     RECT  2.149 149.28 2.245 149.352 ;
     RECT  2.053 146.304 2.293 147.624 ;
     RECT  2.365 78.48 2.408 78.504 ;
     RECT  0.277 79.632 2.408 82.2 ;
     RECT  1.381 139.008 2.408 139.08 ;
     RECT  1.189 141.936 2.408 142.488 ;
     RECT  1.093 143.664 2.408 143.784 ;
     RECT  1.145 144.816 2.408 144.84 ;
     RECT  2.293 146.304 2.408 147.816 ;
     RECT  2.245 148.992 2.408 149.352 ;
     RECT  2.408 2.148 2.512 149.352 ;
     RECT  2.512 2.418 2.704 149.352 ;
     RECT  2.293 150.96 2.725 150.984 ;
     RECT  2.704 149.136 2.765 149.352 ;
     RECT  2.704 147.216 2.837 147.912 ;
     RECT  2.765 149.184 2.837 149.352 ;
     RECT  2.704 145.872 2.867 145.896 ;
     RECT  2.725 150.864 2.867 150.984 ;
     RECT  2.704 141.936 2.945 142.488 ;
     RECT  2.704 78.48 3.341 78.744 ;
     RECT  2.704 144.768 3.377 144.84 ;
     RECT  2.945 142.464 3.449 142.488 ;
     RECT  3.377 144.768 3.521 144.792 ;
     RECT  2.837 149.328 3.589 149.352 ;
     RECT  3.589 149.328 3.635 149.88 ;
     RECT  2.837 147.408 3.781 147.912 ;
     RECT  3.805 77.28 3.875 77.304 ;
     RECT  2.704 80.592 3.875 81.096 ;
     RECT  3.875 80.832 3.881 81.096 ;
     RECT  3.635 149.328 3.973 149.352 ;
     RECT  3.781 147.408 4.261 148.152 ;
     RECT  4.261 147.408 4.309 148.2 ;
     RECT  3.973 149.28 4.309 149.352 ;
     RECT  4.309 147.408 4.313 149.352 ;
     RECT  4.313 147.408 4.417 149.304 ;
     RECT  2.917 151.056 4.549 151.08 ;
     RECT  4.417 146.976 4.741 149.304 ;
     RECT  4.741 146.448 4.781 149.304 ;
     RECT  4.781 147.552 5.033 149.304 ;
     RECT  4.549 150.432 5.033 151.08 ;
     RECT  3.881 80.832 5.125 80.952 ;
     RECT  5.125 80.736 5.171 80.952 ;
     RECT  3.341 78.48 5.177 78.648 ;
     RECT  5.033 147.6 5.317 149.304 ;
     RECT  3.829 72.72 5.365 72.744 ;
     RECT  5.365 72.72 5.411 73.512 ;
     RECT  5.353 76.944 5.411 76.968 ;
     RECT  5.317 147.6 5.569 149.352 ;
     RECT  5.033 150.432 5.569 150.456 ;
     RECT  5.177 78.624 5.753 78.648 ;
     RECT  5.569 147.6 6.185 150.456 ;
     RECT  6.181 0.816 6.217 0.84 ;
     RECT  4.781 146.448 6.229 146.472 ;
     RECT  5.171 80.736 6.325 80.856 ;
     RECT  6.145 145.056 6.565 145.08 ;
     RECT  6.229 146.256 6.565 146.472 ;
     RECT  6.433 2.352 6.613 2.376 ;
     RECT  6.037 122.208 6.649 122.232 ;
     RECT  6.001 123.456 6.649 123.48 ;
     RECT  6.565 145.056 6.661 146.472 ;
     RECT  6.613 2.352 6.709 3.528 ;
     RECT  6.661 4.56 6.709 4.584 ;
     RECT  6.649 122.208 6.709 123.48 ;
     RECT  6.709 2.352 6.757 4.584 ;
     RECT  6.757 2.256 6.793 4.632 ;
     RECT  6.661 144.768 6.829 146.472 ;
     RECT  6.185 147.6 6.829 150.168 ;
     RECT  6.217 0.096 6.869 0.84 ;
     RECT  6.793 2.256 7.009 4.776 ;
     RECT  6.757 143.424 7.081 143.448 ;
     RECT  7.045 7.104 7.141 7.128 ;
     RECT  7.009 2.256 7.189 5.112 ;
     RECT  7.153 126.768 7.189 126.792 ;
     RECT  6.869 0.144 7.225 0.84 ;
     RECT  7.189 2.256 7.225 5.784 ;
     RECT  6.829 144.768 7.225 150.168 ;
     RECT  7.093 116.496 7.333 116.52 ;
     RECT  7.081 143.088 7.333 143.448 ;
     RECT  7.225 144.768 7.333 150.216 ;
     RECT  7.525 9.648 7.585 9.672 ;
     RECT  5.411 72.72 7.585 73.509 ;
     RECT  7.225 0.144 7.621 5.784 ;
     RECT  7.141 6.816 7.621 7.128 ;
     RECT  7.585 9.12 7.669 9.672 ;
     RECT  7.381 32.256 7.669 32.28 ;
     RECT  7.513 11.424 7.729 11.448 ;
     RECT  7.621 0.144 7.808 7.128 ;
     RECT  7.669 8.16 7.808 9.672 ;
     RECT  7.729 11.424 7.808 12.024 ;
     RECT  7.669 32.256 7.808 32.328 ;
     RECT  7.585 72.72 7.808 73.512 ;
     RECT  6.325 80.736 7.808 80.904 ;
     RECT  6.229 95.088 7.808 95.112 ;
     RECT  6.757 97.056 7.808 97.08 ;
     RECT  6.805 98.352 7.808 98.376 ;
     RECT  6.709 100.224 7.808 100.248 ;
     RECT  7.333 115.632 7.808 116.52 ;
     RECT  7.225 120.24 7.808 120.264 ;
     RECT  6.709 122.208 7.808 123.528 ;
     RECT  6.685 124.512 7.808 124.536 ;
     RECT  7.189 126.768 7.808 127.368 ;
     RECT  7.729 128.592 7.808 128.616 ;
     RECT  6.805 129.648 7.808 129.672 ;
     RECT  6.073 130.848 7.808 130.872 ;
     RECT  6.721 131.904 7.808 131.928 ;
     RECT  6.109 134.256 7.808 134.28 ;
     RECT  7.333 143.088 7.808 150.216 ;
     RECT  7.808 0.144 7.859 150.216 ;
     RECT  7.859 0.192 8.101 150.216 ;
     RECT  8.101 0.192 8.104 150.456 ;
     RECT  8.104 9.12 8.243 12.552 ;
     RECT  8.104 0.192 8.387 7.464 ;
     RECT  8.104 79.44 8.579 81 ;
     RECT  8.243 9.12 8.633 10.248 ;
     RECT  8.104 145.056 8.677 150.456 ;
     RECT  8.104 13.68 8.819 16.536 ;
     RECT  8.387 0.24 8.921 7.464 ;
     RECT  8.579 80.64 9.011 81 ;
     RECT  8.104 29.088 9.065 29.64 ;
     RECT  8.104 118.368 9.097 118.392 ;
     RECT  8.921 0.24 9.107 6.36 ;
     RECT  8.819 13.68 9.109 15.912 ;
     RECT  8.921 7.44 9.133 7.464 ;
     RECT  8.104 72.72 9.133 72.744 ;
     RECT  9.097 118.368 9.169 118.44 ;
     RECT  9.157 70.08 9.203 70.104 ;
     RECT  9.133 72.72 9.203 72.984 ;
     RECT  8.633 9.12 9.209 9.96 ;
     RECT  8.104 17.664 9.245 17.688 ;
     RECT  9.109 13.536 9.251 15.912 ;
     RECT  9.133 7.44 9.281 7.992 ;
     RECT  9.107 0.24 9.349 5.88 ;
     RECT  9.209 9.12 9.353 9.72 ;
     RECT  9.349 18.192 9.395 18.216 ;
     RECT  8.104 100.224 9.397 100.248 ;
     RECT  9.349 0.192 9.445 5.88 ;
     RECT  8.243 11.424 9.461 12.552 ;
     RECT  9.353 9.696 9.491 9.72 ;
     RECT  8.104 19.392 9.493 20.328 ;
     RECT  8.104 97.056 9.493 97.08 ;
     RECT  9.281 7.968 9.497 7.992 ;
     RECT  9.493 26.16 9.541 26.184 ;
     RECT  8.104 31.632 9.541 32.952 ;
     RECT  9.461 11.952 9.569 12.552 ;
     RECT  9.541 27.36 9.637 27.384 ;
     RECT  8.104 115.584 9.637 116.52 ;
     RECT  9.541 25.68 9.677 26.184 ;
     RECT  9.677 26.064 9.683 26.184 ;
     RECT  9.637 27.264 9.685 27.384 ;
     RECT  9.397 100.224 9.925 101.112 ;
     RECT  8.104 98.352 9.997 98.376 ;
     RECT  9.251 13.68 10.109 15.912 ;
     RECT  9.925 56.448 10.117 56.472 ;
     RECT  9.925 100.224 10.117 101.736 ;
     RECT  8.104 95.088 10.141 95.112 ;
     RECT  9.493 96.576 10.141 97.08 ;
     RECT  8.104 125.664 10.141 125.688 ;
     RECT  8.677 145.056 10.177 151.08 ;
     RECT  9.733 10.896 10.285 10.92 ;
     RECT  9.445 0.096 10.309 5.88 ;
     RECT  10.261 7.056 10.309 7.128 ;
     RECT  9.569 12.528 10.325 12.552 ;
     RECT  10.309 0.096 10.355 7.128 ;
     RECT  8.104 120.24 10.355 120.888 ;
     RECT  10.355 2.64 10.361 7.128 ;
     RECT  10.261 21.648 10.361 21.672 ;
     RECT  10.285 10.848 10.405 10.92 ;
     RECT  8.104 122.208 10.451 123.528 ;
     RECT  10.109 14.112 10.453 15.912 ;
     RECT  10.361 2.832 10.541 7.128 ;
     RECT  10.451 122.208 10.547 123.48 ;
     RECT  10.453 14.112 10.549 16.584 ;
     RECT  9.065 29.616 10.549 29.64 ;
     RECT  10.117 99.936 10.597 101.736 ;
     RECT  10.541 2.832 10.613 5.64 ;
     RECT  10.405 10.752 10.645 10.92 ;
     RECT  10.117 55.872 10.645 56.472 ;
     RECT  10.549 29.616 10.685 29.688 ;
     RECT  10.501 54.144 10.685 54.168 ;
     RECT  10.645 55.824 10.691 56.472 ;
     RECT  10.645 25.776 10.741 25.8 ;
     RECT  10.549 14.112 10.757 17.112 ;
     RECT  10.645 10.272 10.793 10.92 ;
     RECT  9.493 18.24 10.793 20.328 ;
     RECT  10.693 51.888 10.793 51.912 ;
     RECT  10.793 10.752 10.825 10.92 ;
     RECT  8.104 128.592 10.825 129.672 ;
     RECT  8.104 143.424 10.825 143.976 ;
     RECT  10.685 29.664 10.865 29.688 ;
     RECT  10.825 10.752 10.883 11.4 ;
     RECT  10.573 112.896 10.885 112.92 ;
     RECT  9.589 114.288 10.885 114.312 ;
     RECT  10.741 25.728 10.897 25.8 ;
     RECT  9.541 31.632 10.897 33.576 ;
     RECT  10.897 25.68 10.901 25.8 ;
     RECT  10.645 110.592 10.901 110.616 ;
     RECT  10.883 10.752 10.937 10.776 ;
     RECT  10.757 14.112 10.973 16.536 ;
     RECT  10.213 23.616 10.981 23.64 ;
     RECT  10.825 128.592 11.005 129.768 ;
     RECT  8.104 130.848 11.005 131.928 ;
     RECT  10.177 145.056 11.045 151.176 ;
     RECT  10.541 6.816 11.077 7.128 ;
     RECT  9.685 27.264 11.077 28.008 ;
     RECT  10.901 25.68 11.081 25.752 ;
     RECT  10.981 105.456 11.113 105.48 ;
     RECT  10.885 55.296 11.117 55.32 ;
     RECT  10.613 5.088 11.123 5.64 ;
     RECT  10.973 14.832 11.123 16.536 ;
     RECT  10.789 21.936 11.149 21.96 ;
     RECT  10.981 23.616 11.149 23.976 ;
     RECT  11.123 14.832 11.153 15.912 ;
     RECT  11.149 21.936 11.173 23.976 ;
     RECT  11.173 21.936 11.219 24.648 ;
     RECT  11.081 25.68 11.219 25.704 ;
     RECT  11.125 13.104 11.221 13.128 ;
     RECT  10.933 53.04 11.221 53.064 ;
     RECT  10.793 18.288 11.225 20.328 ;
     RECT  11.077 27.264 11.257 28.536 ;
     RECT  8.104 134.256 11.257 134.28 ;
     RECT  10.021 103.536 11.269 103.56 ;
     RECT  11.221 13.104 11.297 13.656 ;
     RECT  11.257 26.784 11.315 28.536 ;
     RECT  10.355 0.096 11.317 1.416 ;
     RECT  9.169 118.176 11.317 118.44 ;
     RECT  10.691 56.4 11.329 56.472 ;
     RECT  11.219 23.616 11.333 24.648 ;
     RECT  9.203 70.083 11.365 70.101 ;
     RECT  10.597 99.936 11.365 102.072 ;
     RECT  11.365 70.08 11.405 70.104 ;
     RECT  11.221 53.04 11.459 53.544 ;
     RECT  11.041 111.696 11.473 111.72 ;
     RECT  10.613 2.832 11.507 3.672 ;
     RECT  11.333 23.616 11.513 24.552 ;
     RECT  11.077 6.816 11.549 7.464 ;
     RECT  11.473 111.696 11.605 111.768 ;
     RECT  10.885 112.896 11.605 114.312 ;
     RECT  11.507 2.832 11.617 3.144 ;
     RECT  10.165 48.768 11.617 48.792 ;
     RECT  11.123 5.088 11.653 5.496 ;
     RECT  11.557 109.488 11.653 109.512 ;
     RECT  11.617 48.432 11.699 48.792 ;
     RECT  11.413 106.608 11.699 106.632 ;
     RECT  11.545 107.712 11.699 107.736 ;
     RECT  11.653 109.392 11.699 109.512 ;
     RECT  11.549 6.816 11.725 7.272 ;
     RECT  11.557 50.16 11.729 50.184 ;
     RECT  11.329 56.4 11.749 57.576 ;
     RECT  11.365 99.936 11.749 102.456 ;
     RECT  11.269 103.536 11.749 104.328 ;
     RECT  11.653 4.56 11.765 5.496 ;
     RECT  11.315 27.312 11.797 28.536 ;
     RECT  11.797 27.312 11.843 28.824 ;
     RECT  11.699 109.392 11.843 109.416 ;
     RECT  11.605 111.696 11.843 114.312 ;
     RECT  11.749 56.4 11.845 57.624 ;
     RECT  11.797 59.472 11.845 59.496 ;
     RECT  11.845 55.92 11.869 57.624 ;
     RECT  11.845 58.8 11.869 59.496 ;
     RECT  11.257 133.728 11.893 134.28 ;
     RECT  11.905 11.952 11.941 11.976 ;
     RECT  8.104 35.76 11.941 35.784 ;
     RECT  11.113 105.408 11.941 105.48 ;
     RECT  10.897 30.864 11.945 33.576 ;
     RECT  11.843 27.312 11.981 28.536 ;
     RECT  11.941 11.952 11.987 12.792 ;
     RECT  11.459 53.04 12.017 53.064 ;
     RECT  11.845 10.8 12.049 10.824 ;
     RECT  11.153 14.832 12.083 15.672 ;
     RECT  11.725 6.72 12.089 7.272 ;
     RECT  12.037 9.12 12.089 9.24 ;
     RECT  12.089 9.216 12.133 9.24 ;
     RECT  11.869 55.92 12.133 59.496 ;
     RECT  11.701 54.768 12.157 54.792 ;
     RECT  9.011 80.64 12.161 80.904 ;
     RECT  12.133 9.216 12.179 9.672 ;
     RECT  12.049 10.8 12.179 11.448 ;
     RECT  12.121 50.736 12.179 50.76 ;
     RECT  8.104 124.512 12.179 124.536 ;
     RECT  10.141 125.664 12.193 125.736 ;
     RECT  8.104 126.768 12.193 127.368 ;
     RECT  12.179 9.648 12.197 9.672 ;
     RECT  10.141 95.088 12.229 97.08 ;
     RECT  9.997 98.352 12.229 98.664 ;
     RECT  11.317 0.048 12.301 1.416 ;
     RECT  11.617 2.688 12.301 3.144 ;
     RECT  11.941 35.088 12.325 35.784 ;
     RECT  12.229 95.088 12.373 98.664 ;
     RECT  11.225 18.96 12.421 20.328 ;
     RECT  12.325 35.088 12.445 35.928 ;
     RECT  11.941 105.408 12.469 106.248 ;
     RECT  9.637 115.392 12.469 116.52 ;
     RECT  11.893 133.008 12.481 134.28 ;
     RECT  10.355 120.24 12.553 120.264 ;
     RECT  12.157 54.72 12.565 54.792 ;
     RECT  12.325 108.864 12.565 108.888 ;
     RECT  12.469 115.392 12.613 116.904 ;
     RECT  11.317 118.176 12.613 118.92 ;
     RECT  12.301 0.048 12.661 3.144 ;
     RECT  12.133 55.872 12.661 59.496 ;
     RECT  12.565 107.856 12.661 108.888 ;
     RECT  11.557 110.496 12.661 110.52 ;
     RECT  12.421 18.24 12.805 20.328 ;
     RECT  12.565 54.72 12.841 54.84 ;
     RECT  12.661 55.824 12.841 59.496 ;
     RECT  12.661 110.496 12.841 110.616 ;
     RECT  12.661 0.048 12.913 3.912 ;
     RECT  11.765 4.944 12.913 5.496 ;
     RECT  12.445 34.8 12.949 35.928 ;
     RECT  12.373 95.088 12.949 98.952 ;
     RECT  11.843 112.32 12.949 114.312 ;
     RECT  12.613 115.392 12.949 118.92 ;
     RECT  12.949 112.32 12.985 118.92 ;
     RECT  12.913 0.048 12.997 5.496 ;
     RECT  12.089 6.72 12.997 6.984 ;
     RECT  12.733 53.568 12.997 53.592 ;
     RECT  12.277 92.4 12.997 92.424 ;
     RECT  12.997 0.048 13.093 6.984 ;
     RECT  11.699 48.768 13.093 48.792 ;
     RECT  12.997 53.184 13.093 53.592 ;
     RECT  12.841 54.72 13.093 59.496 ;
     RECT  12.469 105.312 13.093 106.248 ;
     RECT  12.661 107.808 13.093 108.888 ;
     RECT  12.985 112.176 13.093 118.92 ;
     RECT  11.045 145.056 13.093 147.48 ;
     RECT  13.093 53.088 13.129 53.592 ;
     RECT  13.093 0.048 13.208 7.464 ;
     RECT  12.179 10.8 13.208 10.824 ;
     RECT  11.987 12.768 13.208 12.792 ;
     RECT  12.181 14.784 13.208 14.808 ;
     RECT  12.805 17.376 13.208 20.328 ;
     RECT  11.219 21.936 13.208 21.96 ;
     RECT  11.513 23.616 13.208 23.64 ;
     RECT  11.981 27.312 13.208 27.96 ;
     RECT  11.945 30.912 13.208 33.576 ;
     RECT  12.949 34.8 13.208 35.976 ;
     RECT  13.093 48.768 13.208 49.08 ;
     RECT  12.985 51.312 13.208 51.336 ;
     RECT  13.129 52.8 13.208 53.592 ;
     RECT  13.093 54.72 13.208 59.544 ;
     RECT  12.949 66.576 13.208 66.6 ;
     RECT  12.949 69.936 13.208 69.96 ;
     RECT  9.203 72.72 13.208 72.744 ;
     RECT  8.579 79.44 13.208 79.464 ;
     RECT  12.161 80.64 13.208 80.856 ;
     RECT  12.229 90.336 13.208 90.36 ;
     RECT  12.997 92.4 13.208 92.712 ;
     RECT  12.949 94.944 13.208 98.952 ;
     RECT  11.749 99.936 13.208 104.328 ;
     RECT  13.093 105.312 13.208 108.888 ;
     RECT  12.841 110.496 13.208 110.664 ;
     RECT  13.093 112.176 13.208 119.16 ;
     RECT  12.553 120.24 13.208 120.408 ;
     RECT  10.547 122.208 13.208 122.808 ;
     RECT  12.193 125.664 13.208 127.368 ;
     RECT  11.005 128.592 13.208 131.928 ;
     RECT  12.481 133.008 13.208 134.808 ;
     RECT  13.057 135.888 13.208 135.912 ;
     RECT  8.104 137.616 13.208 137.64 ;
     RECT  9.541 138.816 13.208 138.84 ;
     RECT  11.437 140.304 13.208 140.328 ;
     RECT  10.825 143.424 13.208 144.072 ;
     RECT  13.093 145.056 13.208 147.672 ;
     RECT  11.045 148.848 13.208 151.176 ;
     RECT  13.208 0.048 13.504 151.176 ;
     RECT  13.504 52.704 13.601 53.544 ;
     RECT  13.504 17.616 13.619 17.64 ;
     RECT  13.504 105.312 13.667 111.576 ;
     RECT  13.504 145.056 13.667 147.576 ;
     RECT  13.504 133.008 13.709 134.808 ;
     RECT  13.504 118.272 13.715 120.888 ;
     RECT  13.504 142.752 13.715 144.072 ;
     RECT  13.504 54.72 13.763 59.496 ;
     RECT  13.504 92.112 13.763 104.328 ;
     RECT  13.763 56.16 13.853 59.496 ;
     RECT  13.763 54.72 13.889 54.984 ;
     RECT  13.853 56.304 13.925 59.496 ;
     RECT  13.504 50.64 14.003 51 ;
     RECT  13.667 105.456 14.003 111.576 ;
     RECT  13.504 125.664 14.003 125.736 ;
     RECT  13.715 120.144 14.099 120.888 ;
     RECT  13.667 145.056 14.099 147.336 ;
     RECT  14.003 105.456 14.105 110.568 ;
     RECT  13.504 112.896 14.105 117.288 ;
     RECT  14.003 50.976 14.213 51 ;
     RECT  14.105 105.552 14.285 110.568 ;
     RECT  13.504 128.592 14.291 131.928 ;
     RECT  14.099 145.056 14.387 146.28 ;
     RECT  14.003 111.552 14.533 111.576 ;
     RECT  14.003 125.712 14.569 125.736 ;
     RECT  13.504 126.768 14.569 127.368 ;
     RECT  14.533 14.016 14.579 14.04 ;
     RECT  14.285 105.648 14.579 110.568 ;
     RECT  13.504 122.208 14.605 122.568 ;
     RECT  14.569 125.712 14.675 127.368 ;
     RECT  14.533 111.552 14.677 111.864 ;
     RECT  13.715 118.272 14.713 119.112 ;
     RECT  14.099 120.144 14.713 120.84 ;
     RECT  14.641 46.416 14.749 46.44 ;
     RECT  14.749 46.416 14.753 46.824 ;
     RECT  14.579 105.648 14.753 110.52 ;
     RECT  14.605 122.208 14.753 122.616 ;
     RECT  14.713 118.272 14.771 120.84 ;
     RECT  13.504 30.576 14.773 33.576 ;
     RECT  14.753 105.648 14.819 110.184 ;
     RECT  13.504 0.048 14.821 8.088 ;
     RECT  14.485 9.168 14.821 9.192 ;
     RECT  13.763 103.488 14.825 104.328 ;
     RECT  14.819 107.52 14.825 110.088 ;
     RECT  14.821 0.048 14.861 9.192 ;
     RECT  14.675 126.528 14.861 127.368 ;
     RECT  14.753 46.512 14.869 46.824 ;
     RECT  14.869 46.512 14.915 47.16 ;
     RECT  13.504 66.579 14.965 66.597 ;
     RECT  14.099 147.312 15.001 147.336 ;
     RECT  14.915 46.8 15.005 47.16 ;
     RECT  14.965 66.576 15.005 66.6 ;
     RECT  14.753 122.208 15.011 122.568 ;
     RECT  13.504 48.768 15.109 48.936 ;
     RECT  14.861 8.976 15.113 9.192 ;
     RECT  13.504 38.688 15.157 38.712 ;
     RECT  14.105 113.328 15.181 117.288 ;
     RECT  14.771 118.272 15.181 119.016 ;
     RECT  15.073 66.672 15.185 66.696 ;
     RECT  14.677 37.344 15.205 37.368 ;
     RECT  13.763 92.112 15.205 102.456 ;
     RECT  14.677 111.552 15.217 112.344 ;
     RECT  15.181 113.328 15.217 119.016 ;
     RECT  14.771 120.144 15.251 120.84 ;
     RECT  15.251 120.144 15.293 120.504 ;
     RECT  15.205 36.912 15.301 37.368 ;
     RECT  13.601 53.52 15.469 53.544 ;
     RECT  15.469 53.52 15.505 53.592 ;
     RECT  15.505 53.184 15.539 53.592 ;
     RECT  14.861 126.624 15.539 127.368 ;
     RECT  13.709 133.152 15.589 134.808 ;
     RECT  13.504 135.888 15.589 135.912 ;
     RECT  13.504 12.768 15.683 12.792 ;
     RECT  13.504 72.72 15.685 72.744 ;
     RECT  13.504 80.64 15.685 80.856 ;
     RECT  15.685 80.496 15.725 80.856 ;
     RECT  15.725 80.496 15.731 80.52 ;
     RECT  15.539 126.624 15.731 126.648 ;
     RECT  15.301 36.912 15.733 37.416 ;
     RECT  15.157 38.4 15.733 38.712 ;
     RECT  14.819 105.648 15.733 106.248 ;
     RECT  14.725 42.72 15.781 42.744 ;
     RECT  13.715 144.048 15.827 144.072 ;
     RECT  14.861 0.048 15.829 7.992 ;
     RECT  15.113 8.976 15.829 9.144 ;
     RECT  13.504 35.04 15.829 35.784 ;
     RECT  15.733 36.912 15.829 38.712 ;
     RECT  13.925 56.4 15.901 59.496 ;
     RECT  13.504 27.312 15.925 27.624 ;
     RECT  15.349 29.232 15.925 29.256 ;
     RECT  15.217 111.552 15.937 119.016 ;
     RECT  15.829 0.048 15.971 9.144 ;
     RECT  15.901 56.4 15.971 59.832 ;
     RECT  13.504 18.912 15.973 20.328 ;
     RECT  15.973 18.048 16.019 20.328 ;
     RECT  14.291 128.592 16.019 129.144 ;
     RECT  15.637 14.448 16.021 14.472 ;
     RECT  15.253 88.176 16.069 88.2 ;
     RECT  16.021 14.256 16.085 14.472 ;
     RECT  16.021 11.856 16.117 11.88 ;
     RECT  16.085 14.304 16.117 14.472 ;
     RECT  13.889 54.96 16.117 54.984 ;
     RECT  14.825 103.488 16.153 104.088 ;
     RECT  15.733 105.36 16.153 106.248 ;
     RECT  16.117 11.424 16.163 11.88 ;
     RECT  14.533 16.56 16.163 16.584 ;
     RECT  15.937 110.832 16.225 119.016 ;
     RECT  15.937 45.744 16.229 45.768 ;
     RECT  16.163 11.856 16.265 11.88 ;
     RECT  15.205 91.44 16.265 102.456 ;
     RECT  14.825 107.52 16.265 109.416 ;
     RECT  15.293 120.48 16.309 120.504 ;
     RECT  16.117 54.672 16.337 54.984 ;
     RECT  16.337 54.72 16.357 54.984 ;
     RECT  15.971 56.4 16.357 59.736 ;
     RECT  16.019 129.12 16.357 129.144 ;
     RECT  14.291 130.224 16.357 131.928 ;
     RECT  16.357 54.72 16.409 59.736 ;
     RECT  16.225 110.544 16.453 119.016 ;
     RECT  15.001 147.312 16.453 147.816 ;
     RECT  13.504 148.848 16.453 151.176 ;
     RECT  15.637 10.272 16.477 10.296 ;
     RECT  16.309 120.48 16.481 120.84 ;
     RECT  13.504 21.936 16.501 21.96 ;
     RECT  13.504 65.232 16.501 65.256 ;
     RECT  16.117 14.304 16.517 15.336 ;
     RECT  13.504 140.448 16.597 140.472 ;
     RECT  15.005 46.8 16.621 46.92 ;
     RECT  15.109 48.672 16.621 48.936 ;
     RECT  16.481 120.672 16.657 120.84 ;
     RECT  15.829 35.04 16.691 38.712 ;
     RECT  16.621 25.632 16.693 25.656 ;
     RECT  16.501 64.704 16.693 65.256 ;
     RECT  16.657 120.672 16.693 120.888 ;
     RECT  16.265 99.936 16.697 102.456 ;
     RECT  16.621 46.752 16.729 46.92 ;
     RECT  16.517 14.736 16.739 15.336 ;
     RECT  16.693 120.672 16.739 120.984 ;
     RECT  16.697 100.992 16.741 102.456 ;
     RECT  16.693 25.104 16.805 25.656 ;
     RECT  15.971 0.048 16.835 8.52 ;
     RECT  16.729 46.656 16.877 46.92 ;
     RECT  16.621 48.48 16.877 48.936 ;
     RECT  16.597 140.448 16.883 140.568 ;
     RECT  16.453 110.256 16.909 119.016 ;
     RECT  16.789 51.36 16.933 51.384 ;
     RECT  16.693 64.704 16.933 66.168 ;
     RECT  15.589 133.152 16.945 135.912 ;
     RECT  16.835 0.048 16.949 0.216 ;
     RECT  16.837 50.16 16.949 50.184 ;
     RECT  16.835 1.248 16.979 8.52 ;
     RECT  13.715 142.752 16.981 142.776 ;
     RECT  16.877 46.896 17.021 46.92 ;
     RECT  16.909 110.256 17.027 119.16 ;
     RECT  16.739 120.672 17.027 120.936 ;
     RECT  16.981 142.752 17.029 143.688 ;
     RECT  16.979 1.392 17.057 8.52 ;
     RECT  17.029 142.752 17.057 143.784 ;
     RECT  16.949 0.048 17.075 0.168 ;
     RECT  16.933 62.736 17.075 62.76 ;
     RECT  16.933 64.704 17.075 66.264 ;
     RECT  16.805 25.632 17.077 25.656 ;
     RECT  15.925 27.312 17.077 29.256 ;
     RECT  16.877 48.672 17.089 48.936 ;
     RECT  17.077 25.632 17.123 29.256 ;
     RECT  17.077 63.072 17.123 63.096 ;
     RECT  17.075 64.704 17.123 66.168 ;
     RECT  17.027 110.256 17.123 113.448 ;
     RECT  15.539 53.184 17.125 53.208 ;
     RECT  17.057 8.496 17.129 8.52 ;
     RECT  16.933 51.312 17.129 51.384 ;
     RECT  17.089 48.672 17.161 48.984 ;
     RECT  14.387 145.584 17.171 146.28 ;
     RECT  16.741 100.992 17.173 102.504 ;
     RECT  16.153 103.488 17.173 106.248 ;
     RECT  16.265 107.52 17.173 109.272 ;
     RECT  17.129 51.36 17.201 51.384 ;
     RECT  17.125 52.464 17.201 53.208 ;
     RECT  16.885 13.104 17.237 13.128 ;
     RECT  16.739 14.832 17.237 15.336 ;
     RECT  17.171 145.584 17.267 146.232 ;
     RECT  17.173 11.52 17.305 11.544 ;
     RECT  17.305 11.424 17.363 11.544 ;
     RECT  16.501 21.936 17.363 22.536 ;
     RECT  17.237 15.312 17.365 15.336 ;
     RECT  13.504 138.816 17.365 138.84 ;
     RECT  17.123 25.824 17.411 29.256 ;
     RECT  17.201 53.184 17.413 53.208 ;
     RECT  16.409 54.72 17.413 54.984 ;
     RECT  17.365 15.312 17.417 15.384 ;
     RECT  16.477 10.272 17.509 10.392 ;
     RECT  17.057 1.392 17.555 7.368 ;
     RECT  17.305 45.024 17.557 45.048 ;
     RECT  16.453 147.312 17.557 151.176 ;
     RECT  17.509 9.696 17.561 10.824 ;
     RECT  13.504 23.616 17.605 23.64 ;
     RECT  16.691 35.424 17.605 38.712 ;
     RECT  17.413 53.184 17.653 54.984 ;
     RECT  16.409 56.4 17.653 59.736 ;
     RECT  17.605 23.616 17.737 23.976 ;
     RECT  16.019 18.96 17.749 20.328 ;
     RECT  17.173 100.992 17.749 109.272 ;
     RECT  17.269 128.112 17.881 128.136 ;
     RECT  16.357 129.12 17.881 131.928 ;
     RECT  17.749 100.896 17.893 109.272 ;
     RECT  14.773 30.576 17.941 33.624 ;
     RECT  17.605 35.424 17.989 39.288 ;
     RECT  17.075 0.048 18.037 0.12 ;
     RECT  17.893 100.848 18.037 109.272 ;
     RECT  17.027 120.864 18.037 120.936 ;
     RECT  17.377 13.536 18.169 13.704 ;
     RECT  17.557 44.688 18.169 45.048 ;
     RECT  17.411 25.824 18.181 25.848 ;
     RECT  17.411 27.312 18.181 29.256 ;
     RECT  17.363 21.984 18.229 22.536 ;
     RECT  17.737 23.616 18.229 24.264 ;
     RECT  18.229 21.984 18.241 24.264 ;
     RECT  18.181 25.68 18.241 25.848 ;
     RECT  17.881 128.112 18.241 131.928 ;
     RECT  17.269 51.888 18.277 51.96 ;
     RECT  17.653 53.184 18.277 59.736 ;
     RECT  17.123 63.075 18.325 63.093 ;
     RECT  18.133 47.328 18.349 47.352 ;
     RECT  16.069 88.128 18.349 88.2 ;
     RECT  18.037 100.128 18.349 109.272 ;
     RECT  17.123 110.256 18.349 112.872 ;
     RECT  17.941 30.576 18.373 34.104 ;
     RECT  17.989 35.424 18.373 39.384 ;
     RECT  18.325 62.256 18.373 63.093 ;
     RECT  16.309 123.456 18.373 123.48 ;
     RECT  18.277 124.56 18.373 124.68 ;
     RECT  18.277 126.528 18.373 126.552 ;
     RECT  18.037 0.048 18.421 0.168 ;
     RECT  18.181 27.312 18.421 29.304 ;
     RECT  13.504 79.44 18.421 79.464 ;
     RECT  18.349 88.128 18.421 89.256 ;
     RECT  18.373 30.576 18.457 39.384 ;
     RECT  18.373 40.8 18.457 40.92 ;
     RECT  18.421 88.032 18.457 89.256 ;
     RECT  18.241 127.824 18.457 131.928 ;
     RECT  18.457 30.576 18.469 40.92 ;
     RECT  15.781 41.904 18.469 42.744 ;
     RECT  13.504 137.04 18.469 137.64 ;
     RECT  18.169 44.688 18.493 45.768 ;
     RECT  17.555 1.392 18.608 6.888 ;
     RECT  17.561 10.176 18.608 10.824 ;
     RECT  18.169 13.536 18.608 14.232 ;
     RECT  17.417 15.312 18.608 15.336 ;
     RECT  17.749 18.96 18.608 21 ;
     RECT  18.241 21.984 18.608 25.848 ;
     RECT  18.421 27.072 18.608 29.304 ;
     RECT  18.469 30.576 18.608 42.744 ;
     RECT  18.493 44.448 18.608 45.768 ;
     RECT  18.349 47.136 18.608 47.352 ;
     RECT  17.161 48.672 18.608 49.032 ;
     RECT  18.277 51.888 18.608 59.736 ;
     RECT  18.373 62.256 18.608 63.288 ;
     RECT  17.123 64.704 18.608 65.256 ;
     RECT  15.685 72.72 18.608 73.272 ;
     RECT  18.421 77.184 18.608 77.208 ;
     RECT  18.421 79.44 18.608 79.992 ;
     RECT  18.421 85.248 18.608 85.272 ;
     RECT  18.457 88.032 18.608 89.352 ;
     RECT  13.504 90.336 18.608 90.36 ;
     RECT  16.265 91.44 18.608 98.952 ;
     RECT  18.349 100.128 18.608 112.872 ;
     RECT  17.027 114.528 18.608 119.16 ;
     RECT  18.037 120.816 18.608 120.936 ;
     RECT  15.011 122.208 18.608 122.472 ;
     RECT  18.373 123.456 18.608 124.68 ;
     RECT  18.373 126.432 18.608 126.552 ;
     RECT  18.457 127.776 18.608 131.928 ;
     RECT  16.945 133.152 18.608 135.96 ;
     RECT  18.469 136.992 18.608 137.64 ;
     RECT  17.365 138.816 18.608 139.416 ;
     RECT  16.883 140.544 18.608 140.568 ;
     RECT  16.549 141.6 18.608 141.624 ;
     RECT  17.057 142.752 18.608 142.776 ;
     RECT  17.057 143.76 18.608 143.784 ;
     RECT  17.267 146.16 18.608 146.232 ;
     RECT  17.557 147.264 18.608 151.176 ;
     RECT  18.608 1.392 18.712 151.176 ;
     RECT  18.712 2.418 18.904 151.176 ;
     RECT  18.904 62.256 18.929 63.288 ;
     RECT  18.421 0.048 18.949 0.36 ;
     RECT  18.904 91.44 18.965 119.4 ;
     RECT  18.904 143.76 18.965 143.784 ;
     RECT  18.904 123.456 19.001 124.632 ;
     RECT  18.904 54.624 19.043 60.024 ;
     RECT  18.712 1.392 19.091 1.416 ;
     RECT  18.904 66.672 19.109 67.56 ;
     RECT  18.904 50.544 19.145 50.568 ;
     RECT  18.904 10.8 19.217 10.824 ;
     RECT  18.949 0.048 19.235 0.408 ;
     RECT  18.904 120.72 19.283 120.84 ;
     RECT  18.904 41.904 19.325 44.472 ;
     RECT  19.283 120.72 19.379 120.744 ;
     RECT  18.904 20.976 19.433 21 ;
     RECT  19.043 54.72 19.433 60.024 ;
     RECT  18.904 5.184 19.619 5.64 ;
     RECT  18.904 6.672 19.619 7.992 ;
     RECT  19.619 6.672 19.715 6.744 ;
     RECT  18.904 146.16 19.757 151.176 ;
     RECT  19.433 54.72 19.901 59.736 ;
     RECT  18.904 51.936 19.907 51.96 ;
     RECT  18.904 2.544 19.909 2.568 ;
     RECT  18.904 21.984 19.909 23.112 ;
     RECT  19.909 2.544 19.933 2.904 ;
     RECT  18.904 45.552 19.933 49.56 ;
     RECT  18.904 53.568 19.973 53.592 ;
     RECT  18.904 122.208 20.005 122.472 ;
     RECT  19.001 123.456 20.005 123.48 ;
     RECT  20.005 122.208 20.045 123.48 ;
     RECT  18.904 35.424 20.053 40.824 ;
     RECT  19.933 45.552 20.113 49.608 ;
     RECT  18.904 90.336 20.113 90.36 ;
     RECT  20.053 35.184 20.149 40.824 ;
     RECT  18.904 79.2 20.149 79.464 ;
     RECT  18.904 127.104 20.149 131.688 ;
     RECT  18.965 106.944 20.197 119.4 ;
     RECT  20.113 45.168 20.221 49.608 ;
     RECT  20.077 50.64 20.221 50.664 ;
     RECT  20.149 126.48 20.243 131.688 ;
     RECT  20.149 35.184 20.245 40.92 ;
     RECT  19.325 41.904 20.245 43.704 ;
     RECT  19.619 7.968 20.257 7.992 ;
     RECT  19.909 21.984 20.257 23.64 ;
     RECT  20.221 45.168 20.257 50.664 ;
     RECT  20.113 4.08 20.293 4.104 ;
     RECT  19.619 5.184 20.293 5.304 ;
     RECT  19.901 54.72 20.329 59.688 ;
     RECT  18.904 133.152 20.339 135.96 ;
     RECT  19.933 2.304 20.341 2.904 ;
     RECT  20.293 4.08 20.341 5.304 ;
     RECT  18.904 64.848 20.389 65.256 ;
     RECT  20.045 122.352 20.405 123.48 ;
     RECT  20.243 126.528 20.405 131.688 ;
     RECT  20.405 122.4 20.435 123.48 ;
     RECT  18.904 27.072 20.437 34.104 ;
     RECT  20.245 35.184 20.437 43.704 ;
     RECT  20.435 122.592 20.441 123.48 ;
     RECT  20.257 7.968 20.473 8.04 ;
     RECT  19.897 12.528 20.473 12.552 ;
     RECT  18.929 62.256 20.473 62.28 ;
     RECT  18.929 63.264 20.473 63.288 ;
     RECT  20.405 126.576 20.483 131.688 ;
     RECT  20.473 12.528 20.485 12.6 ;
     RECT  18.904 137.04 20.531 139.464 ;
     RECT  20.257 45.168 20.533 51.528 ;
     RECT  19.109 67.536 20.533 67.56 ;
     RECT  20.197 106.944 20.581 119.832 ;
     RECT  18.904 24.96 20.617 25.752 ;
     RECT  20.437 27.072 20.617 43.704 ;
     RECT  20.473 62.256 20.653 63.288 ;
     RECT  20.533 66.672 20.675 67.56 ;
     RECT  20.341 2.304 20.725 5.304 ;
     RECT  19.715 6.672 20.773 6.696 ;
     RECT  20.473 7.968 20.773 8.52 ;
     RECT  20.725 1.728 20.797 5.304 ;
     RECT  20.773 6.672 20.797 8.52 ;
     RECT  20.389 14.256 20.797 14.28 ;
     RECT  20.441 123.456 20.821 123.48 ;
     RECT  19.001 124.512 20.821 124.632 ;
     RECT  20.617 24.96 20.867 43.704 ;
     RECT  20.797 10.848 20.869 10.872 ;
     RECT  20.473 16.56 20.869 16.584 ;
     RECT  20.257 21.456 20.869 23.64 ;
     RECT  20.389 64.848 20.869 65.304 ;
     RECT  20.581 106.944 20.869 120.024 ;
     RECT  20.869 21.12 20.915 23.64 ;
     RECT  20.869 106.944 20.941 120.456 ;
     RECT  20.869 16.512 20.977 16.584 ;
     RECT  18.904 18.96 20.977 18.984 ;
     RECT  20.867 26.208 20.981 43.704 ;
     RECT  20.869 10.272 21.013 10.872 ;
     RECT  20.653 61.92 21.013 63.288 ;
     RECT  20.869 64.272 21.013 65.304 ;
     RECT  20.533 45.024 21.049 51.528 ;
     RECT  20.981 36.816 21.053 43.704 ;
     RECT  20.977 15.984 21.059 16.584 ;
     RECT  18.965 91.44 21.085 105.912 ;
     RECT  20.941 106.944 21.085 120.84 ;
     RECT  21.059 16.512 21.125 16.584 ;
     RECT  20.485 12.528 21.157 12.936 ;
     RECT  21.049 44.928 21.157 51.528 ;
     RECT  21.125 16.56 21.193 16.584 ;
     RECT  21.157 44.688 21.193 51.528 ;
     RECT  20.329 54.144 21.193 59.688 ;
     RECT  20.339 133.2 21.203 135.96 ;
     RECT  20.797 1.728 21.229 9.144 ;
     RECT  21.013 10.272 21.229 11.4 ;
     RECT  21.193 44.688 21.251 51.864 ;
     RECT  21.013 61.92 21.301 65.304 ;
     RECT  20.821 123.456 21.301 124.632 ;
     RECT  21.301 123.456 21.337 124.728 ;
     RECT  21.157 12.528 21.349 12.984 ;
     RECT  20.797 14.256 21.397 14.808 ;
     RECT  21.349 12.528 21.409 13.08 ;
     RECT  21.397 14.256 21.409 14.856 ;
     RECT  20.113 89.424 21.409 90.36 ;
     RECT  21.085 91.44 21.409 120.84 ;
     RECT  21.337 123.456 21.409 124.824 ;
     RECT  21.229 1.728 21.445 11.4 ;
     RECT  21.193 54.096 21.445 59.688 ;
     RECT  21.193 16.56 21.481 17.112 ;
     RECT  21.409 12.528 21.541 14.856 ;
     RECT  20.977 18.768 21.541 18.984 ;
     RECT  21.541 18.768 21.589 19.416 ;
     RECT  21.445 54.096 21.685 60.216 ;
     RECT  18.904 140.544 21.779 140.568 ;
     RECT  20.483 126.768 21.781 131.688 ;
     RECT  21.053 36.816 21.809 43.032 ;
     RECT  21.589 18.768 21.925 19.656 ;
     RECT  20.867 24.96 21.949 24.984 ;
     RECT  20.981 26.208 21.949 35.832 ;
     RECT  21.685 53.232 21.973 60.216 ;
     RECT  21.409 89.424 22.021 120.84 ;
     RECT  21.973 53.136 22.057 60.216 ;
     RECT  20.915 21.456 22.069 23.64 ;
     RECT  21.445 1.728 22.097 11.448 ;
     RECT  21.541 12.528 22.117 15.432 ;
     RECT  21.481 16.56 22.117 17.688 ;
     RECT  22.021 89.424 22.129 120.984 ;
     RECT  21.409 122.544 22.237 124.824 ;
     RECT  22.069 20.688 22.261 23.64 ;
     RECT  22.129 89.424 22.273 121.128 ;
     RECT  22.237 122.496 22.273 124.824 ;
     RECT  21.925 18.72 22.309 19.656 ;
     RECT  22.261 20.64 22.309 23.64 ;
     RECT  21.251 44.688 22.357 51.816 ;
     RECT  22.057 53.04 22.357 60.216 ;
     RECT  22.273 89.424 22.381 124.824 ;
     RECT  22.117 12.528 22.405 17.688 ;
     RECT  22.309 18.72 22.405 23.64 ;
     RECT  18.904 88.128 22.417 88.2 ;
     RECT  22.381 89.424 22.417 125.352 ;
     RECT  22.405 12.528 22.453 23.64 ;
     RECT  21.949 24.96 22.453 35.832 ;
     RECT  19.235 0.048 22.457 0.36 ;
     RECT  22.097 2.064 22.489 11.448 ;
     RECT  21.205 66.48 22.501 66.504 ;
     RECT  20.675 67.536 22.501 67.56 ;
     RECT  21.203 133.776 22.549 135.96 ;
     RECT  22.453 12.528 22.595 35.832 ;
     RECT  21.809 36.912 22.597 43.032 ;
     RECT  22.489 2.064 22.633 11.496 ;
     RECT  22.595 12.528 22.633 15.816 ;
     RECT  22.357 44.688 22.669 60.216 ;
     RECT  22.597 36.912 22.705 43.368 ;
     RECT  22.669 44.688 22.705 60.696 ;
     RECT  22.705 36.912 22.741 60.696 ;
     RECT  21.301 61.728 22.741 65.304 ;
     RECT  21.061 77.808 22.789 77.832 ;
     RECT  20.149 79.2 22.789 79.752 ;
     RECT  22.417 88.128 22.789 125.352 ;
     RECT  21.781 126.528 22.789 131.688 ;
     RECT  22.741 36.912 22.813 65.304 ;
     RECT  22.501 66.48 22.813 67.56 ;
     RECT  20.531 137.04 22.813 137.88 ;
     RECT  22.549 133.776 22.837 136.008 ;
     RECT  22.789 77.808 22.853 79.848 ;
     RECT  22.853 77.904 22.921 79.848 ;
     RECT  22.357 83.808 22.961 83.832 ;
     RECT  22.921 77.904 22.979 79.944 ;
     RECT  22.595 16.896 22.993 35.832 ;
     RECT  22.813 36.912 22.993 65.448 ;
     RECT  22.789 88.128 23.101 131.688 ;
     RECT  23.029 70.56 23.173 70.584 ;
     RECT  22.837 132.96 23.365 136.008 ;
     RECT  22.457 0.048 23.821 0.168 ;
     RECT  22.633 2.064 24.008 15.816 ;
     RECT  22.993 16.896 24.008 65.448 ;
     RECT  22.813 66.48 24.008 67.656 ;
     RECT  23.173 70.56 24.008 70.68 ;
     RECT  18.904 72.72 24.008 73.272 ;
     RECT  18.904 75.696 24.008 75.72 ;
     RECT  22.979 77.904 24.008 77.928 ;
     RECT  22.979 79.2 24.008 79.8 ;
     RECT  23.125 81.168 24.008 81.192 ;
     RECT  23.701 86.64 24.008 86.664 ;
     RECT  23.101 87.936 24.008 131.688 ;
     RECT  23.365 132.768 24.008 136.008 ;
     RECT  22.813 136.992 24.008 137.88 ;
     RECT  20.531 139.392 24.008 139.464 ;
     RECT  18.904 141.6 24.008 141.624 ;
     RECT  18.904 142.752 24.008 142.776 ;
     RECT  19.757 146.16 24.008 151.128 ;
     RECT  24.008 2.064 24.037 151.128 ;
     RECT  24.037 2.016 24.133 151.128 ;
     RECT  24.133 1.968 24.229 151.128 ;
     RECT  24.229 1.872 24.304 151.128 ;
     RECT  24.304 1.872 24.401 25.272 ;
     RECT  24.401 2.016 24.419 25.224 ;
     RECT  24.419 2.016 24.437 15.816 ;
     RECT  24.304 87.936 24.437 136.008 ;
     RECT  24.304 26.736 24.509 67.656 ;
     RECT  23.821 0.048 24.649 0.264 ;
     RECT  24.437 88.128 25.157 136.008 ;
     RECT  24.649 0.048 25.261 0.504 ;
     RECT  24.509 26.736 25.265 67.32 ;
     RECT  25.157 88.128 25.265 100.824 ;
     RECT  24.437 2.064 25.331 15.816 ;
     RECT  24.304 72.72 25.477 73.272 ;
     RECT  24.304 70.704 25.573 70.728 ;
     RECT  25.331 2.064 25.619 13.08 ;
     RECT  25.331 14.208 25.621 15.816 ;
     RECT  24.419 16.896 25.621 25.224 ;
     RECT  25.619 2.064 25.661 10.152 ;
     RECT  25.661 2.064 25.667 7.992 ;
     RECT  24.304 74.64 25.697 75.72 ;
     RECT  24.304 77.904 25.717 79.8 ;
     RECT  25.477 72.72 25.733 73.512 ;
     RECT  25.573 70.128 25.769 70.728 ;
     RECT  25.265 26.832 25.837 67.32 ;
     RECT  25.619 11.232 25.841 13.08 ;
     RECT  25.621 14.208 25.841 25.224 ;
     RECT  25.667 2.064 25.877 7.8 ;
     RECT  25.157 101.904 25.909 136.008 ;
     RECT  24.304 137.04 25.909 137.88 ;
     RECT  25.841 11.76 25.949 13.08 ;
     RECT  25.841 14.208 25.985 15.816 ;
     RECT  25.877 2.064 26.021 6.84 ;
     RECT  25.949 12.48 26.021 13.08 ;
     RECT  24.304 146.16 26.053 151.128 ;
     RECT  26.021 2.064 26.195 6.408 ;
     RECT  25.837 26.832 26.233 67.848 ;
     RECT  24.304 83.76 26.233 84.168 ;
     RECT  25.841 16.896 26.237 25.224 ;
     RECT  25.261 0.048 26.245 0.552 ;
     RECT  26.233 82.944 26.245 84.168 ;
     RECT  25.265 88.704 26.245 100.824 ;
     RECT  25.909 101.904 26.245 137.88 ;
     RECT  25.717 77.28 26.293 79.8 ;
     RECT  25.697 75.216 26.309 75.72 ;
     RECT  26.021 12.864 26.381 13.08 ;
     RECT  26.195 2.064 26.387 6.312 ;
     RECT  24.304 139.392 26.387 139.464 ;
     RECT  26.387 2.064 26.417 6.264 ;
     RECT  25.985 14.208 26.437 14.52 ;
     RECT  25.769 70.704 26.437 70.728 ;
     RECT  26.237 16.896 26.489 17.688 ;
     RECT  26.417 2.064 26.525 5.784 ;
     RECT  26.525 2.304 26.531 5.784 ;
     RECT  26.293 76.752 26.533 79.8 ;
     RECT  24.304 81.168 26.533 81.192 ;
     RECT  25.985 15.792 26.561 15.816 ;
     RECT  25.873 86.592 26.581 86.616 ;
     RECT  26.245 88.704 26.581 137.88 ;
     RECT  26.437 70.704 26.633 71.256 ;
     RECT  26.531 2.304 26.669 3.864 ;
     RECT  25.661 8.976 26.741 10.152 ;
     RECT  26.245 0.048 26.771 0.6 ;
     RECT  26.669 2.688 26.777 3.864 ;
     RECT  26.777 3.408 26.813 3.864 ;
     RECT  26.489 16.896 26.813 16.92 ;
     RECT  26.533 76.752 26.821 81.192 ;
     RECT  26.245 82.416 26.821 84.168 ;
     RECT  26.053 145.344 26.849 151.128 ;
     RECT  26.233 26.736 26.867 67.848 ;
     RECT  26.741 8.976 26.965 10.104 ;
     RECT  26.581 86.592 26.965 137.88 ;
     RECT  26.965 86.496 27.013 137.88 ;
     RECT  26.437 13.632 27.029 14.52 ;
     RECT  27.013 86.112 27.059 137.88 ;
     RECT  26.965 8.496 27.061 10.104 ;
     RECT  27.013 70.464 27.137 70.68 ;
     RECT  24.304 141.6 27.203 141.624 ;
     RECT  26.237 18.672 27.205 25.224 ;
     RECT  26.867 26.736 27.205 67.608 ;
     RECT  27.061 8.448 27.301 10.104 ;
     RECT  27.205 18.672 27.317 67.608 ;
     RECT  27.317 18.672 27.347 67.512 ;
     RECT  26.821 76.752 27.349 84.168 ;
     RECT  27.059 86.112 27.529 137.784 ;
     RECT  27.529 85.968 27.587 137.784 ;
     RECT  26.309 75.696 27.589 75.72 ;
     RECT  27.349 76.752 27.589 84.36 ;
     RECT  27.587 85.968 27.641 136.008 ;
     RECT  27.601 17.088 27.683 17.112 ;
     RECT  27.137 70.56 27.685 70.68 ;
     RECT  26.771 0.048 27.731 0.552 ;
     RECT  27.641 85.968 27.731 135.96 ;
     RECT  27.685 70.56 27.781 71.064 ;
     RECT  27.301 8.256 27.827 10.104 ;
     RECT  26.813 3.84 27.877 3.864 ;
     RECT  27.781 70.56 27.877 71.16 ;
     RECT  27.731 0.048 27.893 0.264 ;
     RECT  26.849 145.344 27.923 151.08 ;
     RECT  27.347 18.672 27.965 67.416 ;
     RECT  27.877 70.56 27.965 71.256 ;
     RECT  27.923 146.16 28.033 151.08 ;
     RECT  27.893 0.096 28.115 0.264 ;
     RECT  27.965 70.56 28.115 70.68 ;
     RECT  28.115 70.656 28.163 70.68 ;
     RECT  27.587 137.04 28.393 137.784 ;
     RECT  26.387 139.392 28.393 139.416 ;
     RECT  27.965 19.248 28.397 67.416 ;
     RECT  27.589 75.696 28.433 84.36 ;
     RECT  27.731 86.016 28.721 135.96 ;
     RECT  28.721 86.4 28.825 135.96 ;
     RECT  28.393 137.04 28.825 139.656 ;
     RECT  28.753 2.256 29.041 2.28 ;
     RECT  29.041 1.392 29.077 2.28 ;
     RECT  29.077 1.392 29.221 2.328 ;
     RECT  27.877 3.84 29.221 3.912 ;
     RECT  29.221 1.392 29.269 3.912 ;
     RECT  26.531 4.944 29.269 5.784 ;
     RECT  29.269 1.392 29.408 5.784 ;
     RECT  27.827 8.256 29.408 9.048 ;
     RECT  27.827 10.08 29.408 10.104 ;
     RECT  27.029 14.496 29.408 14.52 ;
     RECT  28.397 19.632 29.408 67.416 ;
     RECT  25.733 72.72 29.408 72.744 ;
     RECT  28.433 75.696 29.408 84.168 ;
     RECT  28.825 86.4 29.408 139.656 ;
     RECT  28.249 141.264 29.408 141.288 ;
     RECT  24.304 142.752 29.408 142.776 ;
     RECT  28.033 146.16 29.408 151.128 ;
     RECT  29.408 1.392 29.512 84.252 ;
     RECT  29.512 1.392 29.704 84.168 ;
     RECT  29.408 86.4 29.704 151.128 ;
     RECT  29.704 78.72 29.801 84.168 ;
     RECT  29.704 137.04 29.843 138.072 ;
     RECT  29.704 75.696 29.981 77.64 ;
     RECT  29.981 75.696 30.089 76.296 ;
     RECT  29.801 78.912 30.125 84.168 ;
     RECT  29.704 142.752 30.227 142.776 ;
     RECT  30.089 75.696 30.413 75.72 ;
     RECT  29.704 1.392 30.611 2.856 ;
     RECT  30.125 78.96 30.629 84.168 ;
     RECT  30.611 2.736 30.697 2.856 ;
     RECT  29.704 3.84 30.697 5.784 ;
     RECT  28.115 0.096 30.757 0.216 ;
     RECT  30.697 2.736 30.757 5.784 ;
     RECT  29.704 10.08 30.757 10.104 ;
     RECT  29.704 14.496 30.757 14.52 ;
     RECT  29.704 19.632 30.757 67.56 ;
     RECT  29.704 8.256 30.803 9.048 ;
     RECT  30.629 78.96 30.845 81.624 ;
     RECT  30.757 2.736 30.899 6.984 ;
     RECT  30.757 10.08 30.899 11.016 ;
     RECT  30.757 14.496 30.899 14.952 ;
     RECT  30.757 18.672 30.899 67.56 ;
     RECT  30.757 0.096 30.901 0.408 ;
     RECT  30.611 1.392 30.901 1.416 ;
     RECT  30.629 82.704 30.953 84.168 ;
     RECT  30.901 0.096 30.989 1.416 ;
     RECT  30.845 78.96 30.989 80.088 ;
     RECT  30.989 0.096 30.995 0.408 ;
     RECT  30.899 2.832 30.995 5.784 ;
     RECT  30.899 6.768 30.995 6.888 ;
     RECT  30.899 10.08 30.995 10.92 ;
     RECT  30.899 14.496 30.995 14.856 ;
     RECT  30.899 18.768 30.995 67.56 ;
     RECT  29.981 77.28 31.061 77.64 ;
     RECT  30.995 0.096 31.139 0.216 ;
     RECT  30.995 2.832 31.139 2.856 ;
     RECT  29.704 146.16 31.187 151.128 ;
     RECT  31.187 146.16 31.283 146.472 ;
     RECT  29.843 137.04 31.379 137.256 ;
     RECT  30.989 78.96 31.421 79.224 ;
     RECT  31.421 78.96 31.457 78.984 ;
     RECT  29.704 86.4 31.475 135.96 ;
     RECT  31.283 146.208 31.571 146.472 ;
     RECT  31.061 77.28 31.637 77.304 ;
     RECT  31.139 0.096 31.853 0.12 ;
     RECT  30.845 81.6 31.853 81.624 ;
     RECT  31.187 147.504 31.925 151.128 ;
     RECT  31.475 135.888 32.147 135.96 ;
     RECT  30.953 83.088 32.213 84.168 ;
     RECT  30.995 19.632 32.357 67.56 ;
     RECT  32.357 20.688 32.681 67.56 ;
     RECT  31.475 86.4 32.717 134.808 ;
     RECT  32.717 132.96 32.897 134.808 ;
     RECT  32.897 133.728 33.041 134.808 ;
     RECT  31.925 147.504 33.203 151.08 ;
     RECT  29.704 139.392 33.395 139.416 ;
     RECT  30.803 8.304 33.445 9.048 ;
     RECT  31.379 137.04 33.491 137.064 ;
     RECT  33.203 147.504 33.683 150.696 ;
     RECT  33.041 134.304 33.779 134.808 ;
     RECT  32.681 20.832 33.833 67.56 ;
     RECT  33.683 147.504 33.875 150.552 ;
     RECT  33.833 21.12 34.265 67.56 ;
     RECT  30.989 1.392 34.808 1.416 ;
     RECT  30.995 3.84 34.808 5.784 ;
     RECT  33.445 7.44 34.808 9.048 ;
     RECT  30.995 10.08 34.808 10.104 ;
     RECT  30.995 14.496 34.808 14.52 ;
     RECT  32.357 19.632 34.808 19.656 ;
     RECT  34.265 21.12 34.808 22.536 ;
     RECT  34.265 23.76 34.808 67.56 ;
     RECT  29.704 72.72 34.808 72.744 ;
     RECT  32.213 83.76 34.808 84.168 ;
     RECT  32.717 86.4 34.808 131.688 ;
     RECT  33.779 134.784 34.808 134.808 ;
     RECT  32.147 135.888 34.808 135.912 ;
     RECT  31.571 146.208 34.808 146.424 ;
     RECT  33.875 147.504 34.808 150.504 ;
     RECT  34.808 86.4 34.835 150.504 ;
     RECT  34.835 150.48 34.885 150.504 ;
     RECT  34.808 1.392 34.912 22.536 ;
     RECT  34.808 23.76 34.912 84.252 ;
     RECT  34.885 150.48 35.027 151.032 ;
     RECT  34.912 1.392 35.104 21.48 ;
     RECT  34.912 23.76 35.104 84.168 ;
     RECT  34.835 86.4 35.104 149.496 ;
     RECT  35.104 146.256 35.267 149.496 ;
     RECT  35.027 150.912 35.267 151.032 ;
     RECT  35.267 146.4 35.315 149.496 ;
     RECT  35.267 150.912 35.315 150.936 ;
     RECT  35.104 7.44 35.741 9.048 ;
     RECT  35.104 86.4 35.813 131.688 ;
     RECT  35.104 134.304 35.849 134.52 ;
     RECT  35.315 147.024 35.989 149.496 ;
     RECT  35.989 147.024 36.025 149.928 ;
     RECT  35.104 144.864 36.101 144.888 ;
     RECT  35.813 86.4 36.245 131.592 ;
     RECT  36.097 134.544 36.245 134.568 ;
     RECT  36.133 142.512 36.245 142.536 ;
     RECT  36.245 86.4 36.353 131.352 ;
     RECT  36.025 147.024 36.421 150.12 ;
     RECT  36.353 86.4 36.461 131.064 ;
     RECT  36.421 147.024 36.529 150.456 ;
     RECT  36.529 147.024 36.637 150.504 ;
     RECT  36.637 147.024 36.713 150.6 ;
     RECT  36.461 86.4 37.397 131.016 ;
     RECT  37.397 128.496 37.469 131.016 ;
     RECT  36.853 144.576 37.501 144.6 ;
     RECT  37.213 142.176 37.609 142.2 ;
     RECT  36.713 147.072 37.619 150.6 ;
     RECT  37.469 128.496 37.721 130.968 ;
     RECT  37.501 143.952 37.933 144.6 ;
     RECT  37.619 147.072 37.973 149.928 ;
     RECT  37.721 128.496 38.045 130.584 ;
     RECT  37.609 141.936 38.185 142.2 ;
     RECT  37.973 147.072 38.291 149.496 ;
     RECT  38.185 141.936 38.483 142.296 ;
     RECT  38.045 129.6 38.549 130.584 ;
     RECT  38.483 142.176 38.675 142.296 ;
     RECT  38.509 151.056 38.725 151.08 ;
     RECT  38.549 129.936 38.729 130.584 ;
     RECT  38.291 147.072 38.797 149.352 ;
     RECT  38.729 129.936 38.801 130.536 ;
     RECT  35.104 23.76 39.161 67.56 ;
     RECT  35.104 1.392 39.205 2.232 ;
     RECT  35.104 3.84 39.205 3.912 ;
     RECT  38.797 146.496 39.517 149.352 ;
     RECT  38.801 129.936 39.697 130.2 ;
     RECT  39.517 146.448 39.733 149.352 ;
     RECT  38.725 150.48 39.733 151.08 ;
     RECT  39.205 1.392 39.805 3.912 ;
     RECT  35.104 4.896 39.805 5.784 ;
     RECT  39.805 1.392 40.208 5.784 ;
     RECT  35.741 8.304 40.208 9.048 ;
     RECT  35.104 10.08 40.208 10.104 ;
     RECT  35.104 14.496 40.208 14.52 ;
     RECT  35.104 19.632 40.208 19.656 ;
     RECT  35.104 21.456 40.208 21.48 ;
     RECT  34.912 22.464 40.208 22.536 ;
     RECT  39.161 66.768 40.208 67.56 ;
     RECT  35.104 72.72 40.208 72.744 ;
     RECT  35.104 83.76 40.208 84.168 ;
     RECT  39.697 129.792 40.208 130.2 ;
     RECT  38.675 142.176 40.208 142.2 ;
     RECT  37.933 143.424 40.208 144.6 ;
     RECT  39.733 146.448 40.208 151.08 ;
     RECT  40.208 1.392 40.312 22.536 ;
     RECT  40.208 66.768 40.312 84.252 ;
     RECT  40.208 129.588 40.312 151.08 ;
     RECT  40.312 2.418 40.504 21.48 ;
     RECT  40.312 66.768 40.504 84.168 ;
     RECT  40.312 129.858 40.504 151.08 ;
     RECT  40.504 11.424 40.643 11.448 ;
     RECT  40.504 146.496 40.883 151.08 ;
     RECT  40.504 129.936 41.893 130.2 ;
     RECT  41.893 129.936 42.077 130.776 ;
     RECT  40.504 7.056 42.133 7.224 ;
     RECT  40.504 8.304 42.133 9.048 ;
     RECT  40.883 146.496 42.217 149.4 ;
     RECT  40.883 150.432 42.217 151.08 ;
     RECT  42.077 130.032 42.293 130.776 ;
     RECT  42.217 146.496 42.293 151.08 ;
     RECT  42.293 146.736 42.761 151.08 ;
     RECT  42.761 147.024 42.797 151.08 ;
     RECT  42.797 147.264 42.803 151.08 ;
     RECT  42.803 147.264 43.379 150.504 ;
     RECT  42.293 130.032 43.877 130.296 ;
     RECT  40.504 3.072 43.949 3.864 ;
     RECT  40.504 143.424 44.341 144.6 ;
     RECT  44.341 143.424 44.453 144.888 ;
     RECT  43.379 147.264 44.917 150.456 ;
     RECT  44.917 147.072 45.299 150.456 ;
     RECT  45.493 150.48 45.529 150.504 ;
     RECT  40.312 1.392 45.608 1.416 ;
     RECT  43.949 3.6 45.608 3.864 ;
     RECT  40.504 4.896 45.608 5.784 ;
     RECT  42.133 7.056 45.608 9.048 ;
     RECT  40.504 10.08 45.608 10.104 ;
     RECT  40.504 14.496 45.608 14.52 ;
     RECT  40.504 19.632 45.608 19.656 ;
     RECT  40.504 21.456 45.608 21.48 ;
     RECT  40.312 22.464 45.608 22.536 ;
     RECT  40.504 66.768 45.608 67.56 ;
     RECT  40.504 72.72 45.608 72.744 ;
     RECT  40.504 83.76 45.608 84.168 ;
     RECT  43.877 130.224 45.608 130.296 ;
     RECT  40.504 142.176 45.608 142.2 ;
     RECT  44.453 143.424 45.608 144.6 ;
     RECT  45.299 147.072 45.608 149.4 ;
     RECT  45.529 150.48 45.637 150.6 ;
     RECT  45.608 1.392 45.712 22.536 ;
     RECT  45.608 66.768 45.712 84.252 ;
     RECT  45.608 129.588 45.712 149.4 ;
     RECT  45.637 150.48 45.733 151.032 ;
     RECT  45.712 2.418 45.904 21.48 ;
     RECT  45.712 66.768 45.904 84.168 ;
     RECT  45.712 129.858 45.904 149.4 ;
     RECT  45.904 147.072 45.971 149.4 ;
     RECT  45.904 6.816 46.019 9.048 ;
     RECT  45.971 147.072 46.019 148.872 ;
     RECT  45.733 150.48 46.285 151.08 ;
     RECT  45.904 143.424 46.433 144.6 ;
     RECT  46.285 149.904 46.933 151.08 ;
     RECT  46.433 143.424 47.009 144.072 ;
     RECT  46.981 71.136 47.027 71.16 ;
     RECT  46.019 147.504 47.123 148.872 ;
     RECT  47.123 148.752 47.185 148.872 ;
     RECT  46.933 149.856 47.185 151.08 ;
     RECT  47.185 148.752 47.261 151.08 ;
     RECT  47.261 148.8 47.297 151.08 ;
     RECT  47.297 148.8 47.315 150.504 ;
     RECT  45.904 130.224 47.317 130.296 ;
     RECT  47.317 130.224 47.363 130.584 ;
     RECT  47.363 130.464 47.369 130.584 ;
     RECT  47.123 147.504 47.869 147.768 ;
     RECT  45.904 66.768 48.017 67.56 ;
     RECT  47.315 149.328 48.325 150.504 ;
     RECT  47.869 147.456 48.341 147.768 ;
     RECT  48.341 147.456 48.409 147.672 ;
     RECT  48.325 149.328 48.413 151.08 ;
     RECT  39.161 23.76 48.449 65.256 ;
     RECT  46.019 7.056 48.467 9.048 ;
     RECT  48.409 147.072 48.659 147.672 ;
     RECT  45.904 3.6 48.665 3.864 ;
     RECT  47.369 130.464 48.665 130.488 ;
     RECT  45.904 142.176 48.665 142.2 ;
     RECT  47.009 143.424 48.737 143.448 ;
     RECT  45.904 10.08 49.093 10.104 ;
     RECT  48.659 147.12 49.235 147.672 ;
     RECT  48.413 149.328 49.331 150.792 ;
     RECT  45.904 4.896 49.385 5.784 ;
     RECT  49.331 149.328 49.453 149.4 ;
     RECT  48.665 3.696 49.457 3.864 ;
     RECT  49.525 145.92 50.149 145.944 ;
     RECT  49.331 150.48 50.389 150.792 ;
     RECT  49.235 147.648 50.425 147.672 ;
     RECT  49.453 148.8 50.425 149.4 ;
     RECT  50.389 150.48 50.867 151.08 ;
     RECT  48.985 130.224 50.893 130.248 ;
     RECT  50.425 147.648 50.965 149.4 ;
     RECT  45.712 1.392 51.008 1.416 ;
     RECT  49.457 3.84 51.008 3.864 ;
     RECT  49.385 5.328 51.008 5.784 ;
     RECT  48.467 7.488 51.008 9.048 ;
     RECT  49.093 10.08 51.008 11.016 ;
     RECT  45.904 14.496 51.008 14.52 ;
     RECT  45.904 19.632 51.008 19.656 ;
     RECT  45.904 21.456 51.008 21.48 ;
     RECT  45.712 22.464 51.008 22.536 ;
     RECT  48.017 66.768 51.008 67.128 ;
     RECT  47.027 71.139 51.008 71.157 ;
     RECT  45.904 72.72 51.008 72.744 ;
     RECT  45.904 83.76 51.008 84.168 ;
     RECT  50.893 130.224 51.008 130.344 ;
     RECT  50.149 145.872 51.008 145.944 ;
     RECT  50.965 147.648 51.008 149.928 ;
     RECT  50.867 151.056 51.059 151.08 ;
     RECT  51.008 1.392 51.112 22.536 ;
     RECT  51.008 66.768 51.112 84.252 ;
     RECT  51.008 129.588 51.112 149.928 ;
     RECT  51.112 129.858 51.251 149.928 ;
     RECT  51.112 2.418 51.304 21.48 ;
     RECT  51.112 66.768 51.304 84.168 ;
     RECT  51.251 129.858 51.304 148.782 ;
     RECT  51.251 149.904 51.347 149.928 ;
     RECT  51.304 66.768 52.445 67.032 ;
     RECT  51.304 7.488 52.477 9.048 ;
     RECT  51.304 10.08 52.477 11.016 ;
     RECT  52.477 7.488 53.075 11.016 ;
     RECT  53.075 10.08 53.453 11.016 ;
     RECT  51.304 130.32 53.633 130.344 ;
     RECT  53.075 7.488 54.101 9.048 ;
     RECT  54.101 8.736 54.533 9.048 ;
     RECT  52.445 66.816 55.037 67.032 ;
     RECT  54.101 7.488 55.573 7.752 ;
     RECT  54.533 9.024 55.573 9.048 ;
     RECT  51.304 71.139 55.861 71.157 ;
     RECT  51.112 1.392 56.408 1.416 ;
     RECT  51.304 3.84 56.408 3.864 ;
     RECT  51.304 5.328 56.408 5.784 ;
     RECT  55.573 7.488 56.408 9.048 ;
     RECT  53.453 10.992 56.408 11.016 ;
     RECT  51.304 14.496 56.408 14.52 ;
     RECT  51.304 19.632 56.408 19.656 ;
     RECT  51.304 21.456 56.408 21.48 ;
     RECT  51.112 22.464 56.408 22.536 ;
     RECT  55.037 67.008 56.408 67.032 ;
     RECT  55.861 71.136 56.408 71.16 ;
     RECT  51.304 72.72 56.408 72.744 ;
     RECT  51.304 83.664 56.408 84.168 ;
     RECT  56.408 1.392 56.512 22.536 ;
     RECT  56.408 66.948 56.512 84.252 ;
     RECT  56.408 129.588 56.512 149.052 ;
     RECT  56.512 2.418 56.704 21.48 ;
     RECT  56.512 67.008 56.704 84.168 ;
     RECT  56.512 129.858 56.704 148.782 ;
     RECT  56.704 84.144 57.733 84.168 ;
     RECT  56.704 67.008 58.705 67.032 ;
     RECT  58.705 67.008 58.745 67.128 ;
     RECT  38.045 128.496 60.473 128.568 ;
     RECT  57.877 130.176 60.901 130.2 ;
     RECT  56.512 1.392 61.808 1.416 ;
     RECT  56.704 3.84 61.808 3.864 ;
     RECT  56.704 5.328 61.808 5.784 ;
     RECT  56.704 7.488 61.808 7.752 ;
     RECT  56.704 8.784 61.808 8.808 ;
     RECT  56.704 10.992 61.808 11.016 ;
     RECT  56.704 14.496 61.808 14.52 ;
     RECT  56.704 19.632 61.808 19.656 ;
     RECT  56.704 21.456 61.808 21.48 ;
     RECT  56.512 22.464 61.808 22.536 ;
     RECT  58.745 67.104 61.808 67.128 ;
     RECT  56.704 71.139 61.808 71.157 ;
     RECT  56.704 72.72 61.808 72.744 ;
     RECT  57.733 84.048 61.808 84.168 ;
     RECT  60.901 130.176 61.808 130.248 ;
     RECT  61.808 1.392 61.912 22.536 ;
     RECT  61.808 66.948 61.912 84.252 ;
     RECT  61.808 129.588 61.912 149.052 ;
     RECT  61.912 2.418 62.104 21.48 ;
     RECT  61.912 67.008 62.104 84.168 ;
     RECT  61.912 129.858 62.104 148.782 ;
     RECT  62.104 67.008 62.741 67.128 ;
     RECT  62.104 7.488 63.385 7.752 ;
     RECT  62.104 21.456 64.177 21.48 ;
     RECT  64.177 21.12 64.403 21.48 ;
     RECT  64.403 21.456 64.433 21.48 ;
     RECT  62.741 67.008 64.537 67.032 ;
     RECT  64.537 67.008 64.595 67.224 ;
     RECT  60.473 128.496 65.225 128.52 ;
     RECT  62.104 130.224 65.225 130.248 ;
     RECT  61.912 1.392 67.208 1.416 ;
     RECT  62.104 3.84 67.208 3.864 ;
     RECT  62.104 5.328 67.208 5.784 ;
     RECT  63.385 7.344 67.208 7.752 ;
     RECT  62.104 8.784 67.208 8.808 ;
     RECT  62.104 10.992 67.208 11.016 ;
     RECT  62.104 14.496 67.208 14.52 ;
     RECT  62.104 19.632 67.208 19.656 ;
     RECT  61.912 22.464 67.208 22.536 ;
     RECT  64.595 67.008 67.208 67.032 ;
     RECT  64.549 69.552 67.208 69.576 ;
     RECT  62.104 71.139 67.208 71.157 ;
     RECT  62.104 72.72 67.208 72.744 ;
     RECT  62.104 84.048 67.208 84.168 ;
     RECT  65.293 130.272 67.208 130.296 ;
     RECT  67.208 1.392 67.312 22.536 ;
     RECT  67.208 66.948 67.312 84.252 ;
     RECT  67.208 129.588 67.312 149.052 ;
     RECT  67.312 2.418 67.504 21.342 ;
     RECT  67.312 67.008 67.504 84.168 ;
     RECT  67.312 129.858 67.504 148.782 ;
     RECT  67.504 72.72 68.429 72.744 ;
     RECT  67.504 71.139 70.585 71.157 ;
     RECT  70.585 71.139 70.643 71.256 ;
     RECT  70.369 72.384 70.643 72.408 ;
     RECT  70.643 71.139 70.729 71.16 ;
     RECT  70.729 71.136 70.769 71.16 ;
     RECT  67.504 84.048 72.373 84.168 ;
     RECT  67.312 1.392 72.608 1.416 ;
     RECT  67.504 3.84 72.608 3.864 ;
     RECT  67.504 5.328 72.608 5.784 ;
     RECT  67.504 7.344 72.608 7.752 ;
     RECT  67.504 8.784 72.608 8.808 ;
     RECT  67.504 10.992 72.608 11.016 ;
     RECT  67.504 14.496 72.608 14.52 ;
     RECT  67.504 19.632 72.608 19.656 ;
     RECT  67.312 22.464 72.608 22.536 ;
     RECT  67.504 67.008 72.608 67.032 ;
     RECT  67.504 69.696 72.608 69.72 ;
     RECT  72.373 83.76 72.608 84.168 ;
     RECT  67.504 130.176 72.608 130.2 ;
     RECT  72.608 1.392 72.712 22.536 ;
     RECT  72.608 66.948 72.712 84.252 ;
     RECT  72.608 129.588 72.712 149.052 ;
     RECT  72.712 67.008 72.785 84.168 ;
     RECT  72.712 2.418 72.904 21.342 ;
     RECT  72.785 67.008 72.904 84.072 ;
     RECT  72.712 129.858 72.904 148.782 ;
     RECT  72.712 1.392 78.008 1.416 ;
     RECT  72.904 3.84 78.008 3.864 ;
     RECT  72.904 5.328 78.008 5.784 ;
     RECT  72.904 7.056 78.008 7.752 ;
     RECT  72.904 8.784 78.008 8.808 ;
     RECT  72.904 10.992 78.008 11.016 ;
     RECT  72.904 14.496 78.008 14.52 ;
     RECT  72.904 19.632 78.008 19.656 ;
     RECT  72.712 22.464 78.008 22.536 ;
     RECT  72.904 67.008 78.008 67.032 ;
     RECT  72.904 69.696 78.008 69.72 ;
     RECT  72.904 84.048 78.008 84.072 ;
     RECT  72.904 130.176 78.008 130.2 ;
     RECT  78.008 1.392 78.112 22.536 ;
     RECT  78.008 66.948 78.112 84.252 ;
     RECT  78.008 129.588 78.112 149.052 ;
     RECT  78.112 2.418 78.304 21.342 ;
     RECT  78.112 67.008 78.304 84.072 ;
     RECT  78.112 129.858 78.304 148.782 ;
     RECT  78.304 5.328 80.809 5.784 ;
     RECT  78.304 130.176 81.385 130.2 ;
     RECT  81.385 130.176 81.709 130.488 ;
     RECT  81.709 130.176 81.749 130.536 ;
     RECT  78.304 3.84 82.597 3.864 ;
     RECT  80.809 5.328 82.597 6.024 ;
     RECT  82.597 3.84 83.185 6.024 ;
     RECT  78.304 7.056 83.185 7.752 ;
     RECT  78.112 1.392 83.408 1.416 ;
     RECT  83.185 3.84 83.408 7.752 ;
     RECT  78.304 8.784 83.408 8.808 ;
     RECT  78.304 10.992 83.408 11.016 ;
     RECT  78.304 14.496 83.408 14.52 ;
     RECT  78.304 19.632 83.408 19.656 ;
     RECT  78.112 22.464 83.408 22.536 ;
     RECT  78.304 67.008 83.408 67.032 ;
     RECT  78.304 69.696 83.408 69.72 ;
     RECT  78.304 84.048 83.408 84.072 ;
     RECT  81.749 130.464 83.408 130.536 ;
     RECT  83.408 1.392 83.512 22.536 ;
     RECT  83.408 66.948 83.512 84.252 ;
     RECT  83.408 129.588 83.512 149.052 ;
     RECT  83.512 2.418 83.704 21.342 ;
     RECT  83.512 67.008 83.704 84.072 ;
     RECT  83.512 129.858 83.704 148.782 ;
     RECT  83.704 130.464 84.733 130.536 ;
     RECT  84.733 130.176 84.773 130.536 ;
     RECT  83.704 67.008 86.641 67.032 ;
     RECT  86.641 67.008 86.681 67.128 ;
     RECT  83.704 3.84 87.509 7.752 ;
     RECT  83.512 1.392 88.808 1.416 ;
     RECT  87.509 4.464 88.808 7.752 ;
     RECT  83.704 8.784 88.808 8.808 ;
     RECT  83.704 10.992 88.808 11.016 ;
     RECT  83.704 14.496 88.808 14.52 ;
     RECT  83.704 19.632 88.808 19.656 ;
     RECT  83.512 22.464 88.808 22.536 ;
     RECT  86.681 67.104 88.808 67.128 ;
     RECT  83.704 69.696 88.808 69.72 ;
     RECT  83.704 84.048 88.808 84.072 ;
     RECT  84.773 130.176 88.808 130.488 ;
     RECT  88.808 1.392 88.912 22.536 ;
     RECT  88.808 66.948 88.912 84.252 ;
     RECT  88.808 129.588 88.912 149.052 ;
     RECT  88.912 2.418 89.104 21.342 ;
     RECT  88.912 67.104 89.104 84.072 ;
     RECT  88.912 129.858 89.104 148.782 ;
     RECT  89.104 4.464 89.219 7.752 ;
     RECT  89.104 2.832 89.315 3.192 ;
     RECT  89.104 67.104 90.029 67.128 ;
     RECT  89.219 4.656 90.529 7.752 ;
     RECT  89.315 3.168 90.637 3.192 ;
     RECT  90.637 3.072 90.677 3.192 ;
     RECT  89.104 130.176 90.677 130.488 ;
     RECT  88.912 22.464 93.845 22.536 ;
     RECT  88.912 1.392 94.208 1.416 ;
     RECT  90.677 3.072 94.208 3.096 ;
     RECT  90.529 4.368 94.208 7.752 ;
     RECT  89.104 8.784 94.208 9.384 ;
     RECT  89.104 10.992 94.208 11.016 ;
     RECT  89.104 14.496 94.208 14.52 ;
     RECT  89.104 19.632 94.208 19.656 ;
     RECT  93.845 22.464 94.208 22.488 ;
     RECT  91.537 67.104 94.208 67.128 ;
     RECT  89.104 69.696 94.208 69.72 ;
     RECT  89.104 84.048 94.208 84.072 ;
     RECT  90.677 130.32 94.208 130.488 ;
     RECT  94.208 1.392 94.312 22.488 ;
     RECT  94.208 66.948 94.312 84.252 ;
     RECT  94.208 129.588 94.312 149.052 ;
     RECT  94.312 2.418 94.504 21.342 ;
     RECT  94.312 67.008 94.504 84.072 ;
     RECT  94.312 129.858 94.504 148.782 ;
     RECT  94.504 67.008 94.637 67.128 ;
     RECT  94.504 3.072 95.285 3.336 ;
     RECT  94.504 130.32 95.497 130.488 ;
     RECT  95.285 3.312 95.605 3.336 ;
     RECT  94.504 4.368 95.605 7.752 ;
     RECT  95.605 3.312 96.853 7.752 ;
     RECT  96.853 3.024 98.345 7.752 ;
     RECT  94.312 22.464 99.137 22.488 ;
     RECT  94.312 1.392 99.608 1.416 ;
     RECT  98.345 3.024 99.608 3.336 ;
     RECT  98.345 4.896 99.608 7.752 ;
     RECT  94.504 8.784 99.608 9.384 ;
     RECT  94.504 10.992 99.608 11.016 ;
     RECT  94.504 14.496 99.608 14.52 ;
     RECT  94.504 19.632 99.608 19.656 ;
     RECT  94.637 67.008 99.608 67.032 ;
     RECT  94.504 69.696 99.608 69.72 ;
     RECT  94.504 84.048 99.608 84.072 ;
     RECT  95.497 130.224 99.608 130.488 ;
     RECT  99.608 1.392 99.712 21.612 ;
     RECT  99.608 66.948 99.712 84.252 ;
     RECT  99.608 129.588 99.712 149.052 ;
     RECT  99.712 2.418 99.904 21.342 ;
     RECT  99.712 67.008 99.904 83.982 ;
     RECT  99.712 129.858 99.904 148.782 ;
     RECT  99.904 2.832 100.721 7.752 ;
     RECT  100.721 2.832 100.883 4.152 ;
     RECT  99.904 130.224 101.293 130.488 ;
     RECT  100.883 2.832 101.873 3.048 ;
     RECT  99.712 1.392 101.989 1.416 ;
     RECT  101.873 2.832 101.989 2.904 ;
     RECT  101.989 1.392 102.035 2.904 ;
     RECT  101.293 130.08 102.409 130.488 ;
     RECT  100.721 5.184 102.469 7.752 ;
     RECT  99.904 8.784 102.469 9.816 ;
     RECT  102.469 5.184 102.629 9.816 ;
     RECT  102.035 1.392 102.845 2.856 ;
     RECT  100.883 4.128 103.489 4.152 ;
     RECT  102.409 129.936 103.597 130.488 ;
     RECT  103.597 129.888 103.669 130.488 ;
     RECT  103.669 129.888 103.715 130.584 ;
     RECT  103.489 3.408 104.245 4.152 ;
     RECT  102.629 5.184 104.245 6.024 ;
     RECT  102.845 1.392 104.569 2.28 ;
     RECT  104.245 3.408 104.821 6.024 ;
     RECT  102.629 7.488 104.821 9.816 ;
     RECT  104.569 1.392 105.008 2.328 ;
     RECT  104.821 3.408 105.008 9.816 ;
     RECT  99.904 10.992 105.008 11.016 ;
     RECT  99.904 14.496 105.008 14.52 ;
     RECT  99.904 67.008 105.008 67.032 ;
     RECT  99.904 69.696 105.008 69.72 ;
     RECT  100.933 84.048 105.008 84.072 ;
     RECT  103.715 129.936 105.008 130.584 ;
     RECT  105.008 1.392 105.112 21.612 ;
     RECT  105.008 66.948 105.112 84.252 ;
     RECT  105.008 129.588 105.112 149.052 ;
     RECT  105.112 1.392 105.304 21.342 ;
     RECT  105.112 67.008 105.304 84.072 ;
     RECT  105.112 129.858 105.304 148.782 ;
     RECT  105.304 129.936 105.443 130.584 ;
     RECT  105.443 130.032 105.617 130.584 ;
     RECT  105.617 130.08 106.157 130.584 ;
     RECT  106.157 130.08 106.553 130.488 ;
     RECT  105.304 4.128 106.585 9.816 ;
     RECT  105.304 10.992 106.585 11.016 ;
     RECT  105.304 67.008 106.585 67.032 ;
     RECT  106.553 130.08 106.621 130.344 ;
     RECT  106.585 67.008 106.625 67.128 ;
     RECT  106.585 4.128 106.841 11.016 ;
     RECT  105.304 1.392 107.417 2.856 ;
     RECT  106.621 130.032 107.557 130.344 ;
     RECT  37.397 86.4 107.593 127.464 ;
     RECT  101.977 128.496 107.593 128.52 ;
     RECT  107.593 86.4 107.629 128.52 ;
     RECT  107.557 129.888 108.029 130.344 ;
     RECT  106.841 4.656 108.317 11.016 ;
     RECT  107.629 86.4 108.493 128.568 ;
     RECT  106.625 67.104 108.601 67.128 ;
     RECT  108.601 67.104 108.781 67.368 ;
     RECT  108.781 66.384 108.817 67.368 ;
     RECT  107.417 1.392 108.853 2.664 ;
     RECT  108.613 3.648 108.853 3.672 ;
     RECT  108.029 129.936 109.033 130.344 ;
     RECT  108.997 0.096 109.093 0.12 ;
     RECT  109.093 0.096 109.189 0.168 ;
     RECT  109.285 22.464 109.381 22.488 ;
     RECT  109.189 0.096 109.669 0.36 ;
     RECT  109.381 21.888 109.669 22.488 ;
     RECT  108.853 1.392 109.681 3.672 ;
     RECT  109.669 0.096 109.717 0.408 ;
     RECT  109.681 1.392 109.717 4.008 ;
     RECT  108.317 5.328 109.717 11.016 ;
     RECT  108.493 86.4 109.861 128.712 ;
     RECT  109.033 129.696 109.861 130.344 ;
     RECT  108.817 66.384 110.185 67.416 ;
     RECT  109.861 86.4 110.221 130.344 ;
     RECT  105.304 69.696 110.293 69.72 ;
     RECT  109.717 0.096 110.408 11.016 ;
     RECT  105.304 14.496 110.408 14.52 ;
     RECT  105.304 18.432 110.408 18.456 ;
     RECT  109.669 21.888 110.408 22.68 ;
     RECT  110.185 66.384 110.408 67.608 ;
     RECT  110.293 69.696 110.408 69.864 ;
     RECT  105.304 84.048 110.408 84.072 ;
     RECT  110.221 86.4 110.408 130.536 ;
     RECT  110.408 66.384 110.512 84.252 ;
     RECT  110.408 86.4 110.512 149.052 ;
     RECT  110.408 0.096 110.621 22.68 ;
     RECT  110.621 0.144 110.704 22.68 ;
     RECT  110.512 66.384 110.704 84.072 ;
     RECT  110.512 86.4 110.704 148.782 ;
     RECT  110.704 86.4 110.821 130.536 ;
     RECT  110.704 14.496 111.053 14.52 ;
     RECT  110.704 0.144 111.685 11.016 ;
     RECT  111.685 0.096 112.595 11.016 ;
     RECT  112.595 0.144 112.691 11.016 ;
     RECT  112.691 0.192 112.849 11.016 ;
     RECT  112.849 0.192 112.921 11.16 ;
     RECT  113.533 82.8 113.605 82.824 ;
     RECT  110.704 84.048 113.605 84.072 ;
     RECT  112.921 0.192 113.893 11.208 ;
     RECT  110.704 21.888 114.181 22.68 ;
     RECT  113.893 0.096 114.805 11.208 ;
     RECT  114.181 21.888 114.805 22.728 ;
     RECT  48.449 23.76 114.805 64.824 ;
     RECT  114.805 0.096 114.851 11.496 ;
     RECT  114.865 19.632 114.949 19.656 ;
     RECT  112.309 20.64 114.949 20.664 ;
     RECT  114.949 19.632 115.093 20.664 ;
     RECT  114.805 21.888 115.093 64.824 ;
     RECT  114.851 0.096 115.229 0.36 ;
     RECT  110.704 69.696 115.261 69.864 ;
     RECT  110.704 66.384 115.369 67.608 ;
     RECT  113.605 82.8 115.441 84.072 ;
     RECT  114.851 1.392 115.669 11.496 ;
     RECT  115.669 1.392 115.808 11.544 ;
     RECT  115.585 13.104 115.808 13.128 ;
     RECT  114.805 14.784 115.808 14.808 ;
     RECT  110.704 18.432 115.808 18.456 ;
     RECT  115.093 19.632 115.808 64.824 ;
     RECT  115.369 66.384 115.808 68.52 ;
     RECT  115.261 69.696 115.808 70.296 ;
     RECT  115.441 82.704 115.808 84.072 ;
     RECT  110.821 85.728 115.808 130.536 ;
     RECT  115.808 66.384 115.912 84.252 ;
     RECT  115.808 85.728 115.912 149.052 ;
     RECT  115.808 1.392 116.104 64.824 ;
     RECT  115.912 66.384 116.104 84.072 ;
     RECT  115.912 85.728 116.104 148.782 ;
     RECT  116.104 17.856 116.243 64.824 ;
     RECT  115.229 0.144 116.291 0.36 ;
     RECT  116.291 0.192 116.485 0.36 ;
     RECT  116.104 1.392 116.485 16.488 ;
     RECT  116.485 0.192 116.531 16.488 ;
     RECT  116.104 69.504 116.915 70.296 ;
     RECT  116.915 69.504 116.921 69.96 ;
     RECT  116.531 16.464 117.157 16.488 ;
     RECT  116.104 82.704 117.601 82.968 ;
     RECT  116.531 0.192 117.683 15.288 ;
     RECT  116.243 19.632 117.745 64.824 ;
     RECT  117.601 82.416 117.745 82.968 ;
     RECT  116.104 84.048 117.745 84.072 ;
     RECT  117.683 1.392 117.817 15.288 ;
     RECT  117.157 16.464 117.817 16.68 ;
     RECT  117.683 0.192 117.925 0.36 ;
     RECT  117.925 0.096 118.037 0.36 ;
     RECT  116.104 66.384 118.105 68.52 ;
     RECT  116.921 69.696 118.105 69.96 ;
     RECT  117.745 82.416 118.249 84.072 ;
     RECT  116.243 18.432 118.979 18.456 ;
     RECT  118.037 0.192 119.077 0.36 ;
     RECT  118.969 80.544 119.113 80.568 ;
     RECT  117.817 1.392 119.149 16.68 ;
     RECT  119.149 1.392 119.269 17.112 ;
     RECT  117.745 19.632 119.365 65.256 ;
     RECT  119.113 80.544 119.509 80.952 ;
     RECT  118.249 82.416 119.509 84.648 ;
     RECT  118.825 75.12 119.797 75.144 ;
     RECT  119.509 80.544 119.797 84.648 ;
     RECT  119.269 1.392 120.013 18.024 ;
     RECT  119.365 19.392 120.013 65.256 ;
     RECT  118.105 66.384 120.229 69.96 ;
     RECT  119.473 72.816 120.265 72.84 ;
     RECT  119.797 75.12 120.445 75.528 ;
     RECT  120.517 78.096 120.589 78.12 ;
     RECT  120.589 77.952 120.661 78.12 ;
     RECT  120.445 75.12 120.733 76.296 ;
     RECT  120.733 75.12 120.805 76.776 ;
     RECT  120.661 77.952 120.805 78.648 ;
     RECT  120.805 75.12 120.877 78.648 ;
     RECT  120.877 74.688 120.901 78.648 ;
     RECT  120.229 66.384 120.985 70.296 ;
     RECT  120.013 71.28 120.985 71.304 ;
     RECT  120.985 66.384 121.208 71.304 ;
     RECT  120.265 72.768 121.208 72.84 ;
     RECT  120.901 74.064 121.208 78.648 ;
     RECT  119.797 80.112 121.208 84.648 ;
     RECT  116.104 85.728 121.208 130.536 ;
     RECT  119.077 0.096 121.285 0.36 ;
     RECT  120.013 1.392 121.285 65.256 ;
     RECT  121.208 85.728 121.312 149.052 ;
     RECT  121.208 66.384 121.504 84.648 ;
     RECT  121.312 85.728 121.504 148.782 ;
     RECT  121.285 0.096 121.565 65.256 ;
     RECT  121.565 0.096 122.573 0.36 ;
     RECT  121.504 66.384 122.605 72.84 ;
     RECT  121.504 75.12 122.749 84.648 ;
     RECT  121.504 85.728 122.749 130.536 ;
     RECT  121.565 1.392 122.832 65.256 ;
     RECT  122.749 75.12 122.832 130.536 ;
     RECT  122.832 64.896 123.041 65.256 ;
     RECT  122.832 75.12 123.149 126.36 ;
     RECT  122.605 66.384 123.155 73.272 ;
     RECT  122.832 127.92 123.251 130.536 ;
     RECT  123.251 129.744 123.347 130.536 ;
     RECT  123.149 75.12 123.365 99.288 ;
     RECT  123.347 129.744 123.395 130.248 ;
     RECT  122.573 0.144 123.683 0.36 ;
     RECT  123.155 66.816 123.685 73.272 ;
     RECT  123.365 84.96 123.725 99.288 ;
     RECT  123.685 66.816 123.731 73.512 ;
     RECT  123.731 66.816 123.761 72.984 ;
     RECT  123.683 0.144 123.779 0.312 ;
     RECT  123.365 75.12 123.829 83.832 ;
     RECT  123.761 66.96 123.869 72.984 ;
     RECT  123.779 0.144 123.875 0.264 ;
     RECT  123.829 74.64 123.971 83.832 ;
     RECT  123.875 0.144 123.973 0.216 ;
     RECT  122.832 1.392 124.013 63.72 ;
     RECT  124.013 16.8 124.115 63.72 ;
     RECT  124.115 19.392 124.157 63.72 ;
     RECT  123.869 66.96 124.259 72.888 ;
     RECT  124.157 26.208 124.301 63.72 ;
     RECT  123.971 75.12 124.301 83.832 ;
     RECT  124.301 75.12 124.307 83.64 ;
     RECT  124.259 67.056 124.355 72.888 ;
     RECT  123.973 0.096 124.373 0.216 ;
     RECT  123.395 129.984 124.451 130.248 ;
     RECT  123.725 86.112 124.481 99.288 ;
     RECT  124.481 89.568 124.517 99.288 ;
     RECT  124.481 86.112 124.547 88.488 ;
     RECT  124.355 67.056 124.643 72.84 ;
     RECT  124.157 19.392 124.691 25.128 ;
     RECT  124.517 89.952 124.697 99.288 ;
     RECT  124.691 19.392 124.769 24.024 ;
     RECT  123.251 127.92 124.835 128.76 ;
     RECT  124.547 86.64 124.877 88.488 ;
     RECT  124.115 16.8 124.883 18.36 ;
     RECT  124.373 0.192 124.933 0.216 ;
     RECT  124.697 89.952 125.021 99.192 ;
     RECT  124.933 0.192 125.075 0.312 ;
     RECT  124.307 75.36 125.075 83.64 ;
     RECT  124.691 25.008 125.129 25.128 ;
     RECT  124.877 86.64 125.129 88.44 ;
     RECT  123.725 84.96 125.161 84.984 ;
     RECT  125.129 86.688 125.165 88.44 ;
     RECT  123.149 100.416 125.165 126.36 ;
     RECT  125.165 86.688 125.201 87.864 ;
     RECT  125.165 100.608 125.201 126.264 ;
     RECT  125.075 0.192 125.219 0.216 ;
     RECT  125.161 84.912 125.219 85.32 ;
     RECT  125.021 89.952 125.219 93.48 ;
     RECT  124.013 1.392 125.233 15.816 ;
     RECT  124.883 16.8 125.233 18.168 ;
     RECT  124.769 19.392 125.233 23.976 ;
     RECT  125.219 91.776 125.237 93.48 ;
     RECT  125.201 100.608 125.237 126.072 ;
     RECT  125.201 86.928 125.273 87.864 ;
     RECT  125.237 91.776 125.273 92.184 ;
     RECT  125.237 100.608 125.273 125.976 ;
     RECT  124.301 26.208 125.345 63.624 ;
     RECT  125.273 100.608 125.345 125.784 ;
     RECT  125.345 41.808 125.381 63.528 ;
     RECT  125.345 100.608 125.381 113.784 ;
     RECT  125.345 114.816 125.381 125.784 ;
     RECT  125.345 26.208 125.417 40.296 ;
     RECT  125.381 41.808 125.417 44.232 ;
     RECT  125.381 45.648 125.417 49.992 ;
     RECT  125.381 51.408 125.417 52.104 ;
     RECT  125.381 55.44 125.417 56.472 ;
     RECT  125.381 57.936 125.417 58.728 ;
     RECT  125.381 59.76 125.417 61.128 ;
     RECT  125.381 62.256 125.417 63.528 ;
     RECT  125.381 100.608 125.417 113.4 ;
     RECT  125.381 114.912 125.417 114.936 ;
     RECT  125.381 116.064 125.417 118.584 ;
     RECT  125.381 119.616 125.417 123.672 ;
     RECT  125.381 124.704 125.417 125.784 ;
     RECT  125.417 43.728 125.453 43.752 ;
     RECT  125.417 52.08 125.453 52.104 ;
     RECT  125.021 94.464 125.453 99.192 ;
     RECT  125.417 100.8 125.453 108.792 ;
     RECT  125.417 117.6 125.453 118.584 ;
     RECT  125.233 1.392 125.459 18.168 ;
     RECT  125.417 56.448 125.459 56.472 ;
     RECT  125.417 58.032 125.489 58.056 ;
     RECT  125.273 91.776 125.489 92.088 ;
     RECT  125.417 124.8 125.489 124.824 ;
     RECT  124.643 67.056 125.507 72.024 ;
     RECT  125.219 89.952 125.525 90.552 ;
     RECT  125.417 62.256 125.561 62.28 ;
     RECT  125.453 100.8 125.561 103.8 ;
     RECT  125.453 104.832 125.561 108.216 ;
     RECT  125.417 109.824 125.561 110.424 ;
     RECT  125.417 111.744 125.561 112.152 ;
     RECT  125.417 113.376 125.561 113.4 ;
     RECT  125.453 117.984 125.561 118.584 ;
     RECT  125.417 119.616 125.561 119.64 ;
     RECT  125.417 120.768 125.561 120.792 ;
     RECT  125.417 121.824 125.561 123.48 ;
     RECT  125.417 38.544 125.597 39.24 ;
     RECT  125.453 94.848 125.597 99.192 ;
     RECT  125.561 102.624 125.597 103.8 ;
     RECT  125.561 105.888 125.597 108.216 ;
     RECT  125.561 111.744 125.597 111.768 ;
     RECT  125.561 117.984 125.597 118.008 ;
     RECT  125.561 123.456 125.597 123.48 ;
     RECT  125.417 26.208 125.603 37.56 ;
     RECT  125.597 105.888 125.633 105.912 ;
     RECT  125.237 93.312 126.277 93.48 ;
     RECT  126.325 0.144 126.373 0.168 ;
     RECT  125.459 18.144 126.385 18.168 ;
     RECT  125.233 19.248 126.385 23.976 ;
     RECT  125.129 25.008 126.385 25.032 ;
     RECT  126.277 93.312 126.469 93.768 ;
     RECT  125.597 94.848 126.469 98.472 ;
     RECT  126.373 0.144 126.515 0.36 ;
     RECT  125.459 1.392 126.608 16.824 ;
     RECT  126.385 18.144 126.608 18.264 ;
     RECT  126.385 19.248 126.608 25.032 ;
     RECT  125.603 26.208 126.608 36.552 ;
     RECT  125.603 37.536 126.608 37.56 ;
     RECT  125.597 39.216 126.608 39.24 ;
     RECT  125.417 49.248 126.608 49.272 ;
     RECT  123.041 65.232 126.608 65.256 ;
     RECT  125.507 67.056 126.608 70.776 ;
     RECT  125.507 72 126.608 72.024 ;
     RECT  125.701 74.304 126.608 74.328 ;
     RECT  125.075 75.36 126.608 81.336 ;
     RECT  125.075 82.704 126.608 83.64 ;
     RECT  125.219 84.912 126.608 85.128 ;
     RECT  125.273 87.84 126.608 87.864 ;
     RECT  125.525 90 126.608 90.552 ;
     RECT  125.489 92.064 126.608 92.088 ;
     RECT  126.469 93.312 126.608 98.472 ;
     RECT  125.597 102.624 126.608 103.608 ;
     RECT  125.561 104.832 126.608 104.856 ;
     RECT  125.561 110.4 126.608 110.424 ;
     RECT  124.835 127.92 126.608 127.944 ;
     RECT  124.451 129.984 126.608 130.008 ;
     RECT  126.608 1.392 126.712 149.052 ;
     RECT  126.712 1.392 126.904 148.782 ;
     RECT  126.904 1.392 126.965 23.928 ;
     RECT  126.904 68.928 127.043 69.816 ;
     RECT  126.904 129.984 127.043 130.008 ;
     RECT  126.904 26.256 127.091 36.552 ;
     RECT  126.904 72 127.091 72.024 ;
     RECT  126.904 91.776 127.091 98.472 ;
     RECT  126.904 67.056 127.109 67.848 ;
     RECT  126.965 13.68 127.139 23.928 ;
     RECT  127.139 18.768 127.145 23.928 ;
     RECT  127.091 26.352 127.181 36.552 ;
     RECT  127.181 28.416 127.187 36.552 ;
     RECT  127.145 19.008 127.217 23.928 ;
     RECT  127.109 67.824 127.235 67.848 ;
     RECT  127.181 26.352 127.283 27.336 ;
     RECT  126.904 75.936 127.283 76.536 ;
     RECT  127.217 22.8 127.325 23.928 ;
     RECT  127.139 13.68 127.361 17.688 ;
     RECT  126.904 82.704 127.427 83.64 ;
     RECT  127.283 26.544 127.469 27.336 ;
     RECT  127.325 22.8 127.475 23.832 ;
     RECT  127.217 19.008 127.523 21.672 ;
     RECT  127.427 82.8 127.523 83.64 ;
     RECT  127.475 23.568 127.571 23.832 ;
     RECT  127.469 26.544 127.571 26.568 ;
     RECT  127.283 76.464 127.619 76.536 ;
     RECT  126.904 89.904 127.649 90.072 ;
     RECT  127.649 89.904 127.667 89.928 ;
     RECT  127.361 14.688 127.763 17.688 ;
     RECT  127.187 29.232 127.763 36.552 ;
     RECT  126.904 87.84 127.811 88.344 ;
     RECT  126.904 77.568 127.859 79.464 ;
     RECT  127.091 92.928 127.901 98.472 ;
     RECT  127.763 16.608 127.907 17.688 ;
     RECT  127.523 83.328 127.907 83.64 ;
     RECT  127.091 91.776 127.955 91.8 ;
     RECT  126.965 1.392 127.969 12.552 ;
     RECT  127.361 13.68 127.969 13.704 ;
     RECT  127.907 17.088 128.003 17.688 ;
     RECT  127.571 23.616 128.003 23.832 ;
     RECT  127.043 69.168 128.003 69.816 ;
     RECT  127.969 1.392 128.009 13.704 ;
     RECT  127.763 14.688 128.009 14.952 ;
     RECT  128.009 14.688 128.099 14.808 ;
     RECT  128.099 14.784 128.195 14.808 ;
     RECT  128.113 66.864 128.245 66.888 ;
     RECT  128.245 66.864 128.257 67.272 ;
     RECT  127.901 92.928 128.261 98.376 ;
     RECT  126.904 41.28 128.297 41.304 ;
     RECT  128.261 92.928 128.297 98.232 ;
     RECT  128.257 66.72 128.387 67.272 ;
     RECT  127.859 78.48 128.435 79.464 ;
     RECT  127.763 34.176 128.483 36.552 ;
     RECT  128.387 67.248 128.531 67.272 ;
     RECT  128.483 34.224 128.617 36.552 ;
     RECT  128.245 64.272 128.653 64.296 ;
     RECT  128.009 1.392 128.675 13.272 ;
     RECT  128.435 79.008 128.723 79.464 ;
     RECT  128.653 63.84 128.819 64.296 ;
     RECT  128.675 1.392 128.867 13.08 ;
     RECT  126.904 127.92 128.867 127.944 ;
     RECT  128.867 13.056 128.873 13.08 ;
     RECT  128.833 40.752 128.915 40.776 ;
     RECT  128.723 79.008 128.963 79.032 ;
     RECT  128.821 22.752 128.981 22.776 ;
     RECT  127.619 76.464 129.011 76.488 ;
     RECT  128.869 43.584 129.013 43.608 ;
     RECT  128.617 34.224 129.059 36.936 ;
     RECT  127.763 29.232 129.155 33.144 ;
     RECT  129.059 34.512 129.197 36.936 ;
     RECT  128.867 1.392 129.251 12.072 ;
     RECT  128.297 92.928 129.265 97.272 ;
     RECT  129.265 92.016 129.299 97.272 ;
     RECT  128.003 17.376 129.347 17.688 ;
     RECT  129.155 29.232 129.349 32.328 ;
     RECT  129.253 26.784 129.395 26.808 ;
     RECT  129.253 90.624 129.395 90.648 ;
     RECT  129.299 92.016 129.395 92.04 ;
     RECT  129.299 93.36 129.395 97.272 ;
     RECT  126.904 49.248 129.397 49.272 ;
     RECT  129.397 48.432 129.443 49.608 ;
     RECT  127.907 83.616 129.443 83.64 ;
     RECT  129.409 91.776 129.491 91.8 ;
     RECT  129.349 28.992 129.539 32.328 ;
     RECT  129.013 43.584 129.539 43.896 ;
     RECT  129.443 48.432 129.539 48.456 ;
     RECT  129.197 34.8 129.587 36.936 ;
     RECT  129.397 46.752 129.587 46.776 ;
     RECT  129.443 49.488 129.587 49.608 ;
     RECT  129.395 93.504 129.593 97.272 ;
     RECT  128.819 64.272 129.683 64.296 ;
     RECT  129.625 90.576 129.683 90.6 ;
     RECT  129.593 93.504 129.683 95.208 ;
     RECT  127.811 88.32 129.697 88.344 ;
     RECT  126.904 81.168 129.731 81.192 ;
     RECT  129.697 88.32 129.733 88.584 ;
     RECT  129.661 14.256 129.779 14.28 ;
     RECT  129.733 87.744 129.779 88.584 ;
     RECT  129.683 94.08 129.827 95.208 ;
     RECT  129.587 34.944 129.829 36.936 ;
     RECT  129.769 27.936 129.875 27.96 ;
     RECT  128.485 71.808 129.917 71.832 ;
     RECT  129.877 14.784 129.923 14.808 ;
     RECT  129.517 22.8 129.923 22.824 ;
     RECT  129.841 52.56 129.923 52.584 ;
     RECT  129.877 56.64 129.925 56.664 ;
     RECT  129.539 28.992 129.949 32.088 ;
     RECT  129.949 28.512 129.953 32.088 ;
     RECT  126.904 74.304 129.973 74.328 ;
     RECT  127.523 19.008 129.989 20.328 ;
     RECT  129.973 73.488 130.019 74.328 ;
     RECT  130.019 73.488 130.025 73.512 ;
     RECT  129.827 94.416 130.061 95.208 ;
     RECT  130.057 27.36 130.115 27.384 ;
     RECT  130.061 94.944 130.133 95.208 ;
     RECT  130.165 72.96 130.211 72.984 ;
     RECT  130.093 15.408 130.309 15.432 ;
     RECT  129.949 25.728 130.309 25.752 ;
     RECT  130.309 15.408 130.355 15.96 ;
     RECT  130.309 25.728 130.355 26.232 ;
     RECT  129.779 87.744 130.421 87.768 ;
     RECT  129.925 56.64 130.529 56.76 ;
     RECT  126.904 85.104 130.547 85.128 ;
     RECT  129.989 20.304 130.565 20.328 ;
     RECT  130.133 94.944 130.565 95.112 ;
     RECT  129.769 90.048 130.595 90.072 ;
     RECT  129.953 30.24 130.597 32.088 ;
     RECT  130.529 56.688 130.643 56.76 ;
     RECT  128.003 69.792 130.643 69.816 ;
     RECT  129.593 96.192 130.673 97.272 ;
     RECT  130.355 15.408 130.691 15.432 ;
     RECT  129.829 34.944 130.709 37.56 ;
     RECT  130.525 87.216 130.883 87.24 ;
     RECT  128.003 23.808 130.885 23.832 ;
     RECT  129.953 28.512 130.921 29.256 ;
     RECT  130.597 30.24 130.921 32.184 ;
     RECT  130.885 23.52 130.925 23.832 ;
     RECT  130.921 28.512 131.029 32.184 ;
     RECT  127.523 21.408 131.077 21.672 ;
     RECT  129.349 0.096 131.219 0.12 ;
     RECT  129.989 19.008 131.365 19.272 ;
     RECT  130.789 27.312 131.461 27.336 ;
     RECT  129.347 17.376 131.569 17.64 ;
     RECT  131.365 18.768 131.569 19.272 ;
     RECT  129.251 1.392 131.605 12.024 ;
     RECT  131.281 24.528 131.605 24.552 ;
     RECT  130.355 25.728 131.605 25.848 ;
     RECT  131.569 17.376 131.749 19.272 ;
     RECT  131.701 13.776 131.797 14.136 ;
     RECT  131.077 21.408 131.797 22.056 ;
     RECT  131.797 13.776 131.893 14.232 ;
     RECT  131.461 27.312 131.965 27.384 ;
     RECT  131.029 28.464 131.965 32.184 ;
     RECT  131.605 1.392 132.008 12.552 ;
     RECT  131.893 13.68 132.008 14.232 ;
     RECT  131.713 15.984 132.008 16.008 ;
     RECT  131.749 17.376 132.008 19.896 ;
     RECT  131.797 21.12 132.008 22.056 ;
     RECT  130.925 23.52 132.008 23.544 ;
     RECT  131.605 24.528 132.008 25.848 ;
     RECT  131.965 27.312 132.008 32.184 ;
     RECT  130.709 34.944 132.008 37.08 ;
     RECT  129.539 43.584 132.008 43.608 ;
     RECT  129.587 49.488 132.008 49.512 ;
     RECT  130.643 56.736 132.008 56.76 ;
     RECT  129.637 60 132.008 60.024 ;
     RECT  130.565 94.944 132.008 94.968 ;
     RECT  130.673 96.192 132.008 96.888 ;
     RECT  132.008 1.392 132.112 149.052 ;
     RECT  132.112 1.392 132.304 148.782 ;
     RECT  132.229 0.144 132.419 0.168 ;
     RECT  132.304 12.768 132.419 13.704 ;
     RECT  132.304 94.944 132.467 94.968 ;
     RECT  132.304 19.008 132.473 19.896 ;
     RECT  132.304 1.392 132.563 11.736 ;
     RECT  132.419 13.056 132.563 13.704 ;
     RECT  132.473 19.008 132.563 19.416 ;
     RECT  132.304 36.912 132.611 37.08 ;
     RECT  132.304 29.712 132.659 32.376 ;
     RECT  132.659 29.712 132.707 30.36 ;
     RECT  132.563 13.68 132.755 13.704 ;
     RECT  132.304 96.192 132.761 96.216 ;
     RECT  132.659 31.344 132.803 32.376 ;
     RECT  132.709 0.096 132.869 0.12 ;
     RECT  132.563 1.392 132.941 10.152 ;
     RECT  132.563 19.008 132.995 19.272 ;
     RECT  132.304 27.648 133.049 27.672 ;
     RECT  132.563 11.52 133.187 11.736 ;
     RECT  132.941 1.392 133.283 10.056 ;
     RECT  133.283 1.392 133.379 9.96 ;
     RECT  132.304 14.832 133.379 14.856 ;
     RECT  132.803 31.344 133.379 31.992 ;
     RECT  132.707 29.712 133.409 30.216 ;
     RECT  132.304 22.032 133.445 22.056 ;
     RECT  133.409 30.192 133.625 30.216 ;
     RECT  133.379 31.488 133.661 31.992 ;
     RECT  132.995 19.008 133.715 19.032 ;
     RECT  132.304 15.984 133.763 17.4 ;
     RECT  133.763 15.984 133.811 17.112 ;
     RECT  132.611 36.912 133.877 36.936 ;
     RECT  133.811 17.088 133.907 17.112 ;
     RECT  133.873 12.528 133.955 12.552 ;
     RECT  133.187 11.52 134.051 11.544 ;
     RECT  133.811 15.984 134.195 16.008 ;
     RECT  132.304 60 134.237 60.024 ;
     RECT  133.379 1.392 134.291 9.912 ;
     RECT  134.291 1.392 134.309 8.712 ;
     RECT  132.304 43.584 134.309 43.608 ;
     RECT  134.377 59.856 134.435 59.88 ;
     RECT  133.861 0.096 134.453 0.12 ;
     RECT  132.304 49.488 134.453 49.512 ;
     RECT  134.521 22.8 134.723 22.824 ;
     RECT  133.661 31.488 134.737 31.848 ;
     RECT  134.309 1.392 134.771 8.568 ;
     RECT  134.771 1.392 134.813 7.368 ;
     RECT  134.737 31.344 134.819 31.848 ;
     RECT  134.819 31.824 134.921 31.848 ;
     RECT  134.701 26.208 134.963 26.232 ;
     RECT  134.813 1.392 135.011 6.312 ;
     RECT  135.011 1.392 135.059 6.168 ;
     RECT  134.089 19.392 135.059 19.416 ;
     RECT  134.291 9.888 135.107 9.912 ;
     RECT  135.059 2.256 135.137 6.168 ;
     RECT  135.137 2.256 135.173 4.68 ;
     RECT  135.173 2.256 135.209 3.432 ;
     RECT  135.173 4.512 135.245 4.68 ;
     RECT  134.771 8.544 135.245 8.568 ;
     RECT  135.245 4.56 135.281 4.68 ;
     RECT  135.209 2.256 135.395 2.856 ;
     RECT  135.281 4.56 135.395 4.632 ;
     RECT  135.395 4.56 135.635 4.584 ;
     RECT  135.395 2.256 135.641 2.712 ;
     RECT  135.641 2.688 135.713 2.712 ;
     RECT  137.408 2.148 137.512 149.052 ;
     RECT  137.512 2.418 137.704 148.782 ;
     RECT  142.808 2.148 142.912 149.052 ;
     RECT  142.912 2.418 143.104 148.782 ;
     RECT  148.208 2.148 148.312 149.052 ;
     RECT  148.312 2.418 148.504 148.782 ;
    LAYER M5 ;
     RECT  109.008 0.016 135.048 0.131 ;
     RECT  109.104 0.131 135.048 0.179 ;
     RECT  109.2 0.179 135.048 0.371 ;
     RECT  2.4 2.137 2.52 2.151 ;
     RECT  34.8 2.137 34.92 2.151 ;
     RECT  40.2 2.137 40.32 2.151 ;
     RECT  45.6 2.137 45.72 2.151 ;
     RECT  51 2.137 51.12 2.151 ;
     RECT  56.4 2.137 56.52 2.151 ;
     RECT  61.8 2.137 61.92 2.151 ;
     RECT  67.2 2.137 67.32 2.151 ;
     RECT  72.6 2.137 72.72 2.151 ;
     RECT  78 2.137 78.12 2.151 ;
     RECT  83.4 2.137 83.52 2.151 ;
     RECT  88.8 2.137 88.92 2.151 ;
     RECT  94.2 2.137 94.32 2.151 ;
     RECT  99.6 2.137 99.72 2.151 ;
     RECT  105 2.137 105.12 2.151 ;
     RECT  137.4 2.137 137.52 2.151 ;
     RECT  142.8 2.137 142.92 2.151 ;
     RECT  148.2 2.137 148.32 2.151 ;
     RECT  40.2 2.151 40.512 2.197 ;
     RECT  6.864 0.016 32.136 2.245 ;
     RECT  109.296 0.371 135.048 2.245 ;
     RECT  6.768 2.245 32.136 2.677 ;
     RECT  88.8 2.151 89.112 2.821 ;
     RECT  6.624 2.677 32.136 2.915 ;
     RECT  102 2.197 102.024 2.915 ;
     RECT  39.216 2.197 40.512 3.107 ;
     RECT  88.8 2.821 89.304 3.203 ;
     RECT  99.6 2.151 99.912 3.397 ;
     RECT  6.624 2.915 19.224 3.539 ;
     RECT  108.624 2.245 135.624 3.683 ;
     RECT  96.864 3.013 96.888 3.925 ;
     RECT  105 2.151 105.312 3.925 ;
     RECT  99.6 3.397 100.872 4.163 ;
     RECT  20.352 2.915 32.136 4.261 ;
     RECT  34.8 2.151 35.112 4.501 ;
     RECT  83.4 2.151 83.712 4.501 ;
     RECT  96.864 3.925 97.512 4.501 ;
     RECT  6.672 3.539 19.224 4.595 ;
     RECT  96.864 4.501 97.992 4.595 ;
     RECT  109.296 3.683 135.624 4.595 ;
     RECT  6.768 4.595 19.224 4.643 ;
     RECT  109.296 4.595 135.384 4.643 ;
     RECT  104.4 3.925 105.312 4.691 ;
     RECT  6.816 4.643 19.224 4.787 ;
     RECT  97.488 4.595 97.992 4.931 ;
     RECT  99.6 4.163 100.536 5.173 ;
     RECT  34.704 4.501 35.112 5.267 ;
     RECT  39.84 3.107 40.512 5.267 ;
     RECT  97.968 4.931 97.992 5.315 ;
     RECT  99.6 5.173 100.632 5.315 ;
     RECT  72.6 2.151 72.912 5.461 ;
     RECT  82.608 4.501 83.712 5.507 ;
     RECT  7.056 4.787 19.224 5.605 ;
     RECT  20.304 4.261 32.136 5.605 ;
     RECT  105 4.691 105.312 5.653 ;
     RECT  91.152 4.645 91.176 5.747 ;
     RECT  106.704 4.261 106.728 5.891 ;
     RECT  45.6 2.151 45.912 6.805 ;
     RECT  104.832 5.653 105.312 6.851 ;
     RECT  7.056 5.605 32.136 7.139 ;
     RECT  40.2 5.267 40.512 7.189 ;
     RECT  72.6 5.461 73.32 7.379 ;
     RECT  33.456 5.653 33.48 7.475 ;
     RECT  48.432 3.685 48.456 7.475 ;
     RECT  42.144 5.077 42.168 7.523 ;
     RECT  45.6 6.805 46.008 7.763 ;
     RECT  56.4 2.151 56.712 7.957 ;
     RECT  7.344 7.139 32.136 8.051 ;
     RECT  102.48 6.805 102.504 8.051 ;
     RECT  7.344 8.051 14.904 8.099 ;
     RECT  55.584 7.957 56.712 8.819 ;
     RECT  14.496 8.099 14.904 9.155 ;
     RECT  14.496 9.155 14.52 9.203 ;
     RECT  88.8 3.203 89.208 9.395 ;
     RECT  109.296 4.643 135.096 9.539 ;
     RECT  105 6.851 105.312 9.637 ;
     RECT  99.6 5.315 100.536 9.827 ;
     RECT  112.32 9.539 135.096 9.923 ;
     RECT  53.04 8.485 53.064 10.019 ;
     RECT  15.888 8.051 32.136 10.261 ;
     RECT  112.32 9.923 135.048 10.403 ;
     RECT  109.296 9.539 111.288 10.979 ;
     RECT  49.104 7.909 49.128 11.027 ;
     RECT  113.904 10.403 135.048 11.027 ;
     RECT  40.2 7.189 40.632 11.459 ;
     RECT  15.648 10.261 32.136 14.483 ;
     RECT  14.544 14.005 14.568 16.595 ;
     RECT  114.192 11.027 135.048 17.123 ;
     RECT  119.232 17.123 135.048 17.411 ;
     RECT  7.344 8.099 13.512 17.605 ;
     RECT  16.08 14.483 32.136 18.037 ;
     RECT  114.192 17.123 118.248 18.421 ;
     RECT  119.232 17.411 133.704 18.421 ;
     RECT  105 9.637 105.432 18.467 ;
     RECT  114.192 18.421 133.704 19.043 ;
     RECT  114.192 19.043 132.984 19.283 ;
     RECT  15.984 18.037 32.136 19.427 ;
     RECT  114.192 19.283 132.696 19.427 ;
     RECT  134.688 17.411 135.048 19.427 ;
     RECT  112.32 10.403 112.344 20.675 ;
     RECT  64.368 7.381 64.392 21.155 ;
     RECT  114.192 19.427 120.216 21.155 ;
     RECT  117.312 21.155 120.216 21.203 ;
     RECT  114.192 21.155 116.28 21.299 ;
     RECT  117.312 21.203 118.248 21.971 ;
     RECT  16.08 19.427 32.136 22.451 ;
     RECT  109.296 10.979 110.712 22.499 ;
     RECT  16.08 22.451 31.944 22.595 ;
     RECT  16.08 22.595 31.752 22.691 ;
     RECT  109.68 22.499 110.712 22.691 ;
     RECT  16.08 22.691 31.56 22.739 ;
     RECT  114.192 21.299 116.112 22.739 ;
     RECT  118.128 21.971 118.248 22.787 ;
     RECT  134.688 19.427 134.952 22.835 ;
     RECT  119.232 21.203 120.216 22.883 ;
     RECT  119.232 22.883 119.544 22.931 ;
     RECT  31.44 22.739 31.56 22.979 ;
     RECT  16.08 22.739 30.408 23.027 ;
     RECT  114.816 22.739 116.112 23.075 ;
     RECT  115.056 23.075 116.112 23.123 ;
     RECT  118.128 22.787 118.152 23.171 ;
     RECT  119.472 22.931 119.544 23.219 ;
     RECT  31.536 22.979 31.56 23.267 ;
     RECT  16.08 23.027 30.312 23.363 ;
     RECT  119.472 23.219 119.496 23.363 ;
     RECT  16.08 23.363 29.712 23.603 ;
     RECT  16.08 23.603 28.296 23.651 ;
     RECT  121.2 19.427 132.696 23.651 ;
     RECT  16.08 23.651 28.2 23.699 ;
     RECT  122.544 23.651 132.696 23.699 ;
     RECT  16.08 23.699 28.056 24.419 ;
     RECT  16.08 24.419 28.008 24.515 ;
     RECT  134.784 22.835 134.952 26.243 ;
     RECT  7.344 17.605 13.608 27.301 ;
     RECT  16.08 24.515 27.912 28.405 ;
     RECT  15.936 28.405 27.912 29.221 ;
     RECT  122.688 23.699 132.696 30.181 ;
     RECT  122.688 30.181 133.368 31.379 ;
     RECT  134.784 26.243 134.808 31.379 ;
     RECT  122.688 31.379 132.6 32.341 ;
     RECT  7.344 27.301 13.848 32.725 ;
     RECT  15.36 29.221 27.912 33.061 ;
     RECT  7.344 32.725 14.136 33.589 ;
     RECT  15.36 33.061 28.008 33.589 ;
     RECT  7.344 33.589 28.008 34.115 ;
     RECT  7.344 34.115 27.912 36.085 ;
     RECT  7.344 36.085 28.008 36.275 ;
     RECT  122.688 32.341 132.792 36.563 ;
     RECT  132 36.563 132.792 36.947 ;
     RECT  132 36.947 132.6 37.091 ;
     RECT  7.344 36.275 27.912 40.261 ;
     RECT  7.344 40.261 27.96 40.837 ;
     RECT  7.344 40.837 28.008 41.027 ;
     RECT  7.344 41.027 27.912 44.677 ;
     RECT  7.344 44.677 27.96 48.853 ;
     RECT  7.344 48.853 28.008 49.043 ;
     RECT  7.344 49.043 27.912 53.557 ;
     RECT  7.344 53.557 27.96 53.699 ;
     RECT  134.4 31.813 134.424 59.891 ;
     RECT  7.344 53.699 27.912 60.085 ;
     RECT  7.344 60.085 28.008 61.379 ;
     RECT  7.344 61.379 27.912 64.405 ;
     RECT  7.344 64.405 27.96 64.453 ;
     RECT  7.344 64.453 28.056 64.739 ;
     RECT  16.944 64.739 28.056 64.885 ;
     RECT  122.688 36.563 130.872 64.931 ;
     RECT  16.944 64.885 28.152 64.933 ;
     RECT  16.944 64.933 28.344 66.275 ;
     RECT  118.56 66.853 118.584 66.995 ;
     RECT  110.4 22.691 110.712 67.045 ;
     RECT  110.4 67.045 110.856 67.237 ;
     RECT  122.784 64.931 130.872 67.381 ;
     RECT  46.992 67.381 47.016 67.427 ;
     RECT  115.8 23.123 116.112 69.493 ;
     RECT  64.56 67.189 64.584 69.587 ;
     RECT  110.304 67.237 110.856 69.875 ;
     RECT  115.8 69.493 116.904 70.307 ;
     RECT  46.995 67.427 47.013 71.125 ;
     RECT  56.4 8.819 56.712 71.125 ;
     RECT  46.992 71.125 47.016 71.171 ;
     RECT  70.608 71.221 70.632 71.267 ;
     RECT  70.611 71.267 70.629 72.373 ;
     RECT  70.608 72.373 70.632 72.419 ;
     RECT  5.376 73.477 5.4 73.523 ;
     RECT  121.2 23.651 121.512 74.053 ;
     RECT  120.912 74.053 121.512 74.723 ;
     RECT  17.04 66.275 28.344 76.261 ;
     RECT  29.4 23.603 29.712 76.261 ;
     RECT  121.104 74.723 121.512 76.645 ;
     RECT  122.544 67.381 130.872 76.645 ;
     RECT  5.379 73.523 5.397 76.933 ;
     RECT  5.376 76.933 5.4 76.979 ;
     RECT  121.104 76.645 130.872 77.315 ;
     RECT  121.104 77.315 125.112 77.413 ;
     RECT  17.04 76.261 29.712 78.083 ;
     RECT  120.816 77.413 125.112 78.131 ;
     RECT  3.84 72.709 3.864 78.469 ;
     RECT  29.232 78.083 29.712 78.997 ;
     RECT  0.288 79.621 0.312 79.717 ;
     RECT  17.04 78.083 28.2 79.765 ;
     RECT  29.232 78.997 30.456 79.765 ;
     RECT  17.04 79.765 30.456 79.955 ;
     RECT  121.104 78.131 125.112 80.291 ;
     RECT  126.096 77.315 130.872 80.435 ;
     RECT  3.84 78.469 4.824 80.627 ;
     RECT  0.24 79.717 0.312 80.677 ;
     RECT  4.8 80.627 4.824 80.725 ;
     RECT  4.8 80.725 5.16 80.867 ;
     RECT  17.04 79.955 29.712 80.867 ;
     RECT  0.24 80.677 0.36 80.869 ;
     RECT  5.136 80.867 5.16 80.963 ;
     RECT  0.192 80.869 0.36 81.061 ;
     RECT  0.144 81.061 0.36 81.107 ;
     RECT  0.144 81.107 0.312 81.299 ;
     RECT  0.144 81.299 0.264 81.539 ;
     RECT  29.28 80.867 29.712 81.683 ;
     RECT  17.04 80.867 28.2 82.021 ;
     RECT  0.144 81.539 0.216 82.115 ;
     RECT  119.856 81.445 119.88 82.115 ;
     RECT  121.104 80.291 125.064 82.115 ;
     RECT  0.144 82.115 0.168 82.211 ;
     RECT  121.104 82.115 125.016 82.837 ;
     RECT  55.872 71.125 56.712 83.699 ;
     RECT  72.6 7.379 72.912 83.749 ;
     RECT  120.192 82.837 125.016 83.843 ;
     RECT  121.2 83.843 125.016 83.939 ;
     RECT  120.192 83.843 120.216 84.083 ;
     RECT  72.384 83.749 72.912 84.179 ;
     RECT  122.544 83.939 125.016 85.285 ;
     RECT  110.4 69.875 110.856 85.763 ;
     RECT  17.04 82.021 28.296 86.339 ;
     RECT  17.04 86.339 28.056 86.627 ;
     RECT  122.544 85.285 125.208 86.917 ;
     RECT  126.288 80.435 130.872 87.251 ;
     RECT  17.04 86.627 27.912 87.925 ;
     RECT  17.04 87.925 28.008 88.115 ;
     RECT  7.344 64.739 15.96 88.117 ;
     RECT  17.04 88.115 27.912 88.117 ;
     RECT  7.344 88.117 27.912 89.173 ;
     RECT  122.544 86.917 125.256 90.083 ;
     RECT  126.288 87.251 130.584 90.083 ;
     RECT  7.344 89.173 28.008 90.227 ;
     RECT  122.544 90.083 125.208 93.251 ;
     RECT  126.288 90.083 129.816 93.539 ;
     RECT  126.384 93.539 129.816 94.307 ;
     RECT  132 37.091 132.456 94.979 ;
     RECT  126.384 94.307 127.752 95.219 ;
     RECT  128.784 94.307 129.384 95.557 ;
     RECT  128.592 95.557 129.384 95.651 ;
     RECT  126.384 95.219 127.128 95.795 ;
     RECT  128.592 95.651 129.144 95.795 ;
     RECT  128.592 95.795 128.856 96.181 ;
     RECT  126.6 95.795 127.128 96.467 ;
     RECT  7.344 90.227 27.912 96.565 ;
     RECT  130.416 94.981 130.44 96.947 ;
     RECT  6.24 95.077 6.264 97.045 ;
     RECT  7.344 96.565 28.008 97.045 ;
     RECT  128.208 96.181 128.856 97.523 ;
     RECT  6.24 97.045 28.008 97.859 ;
     RECT  126.6 96.467 127.08 98.147 ;
     RECT  6.24 97.859 27.912 98.869 ;
     RECT  6.24 98.869 27.96 99.157 ;
     RECT  6.24 99.157 28.008 99.443 ;
     RECT  6.24 99.443 27.96 100.067 ;
     RECT  6.24 100.067 27.912 107.173 ;
     RECT  6.24 107.173 27.96 108.949 ;
     RECT  6.24 108.949 28.008 109.427 ;
     RECT  6.24 109.427 27.96 112.787 ;
     RECT  6.24 112.787 27.912 112.979 ;
     RECT  6.24 112.979 27.864 114.949 ;
     RECT  6.24 114.949 27.912 115.381 ;
     RECT  6.24 115.381 28.056 115.571 ;
     RECT  6.24 115.571 28.008 115.811 ;
     RECT  6.24 115.811 27.96 116.965 ;
     RECT  6.24 116.965 28.008 117.251 ;
     RECT  6.24 117.251 27.912 121.669 ;
     RECT  6.24 121.669 27.96 122.867 ;
     RECT  6.24 122.867 27.912 125.267 ;
     RECT  6.24 125.267 27.864 126.997 ;
     RECT  6.24 126.997 27.912 127.141 ;
     RECT  6.24 127.141 27.96 127.285 ;
     RECT  6.24 127.285 28.056 127.525 ;
     RECT  29.4 81.683 29.712 127.525 ;
     RECT  6.24 127.525 29.712 127.669 ;
     RECT  128.832 97.523 128.856 127.955 ;
     RECT  31.92 127.813 31.944 128.197 ;
     RECT  6.24 127.669 30.024 128.293 ;
     RECT  6.24 128.293 30.84 128.389 ;
     RECT  31.92 128.197 32.52 128.389 ;
     RECT  33.696 128.053 33.72 128.437 ;
     RECT  34.8 5.267 35.112 128.581 ;
     RECT  122.544 93.251 124.824 128.723 ;
     RECT  124.416 128.723 124.824 128.771 ;
     RECT  34.8 128.581 35.352 129.061 ;
     RECT  34.8 129.061 35.4 129.205 ;
     RECT  6.24 128.389 32.52 129.683 ;
     RECT  33.648 128.437 33.72 129.683 ;
     RECT  122.544 128.723 123.384 129.779 ;
     RECT  105 18.467 105.312 129.925 ;
     RECT  122.544 129.779 123.336 129.971 ;
     RECT  126.6 98.147 127.032 130.019 ;
     RECT  124.416 128.771 124.44 130.259 ;
     RECT  122.784 129.971 123.336 130.307 ;
     RECT  123.312 130.307 123.336 130.547 ;
     RECT  34.8 129.205 35.928 130.595 ;
     RECT  47.328 130.213 47.352 130.595 ;
     RECT  103.68 129.877 103.704 130.595 ;
     RECT  105 129.925 105.432 130.595 ;
     RECT  33.696 129.683 33.72 130.691 ;
     RECT  34.8 130.595 35.4 130.739 ;
     RECT  6.24 129.683 31.944 130.883 ;
     RECT  31.344 130.883 31.944 131.221 ;
     RECT  31.344 131.221 32.04 131.651 ;
     RECT  6.24 130.883 29.928 131.795 ;
     RECT  34.8 130.739 35.112 134.293 ;
     RECT  34.8 134.293 35.832 134.531 ;
     RECT  33.744 134.293 33.768 134.773 ;
     RECT  34.8 134.531 35.112 134.773 ;
     RECT  31.632 131.651 32.04 135.349 ;
     RECT  31.44 135.349 32.04 135.925 ;
     RECT  33.744 134.773 35.112 137.029 ;
     RECT  31.44 135.925 32.136 137.221 ;
     RECT  6.24 131.795 29.832 137.651 ;
     RECT  9.408 137.651 29.832 138.083 ;
     RECT  1.392 138.997 1.416 139.045 ;
     RECT  33.456 137.029 35.112 139.381 ;
     RECT  1.296 139.045 1.416 141.925 ;
     RECT  38.448 141.925 38.472 142.261 ;
     RECT  1.2 141.925 1.416 142.453 ;
     RECT  9.408 138.083 29.712 142.741 ;
     RECT  6.24 137.651 8.112 143.123 ;
     RECT  2.4 2.151 2.712 144.757 ;
     RECT  6.24 143.123 6.264 144.757 ;
     RECT  7.344 143.123 8.112 144.757 ;
     RECT  51 2.151 51.312 145.861 ;
     RECT  31.344 137.221 32.136 146.149 ;
     RECT  33.36 139.381 35.112 146.245 ;
     RECT  6.24 144.757 8.112 146.291 ;
     RECT  0.72 142.453 1.416 146.293 ;
     RECT  2.4 144.757 3.144 146.293 ;
     RECT  33.36 146.245 35.256 146.389 ;
     RECT  6.576 146.291 8.112 146.677 ;
     RECT  9.408 142.741 30.216 146.677 ;
     RECT  6.576 146.677 30.216 147.061 ;
     RECT  31.248 146.149 32.136 147.061 ;
     RECT  38.448 142.261 38.664 147.061 ;
     RECT  45.6 7.763 45.912 147.061 ;
     RECT  48.624 147.061 48.648 147.109 ;
     RECT  50.16 145.861 51.312 147.109 ;
     RECT  40.2 11.459 40.512 147.205 ;
     RECT  0.72 146.293 3.144 147.397 ;
     RECT  45.6 147.061 46.008 147.493 ;
     RECT  4.752 146.437 4.776 147.589 ;
     RECT  6.576 147.061 32.136 147.589 ;
     RECT  44.88 147.493 46.008 147.635 ;
     RECT  0.72 147.397 3.336 147.637 ;
     RECT  38.448 147.061 38.76 147.685 ;
     RECT  36.48 147.541 36.504 147.877 ;
     RECT  0.72 147.637 3.72 147.925 ;
     RECT  4.752 147.589 32.136 147.925 ;
     RECT  36.48 147.877 36.552 148.019 ;
     RECT  40.2 147.205 41.064 148.165 ;
     RECT  45.072 147.635 46.008 148.213 ;
     RECT  47.376 147.685 47.4 148.213 ;
     RECT  0.72 147.925 32.136 148.357 ;
     RECT  33.36 146.389 35.304 148.357 ;
     RECT  38.448 147.685 38.904 148.405 ;
     RECT  38.352 148.405 38.904 148.501 ;
     RECT  40.08 148.165 41.064 148.501 ;
     RECT  36.528 148.019 36.552 148.549 ;
     RECT  38.352 148.501 41.064 148.549 ;
     RECT  42.192 147.637 42.216 148.549 ;
     RECT  36.528 148.549 36.936 148.693 ;
     RECT  38.352 148.549 42.216 148.789 ;
     RECT  43.632 148.213 43.656 148.789 ;
     RECT  45.072 148.213 47.4 148.789 ;
     RECT  56.4 83.699 56.712 149.049 ;
     RECT  61.8 2.151 62.112 149.049 ;
     RECT  67.2 2.151 67.512 149.049 ;
     RECT  72.6 84.179 72.912 149.049 ;
     RECT  78 2.151 78.312 149.049 ;
     RECT  83.4 5.507 83.712 149.049 ;
     RECT  88.8 9.395 89.112 149.049 ;
     RECT  94.2 2.151 94.512 149.049 ;
     RECT  99.6 9.827 99.912 149.049 ;
     RECT  105 130.595 105.312 149.049 ;
     RECT  110.4 85.763 110.712 149.049 ;
     RECT  115.8 70.307 116.112 149.049 ;
     RECT  121.2 83.939 121.512 149.049 ;
     RECT  126.6 130.019 126.912 149.049 ;
     RECT  132 94.979 132.312 149.049 ;
     RECT  137.4 2.151 137.712 149.049 ;
     RECT  142.8 2.151 143.112 149.049 ;
     RECT  148.2 2.151 148.512 149.049 ;
     RECT  56.4 149.049 56.52 149.063 ;
     RECT  61.8 149.049 61.92 149.063 ;
     RECT  67.2 149.049 67.32 149.063 ;
     RECT  72.6 149.049 72.72 149.063 ;
     RECT  78 149.049 78.12 149.063 ;
     RECT  83.4 149.049 83.52 149.063 ;
     RECT  88.8 149.049 88.92 149.063 ;
     RECT  94.2 149.049 94.32 149.063 ;
     RECT  99.6 149.049 99.72 149.063 ;
     RECT  105 149.049 105.12 149.063 ;
     RECT  110.4 149.049 110.52 149.063 ;
     RECT  115.8 149.049 115.92 149.063 ;
     RECT  121.2 149.049 121.32 149.063 ;
     RECT  126.6 149.049 126.72 149.063 ;
     RECT  132 149.049 132.12 149.063 ;
     RECT  137.4 149.049 137.52 149.063 ;
     RECT  142.8 149.049 142.92 149.063 ;
     RECT  148.2 149.049 148.32 149.063 ;
     RECT  36.528 148.693 37.032 149.317 ;
     RECT  38.352 148.789 47.4 149.317 ;
     RECT  48.624 147.109 51.312 149.317 ;
     RECT  0.72 148.357 35.304 149.893 ;
     RECT  36.528 149.317 51.312 149.893 ;
     RECT  0.72 149.893 51.336 151.184 ;
  END
END ot_nhb_pbst
END LIBRARY
